VERSION 5.8 ;
BUSBITCHARS "[]" ;
DIVIDERCHAR "/" ;
UNITS
    DATABASE MICRONS 1000 ;
END UNITS

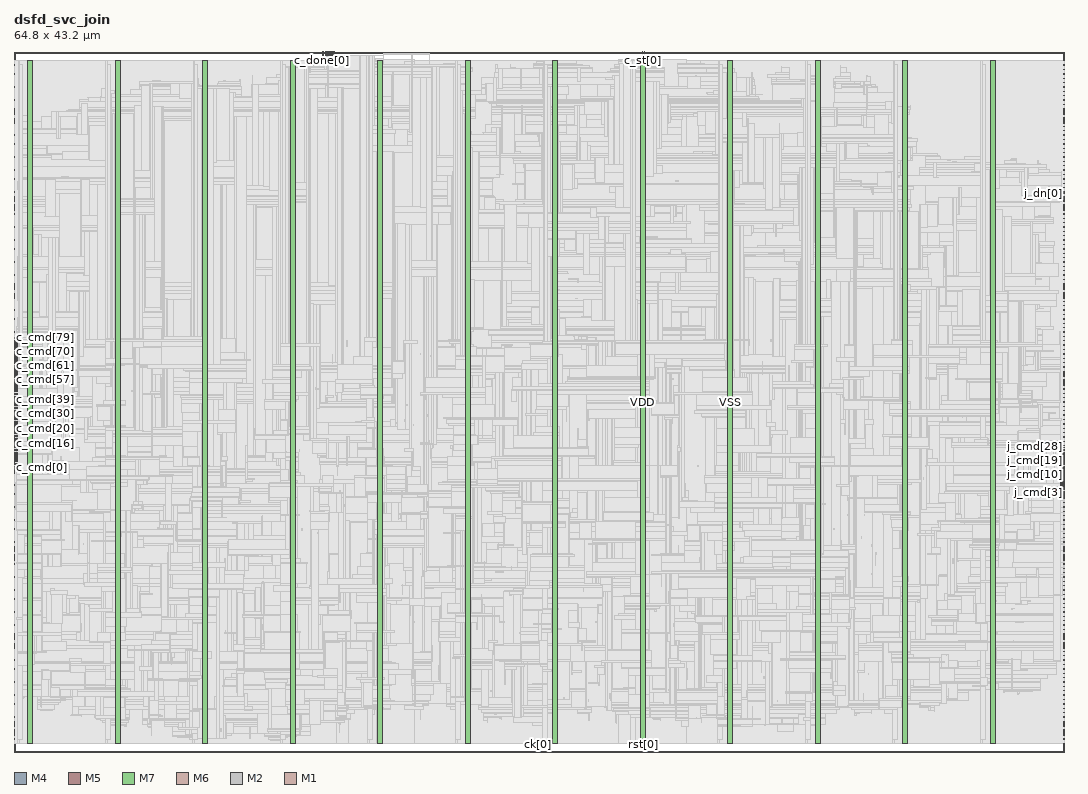
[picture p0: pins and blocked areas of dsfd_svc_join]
MACRO dsfd_svc_join
  FOREIGN dsfd_svc_join 0 0 ;
  CLASS BLOCK ;
  SIZE 64.8 BY 43.2 ;
  PIN c_cmd[0]
    DIRECTION INPUT ;
    USE SIGNAL ;
    PORT
      LAYER M4 ;
        RECT  0 17.52 0.192 17.544 ;
    END
  END c_cmd[0]
  PIN c_cmd[10]
    DIRECTION INPUT ;
    USE SIGNAL ;
    PORT
      LAYER M4 ;
        RECT  0 18.48 0.192 18.504 ;
    END
  END c_cmd[10]
  PIN c_cmd[11]
    DIRECTION INPUT ;
    USE SIGNAL ;
    PORT
      LAYER M4 ;
        RECT  0 18.576 0.192 18.6 ;
    END
  END c_cmd[11]
  PIN c_cmd[12]
    DIRECTION INPUT ;
    USE SIGNAL ;
    PORT
      LAYER M4 ;
        RECT  0 18.672 0.192 18.696 ;
    END
  END c_cmd[12]
  PIN c_cmd[13]
    DIRECTION INPUT ;
    USE SIGNAL ;
    PORT
      LAYER M4 ;
        RECT  0 18.768 0.192 18.792 ;
    END
  END c_cmd[13]
  PIN c_cmd[14]
    DIRECTION INPUT ;
    USE SIGNAL ;
    PORT
      LAYER M4 ;
        RECT  0 18.864 0.192 18.888 ;
    END
  END c_cmd[14]
  PIN c_cmd[15]
    DIRECTION INPUT ;
    USE SIGNAL ;
    PORT
      LAYER M4 ;
        RECT  0 18.96 0.192 18.984 ;
    END
  END c_cmd[15]
  PIN c_cmd[16]
    DIRECTION INPUT ;
    USE SIGNAL ;
    PORT
      LAYER M4 ;
        RECT  0 19.056 0.192 19.08 ;
    END
  END c_cmd[16]
  PIN c_cmd[17]
    DIRECTION INPUT ;
    USE SIGNAL ;
    PORT
      LAYER M4 ;
        RECT  0 19.152 0.192 19.176 ;
    END
  END c_cmd[17]
  PIN c_cmd[18]
    DIRECTION INPUT ;
    USE SIGNAL ;
    PORT
      LAYER M4 ;
        RECT  0 19.248 0.192 19.272 ;
    END
  END c_cmd[18]
  PIN c_cmd[19]
    DIRECTION INPUT ;
    USE SIGNAL ;
    PORT
      LAYER M4 ;
        RECT  0 19.344 0.192 19.368 ;
    END
  END c_cmd[19]
  PIN c_cmd[1]
    DIRECTION INPUT ;
    USE SIGNAL ;
    PORT
      LAYER M4 ;
        RECT  0 17.616 0.192 17.64 ;
    END
  END c_cmd[1]
  PIN c_cmd[20]
    DIRECTION INPUT ;
    USE SIGNAL ;
    PORT
      LAYER M4 ;
        RECT  0 19.44 0.192 19.464 ;
    END
  END c_cmd[20]
  PIN c_cmd[21]
    DIRECTION INPUT ;
    USE SIGNAL ;
    PORT
      LAYER M4 ;
        RECT  0 19.536 0.192 19.56 ;
    END
  END c_cmd[21]
  PIN c_cmd[22]
    DIRECTION INPUT ;
    USE SIGNAL ;
    PORT
      LAYER M4 ;
        RECT  0 19.632 0.192 19.656 ;
    END
  END c_cmd[22]
  PIN c_cmd[23]
    DIRECTION INPUT ;
    USE SIGNAL ;
    PORT
      LAYER M4 ;
        RECT  0 19.728 0.192 19.752 ;
    END
  END c_cmd[23]
  PIN c_cmd[24]
    DIRECTION INPUT ;
    USE SIGNAL ;
    PORT
      LAYER M4 ;
        RECT  0 19.824 0.192 19.848 ;
    END
  END c_cmd[24]
  PIN c_cmd[25]
    DIRECTION INPUT ;
    USE SIGNAL ;
    PORT
      LAYER M4 ;
        RECT  0 19.92 0.192 19.944 ;
    END
  END c_cmd[25]
  PIN c_cmd[26]
    DIRECTION INPUT ;
    USE SIGNAL ;
    PORT
      LAYER M4 ;
        RECT  0 20.016 0.192 20.04 ;
    END
  END c_cmd[26]
  PIN c_cmd[27]
    DIRECTION INPUT ;
    USE SIGNAL ;
    PORT
      LAYER M4 ;
        RECT  0 20.112 0.192 20.136 ;
    END
  END c_cmd[27]
  PIN c_cmd[28]
    DIRECTION INPUT ;
    USE SIGNAL ;
    PORT
      LAYER M4 ;
        RECT  0 20.208 0.192 20.232 ;
    END
  END c_cmd[28]
  PIN c_cmd[29]
    DIRECTION INPUT ;
    USE SIGNAL ;
    PORT
      LAYER M4 ;
        RECT  0 20.304 0.192 20.328 ;
    END
  END c_cmd[29]
  PIN c_cmd[2]
    DIRECTION INPUT ;
    USE SIGNAL ;
    PORT
      LAYER M4 ;
        RECT  0 17.712 0.192 17.736 ;
    END
  END c_cmd[2]
  PIN c_cmd[30]
    DIRECTION INPUT ;
    USE SIGNAL ;
    PORT
      LAYER M4 ;
        RECT  0 20.4 0.192 20.424 ;
    END
  END c_cmd[30]
  PIN c_cmd[31]
    DIRECTION INPUT ;
    USE SIGNAL ;
    PORT
      LAYER M4 ;
        RECT  0 20.496 0.192 20.52 ;
    END
  END c_cmd[31]
  PIN c_cmd[32]
    DIRECTION INPUT ;
    USE SIGNAL ;
    PORT
      LAYER M4 ;
        RECT  0 20.592 0.192 20.616 ;
    END
  END c_cmd[32]
  PIN c_cmd[33]
    DIRECTION INPUT ;
    USE SIGNAL ;
    PORT
      LAYER M4 ;
        RECT  0 20.688 0.192 20.712 ;
    END
  END c_cmd[33]
  PIN c_cmd[34]
    DIRECTION INPUT ;
    USE SIGNAL ;
    PORT
      LAYER M4 ;
        RECT  0 20.784 0.192 20.808 ;
    END
  END c_cmd[34]
  PIN c_cmd[35]
    DIRECTION INPUT ;
    USE SIGNAL ;
    PORT
      LAYER M4 ;
        RECT  0 20.88 0.192 20.904 ;
    END
  END c_cmd[35]
  PIN c_cmd[36]
    DIRECTION INPUT ;
    USE SIGNAL ;
    PORT
      LAYER M4 ;
        RECT  0 20.976 0.192 21 ;
    END
  END c_cmd[36]
  PIN c_cmd[37]
    DIRECTION INPUT ;
    USE SIGNAL ;
    PORT
      LAYER M4 ;
        RECT  0 21.072 0.192 21.096 ;
    END
  END c_cmd[37]
  PIN c_cmd[38]
    DIRECTION INPUT ;
    USE SIGNAL ;
    PORT
      LAYER M4 ;
        RECT  0 21.168 0.192 21.192 ;
    END
  END c_cmd[38]
  PIN c_cmd[39]
    DIRECTION INPUT ;
    USE SIGNAL ;
    PORT
      LAYER M4 ;
        RECT  0 21.264 0.192 21.288 ;
    END
  END c_cmd[39]
  PIN c_cmd[3]
    DIRECTION INPUT ;
    USE SIGNAL ;
    PORT
      LAYER M4 ;
        RECT  0 17.808 0.192 17.832 ;
    END
  END c_cmd[3]
  PIN c_cmd[40]
    DIRECTION INPUT ;
    USE SIGNAL ;
    PORT
      LAYER M4 ;
        RECT  0 21.36 0.192 21.384 ;
    END
  END c_cmd[40]
  PIN c_cmd[41]
    DIRECTION INPUT ;
    USE SIGNAL ;
    PORT
      LAYER M4 ;
        RECT  0 21.456 0.192 21.48 ;
    END
  END c_cmd[41]
  PIN c_cmd[42]
    DIRECTION INPUT ;
    USE SIGNAL ;
    PORT
      LAYER M4 ;
        RECT  0 21.552 0.192 21.576 ;
    END
  END c_cmd[42]
  PIN c_cmd[43]
    DIRECTION INPUT ;
    USE SIGNAL ;
    PORT
      LAYER M4 ;
        RECT  0 21.648 0.192 21.672 ;
    END
  END c_cmd[43]
  PIN c_cmd[44]
    DIRECTION INPUT ;
    USE SIGNAL ;
    PORT
      LAYER M4 ;
        RECT  0 21.744 0.192 21.768 ;
    END
  END c_cmd[44]
  PIN c_cmd[45]
    DIRECTION INPUT ;
    USE SIGNAL ;
    PORT
      LAYER M4 ;
        RECT  0 21.84 0.192 21.864 ;
    END
  END c_cmd[45]
  PIN c_cmd[46]
    DIRECTION INPUT ;
    USE SIGNAL ;
    PORT
      LAYER M4 ;
        RECT  0 21.936 0.192 21.96 ;
    END
  END c_cmd[46]
  PIN c_cmd[47]
    DIRECTION INPUT ;
    USE SIGNAL ;
    PORT
      LAYER M4 ;
        RECT  0 22.032 0.192 22.056 ;
    END
  END c_cmd[47]
  PIN c_cmd[48]
    DIRECTION INPUT ;
    USE SIGNAL ;
    PORT
      LAYER M4 ;
        RECT  0 22.128 0.192 22.152 ;
    END
  END c_cmd[48]
  PIN c_cmd[49]
    DIRECTION INPUT ;
    USE SIGNAL ;
    PORT
      LAYER M4 ;
        RECT  0 22.224 0.192 22.248 ;
    END
  END c_cmd[49]
  PIN c_cmd[4]
    DIRECTION INPUT ;
    USE SIGNAL ;
    PORT
      LAYER M4 ;
        RECT  0 17.904 0.192 17.928 ;
    END
  END c_cmd[4]
  PIN c_cmd[50]
    DIRECTION INPUT ;
    USE SIGNAL ;
    PORT
      LAYER M4 ;
        RECT  0 22.32 0.192 22.344 ;
    END
  END c_cmd[50]
  PIN c_cmd[51]
    DIRECTION INPUT ;
    USE SIGNAL ;
    PORT
      LAYER M4 ;
        RECT  0 22.416 0.192 22.44 ;
    END
  END c_cmd[51]
  PIN c_cmd[52]
    DIRECTION INPUT ;
    USE SIGNAL ;
    PORT
      LAYER M4 ;
        RECT  0 22.512 0.192 22.536 ;
    END
  END c_cmd[52]
  PIN c_cmd[53]
    DIRECTION INPUT ;
    USE SIGNAL ;
    PORT
      LAYER M4 ;
        RECT  0 22.608 0.192 22.632 ;
    END
  END c_cmd[53]
  PIN c_cmd[54]
    DIRECTION INPUT ;
    USE SIGNAL ;
    PORT
      LAYER M4 ;
        RECT  0 22.704 0.192 22.728 ;
    END
  END c_cmd[54]
  PIN c_cmd[55]
    DIRECTION INPUT ;
    USE SIGNAL ;
    PORT
      LAYER M4 ;
        RECT  0 22.8 0.192 22.824 ;
    END
  END c_cmd[55]
  PIN c_cmd[56]
    DIRECTION INPUT ;
    USE SIGNAL ;
    PORT
      LAYER M4 ;
        RECT  0 22.896 0.192 22.92 ;
    END
  END c_cmd[56]
  PIN c_cmd[57]
    DIRECTION INPUT ;
    USE SIGNAL ;
    PORT
      LAYER M4 ;
        RECT  0 22.992 0.192 23.016 ;
    END
  END c_cmd[57]
  PIN c_cmd[58]
    DIRECTION INPUT ;
    USE SIGNAL ;
    PORT
      LAYER M4 ;
        RECT  0 23.088 0.192 23.112 ;
    END
  END c_cmd[58]
  PIN c_cmd[59]
    DIRECTION INPUT ;
    USE SIGNAL ;
    PORT
      LAYER M4 ;
        RECT  0 23.184 0.192 23.208 ;
    END
  END c_cmd[59]
  PIN c_cmd[5]
    DIRECTION INPUT ;
    USE SIGNAL ;
    PORT
      LAYER M4 ;
        RECT  0 18 0.192 18.024 ;
    END
  END c_cmd[5]
  PIN c_cmd[60]
    DIRECTION INPUT ;
    USE SIGNAL ;
    PORT
      LAYER M4 ;
        RECT  0 23.28 0.192 23.304 ;
    END
  END c_cmd[60]
  PIN c_cmd[61]
    DIRECTION INPUT ;
    USE SIGNAL ;
    PORT
      LAYER M4 ;
        RECT  0 23.376 0.192 23.4 ;
    END
  END c_cmd[61]
  PIN c_cmd[62]
    DIRECTION INPUT ;
    USE SIGNAL ;
    PORT
      LAYER M4 ;
        RECT  0 23.472 0.192 23.496 ;
    END
  END c_cmd[62]
  PIN c_cmd[63]
    DIRECTION INPUT ;
    USE SIGNAL ;
    PORT
      LAYER M4 ;
        RECT  0 23.568 0.192 23.592 ;
    END
  END c_cmd[63]
  PIN c_cmd[64]
    DIRECTION INPUT ;
    USE SIGNAL ;
    PORT
      LAYER M4 ;
        RECT  0 23.664 0.192 23.688 ;
    END
  END c_cmd[64]
  PIN c_cmd[65]
    DIRECTION INPUT ;
    USE SIGNAL ;
    PORT
      LAYER M4 ;
        RECT  0 23.76 0.192 23.784 ;
    END
  END c_cmd[65]
  PIN c_cmd[66]
    DIRECTION INPUT ;
    USE SIGNAL ;
    PORT
      LAYER M4 ;
        RECT  0 23.856 0.192 23.88 ;
    END
  END c_cmd[66]
  PIN c_cmd[67]
    DIRECTION INPUT ;
    USE SIGNAL ;
    PORT
      LAYER M4 ;
        RECT  0 23.952 0.192 23.976 ;
    END
  END c_cmd[67]
  PIN c_cmd[68]
    DIRECTION INPUT ;
    USE SIGNAL ;
    PORT
      LAYER M4 ;
        RECT  0 24.048 0.192 24.072 ;
    END
  END c_cmd[68]
  PIN c_cmd[69]
    DIRECTION INPUT ;
    USE SIGNAL ;
    PORT
      LAYER M4 ;
        RECT  0 24.144 0.192 24.168 ;
    END
  END c_cmd[69]
  PIN c_cmd[6]
    DIRECTION INPUT ;
    USE SIGNAL ;
    PORT
      LAYER M4 ;
        RECT  0 18.096 0.192 18.12 ;
    END
  END c_cmd[6]
  PIN c_cmd[70]
    DIRECTION INPUT ;
    USE SIGNAL ;
    PORT
      LAYER M4 ;
        RECT  0 24.24 0.192 24.264 ;
    END
  END c_cmd[70]
  PIN c_cmd[71]
    DIRECTION INPUT ;
    USE SIGNAL ;
    PORT
      LAYER M4 ;
        RECT  0 24.336 0.192 24.36 ;
    END
  END c_cmd[71]
  PIN c_cmd[72]
    DIRECTION INPUT ;
    USE SIGNAL ;
    PORT
      LAYER M4 ;
        RECT  0 24.432 0.192 24.456 ;
    END
  END c_cmd[72]
  PIN c_cmd[73]
    DIRECTION INPUT ;
    USE SIGNAL ;
    PORT
      LAYER M4 ;
        RECT  0 24.528 0.192 24.552 ;
    END
  END c_cmd[73]
  PIN c_cmd[74]
    DIRECTION INPUT ;
    USE SIGNAL ;
    PORT
      LAYER M4 ;
        RECT  0 24.624 0.192 24.648 ;
    END
  END c_cmd[74]
  PIN c_cmd[75]
    DIRECTION INPUT ;
    USE SIGNAL ;
    PORT
      LAYER M4 ;
        RECT  0 24.72 0.192 24.744 ;
    END
  END c_cmd[75]
  PIN c_cmd[76]
    DIRECTION INPUT ;
    USE SIGNAL ;
    PORT
      LAYER M4 ;
        RECT  0 24.816 0.192 24.84 ;
    END
  END c_cmd[76]
  PIN c_cmd[77]
    DIRECTION INPUT ;
    USE SIGNAL ;
    PORT
      LAYER M4 ;
        RECT  0 24.912 0.192 24.936 ;
    END
  END c_cmd[77]
  PIN c_cmd[78]
    DIRECTION INPUT ;
    USE SIGNAL ;
    PORT
      LAYER M4 ;
        RECT  0 25.008 0.192 25.032 ;
    END
  END c_cmd[78]
  PIN c_cmd[79]
    DIRECTION INPUT ;
    USE SIGNAL ;
    PORT
      LAYER M4 ;
        RECT  0 25.104 0.192 25.128 ;
    END
  END c_cmd[79]
  PIN c_cmd[7]
    DIRECTION INPUT ;
    USE SIGNAL ;
    PORT
      LAYER M4 ;
        RECT  0 18.192 0.192 18.216 ;
    END
  END c_cmd[7]
  PIN c_cmd[80]
    DIRECTION INPUT ;
    USE SIGNAL ;
    PORT
      LAYER M4 ;
        RECT  0 25.2 0.192 25.224 ;
    END
  END c_cmd[80]
  PIN c_cmd[81]
    DIRECTION INPUT ;
    USE SIGNAL ;
    PORT
      LAYER M4 ;
        RECT  0 25.296 0.192 25.32 ;
    END
  END c_cmd[81]
  PIN c_cmd[82]
    DIRECTION INPUT ;
    USE SIGNAL ;
    PORT
      LAYER M4 ;
        RECT  0 25.392 0.192 25.416 ;
    END
  END c_cmd[82]
  PIN c_cmd[83]
    DIRECTION INPUT ;
    USE SIGNAL ;
    PORT
      LAYER M4 ;
        RECT  0 25.488 0.192 25.512 ;
    END
  END c_cmd[83]
  PIN c_cmd[84]
    DIRECTION INPUT ;
    USE SIGNAL ;
    PORT
      LAYER M4 ;
        RECT  0 25.584 0.192 25.608 ;
    END
  END c_cmd[84]
  PIN c_cmd[8]
    DIRECTION INPUT ;
    USE SIGNAL ;
    PORT
      LAYER M4 ;
        RECT  0 18.288 0.192 18.312 ;
    END
  END c_cmd[8]
  PIN c_cmd[9]
    DIRECTION INPUT ;
    USE SIGNAL ;
    PORT
      LAYER M4 ;
        RECT  0 18.384 0.192 18.408 ;
    END
  END c_cmd[9]
  PIN c_done[0]
    DIRECTION OUTPUT ;
    USE SIGNAL ;
    PORT
      LAYER M5 ;
        RECT  19.008 43.008 19.032 43.2 ;
    END
  END c_done[0]
  PIN c_done[1]
    DIRECTION OUTPUT ;
    USE SIGNAL ;
    PORT
      LAYER M5 ;
        RECT  19.104 43.008 19.128 43.2 ;
    END
  END c_done[1]
  PIN c_done[2]
    DIRECTION OUTPUT ;
    USE SIGNAL ;
    PORT
      LAYER M5 ;
        RECT  19.2 43.008 19.224 43.2 ;
    END
  END c_done[2]
  PIN c_done[3]
    DIRECTION OUTPUT ;
    USE SIGNAL ;
    PORT
      LAYER M5 ;
        RECT  19.296 43.008 19.32 43.2 ;
    END
  END c_done[3]
  PIN c_done[4]
    DIRECTION OUTPUT ;
    USE SIGNAL ;
    PORT
      LAYER M5 ;
        RECT  19.392 43.008 19.416 43.2 ;
    END
  END c_done[4]
  PIN c_done[5]
    DIRECTION OUTPUT ;
    USE SIGNAL ;
    PORT
      LAYER M5 ;
        RECT  19.488 43.008 19.512 43.2 ;
    END
  END c_done[5]
  PIN c_done[6]
    DIRECTION OUTPUT ;
    USE SIGNAL ;
    PORT
      LAYER M5 ;
        RECT  19.584 43.008 19.608 43.2 ;
    END
  END c_done[6]
  PIN c_done[7]
    DIRECTION OUTPUT ;
    USE SIGNAL ;
    PORT
      LAYER M5 ;
        RECT  19.68 43.008 19.704 43.2 ;
    END
  END c_done[7]
  PIN c_done[8]
    DIRECTION OUTPUT ;
    USE SIGNAL ;
    PORT
      LAYER M5 ;
        RECT  19.776 43.008 19.8 43.2 ;
    END
  END c_done[8]
  PIN c_st[0]
    DIRECTION OUTPUT ;
    USE SIGNAL ;
    PORT
      LAYER M5 ;
        RECT  38.784 43.008 38.808 43.2 ;
    END
  END c_st[0]
  PIN c_st[1]
    DIRECTION OUTPUT ;
    USE SIGNAL ;
    PORT
      LAYER M5 ;
        RECT  38.88 43.008 38.904 43.2 ;
    END
  END c_st[1]
  PIN ck[0]
    DIRECTION INPUT ;
    USE SIGNAL ;
    PORT
      LAYER M5 ;
        RECT  32.352 0 32.376 0.192 ;
    END
  END ck[0]
  PIN j_cmd[0]
    DIRECTION OUTPUT ;
    USE SIGNAL ;
    PORT
      LAYER M4 ;
        RECT  64.608 15.696 64.8 15.72 ;
    END
  END j_cmd[0]
  PIN j_cmd[10]
    DIRECTION OUTPUT ;
    USE SIGNAL ;
    PORT
      LAYER M4 ;
        RECT  64.608 16.656 64.8 16.68 ;
    END
  END j_cmd[10]
  PIN j_cmd[11]
    DIRECTION OUTPUT ;
    USE SIGNAL ;
    PORT
      LAYER M4 ;
        RECT  64.608 16.752 64.8 16.776 ;
    END
  END j_cmd[11]
  PIN j_cmd[12]
    DIRECTION OUTPUT ;
    USE SIGNAL ;
    PORT
      LAYER M4 ;
        RECT  64.608 16.848 64.8 16.872 ;
    END
  END j_cmd[12]
  PIN j_cmd[13]
    DIRECTION OUTPUT ;
    USE SIGNAL ;
    PORT
      LAYER M4 ;
        RECT  64.608 16.944 64.8 16.968 ;
    END
  END j_cmd[13]
  PIN j_cmd[14]
    DIRECTION OUTPUT ;
    USE SIGNAL ;
    PORT
      LAYER M4 ;
        RECT  64.608 17.04 64.8 17.064 ;
    END
  END j_cmd[14]
  PIN j_cmd[15]
    DIRECTION OUTPUT ;
    USE SIGNAL ;
    PORT
      LAYER M4 ;
        RECT  64.608 17.136 64.8 17.16 ;
    END
  END j_cmd[15]
  PIN j_cmd[16]
    DIRECTION OUTPUT ;
    USE SIGNAL ;
    PORT
      LAYER M4 ;
        RECT  64.608 17.232 64.8 17.256 ;
    END
  END j_cmd[16]
  PIN j_cmd[17]
    DIRECTION OUTPUT ;
    USE SIGNAL ;
    PORT
      LAYER M4 ;
        RECT  64.608 17.328 64.8 17.352 ;
    END
  END j_cmd[17]
  PIN j_cmd[18]
    DIRECTION OUTPUT ;
    USE SIGNAL ;
    PORT
      LAYER M4 ;
        RECT  64.608 17.424 64.8 17.448 ;
    END
  END j_cmd[18]
  PIN j_cmd[19]
    DIRECTION OUTPUT ;
    USE SIGNAL ;
    PORT
      LAYER M4 ;
        RECT  64.608 17.52 64.8 17.544 ;
    END
  END j_cmd[19]
  PIN j_cmd[1]
    DIRECTION OUTPUT ;
    USE SIGNAL ;
    PORT
      LAYER M4 ;
        RECT  64.608 15.792 64.8 15.816 ;
    END
  END j_cmd[1]
  PIN j_cmd[20]
    DIRECTION OUTPUT ;
    USE SIGNAL ;
    PORT
      LAYER M4 ;
        RECT  64.608 17.616 64.8 17.64 ;
    END
  END j_cmd[20]
  PIN j_cmd[21]
    DIRECTION OUTPUT ;
    USE SIGNAL ;
    PORT
      LAYER M4 ;
        RECT  64.608 17.712 64.8 17.736 ;
    END
  END j_cmd[21]
  PIN j_cmd[22]
    DIRECTION OUTPUT ;
    USE SIGNAL ;
    PORT
      LAYER M4 ;
        RECT  64.608 17.808 64.8 17.832 ;
    END
  END j_cmd[22]
  PIN j_cmd[23]
    DIRECTION OUTPUT ;
    USE SIGNAL ;
    PORT
      LAYER M4 ;
        RECT  64.608 17.904 64.8 17.928 ;
    END
  END j_cmd[23]
  PIN j_cmd[24]
    DIRECTION OUTPUT ;
    USE SIGNAL ;
    PORT
      LAYER M4 ;
        RECT  64.608 18 64.8 18.024 ;
    END
  END j_cmd[24]
  PIN j_cmd[25]
    DIRECTION OUTPUT ;
    USE SIGNAL ;
    PORT
      LAYER M4 ;
        RECT  64.608 18.096 64.8 18.12 ;
    END
  END j_cmd[25]
  PIN j_cmd[26]
    DIRECTION OUTPUT ;
    USE SIGNAL ;
    PORT
      LAYER M4 ;
        RECT  64.608 18.192 64.8 18.216 ;
    END
  END j_cmd[26]
  PIN j_cmd[27]
    DIRECTION OUTPUT ;
    USE SIGNAL ;
    PORT
      LAYER M4 ;
        RECT  64.608 18.288 64.8 18.312 ;
    END
  END j_cmd[27]
  PIN j_cmd[28]
    DIRECTION OUTPUT ;
    USE SIGNAL ;
    PORT
      LAYER M4 ;
        RECT  64.608 18.384 64.8 18.408 ;
    END
  END j_cmd[28]
  PIN j_cmd[29]
    DIRECTION OUTPUT ;
    USE SIGNAL ;
    PORT
      LAYER M4 ;
        RECT  64.608 18.48 64.8 18.504 ;
    END
  END j_cmd[29]
  PIN j_cmd[2]
    DIRECTION OUTPUT ;
    USE SIGNAL ;
    PORT
      LAYER M4 ;
        RECT  64.608 15.888 64.8 15.912 ;
    END
  END j_cmd[2]
  PIN j_cmd[30]
    DIRECTION OUTPUT ;
    USE SIGNAL ;
    PORT
      LAYER M4 ;
        RECT  64.608 18.576 64.8 18.6 ;
    END
  END j_cmd[30]
  PIN j_cmd[31]
    DIRECTION OUTPUT ;
    USE SIGNAL ;
    PORT
      LAYER M4 ;
        RECT  64.608 18.672 64.8 18.696 ;
    END
  END j_cmd[31]
  PIN j_cmd[32]
    DIRECTION OUTPUT ;
    USE SIGNAL ;
    PORT
      LAYER M4 ;
        RECT  64.608 18.768 64.8 18.792 ;
    END
  END j_cmd[32]
  PIN j_cmd[3]
    DIRECTION OUTPUT ;
    USE SIGNAL ;
    PORT
      LAYER M4 ;
        RECT  64.608 15.984 64.8 16.008 ;
    END
  END j_cmd[3]
  PIN j_cmd[4]
    DIRECTION OUTPUT ;
    USE SIGNAL ;
    PORT
      LAYER M4 ;
        RECT  64.608 16.08 64.8 16.104 ;
    END
  END j_cmd[4]
  PIN j_cmd[5]
    DIRECTION OUTPUT ;
    USE SIGNAL ;
    PORT
      LAYER M4 ;
        RECT  64.608 16.176 64.8 16.2 ;
    END
  END j_cmd[5]
  PIN j_cmd[6]
    DIRECTION OUTPUT ;
    USE SIGNAL ;
    PORT
      LAYER M4 ;
        RECT  64.608 16.272 64.8 16.296 ;
    END
  END j_cmd[6]
  PIN j_cmd[7]
    DIRECTION OUTPUT ;
    USE SIGNAL ;
    PORT
      LAYER M4 ;
        RECT  64.608 16.368 64.8 16.392 ;
    END
  END j_cmd[7]
  PIN j_cmd[8]
    DIRECTION OUTPUT ;
    USE SIGNAL ;
    PORT
      LAYER M4 ;
        RECT  64.608 16.464 64.8 16.488 ;
    END
  END j_cmd[8]
  PIN j_cmd[9]
    DIRECTION OUTPUT ;
    USE SIGNAL ;
    PORT
      LAYER M4 ;
        RECT  64.608 16.56 64.8 16.584 ;
    END
  END j_cmd[9]
  PIN j_dn[0]
    DIRECTION INPUT ;
    USE SIGNAL ;
    PORT
      LAYER M4 ;
        RECT  64.608 34.464 64.8 34.488 ;
    END
  END j_dn[0]
  PIN j_dn[1]
    DIRECTION INPUT ;
    USE SIGNAL ;
    PORT
      LAYER M4 ;
        RECT  64.608 34.56 64.8 34.584 ;
    END
  END j_dn[1]
  PIN rst[0]
    DIRECTION INPUT ;
    USE SIGNAL ;
    PORT
      LAYER M5 ;
        RECT  38.832 0 38.856 0.192 ;
    END
  END rst[0]
  PIN VDD
    DIRECTION INOUT ;
    USE POWER ;
    PORT
      LAYER M7 ;
        RECT  60.256 0.531 60.544 42.669 ;
        RECT  49.456 0.531 49.744 42.669 ;
        RECT  38.656 0.531 38.944 42.669 ;
        RECT  27.856 0.531 28.144 42.669 ;
        RECT  17.056 0.531 17.344 42.669 ;
        RECT  6.256 0.531 6.544 42.669 ;
      LAYER M6 ;
        RECT  64.768 39.372 64.8 39.66 ;
        RECT  0 39.372 0.032 39.66 ;
        RECT  64.768 33.972 64.8 34.26 ;
        RECT  0 33.972 0.032 34.26 ;
        RECT  64.768 28.572 64.8 28.86 ;
        RECT  0 28.572 0.032 28.86 ;
        RECT  64.768 23.172 64.8 23.46 ;
        RECT  0 23.172 0.032 23.46 ;
        RECT  64.768 17.772 64.8 18.06 ;
        RECT  0 17.772 0.032 18.06 ;
        RECT  64.768 12.372 64.8 12.66 ;
        RECT  0 12.372 0.032 12.66 ;
        RECT  64.768 6.972 64.8 7.26 ;
        RECT  0 6.972 0.032 7.26 ;
        RECT  64.768 1.572 64.8 1.86 ;
        RECT  0 1.572 0.032 1.86 ;
      LAYER M2 ;
        RECT  64.782 42.381 64.8 42.399 ;
        RECT  0 42.381 0.018 42.399 ;
        RECT  64.782 41.841 64.8 41.859 ;
        RECT  0 41.841 0.018 41.859 ;
        RECT  64.782 41.301 64.8 41.319 ;
        RECT  0 41.301 0.018 41.319 ;
        RECT  64.782 40.761 64.8 40.779 ;
        RECT  0 40.761 0.018 40.779 ;
        RECT  64.782 40.221 64.8 40.239 ;
        RECT  0 40.221 0.018 40.239 ;
        RECT  64.782 39.681 64.8 39.699 ;
        RECT  0 39.681 0.018 39.699 ;
        RECT  64.782 39.141 64.8 39.159 ;
        RECT  0 39.141 0.018 39.159 ;
        RECT  64.782 38.601 64.8 38.619 ;
        RECT  0 38.601 0.018 38.619 ;
        RECT  64.782 38.061 64.8 38.079 ;
        RECT  0 38.061 0.018 38.079 ;
        RECT  64.782 37.521 64.8 37.539 ;
        RECT  0 37.521 0.018 37.539 ;
        RECT  64.782 36.981 64.8 36.999 ;
        RECT  0 36.981 0.018 36.999 ;
        RECT  64.782 36.441 64.8 36.459 ;
        RECT  0 36.441 0.018 36.459 ;
        RECT  64.782 35.901 64.8 35.919 ;
        RECT  0 35.901 0.018 35.919 ;
        RECT  64.782 35.361 64.8 35.379 ;
        RECT  0 35.361 0.018 35.379 ;
        RECT  64.782 34.821 64.8 34.839 ;
        RECT  0 34.821 0.018 34.839 ;
        RECT  64.782 34.281 64.8 34.299 ;
        RECT  0 34.281 0.018 34.299 ;
        RECT  64.782 33.741 64.8 33.759 ;
        RECT  0 33.741 0.018 33.759 ;
        RECT  64.782 33.201 64.8 33.219 ;
        RECT  0 33.201 0.018 33.219 ;
        RECT  64.782 32.661 64.8 32.679 ;
        RECT  0 32.661 0.018 32.679 ;
        RECT  64.782 32.121 64.8 32.139 ;
        RECT  0 32.121 0.018 32.139 ;
        RECT  64.782 31.581 64.8 31.599 ;
        RECT  0 31.581 0.018 31.599 ;
        RECT  64.782 31.041 64.8 31.059 ;
        RECT  0 31.041 0.018 31.059 ;
        RECT  64.782 30.501 64.8 30.519 ;
        RECT  0 30.501 0.018 30.519 ;
        RECT  64.782 29.961 64.8 29.979 ;
        RECT  0 29.961 0.018 29.979 ;
        RECT  64.782 29.421 64.8 29.439 ;
        RECT  0 29.421 0.018 29.439 ;
        RECT  64.782 28.881 64.8 28.899 ;
        RECT  0 28.881 0.018 28.899 ;
        RECT  64.782 28.341 64.8 28.359 ;
        RECT  0 28.341 0.018 28.359 ;
        RECT  64.782 27.801 64.8 27.819 ;
        RECT  0 27.801 0.018 27.819 ;
        RECT  64.782 27.261 64.8 27.279 ;
        RECT  0 27.261 0.018 27.279 ;
        RECT  64.782 26.721 64.8 26.739 ;
        RECT  0 26.721 0.018 26.739 ;
        RECT  64.782 26.181 64.8 26.199 ;
        RECT  0 26.181 0.018 26.199 ;
        RECT  64.782 25.641 64.8 25.659 ;
        RECT  0 25.641 0.018 25.659 ;
        RECT  64.782 25.101 64.8 25.119 ;
        RECT  0 25.101 0.018 25.119 ;
        RECT  64.782 24.561 64.8 24.579 ;
        RECT  0 24.561 0.018 24.579 ;
        RECT  64.782 24.021 64.8 24.039 ;
        RECT  0 24.021 0.018 24.039 ;
        RECT  64.782 23.481 64.8 23.499 ;
        RECT  0 23.481 0.018 23.499 ;
        RECT  64.782 22.941 64.8 22.959 ;
        RECT  0 22.941 0.018 22.959 ;
        RECT  64.782 22.401 64.8 22.419 ;
        RECT  0 22.401 0.018 22.419 ;
        RECT  64.782 21.861 64.8 21.879 ;
        RECT  0 21.861 0.018 21.879 ;
        RECT  64.782 21.321 64.8 21.339 ;
        RECT  0 21.321 0.018 21.339 ;
        RECT  64.782 20.781 64.8 20.799 ;
        RECT  0 20.781 0.018 20.799 ;
        RECT  64.782 20.241 64.8 20.259 ;
        RECT  0 20.241 0.018 20.259 ;
        RECT  64.782 19.701 64.8 19.719 ;
        RECT  0 19.701 0.018 19.719 ;
        RECT  64.782 19.161 64.8 19.179 ;
        RECT  0 19.161 0.018 19.179 ;
        RECT  64.782 18.621 64.8 18.639 ;
        RECT  0 18.621 0.018 18.639 ;
        RECT  64.782 18.081 64.8 18.099 ;
        RECT  0 18.081 0.018 18.099 ;
        RECT  64.782 17.541 64.8 17.559 ;
        RECT  0 17.541 0.018 17.559 ;
        RECT  64.782 17.001 64.8 17.019 ;
        RECT  0 17.001 0.018 17.019 ;
        RECT  64.782 16.461 64.8 16.479 ;
        RECT  0 16.461 0.018 16.479 ;
        RECT  64.782 15.921 64.8 15.939 ;
        RECT  0 15.921 0.018 15.939 ;
        RECT  64.782 15.381 64.8 15.399 ;
        RECT  0 15.381 0.018 15.399 ;
        RECT  64.782 14.841 64.8 14.859 ;
        RECT  0 14.841 0.018 14.859 ;
        RECT  64.782 14.301 64.8 14.319 ;
        RECT  0 14.301 0.018 14.319 ;
        RECT  64.782 13.761 64.8 13.779 ;
        RECT  0 13.761 0.018 13.779 ;
        RECT  64.782 13.221 64.8 13.239 ;
        RECT  0 13.221 0.018 13.239 ;
        RECT  64.782 12.681 64.8 12.699 ;
        RECT  0 12.681 0.018 12.699 ;
        RECT  64.782 12.141 64.8 12.159 ;
        RECT  0 12.141 0.018 12.159 ;
        RECT  64.782 11.601 64.8 11.619 ;
        RECT  0 11.601 0.018 11.619 ;
        RECT  64.782 11.061 64.8 11.079 ;
        RECT  0 11.061 0.018 11.079 ;
        RECT  64.782 10.521 64.8 10.539 ;
        RECT  0 10.521 0.018 10.539 ;
        RECT  64.782 9.981 64.8 9.999 ;
        RECT  0 9.981 0.018 9.999 ;
        RECT  64.782 9.441 64.8 9.459 ;
        RECT  0 9.441 0.018 9.459 ;
        RECT  64.782 8.901 64.8 8.919 ;
        RECT  0 8.901 0.018 8.919 ;
        RECT  64.782 8.361 64.8 8.379 ;
        RECT  0 8.361 0.018 8.379 ;
        RECT  64.782 7.821 64.8 7.839 ;
        RECT  0 7.821 0.018 7.839 ;
        RECT  64.782 7.281 64.8 7.299 ;
        RECT  0 7.281 0.018 7.299 ;
        RECT  64.782 6.741 64.8 6.759 ;
        RECT  0 6.741 0.018 6.759 ;
        RECT  64.782 6.201 64.8 6.219 ;
        RECT  0 6.201 0.018 6.219 ;
        RECT  64.782 5.661 64.8 5.679 ;
        RECT  0 5.661 0.018 5.679 ;
        RECT  64.782 5.121 64.8 5.139 ;
        RECT  0 5.121 0.018 5.139 ;
        RECT  64.782 4.581 64.8 4.599 ;
        RECT  0 4.581 0.018 4.599 ;
        RECT  64.782 4.041 64.8 4.059 ;
        RECT  0 4.041 0.018 4.059 ;
        RECT  64.782 3.501 64.8 3.519 ;
        RECT  0 3.501 0.018 3.519 ;
        RECT  64.782 2.961 64.8 2.979 ;
        RECT  0 2.961 0.018 2.979 ;
        RECT  64.782 2.421 64.8 2.439 ;
        RECT  0 2.421 0.018 2.439 ;
        RECT  64.782 1.881 64.8 1.899 ;
        RECT  0 1.881 0.018 1.899 ;
        RECT  64.782 1.341 64.8 1.359 ;
        RECT  0 1.341 0.018 1.359 ;
        RECT  64.782 0.801 64.8 0.819 ;
        RECT  0 0.801 0.018 0.819 ;
      LAYER M1 ;
        RECT  64.782 42.381 64.8 42.399 ;
        RECT  0 42.381 0.018 42.399 ;
        RECT  64.782 41.841 64.8 41.859 ;
        RECT  0 41.841 0.018 41.859 ;
        RECT  64.782 41.301 64.8 41.319 ;
        RECT  0 41.301 0.018 41.319 ;
        RECT  64.782 40.761 64.8 40.779 ;
        RECT  0 40.761 0.018 40.779 ;
        RECT  64.782 40.221 64.8 40.239 ;
        RECT  0 40.221 0.018 40.239 ;
        RECT  64.782 39.681 64.8 39.699 ;
        RECT  0 39.681 0.018 39.699 ;
        RECT  64.782 39.141 64.8 39.159 ;
        RECT  0 39.141 0.018 39.159 ;
        RECT  64.782 38.601 64.8 38.619 ;
        RECT  0 38.601 0.018 38.619 ;
        RECT  64.782 38.061 64.8 38.079 ;
        RECT  0 38.061 0.018 38.079 ;
        RECT  64.782 37.521 64.8 37.539 ;
        RECT  0 37.521 0.018 37.539 ;
        RECT  64.782 36.981 64.8 36.999 ;
        RECT  0 36.981 0.018 36.999 ;
        RECT  64.782 36.441 64.8 36.459 ;
        RECT  0 36.441 0.018 36.459 ;
        RECT  64.782 35.901 64.8 35.919 ;
        RECT  0 35.901 0.018 35.919 ;
        RECT  64.782 35.361 64.8 35.379 ;
        RECT  0 35.361 0.018 35.379 ;
        RECT  64.782 34.821 64.8 34.839 ;
        RECT  0 34.821 0.018 34.839 ;
        RECT  64.782 34.281 64.8 34.299 ;
        RECT  0 34.281 0.018 34.299 ;
        RECT  64.782 33.741 64.8 33.759 ;
        RECT  0 33.741 0.018 33.759 ;
        RECT  64.782 33.201 64.8 33.219 ;
        RECT  0 33.201 0.018 33.219 ;
        RECT  64.782 32.661 64.8 32.679 ;
        RECT  0 32.661 0.018 32.679 ;
        RECT  64.782 32.121 64.8 32.139 ;
        RECT  0 32.121 0.018 32.139 ;
        RECT  64.782 31.581 64.8 31.599 ;
        RECT  0 31.581 0.018 31.599 ;
        RECT  64.782 31.041 64.8 31.059 ;
        RECT  0 31.041 0.018 31.059 ;
        RECT  64.782 30.501 64.8 30.519 ;
        RECT  0 30.501 0.018 30.519 ;
        RECT  64.782 29.961 64.8 29.979 ;
        RECT  0 29.961 0.018 29.979 ;
        RECT  64.782 29.421 64.8 29.439 ;
        RECT  0 29.421 0.018 29.439 ;
        RECT  64.782 28.881 64.8 28.899 ;
        RECT  0 28.881 0.018 28.899 ;
        RECT  64.782 28.341 64.8 28.359 ;
        RECT  0 28.341 0.018 28.359 ;
        RECT  64.782 27.801 64.8 27.819 ;
        RECT  0 27.801 0.018 27.819 ;
        RECT  64.782 27.261 64.8 27.279 ;
        RECT  0 27.261 0.018 27.279 ;
        RECT  64.782 26.721 64.8 26.739 ;
        RECT  0 26.721 0.018 26.739 ;
        RECT  64.782 26.181 64.8 26.199 ;
        RECT  0 26.181 0.018 26.199 ;
        RECT  64.782 25.641 64.8 25.659 ;
        RECT  0 25.641 0.018 25.659 ;
        RECT  64.782 25.101 64.8 25.119 ;
        RECT  0 25.101 0.018 25.119 ;
        RECT  64.782 24.561 64.8 24.579 ;
        RECT  0 24.561 0.018 24.579 ;
        RECT  64.782 24.021 64.8 24.039 ;
        RECT  0 24.021 0.018 24.039 ;
        RECT  64.782 23.481 64.8 23.499 ;
        RECT  0 23.481 0.018 23.499 ;
        RECT  64.782 22.941 64.8 22.959 ;
        RECT  0 22.941 0.018 22.959 ;
        RECT  64.782 22.401 64.8 22.419 ;
        RECT  0 22.401 0.018 22.419 ;
        RECT  64.782 21.861 64.8 21.879 ;
        RECT  0 21.861 0.018 21.879 ;
        RECT  64.782 21.321 64.8 21.339 ;
        RECT  0 21.321 0.018 21.339 ;
        RECT  64.782 20.781 64.8 20.799 ;
        RECT  0 20.781 0.018 20.799 ;
        RECT  64.782 20.241 64.8 20.259 ;
        RECT  0 20.241 0.018 20.259 ;
        RECT  64.782 19.701 64.8 19.719 ;
        RECT  0 19.701 0.018 19.719 ;
        RECT  64.782 19.161 64.8 19.179 ;
        RECT  0 19.161 0.018 19.179 ;
        RECT  64.782 18.621 64.8 18.639 ;
        RECT  0 18.621 0.018 18.639 ;
        RECT  64.782 18.081 64.8 18.099 ;
        RECT  0 18.081 0.018 18.099 ;
        RECT  64.782 17.541 64.8 17.559 ;
        RECT  0 17.541 0.018 17.559 ;
        RECT  64.782 17.001 64.8 17.019 ;
        RECT  0 17.001 0.018 17.019 ;
        RECT  64.782 16.461 64.8 16.479 ;
        RECT  0 16.461 0.018 16.479 ;
        RECT  64.782 15.921 64.8 15.939 ;
        RECT  0 15.921 0.018 15.939 ;
        RECT  64.782 15.381 64.8 15.399 ;
        RECT  0 15.381 0.018 15.399 ;
        RECT  64.782 14.841 64.8 14.859 ;
        RECT  0 14.841 0.018 14.859 ;
        RECT  64.782 14.301 64.8 14.319 ;
        RECT  0 14.301 0.018 14.319 ;
        RECT  64.782 13.761 64.8 13.779 ;
        RECT  0 13.761 0.018 13.779 ;
        RECT  64.782 13.221 64.8 13.239 ;
        RECT  0 13.221 0.018 13.239 ;
        RECT  64.782 12.681 64.8 12.699 ;
        RECT  0 12.681 0.018 12.699 ;
        RECT  64.782 12.141 64.8 12.159 ;
        RECT  0 12.141 0.018 12.159 ;
        RECT  64.782 11.601 64.8 11.619 ;
        RECT  0 11.601 0.018 11.619 ;
        RECT  64.782 11.061 64.8 11.079 ;
        RECT  0 11.061 0.018 11.079 ;
        RECT  64.782 10.521 64.8 10.539 ;
        RECT  0 10.521 0.018 10.539 ;
        RECT  64.782 9.981 64.8 9.999 ;
        RECT  0 9.981 0.018 9.999 ;
        RECT  64.782 9.441 64.8 9.459 ;
        RECT  0 9.441 0.018 9.459 ;
        RECT  64.782 8.901 64.8 8.919 ;
        RECT  0 8.901 0.018 8.919 ;
        RECT  64.782 8.361 64.8 8.379 ;
        RECT  0 8.361 0.018 8.379 ;
        RECT  64.782 7.821 64.8 7.839 ;
        RECT  0 7.821 0.018 7.839 ;
        RECT  64.782 7.281 64.8 7.299 ;
        RECT  0 7.281 0.018 7.299 ;
        RECT  64.782 6.741 64.8 6.759 ;
        RECT  0 6.741 0.018 6.759 ;
        RECT  64.782 6.201 64.8 6.219 ;
        RECT  0 6.201 0.018 6.219 ;
        RECT  64.782 5.661 64.8 5.679 ;
        RECT  0 5.661 0.018 5.679 ;
        RECT  64.782 5.121 64.8 5.139 ;
        RECT  0 5.121 0.018 5.139 ;
        RECT  64.782 4.581 64.8 4.599 ;
        RECT  0 4.581 0.018 4.599 ;
        RECT  64.782 4.041 64.8 4.059 ;
        RECT  0 4.041 0.018 4.059 ;
        RECT  64.782 3.501 64.8 3.519 ;
        RECT  0 3.501 0.018 3.519 ;
        RECT  64.782 2.961 64.8 2.979 ;
        RECT  0 2.961 0.018 2.979 ;
        RECT  64.782 2.421 64.8 2.439 ;
        RECT  0 2.421 0.018 2.439 ;
        RECT  64.782 1.881 64.8 1.899 ;
        RECT  0 1.881 0.018 1.899 ;
        RECT  64.782 1.341 64.8 1.359 ;
        RECT  0 1.341 0.018 1.359 ;
        RECT  64.782 0.801 64.8 0.819 ;
        RECT  0 0.801 0.018 0.819 ;
    END
  END VDD
  PIN VSS
    DIRECTION INOUT ;
    USE GROUND ;
    PORT
      LAYER M7 ;
        RECT  54.856 0.531 55.144 42.669 ;
        RECT  44.056 0.531 44.344 42.669 ;
        RECT  33.256 0.531 33.544 42.669 ;
        RECT  22.456 0.531 22.744 42.669 ;
        RECT  11.656 0.531 11.944 42.669 ;
        RECT  0.856 0.531 1.144 42.669 ;
      LAYER M6 ;
        RECT  64.768 38.796 64.8 39.084 ;
        RECT  0 38.796 0.032 39.084 ;
        RECT  64.768 33.396 64.8 33.684 ;
        RECT  0 33.396 0.032 33.684 ;
        RECT  64.768 27.996 64.8 28.284 ;
        RECT  0 27.996 0.032 28.284 ;
        RECT  64.768 22.596 64.8 22.884 ;
        RECT  0 22.596 0.032 22.884 ;
        RECT  64.768 17.196 64.8 17.484 ;
        RECT  0 17.196 0.032 17.484 ;
        RECT  64.768 11.796 64.8 12.084 ;
        RECT  0 11.796 0.032 12.084 ;
        RECT  64.768 6.396 64.8 6.684 ;
        RECT  0 6.396 0.032 6.684 ;
        RECT  64.768 0.996 64.8 1.284 ;
        RECT  0 0.996 0.032 1.284 ;
      LAYER M2 ;
        RECT  64.782 42.651 64.8 42.669 ;
        RECT  0 42.651 0.018 42.669 ;
        RECT  64.782 42.111 64.8 42.129 ;
        RECT  0 42.111 0.018 42.129 ;
        RECT  64.782 41.571 64.8 41.589 ;
        RECT  0 41.571 0.018 41.589 ;
        RECT  64.782 41.031 64.8 41.049 ;
        RECT  0 41.031 0.018 41.049 ;
        RECT  64.782 40.491 64.8 40.509 ;
        RECT  0 40.491 0.018 40.509 ;
        RECT  64.782 39.951 64.8 39.969 ;
        RECT  0 39.951 0.018 39.969 ;
        RECT  64.782 39.411 64.8 39.429 ;
        RECT  0 39.411 0.018 39.429 ;
        RECT  64.782 38.871 64.8 38.889 ;
        RECT  0 38.871 0.018 38.889 ;
        RECT  64.782 38.331 64.8 38.349 ;
        RECT  0 38.331 0.018 38.349 ;
        RECT  64.782 37.791 64.8 37.809 ;
        RECT  0 37.791 0.018 37.809 ;
        RECT  64.782 37.251 64.8 37.269 ;
        RECT  0 37.251 0.018 37.269 ;
        RECT  64.782 36.711 64.8 36.729 ;
        RECT  0 36.711 0.018 36.729 ;
        RECT  64.782 36.171 64.8 36.189 ;
        RECT  0 36.171 0.018 36.189 ;
        RECT  64.782 35.631 64.8 35.649 ;
        RECT  0 35.631 0.018 35.649 ;
        RECT  64.782 35.091 64.8 35.109 ;
        RECT  0 35.091 0.018 35.109 ;
        RECT  64.782 34.551 64.8 34.569 ;
        RECT  0 34.551 0.018 34.569 ;
        RECT  64.782 34.011 64.8 34.029 ;
        RECT  0 34.011 0.018 34.029 ;
        RECT  64.782 33.471 64.8 33.489 ;
        RECT  0 33.471 0.018 33.489 ;
        RECT  64.782 32.931 64.8 32.949 ;
        RECT  0 32.931 0.018 32.949 ;
        RECT  64.782 32.391 64.8 32.409 ;
        RECT  0 32.391 0.018 32.409 ;
        RECT  64.782 31.851 64.8 31.869 ;
        RECT  0 31.851 0.018 31.869 ;
        RECT  64.782 31.311 64.8 31.329 ;
        RECT  0 31.311 0.018 31.329 ;
        RECT  64.782 30.771 64.8 30.789 ;
        RECT  0 30.771 0.018 30.789 ;
        RECT  64.782 30.231 64.8 30.249 ;
        RECT  0 30.231 0.018 30.249 ;
        RECT  64.782 29.691 64.8 29.709 ;
        RECT  0 29.691 0.018 29.709 ;
        RECT  64.782 29.151 64.8 29.169 ;
        RECT  0 29.151 0.018 29.169 ;
        RECT  64.782 28.611 64.8 28.629 ;
        RECT  0 28.611 0.018 28.629 ;
        RECT  64.782 28.071 64.8 28.089 ;
        RECT  0 28.071 0.018 28.089 ;
        RECT  64.782 27.531 64.8 27.549 ;
        RECT  0 27.531 0.018 27.549 ;
        RECT  64.782 26.991 64.8 27.009 ;
        RECT  0 26.991 0.018 27.009 ;
        RECT  64.782 26.451 64.8 26.469 ;
        RECT  0 26.451 0.018 26.469 ;
        RECT  64.782 25.911 64.8 25.929 ;
        RECT  0 25.911 0.018 25.929 ;
        RECT  64.782 25.371 64.8 25.389 ;
        RECT  0 25.371 0.018 25.389 ;
        RECT  64.782 24.831 64.8 24.849 ;
        RECT  0 24.831 0.018 24.849 ;
        RECT  64.782 24.291 64.8 24.309 ;
        RECT  0 24.291 0.018 24.309 ;
        RECT  64.782 23.751 64.8 23.769 ;
        RECT  0 23.751 0.018 23.769 ;
        RECT  64.782 23.211 64.8 23.229 ;
        RECT  0 23.211 0.018 23.229 ;
        RECT  64.782 22.671 64.8 22.689 ;
        RECT  0 22.671 0.018 22.689 ;
        RECT  64.782 22.131 64.8 22.149 ;
        RECT  0 22.131 0.018 22.149 ;
        RECT  64.782 21.591 64.8 21.609 ;
        RECT  0 21.591 0.018 21.609 ;
        RECT  64.782 21.051 64.8 21.069 ;
        RECT  0 21.051 0.018 21.069 ;
        RECT  64.782 20.511 64.8 20.529 ;
        RECT  0 20.511 0.018 20.529 ;
        RECT  64.782 19.971 64.8 19.989 ;
        RECT  0 19.971 0.018 19.989 ;
        RECT  64.782 19.431 64.8 19.449 ;
        RECT  0 19.431 0.018 19.449 ;
        RECT  64.782 18.891 64.8 18.909 ;
        RECT  0 18.891 0.018 18.909 ;
        RECT  64.782 18.351 64.8 18.369 ;
        RECT  0 18.351 0.018 18.369 ;
        RECT  64.782 17.811 64.8 17.829 ;
        RECT  0 17.811 0.018 17.829 ;
        RECT  64.782 17.271 64.8 17.289 ;
        RECT  0 17.271 0.018 17.289 ;
        RECT  64.782 16.731 64.8 16.749 ;
        RECT  0 16.731 0.018 16.749 ;
        RECT  64.782 16.191 64.8 16.209 ;
        RECT  0 16.191 0.018 16.209 ;
        RECT  64.782 15.651 64.8 15.669 ;
        RECT  0 15.651 0.018 15.669 ;
        RECT  64.782 15.111 64.8 15.129 ;
        RECT  0 15.111 0.018 15.129 ;
        RECT  64.782 14.571 64.8 14.589 ;
        RECT  0 14.571 0.018 14.589 ;
        RECT  64.782 14.031 64.8 14.049 ;
        RECT  0 14.031 0.018 14.049 ;
        RECT  64.782 13.491 64.8 13.509 ;
        RECT  0 13.491 0.018 13.509 ;
        RECT  64.782 12.951 64.8 12.969 ;
        RECT  0 12.951 0.018 12.969 ;
        RECT  64.782 12.411 64.8 12.429 ;
        RECT  0 12.411 0.018 12.429 ;
        RECT  64.782 11.871 64.8 11.889 ;
        RECT  0 11.871 0.018 11.889 ;
        RECT  64.782 11.331 64.8 11.349 ;
        RECT  0 11.331 0.018 11.349 ;
        RECT  64.782 10.791 64.8 10.809 ;
        RECT  0 10.791 0.018 10.809 ;
        RECT  64.782 10.251 64.8 10.269 ;
        RECT  0 10.251 0.018 10.269 ;
        RECT  64.782 9.711 64.8 9.729 ;
        RECT  0 9.711 0.018 9.729 ;
        RECT  64.782 9.171 64.8 9.189 ;
        RECT  0 9.171 0.018 9.189 ;
        RECT  64.782 8.631 64.8 8.649 ;
        RECT  0 8.631 0.018 8.649 ;
        RECT  64.782 8.091 64.8 8.109 ;
        RECT  0 8.091 0.018 8.109 ;
        RECT  64.782 7.551 64.8 7.569 ;
        RECT  0 7.551 0.018 7.569 ;
        RECT  64.782 7.011 64.8 7.029 ;
        RECT  0 7.011 0.018 7.029 ;
        RECT  64.782 6.471 64.8 6.489 ;
        RECT  0 6.471 0.018 6.489 ;
        RECT  64.782 5.931 64.8 5.949 ;
        RECT  0 5.931 0.018 5.949 ;
        RECT  64.782 5.391 64.8 5.409 ;
        RECT  0 5.391 0.018 5.409 ;
        RECT  64.782 4.851 64.8 4.869 ;
        RECT  0 4.851 0.018 4.869 ;
        RECT  64.782 4.311 64.8 4.329 ;
        RECT  0 4.311 0.018 4.329 ;
        RECT  64.782 3.771 64.8 3.789 ;
        RECT  0 3.771 0.018 3.789 ;
        RECT  64.782 3.231 64.8 3.249 ;
        RECT  0 3.231 0.018 3.249 ;
        RECT  64.782 2.691 64.8 2.709 ;
        RECT  0 2.691 0.018 2.709 ;
        RECT  64.782 2.151 64.8 2.169 ;
        RECT  0 2.151 0.018 2.169 ;
        RECT  64.782 1.611 64.8 1.629 ;
        RECT  0 1.611 0.018 1.629 ;
        RECT  64.782 1.071 64.8 1.089 ;
        RECT  0 1.071 0.018 1.089 ;
        RECT  64.782 0.531 64.8 0.549 ;
        RECT  0 0.531 0.018 0.549 ;
      LAYER M1 ;
        RECT  64.782 42.651 64.8 42.669 ;
        RECT  0 42.651 0.018 42.669 ;
        RECT  64.782 42.111 64.8 42.129 ;
        RECT  0 42.111 0.018 42.129 ;
        RECT  64.782 41.571 64.8 41.589 ;
        RECT  0 41.571 0.018 41.589 ;
        RECT  64.782 41.031 64.8 41.049 ;
        RECT  0 41.031 0.018 41.049 ;
        RECT  64.782 40.491 64.8 40.509 ;
        RECT  0 40.491 0.018 40.509 ;
        RECT  64.782 39.951 64.8 39.969 ;
        RECT  0 39.951 0.018 39.969 ;
        RECT  64.782 39.411 64.8 39.429 ;
        RECT  0 39.411 0.018 39.429 ;
        RECT  64.782 38.871 64.8 38.889 ;
        RECT  0 38.871 0.018 38.889 ;
        RECT  64.782 38.331 64.8 38.349 ;
        RECT  0 38.331 0.018 38.349 ;
        RECT  64.782 37.791 64.8 37.809 ;
        RECT  0 37.791 0.018 37.809 ;
        RECT  64.782 37.251 64.8 37.269 ;
        RECT  0 37.251 0.018 37.269 ;
        RECT  64.782 36.711 64.8 36.729 ;
        RECT  0 36.711 0.018 36.729 ;
        RECT  64.782 36.171 64.8 36.189 ;
        RECT  0 36.171 0.018 36.189 ;
        RECT  64.782 35.631 64.8 35.649 ;
        RECT  0 35.631 0.018 35.649 ;
        RECT  64.782 35.091 64.8 35.109 ;
        RECT  0 35.091 0.018 35.109 ;
        RECT  64.782 34.551 64.8 34.569 ;
        RECT  0 34.551 0.018 34.569 ;
        RECT  64.782 34.011 64.8 34.029 ;
        RECT  0 34.011 0.018 34.029 ;
        RECT  64.782 33.471 64.8 33.489 ;
        RECT  0 33.471 0.018 33.489 ;
        RECT  64.782 32.931 64.8 32.949 ;
        RECT  0 32.931 0.018 32.949 ;
        RECT  64.782 32.391 64.8 32.409 ;
        RECT  0 32.391 0.018 32.409 ;
        RECT  64.782 31.851 64.8 31.869 ;
        RECT  0 31.851 0.018 31.869 ;
        RECT  64.782 31.311 64.8 31.329 ;
        RECT  0 31.311 0.018 31.329 ;
        RECT  64.782 30.771 64.8 30.789 ;
        RECT  0 30.771 0.018 30.789 ;
        RECT  64.782 30.231 64.8 30.249 ;
        RECT  0 30.231 0.018 30.249 ;
        RECT  64.782 29.691 64.8 29.709 ;
        RECT  0 29.691 0.018 29.709 ;
        RECT  64.782 29.151 64.8 29.169 ;
        RECT  0 29.151 0.018 29.169 ;
        RECT  64.782 28.611 64.8 28.629 ;
        RECT  0 28.611 0.018 28.629 ;
        RECT  64.782 28.071 64.8 28.089 ;
        RECT  0 28.071 0.018 28.089 ;
        RECT  64.782 27.531 64.8 27.549 ;
        RECT  0 27.531 0.018 27.549 ;
        RECT  64.782 26.991 64.8 27.009 ;
        RECT  0 26.991 0.018 27.009 ;
        RECT  64.782 26.451 64.8 26.469 ;
        RECT  0 26.451 0.018 26.469 ;
        RECT  64.782 25.911 64.8 25.929 ;
        RECT  0 25.911 0.018 25.929 ;
        RECT  64.782 25.371 64.8 25.389 ;
        RECT  0 25.371 0.018 25.389 ;
        RECT  64.782 24.831 64.8 24.849 ;
        RECT  0 24.831 0.018 24.849 ;
        RECT  64.782 24.291 64.8 24.309 ;
        RECT  0 24.291 0.018 24.309 ;
        RECT  64.782 23.751 64.8 23.769 ;
        RECT  0 23.751 0.018 23.769 ;
        RECT  64.782 23.211 64.8 23.229 ;
        RECT  0 23.211 0.018 23.229 ;
        RECT  64.782 22.671 64.8 22.689 ;
        RECT  0 22.671 0.018 22.689 ;
        RECT  64.782 22.131 64.8 22.149 ;
        RECT  0 22.131 0.018 22.149 ;
        RECT  64.782 21.591 64.8 21.609 ;
        RECT  0 21.591 0.018 21.609 ;
        RECT  64.782 21.051 64.8 21.069 ;
        RECT  0 21.051 0.018 21.069 ;
        RECT  64.782 20.511 64.8 20.529 ;
        RECT  0 20.511 0.018 20.529 ;
        RECT  64.782 19.971 64.8 19.989 ;
        RECT  0 19.971 0.018 19.989 ;
        RECT  64.782 19.431 64.8 19.449 ;
        RECT  0 19.431 0.018 19.449 ;
        RECT  64.782 18.891 64.8 18.909 ;
        RECT  0 18.891 0.018 18.909 ;
        RECT  64.782 18.351 64.8 18.369 ;
        RECT  0 18.351 0.018 18.369 ;
        RECT  64.782 17.811 64.8 17.829 ;
        RECT  0 17.811 0.018 17.829 ;
        RECT  64.782 17.271 64.8 17.289 ;
        RECT  0 17.271 0.018 17.289 ;
        RECT  64.782 16.731 64.8 16.749 ;
        RECT  0 16.731 0.018 16.749 ;
        RECT  64.782 16.191 64.8 16.209 ;
        RECT  0 16.191 0.018 16.209 ;
        RECT  64.782 15.651 64.8 15.669 ;
        RECT  0 15.651 0.018 15.669 ;
        RECT  64.782 15.111 64.8 15.129 ;
        RECT  0 15.111 0.018 15.129 ;
        RECT  64.782 14.571 64.8 14.589 ;
        RECT  0 14.571 0.018 14.589 ;
        RECT  64.782 14.031 64.8 14.049 ;
        RECT  0 14.031 0.018 14.049 ;
        RECT  64.782 13.491 64.8 13.509 ;
        RECT  0 13.491 0.018 13.509 ;
        RECT  64.782 12.951 64.8 12.969 ;
        RECT  0 12.951 0.018 12.969 ;
        RECT  64.782 12.411 64.8 12.429 ;
        RECT  0 12.411 0.018 12.429 ;
        RECT  64.782 11.871 64.8 11.889 ;
        RECT  0 11.871 0.018 11.889 ;
        RECT  64.782 11.331 64.8 11.349 ;
        RECT  0 11.331 0.018 11.349 ;
        RECT  64.782 10.791 64.8 10.809 ;
        RECT  0 10.791 0.018 10.809 ;
        RECT  64.782 10.251 64.8 10.269 ;
        RECT  0 10.251 0.018 10.269 ;
        RECT  64.782 9.711 64.8 9.729 ;
        RECT  0 9.711 0.018 9.729 ;
        RECT  64.782 9.171 64.8 9.189 ;
        RECT  0 9.171 0.018 9.189 ;
        RECT  64.782 8.631 64.8 8.649 ;
        RECT  0 8.631 0.018 8.649 ;
        RECT  64.782 8.091 64.8 8.109 ;
        RECT  0 8.091 0.018 8.109 ;
        RECT  64.782 7.551 64.8 7.569 ;
        RECT  0 7.551 0.018 7.569 ;
        RECT  64.782 7.011 64.8 7.029 ;
        RECT  0 7.011 0.018 7.029 ;
        RECT  64.782 6.471 64.8 6.489 ;
        RECT  0 6.471 0.018 6.489 ;
        RECT  64.782 5.931 64.8 5.949 ;
        RECT  0 5.931 0.018 5.949 ;
        RECT  64.782 5.391 64.8 5.409 ;
        RECT  0 5.391 0.018 5.409 ;
        RECT  64.782 4.851 64.8 4.869 ;
        RECT  0 4.851 0.018 4.869 ;
        RECT  64.782 4.311 64.8 4.329 ;
        RECT  0 4.311 0.018 4.329 ;
        RECT  64.782 3.771 64.8 3.789 ;
        RECT  0 3.771 0.018 3.789 ;
        RECT  64.782 3.231 64.8 3.249 ;
        RECT  0 3.231 0.018 3.249 ;
        RECT  64.782 2.691 64.8 2.709 ;
        RECT  0 2.691 0.018 2.709 ;
        RECT  64.782 2.151 64.8 2.169 ;
        RECT  0 2.151 0.018 2.169 ;
        RECT  64.782 1.611 64.8 1.629 ;
        RECT  0 1.611 0.018 1.629 ;
        RECT  64.782 1.071 64.8 1.089 ;
        RECT  0 1.071 0.018 1.089 ;
        RECT  64.782 0.531 64.8 0.549 ;
        RECT  0 0.531 0.018 0.549 ;
    END
  END VSS
  OBS
    LAYER RVTN ;
     RECT  0 0.54 64.8 0.675 ;
     RECT  0 0.945 64.8 1.215 ;
     RECT  0 1.485 64.8 1.755 ;
     RECT  0 2.025 64.8 2.295 ;
     RECT  0 2.565 64.8 2.835 ;
     RECT  0 3.105 64.8 3.375 ;
     RECT  0 3.645 64.8 3.915 ;
     RECT  0 4.185 64.8 4.455 ;
     RECT  0 4.725 64.8 4.995 ;
     RECT  0 5.265 64.8 5.535 ;
     RECT  0 5.805 64.8 6.075 ;
     RECT  0 6.345 64.8 6.615 ;
     RECT  0 6.885 64.8 7.155 ;
     RECT  0 7.425 64.8 7.695 ;
     RECT  0 7.965 64.8 8.235 ;
     RECT  0 8.505 64.8 8.775 ;
     RECT  0 9.045 64.8 9.315 ;
     RECT  0 9.585 64.8 9.855 ;
     RECT  0 10.125 64.8 10.395 ;
     RECT  0 10.665 64.8 10.935 ;
     RECT  0 11.205 64.8 11.475 ;
     RECT  0 11.745 64.8 12.015 ;
     RECT  0 12.285 64.8 12.555 ;
     RECT  0 12.825 64.8 13.095 ;
     RECT  0 13.365 64.8 13.635 ;
     RECT  0 13.905 64.8 14.175 ;
     RECT  0 14.445 64.8 14.715 ;
     RECT  0 14.985 64.8 15.255 ;
     RECT  0 15.525 64.8 15.795 ;
     RECT  0 16.065 64.8 16.335 ;
     RECT  0 16.605 64.8 16.875 ;
     RECT  0 17.145 64.8 17.415 ;
     RECT  0 17.685 64.8 17.955 ;
     RECT  0 18.225 64.8 18.495 ;
     RECT  0 18.765 64.8 19.035 ;
     RECT  0 19.305 64.8 19.575 ;
     RECT  0 19.845 64.8 20.115 ;
     RECT  0 20.385 64.8 20.655 ;
     RECT  0 20.925 64.8 21.195 ;
     RECT  0 21.465 64.8 21.735 ;
     RECT  0 22.005 64.8 22.275 ;
     RECT  0 22.545 64.8 22.815 ;
     RECT  0 23.085 64.8 23.355 ;
     RECT  0 23.625 64.8 23.895 ;
     RECT  0 24.165 64.8 24.435 ;
     RECT  0 24.705 64.8 24.975 ;
     RECT  0 25.245 64.8 25.515 ;
     RECT  0 25.785 64.8 26.055 ;
     RECT  0 26.325 64.8 26.595 ;
     RECT  0 26.865 64.8 27.135 ;
     RECT  0 27.405 64.8 27.675 ;
     RECT  0 27.945 64.8 28.215 ;
     RECT  0 28.485 64.8 28.755 ;
     RECT  0 29.025 64.8 29.295 ;
     RECT  0 29.565 64.8 29.835 ;
     RECT  0 30.105 64.8 30.375 ;
     RECT  0 30.645 64.8 30.915 ;
     RECT  0 31.185 64.8 31.455 ;
     RECT  0 31.725 64.8 31.995 ;
     RECT  0 32.265 64.8 32.535 ;
     RECT  0 32.805 64.8 33.075 ;
     RECT  0 33.345 64.8 33.615 ;
     RECT  0 33.885 64.8 34.155 ;
     RECT  0 34.425 64.8 34.695 ;
     RECT  0 34.965 64.8 35.235 ;
     RECT  0 35.505 64.8 35.775 ;
     RECT  0 36.045 64.8 36.315 ;
     RECT  0 36.585 64.8 36.855 ;
     RECT  0 37.125 64.8 37.395 ;
     RECT  0 37.665 64.8 37.935 ;
     RECT  0 38.205 64.8 38.475 ;
     RECT  0 38.745 64.8 39.015 ;
     RECT  0 39.285 64.8 39.555 ;
     RECT  0 39.825 64.8 40.095 ;
     RECT  0 40.365 64.8 40.635 ;
     RECT  0 40.905 64.8 41.175 ;
     RECT  0 41.445 64.8 41.715 ;
     RECT  0 41.985 64.8 42.255 ;
     RECT  0 42.525 64.8 42.66 ;
    LAYER RVTP ;
     RECT  0 0.675 64.8 0.945 ;
     RECT  0 1.215 64.8 1.485 ;
     RECT  0 1.755 64.8 2.025 ;
     RECT  0 2.295 64.8 2.565 ;
     RECT  0 2.835 64.8 3.105 ;
     RECT  0 3.375 64.8 3.645 ;
     RECT  0 3.915 64.8 4.185 ;
     RECT  0 4.455 64.8 4.725 ;
     RECT  0 4.995 64.8 5.265 ;
     RECT  0 5.535 64.8 5.805 ;
     RECT  0 6.075 64.8 6.345 ;
     RECT  0 6.615 64.8 6.885 ;
     RECT  0 7.155 64.8 7.425 ;
     RECT  0 7.695 64.8 7.965 ;
     RECT  0 8.235 64.8 8.505 ;
     RECT  0 8.775 64.8 9.045 ;
     RECT  0 9.315 64.8 9.585 ;
     RECT  0 9.855 64.8 10.125 ;
     RECT  0 10.395 64.8 10.665 ;
     RECT  0 10.935 64.8 11.205 ;
     RECT  0 11.475 64.8 11.745 ;
     RECT  0 12.015 64.8 12.285 ;
     RECT  0 12.555 64.8 12.825 ;
     RECT  0 13.095 64.8 13.365 ;
     RECT  0 13.635 64.8 13.905 ;
     RECT  0 14.175 64.8 14.445 ;
     RECT  0 14.715 64.8 14.985 ;
     RECT  0 15.255 64.8 15.525 ;
     RECT  0 15.795 64.8 16.065 ;
     RECT  0 16.335 64.8 16.605 ;
     RECT  0 16.875 64.8 17.145 ;
     RECT  0 17.415 64.8 17.685 ;
     RECT  0 17.955 64.8 18.225 ;
     RECT  0 18.495 64.8 18.765 ;
     RECT  0 19.035 64.8 19.305 ;
     RECT  0 19.575 64.8 19.845 ;
     RECT  0 20.115 64.8 20.385 ;
     RECT  0 20.655 64.8 20.925 ;
     RECT  0 21.195 64.8 21.465 ;
     RECT  0 21.735 64.8 22.005 ;
     RECT  0 22.275 64.8 22.545 ;
     RECT  0 22.815 64.8 23.085 ;
     RECT  0 23.355 64.8 23.625 ;
     RECT  0 23.895 64.8 24.165 ;
     RECT  0 24.435 64.8 24.705 ;
     RECT  0 24.975 64.8 25.245 ;
     RECT  0 25.515 64.8 25.785 ;
     RECT  0 26.055 64.8 26.325 ;
     RECT  0 26.595 64.8 26.865 ;
     RECT  0 27.135 64.8 27.405 ;
     RECT  0 27.675 64.8 27.945 ;
     RECT  0 28.215 64.8 28.485 ;
     RECT  0 28.755 64.8 29.025 ;
     RECT  0 29.295 64.8 29.565 ;
     RECT  0 29.835 64.8 30.105 ;
     RECT  0 30.375 64.8 30.645 ;
     RECT  0 30.915 64.8 31.185 ;
     RECT  0 31.455 64.8 31.725 ;
     RECT  0 31.995 64.8 32.265 ;
     RECT  0 32.535 64.8 32.805 ;
     RECT  0 33.075 64.8 33.345 ;
     RECT  0 33.615 64.8 33.885 ;
     RECT  0 34.155 64.8 34.425 ;
     RECT  0 34.695 64.8 34.965 ;
     RECT  0 35.235 64.8 35.505 ;
     RECT  0 35.775 64.8 36.045 ;
     RECT  0 36.315 64.8 36.585 ;
     RECT  0 36.855 64.8 37.125 ;
     RECT  0 37.395 64.8 37.665 ;
     RECT  0 37.935 64.8 38.205 ;
     RECT  0 38.475 64.8 38.745 ;
     RECT  0 39.015 64.8 39.285 ;
     RECT  0 39.555 64.8 39.825 ;
     RECT  0 40.095 64.8 40.365 ;
     RECT  0 40.635 64.8 40.905 ;
     RECT  0 41.175 64.8 41.445 ;
     RECT  0 41.715 64.8 41.985 ;
     RECT  0 42.255 64.8 42.525 ;
    LAYER M1 ;
     RECT  0 0.531 64.8 42.669 ;
    LAYER M2 ;
     RECT  0 0.531 19.903 42.669 ;
     RECT  19.903 0.531 20.659 42.714 ;
     RECT  20.659 0.531 22.343 42.786 ;
     RECT  22.343 0.531 24.719 42.714 ;
     RECT  24.719 0.531 37.327 42.669 ;
     RECT  37.327 0.531 41.531 42.714 ;
     RECT  41.531 0.531 64.8 42.669 ;
    LAYER M3 ;
     RECT  11.055 0.523 11.145 0.607 ;
     RECT  16.455 0.523 16.545 0.679 ;
     RECT  15.876 0.679 16.545 0.715 ;
     RECT  11.052 0.607 11.145 0.751 ;
     RECT  15.804 0.715 16.545 0.751 ;
     RECT  0.255 0.523 0.345 0.793 ;
     RECT  5.655 0.523 5.745 0.793 ;
     RECT  10.836 0.751 11.214 0.793 ;
     RECT  15.696 0.751 16.545 0.793 ;
     RECT  21.855 0.523 21.945 0.793 ;
     RECT  27.255 0.523 27.345 0.793 ;
     RECT  32.655 0.523 32.745 0.793 ;
     RECT  38.055 0.523 38.145 0.793 ;
     RECT  43.455 0.523 43.545 0.793 ;
     RECT  48.855 0.523 48.945 0.793 ;
     RECT  54.255 0.523 54.345 0.793 ;
     RECT  59.655 0.523 59.745 0.793 ;
     RECT  15.696 0.793 16.737 0.877 ;
     RECT  10.836 0.793 11.337 0.913 ;
     RECT  10.116 0.913 11.337 0.949 ;
     RECT  15.696 0.877 16.866 0.949 ;
     RECT  9.936 0.949 11.337 0.985 ;
     RECT  15.696 0.949 16.902 0.985 ;
     RECT  9.792 0.985 11.337 1.021 ;
     RECT  12.456 0.859 13.086 1.021 ;
     RECT  15.48 0.985 17.442 1.021 ;
     RECT  14.58 0.985 14.598 1.147 ;
     RECT  9.792 1.021 13.446 1.291 ;
     RECT  14.58 1.147 14.742 1.291 ;
     RECT  15.48 1.021 18.27 1.291 ;
     RECT  47.124 1.255 47.142 1.291 ;
     RECT  8.496 1.021 8.514 1.525 ;
     RECT  8.316 1.525 8.514 1.561 ;
     RECT  9.792 1.291 18.27 1.561 ;
     RECT  43.455 0.793 43.737 1.561 ;
     RECT  5.655 0.793 5.937 1.651 ;
     RECT  6.84 1.561 6.93 1.651 ;
     RECT  32.655 0.793 32.937 1.651 ;
     RECT  48.855 0.793 49.137 1.651 ;
     RECT  9.288 1.561 18.27 1.675 ;
     RECT  43.455 1.561 45.594 1.675 ;
     RECT  46.332 1.651 46.35 1.675 ;
     RECT  5.655 1.651 6.93 1.687 ;
     RECT  8.208 1.561 8.514 1.687 ;
     RECT  43.455 1.675 46.35 1.687 ;
     RECT  47.124 1.291 48.078 1.687 ;
     RECT  20.088 1.183 20.106 1.723 ;
     RECT  48.855 1.651 49.374 1.723 ;
     RECT  20.088 1.723 20.178 1.759 ;
     RECT  20.016 1.759 20.178 1.795 ;
     RECT  37.188 1.759 37.206 1.795 ;
     RECT  5.616 1.687 6.93 1.831 ;
     RECT  9.288 1.675 18.882 1.831 ;
     RECT  20.016 1.795 20.394 1.831 ;
     RECT  30.852 1.795 31.05 1.831 ;
     RECT  31.968 1.651 32.937 1.831 ;
     RECT  5.436 1.831 7.074 1.915 ;
     RECT  7.956 1.687 8.514 1.921 ;
     RECT  9.288 1.831 20.394 1.921 ;
     RECT  29.232 1.795 29.25 1.921 ;
     RECT  41.22 1.561 41.598 1.921 ;
     RECT  29.124 1.921 29.25 1.957 ;
     RECT  35.424 1.921 35.442 1.957 ;
     RECT  5.364 1.915 7.074 1.993 ;
     RECT  5.364 1.993 7.11 2.029 ;
     RECT  7.956 1.921 20.394 2.029 ;
     RECT  39.888 1.921 39.906 2.029 ;
     RECT  7.956 2.029 20.79 2.057 ;
     RECT  40.824 1.921 41.598 2.059 ;
     RECT  42.408 1.795 42.426 2.059 ;
     RECT  43.455 1.687 48.078 2.059 ;
     RECT  48.855 1.723 50.058 2.059 ;
     RECT  30.06 1.993 30.078 2.065 ;
     RECT  39.456 2.029 39.906 2.065 ;
     RECT  40.824 2.059 42.426 2.093 ;
     RECT  5.112 2.029 7.11 2.101 ;
     RECT  28.944 1.957 29.25 2.101 ;
     RECT  29.988 2.065 30.078 2.101 ;
     RECT  38.055 0.793 38.337 2.101 ;
     RECT  39.384 2.065 39.906 2.101 ;
     RECT  40.824 2.093 41.598 2.101 ;
     RECT  42.372 2.093 42.426 2.101 ;
     RECT  43.455 2.059 50.058 2.101 ;
     RECT  28.944 2.101 30.078 2.191 ;
     RECT  30.852 1.831 32.937 2.191 ;
     RECT  4.14 2.191 4.158 2.251 ;
     RECT  51.984 2.227 52.002 2.263 ;
     RECT  3.528 2.251 4.158 2.291 ;
     RECT  3.996 2.291 4.158 2.335 ;
     RECT  4.968 2.101 7.11 2.335 ;
     RECT  21.855 0.793 22.137 2.335 ;
     RECT  37.116 1.795 37.206 2.335 ;
     RECT  38.016 2.101 41.598 2.335 ;
     RECT  10.044 2.057 20.79 2.371 ;
     RECT  28.944 2.191 32.937 2.371 ;
     RECT  35.424 1.957 35.514 2.371 ;
     RECT  42.372 2.101 50.058 2.371 ;
     RECT  51.84 2.263 52.002 2.371 ;
     RECT  54.255 0.793 54.537 2.371 ;
     RECT  28.944 2.371 33.426 2.461 ;
     RECT  34.776 2.371 35.514 2.461 ;
     RECT  51.84 2.371 52.182 2.461 ;
     RECT  52.92 2.371 52.938 2.461 ;
     RECT  37.116 2.335 41.598 2.497 ;
     RECT  36.936 2.497 41.598 2.533 ;
     RECT  2.376 2.533 2.394 2.569 ;
     RECT  36.648 2.533 41.598 2.569 ;
     RECT  56.808 2.497 56.826 2.569 ;
     RECT  1.656 2.569 2.394 2.605 ;
     RECT  10.044 2.371 21.042 2.605 ;
     RECT  21.855 2.335 22.23 2.605 ;
     RECT  27.255 0.793 27.537 2.605 ;
     RECT  28.872 2.461 33.426 2.605 ;
     RECT  51.84 2.461 52.938 2.605 ;
     RECT  53.748 2.371 54.537 2.605 ;
     RECT  1.584 2.605 2.394 2.641 ;
     RECT  3.996 2.335 7.11 2.641 ;
     RECT  7.956 2.057 9.306 2.641 ;
     RECT  10.044 2.605 22.23 2.641 ;
     RECT  23.148 2.605 23.166 2.641 ;
     RECT  25.092 1.993 25.11 2.641 ;
     RECT  27.036 2.605 27.537 2.641 ;
     RECT  28.656 2.605 33.426 2.641 ;
     RECT  34.776 2.461 35.622 2.641 ;
     RECT  42.372 2.371 50.778 2.641 ;
     RECT  51.84 2.605 54.537 2.641 ;
     RECT  42.372 2.641 50.922 2.731 ;
     RECT  51.696 2.641 54.537 2.731 ;
     RECT  56.448 2.569 56.826 2.731 ;
     RECT  28.656 2.641 35.622 2.759 ;
     RECT  36.576 2.569 41.598 2.767 ;
     RECT  26.964 2.641 27.537 2.803 ;
     RECT  24.084 2.641 25.254 2.875 ;
     RECT  36.432 2.767 41.598 2.875 ;
     RECT  42.372 2.731 54.882 2.875 ;
     RECT  1.476 2.641 2.502 2.911 ;
     RECT  3.996 2.641 9.306 2.911 ;
     RECT  10.044 2.641 23.238 2.911 ;
     RECT  24.084 2.875 25.578 2.911 ;
     RECT  26.676 2.803 27.537 2.911 ;
     RECT  28.656 2.759 34.434 2.911 ;
     RECT  35.28 2.759 35.622 2.911 ;
     RECT  36.432 2.875 54.882 2.911 ;
     RECT  55.908 2.731 56.826 2.911 ;
     RECT  3.996 2.911 25.578 2.939 ;
     RECT  35.28 2.911 56.826 2.939 ;
     RECT  40.86 2.939 56.826 3.019 ;
     RECT  1.476 2.911 2.754 3.037 ;
     RECT  35.28 2.939 40.086 3.065 ;
     RECT  3.996 2.939 17.046 3.101 ;
     RECT  17.928 2.939 25.578 3.101 ;
     RECT  1.476 3.037 2.862 3.181 ;
     RECT  24.588 3.101 25.578 3.181 ;
     RECT  40.86 3.019 57.546 3.181 ;
     RECT  17.928 3.101 23.49 3.209 ;
     RECT  1.476 3.181 3.186 3.259 ;
     RECT  3.996 3.101 9.27 3.259 ;
     RECT  17.928 3.209 23.238 3.299 ;
     RECT  0.255 0.793 0.537 3.307 ;
     RECT  0.255 3.307 0.594 3.343 ;
     RECT  0.255 3.343 0.666 3.403 ;
     RECT  1.476 3.259 9.27 3.403 ;
     RECT  24.588 3.181 25.686 3.577 ;
     RECT  61.956 3.577 61.974 3.613 ;
     RECT  40.86 3.181 58.878 3.685 ;
     RECT  26.676 2.911 34.434 3.721 ;
     RECT  35.28 3.065 39.474 3.721 ;
     RECT  61.092 3.649 61.11 3.721 ;
     RECT  61.956 3.613 62.082 3.721 ;
     RECT  40.464 3.685 58.878 3.787 ;
     RECT  40.428 3.787 58.878 3.811 ;
     RECT  59.655 0.793 59.937 3.811 ;
     RECT  61.092 3.721 62.838 3.811 ;
     RECT  26.676 3.721 39.474 3.835 ;
     RECT  0.255 3.403 9.27 3.847 ;
     RECT  10.008 3.101 17.046 3.847 ;
     RECT  17.928 3.299 23.202 3.847 ;
     RECT  26.676 3.835 39.546 3.847 ;
     RECT  40.428 3.811 59.937 3.847 ;
     RECT  61.092 3.811 63.342 3.847 ;
     RECT  26.676 3.847 63.342 3.983 ;
     RECT  0.255 3.847 23.202 4.081 ;
     RECT  24.588 3.577 25.866 4.117 ;
     RECT  0.255 4.081 23.31 4.189 ;
     RECT  24.552 4.117 25.866 4.219 ;
     RECT  26.676 3.983 28.026 4.219 ;
     RECT  28.764 3.983 63.342 4.261 ;
     RECT  28.764 4.261 63.378 4.379 ;
     RECT  58.068 4.379 63.378 4.531 ;
     RECT  28.764 4.379 57.114 4.559 ;
     RECT  24.552 4.219 28.026 4.685 ;
     RECT  24.66 4.685 28.026 4.801 ;
     RECT  28.764 4.559 33.75 4.801 ;
     RECT  58.068 4.531 63.81 4.801 ;
     RECT  0.255 4.189 23.526 4.963 ;
     RECT  34.524 4.559 57.114 5.161 ;
     RECT  58.068 4.801 64.35 5.161 ;
     RECT  24.66 4.801 33.75 5.341 ;
     RECT  34.524 5.161 64.35 5.341 ;
     RECT  0.255 4.963 23.742 5.459 ;
     RECT  24.66 5.341 64.35 5.459 ;
     RECT  0.255 5.459 23.526 5.495 ;
     RECT  24.66 5.459 62.19 5.531 ;
     RECT  0.255 5.495 23.31 5.603 ;
     RECT  24.66 5.531 34.47 5.603 ;
     RECT  62.928 5.459 64.35 5.611 ;
     RECT  62.928 5.611 64.566 5.693 ;
     RECT  24.66 5.603 34.326 5.701 ;
     RECT  35.208 5.531 62.19 6.277 ;
     RECT  62.928 5.693 64.242 6.277 ;
     RECT  0.255 5.603 23.094 6.385 ;
     RECT  35.208 6.277 64.242 6.421 ;
     RECT  0.255 6.385 23.13 6.547 ;
     RECT  24.624 5.701 34.326 6.571 ;
     RECT  35.208 6.421 64.422 6.571 ;
     RECT  24.624 6.571 64.422 6.781 ;
     RECT  24.624 6.781 64.53 6.845 ;
     RECT  0.255 6.547 23.634 6.961 ;
     RECT  0.216 6.961 23.634 7.231 ;
     RECT  24.624 6.845 64.458 7.231 ;
     RECT  0.216 7.231 64.458 7.421 ;
     RECT  0.216 7.421 23.958 7.457 ;
     RECT  24.696 7.421 64.458 8.041 ;
     RECT  0.216 7.457 23.778 8.437 ;
     RECT  24.696 8.041 64.494 8.437 ;
     RECT  0.216 8.437 64.494 8.477 ;
     RECT  24.696 8.477 64.494 8.537 ;
     RECT  24.696 8.537 58.446 8.813 ;
     RECT  59.22 8.537 64.494 9.149 ;
     RECT  0.216 8.477 23.634 9.355 ;
     RECT  44.604 8.813 58.446 9.437 ;
     RECT  0.216 9.355 23.886 9.451 ;
     RECT  24.696 8.813 43.866 9.451 ;
     RECT  0.216 9.451 43.866 9.509 ;
     RECT  62.136 9.149 64.494 9.509 ;
     RECT  24.588 9.509 43.866 9.553 ;
     RECT  45.18 9.437 58.446 9.581 ;
     RECT  45.432 9.581 58.446 9.661 ;
     RECT  59.22 9.149 61.218 9.661 ;
     RECT  63.252 9.509 64.494 9.661 ;
     RECT  45.432 9.661 61.218 9.851 ;
     RECT  24.588 9.553 44.442 10.165 ;
     RECT  50.688 9.851 61.218 10.201 ;
     RECT  24.588 10.165 44.586 10.267 ;
     RECT  0.216 9.509 23.202 10.399 ;
     RECT  50.688 10.201 61.29 10.427 ;
     RECT  58.896 10.427 61.29 10.435 ;
     RECT  62.136 9.509 62.514 10.435 ;
     RECT  24.156 10.267 44.586 10.463 ;
     RECT  45.432 9.851 49.626 10.633 ;
     RECT  50.688 10.427 57.906 10.633 ;
     RECT  0.216 10.399 23.346 10.697 ;
     RECT  27.036 10.463 44.586 10.705 ;
     RECT  45.432 10.633 57.906 10.705 ;
     RECT  0.216 10.697 23.202 10.733 ;
     RECT  63.252 9.661 64.71 10.741 ;
     RECT  58.896 10.435 62.514 10.859 ;
     RECT  59.04 10.859 62.514 10.939 ;
     RECT  63.252 10.741 64.746 10.939 ;
     RECT  24.156 10.463 26.262 11.209 ;
     RECT  27.036 10.705 57.906 11.209 ;
     RECT  27.036 11.209 58.158 11.213 ;
     RECT  24.048 11.209 26.262 11.371 ;
     RECT  27.036 11.213 55.134 11.371 ;
     RECT  24.048 11.371 55.134 11.399 ;
     RECT  59.04 10.939 64.746 11.399 ;
     RECT  24.048 11.399 30.33 11.435 ;
     RECT  0.216 10.733 15.39 11.479 ;
     RECT  16.128 10.733 23.202 11.479 ;
     RECT  0.216 11.479 23.202 11.641 ;
     RECT  24.048 11.435 30.114 11.641 ;
     RECT  31.068 11.399 55.134 11.669 ;
     RECT  61.596 11.399 64.746 11.669 ;
     RECT  56.088 11.213 58.158 11.749 ;
     RECT  56.088 11.749 58.302 11.821 ;
     RECT  59.04 11.399 60.786 11.821 ;
     RECT  44.856 11.669 55.134 11.975 ;
     RECT  45.216 11.975 55.134 12.019 ;
     RECT  45.216 12.019 55.35 12.029 ;
     RECT  45.54 12.029 55.35 12.055 ;
     RECT  56.088 11.821 60.786 12.055 ;
     RECT  31.068 11.669 43.938 12.451 ;
     RECT  45.54 12.055 60.786 12.451 ;
     RECT  61.704 11.669 64.746 12.451 ;
     RECT  31.068 12.451 44.442 12.749 ;
     RECT  0.216 11.641 30.114 12.757 ;
     RECT  0.216 12.757 30.294 12.763 ;
     RECT  31.068 12.749 31.806 12.763 ;
     RECT  45.54 12.451 64.746 12.829 ;
     RECT  0.216 12.763 31.806 12.857 ;
     RECT  45.432 12.829 64.746 12.865 ;
     RECT  32.655 12.749 44.442 12.991 ;
     RECT  45.432 12.865 64.782 12.991 ;
     RECT  32.655 12.991 64.782 13.163 ;
     RECT  0.255 12.857 31.806 13.289 ;
     RECT  0.255 13.289 28.89 13.373 ;
     RECT  29.664 13.289 31.806 13.531 ;
     RECT  32.655 13.163 34.902 13.531 ;
     RECT  35.64 13.163 64.782 13.595 ;
     RECT  0.255 13.373 27.594 13.723 ;
     RECT  35.64 13.595 40.698 13.901 ;
     RECT  41.58 13.595 64.782 14.045 ;
     RECT  28.368 13.373 28.89 14.071 ;
     RECT  29.664 13.531 34.902 14.071 ;
     RECT  28.368 14.071 34.902 14.143 ;
     RECT  35.64 13.901 40.554 14.143 ;
     RECT  0.18 13.723 27.594 14.203 ;
     RECT  28.368 14.143 40.554 14.203 ;
     RECT  0.144 14.203 40.554 14.711 ;
     RECT  28.836 14.711 40.554 14.747 ;
     RECT  42.3 14.045 64.782 14.791 ;
     RECT  0.144 14.711 19.458 14.909 ;
     RECT  0.144 14.909 6.462 14.953 ;
     RECT  30.924 14.747 40.554 15.025 ;
     RECT  30.924 15.025 40.878 15.061 ;
     RECT  41.76 14.791 64.782 15.061 ;
     RECT  7.236 14.909 19.458 15.179 ;
     RECT  7.236 15.179 19.422 15.251 ;
     RECT  7.452 15.251 19.422 15.287 ;
     RECT  28.836 14.747 30.114 15.529 ;
     RECT  30.924 15.061 64.782 15.529 ;
     RECT  20.232 14.711 28.098 15.727 ;
     RECT  28.836 15.529 64.782 15.727 ;
     RECT  7.632 15.287 19.422 15.961 ;
     RECT  20.232 15.727 64.782 15.961 ;
     RECT  7.632 15.961 64.782 16.105 ;
     RECT  7.524 16.105 64.782 16.259 ;
     RECT  0.072 14.953 6.462 16.411 ;
     RECT  7.776 16.259 64.782 16.541 ;
     RECT  0.072 16.411 7.002 16.645 ;
     RECT  18.864 16.541 64.782 16.799 ;
     RECT  7.776 16.541 17.946 17.069 ;
     RECT  7.776 17.069 17.658 17.249 ;
     RECT  7.776 17.249 17.55 17.311 ;
     RECT  0.036 16.645 7.002 17.419 ;
     RECT  7.74 17.311 17.55 17.419 ;
     RECT  18.936 16.799 64.782 17.717 ;
     RECT  18.936 17.717 64.746 17.761 ;
     RECT  18.828 17.761 64.746 17.879 ;
     RECT  0.036 17.419 17.55 17.915 ;
     RECT  18.828 17.879 64.602 17.933 ;
     RECT  4.824 17.915 17.55 18.149 ;
     RECT  18.828 17.933 64.566 18.149 ;
     RECT  18.828 18.149 20.574 18.193 ;
     RECT  5.004 18.149 17.55 18.221 ;
     RECT  18.756 18.193 20.574 18.301 ;
     RECT  18.72 18.301 20.574 18.391 ;
     RECT  7.02 18.221 17.55 18.491 ;
     RECT  7.02 18.491 16.794 18.527 ;
     RECT  17.604 18.571 17.622 18.689 ;
     RECT  0.036 17.915 4.05 18.797 ;
     RECT  7.02 18.527 16.737 18.845 ;
     RECT  5.004 18.221 6.282 19.075 ;
     RECT  18.396 18.391 20.574 19.075 ;
     RECT  21.348 18.149 64.566 19.075 ;
     RECT  18.396 19.075 64.566 19.111 ;
     RECT  18.396 19.111 64.602 19.201 ;
     RECT  4.356 19.075 6.282 19.471 ;
     RECT  7.02 18.845 11.754 19.471 ;
     RECT  12.636 18.845 16.737 19.531 ;
     RECT  17.856 19.201 64.602 19.607 ;
     RECT  4.356 19.471 11.754 19.615 ;
     RECT  12.636 19.531 16.938 19.615 ;
     RECT  17.856 19.607 18.666 19.615 ;
     RECT  0.036 18.797 3.438 19.651 ;
     RECT  4.356 19.615 18.666 19.651 ;
     RECT  0.036 19.651 18.666 19.913 ;
     RECT  19.404 19.607 64.602 20.147 ;
     RECT  0.072 19.913 18.666 20.353 ;
     RECT  19.404 20.147 61.254 20.353 ;
     RECT  62.064 20.147 64.602 20.461 ;
     RECT  62.064 20.461 64.674 20.579 ;
     RECT  0.072 20.353 61.254 21.271 ;
     RECT  62.064 20.579 64.53 21.271 ;
     RECT  0.072 21.271 64.53 21.299 ;
     RECT  0.072 21.299 29.754 21.505 ;
     RECT  30.492 21.299 64.53 21.541 ;
     RECT  0.036 21.505 29.754 21.629 ;
     RECT  30.492 21.541 64.566 21.695 ;
     RECT  0.072 21.629 29.754 21.767 ;
     RECT  30.492 21.695 63.45 21.773 ;
     RECT  30.492 21.773 61.038 21.803 ;
     RECT  0.108 21.767 29.754 22.081 ;
     RECT  30.492 21.803 61.002 22.081 ;
     RECT  0.108 22.081 61.002 22.235 ;
     RECT  0.144 22.235 61.002 22.505 ;
     RECT  61.956 21.773 63.45 22.585 ;
     RECT  0.18 22.505 61.002 22.891 ;
     RECT  61.956 22.585 63.702 22.891 ;
     RECT  0.18 22.891 63.702 23.419 ;
     RECT  0.072 23.419 63.702 23.431 ;
     RECT  64.548 21.695 64.566 23.431 ;
     RECT  0.072 23.431 64.566 23.585 ;
     RECT  0.144 23.585 64.566 23.657 ;
     RECT  0.216 23.657 64.566 23.819 ;
     RECT  0.216 23.819 52.578 23.855 ;
     RECT  53.352 23.819 64.566 23.927 ;
     RECT  53.424 23.927 64.566 24.241 ;
     RECT  53.424 24.241 64.602 24.359 ;
     RECT  0.255 23.855 52.578 24.935 ;
     RECT  0.255 24.935 28.53 25.043 ;
     RECT  0.255 25.043 28.386 25.169 ;
     RECT  53.424 24.359 64.566 25.169 ;
     RECT  29.484 24.935 52.578 25.285 ;
     RECT  29.484 25.285 52.614 25.411 ;
     RECT  53.424 25.169 63.486 25.411 ;
     RECT  0.255 25.169 28.206 25.483 ;
     RECT  29.484 25.411 63.486 25.681 ;
     RECT  29.268 25.681 63.486 25.781 ;
     RECT  0.216 25.483 28.206 25.861 ;
     RECT  0.144 25.861 28.206 25.951 ;
     RECT  64.548 25.169 64.566 25.979 ;
     RECT  29.268 25.781 57.114 25.997 ;
     RECT  0.144 25.951 28.35 26.059 ;
     RECT  29.268 25.997 57.078 26.059 ;
     RECT  57.852 25.781 63.486 26.059 ;
     RECT  57.852 26.059 63.63 26.095 ;
     RECT  0.144 26.059 57.078 26.123 ;
     RECT  57.852 26.095 64.134 26.249 ;
     RECT  0.144 26.123 57.042 26.285 ;
     RECT  0.216 26.285 57.042 26.789 ;
     RECT  0.255 26.789 57.042 27.103 ;
     RECT  0.255 27.103 57.078 27.211 ;
     RECT  57.852 26.249 63.954 27.211 ;
     RECT  0.255 27.211 63.954 27.481 ;
     RECT  0.255 27.481 64.35 27.877 ;
     RECT  0.216 27.877 64.35 28.291 ;
     RECT  0.216 28.291 64.458 28.481 ;
     RECT  0.216 28.481 63.918 28.715 ;
     RECT  0.216 28.715 56.646 29.021 ;
     RECT  51.624 29.021 56.646 29.219 ;
     RECT  57.384 28.715 63.918 29.371 ;
     RECT  0.216 29.021 50.742 29.803 ;
     RECT  51.624 29.219 56.43 29.803 ;
     RECT  0.216 29.803 56.43 29.903 ;
     RECT  57.384 29.371 64.458 30.137 ;
     RECT  0.216 29.903 56.394 30.569 ;
     RECT  0.255 30.569 56.394 30.605 ;
     RECT  33.66 30.605 56.394 30.685 ;
     RECT  33.66 30.685 56.538 30.847 ;
     RECT  57.384 30.137 64.17 30.847 ;
     RECT  33.66 30.847 64.17 31.109 ;
     RECT  33.66 31.109 45.018 31.145 ;
     RECT  45.9 31.109 64.17 31.145 ;
     RECT  45.9 31.145 56.394 31.253 ;
     RECT  57.132 31.145 64.17 31.261 ;
     RECT  0.255 30.605 32.937 31.379 ;
     RECT  33.66 31.145 44.91 31.379 ;
     RECT  0.255 31.379 31.842 31.451 ;
     RECT  57.132 31.261 64.242 31.523 ;
     RECT  32.616 31.379 32.937 31.627 ;
     RECT  33.66 31.379 41.814 31.627 ;
     RECT  32.616 31.627 41.814 31.721 ;
     RECT  42.588 31.379 44.91 31.867 ;
     RECT  42.588 31.867 45.486 31.999 ;
     RECT  42.588 31.999 45.558 32.071 ;
     RECT  46.404 31.253 56.394 32.071 ;
     RECT  57.132 31.523 63.63 32.071 ;
     RECT  0.255 31.451 31.734 32.197 ;
     RECT  32.616 31.721 41.49 32.197 ;
     RECT  0.255 32.197 41.49 32.381 ;
     RECT  0.255 32.381 31.77 32.477 ;
     RECT  32.655 32.381 41.49 32.611 ;
     RECT  42.588 32.071 63.63 32.611 ;
     RECT  32.655 32.611 41.778 32.729 ;
     RECT  42.588 32.611 64.17 32.765 ;
     RECT  56.232 32.765 64.17 32.873 ;
     RECT  63 32.873 64.17 32.999 ;
     RECT  63 32.999 63.99 33.035 ;
     RECT  26.964 32.477 31.77 33.241 ;
     RECT  32.655 32.729 41.274 33.241 ;
     RECT  0.255 32.477 26.19 33.313 ;
     RECT  26.964 33.241 41.274 33.313 ;
     RECT  42.588 32.765 55.278 33.421 ;
     RECT  42.3 33.421 55.278 33.583 ;
     RECT  0.255 33.313 41.274 33.691 ;
     RECT  56.232 32.873 62.262 33.691 ;
     RECT  63 33.035 63.954 33.691 ;
     RECT  42.3 33.583 55.386 33.787 ;
     RECT  42.264 33.787 55.386 33.809 ;
     RECT  0.255 33.691 41.382 33.817 ;
     RECT  42.264 33.809 55.35 33.817 ;
     RECT  56.232 33.691 63.954 33.925 ;
     RECT  0.255 33.817 55.35 33.953 ;
     RECT  56.232 33.925 64.53 33.961 ;
     RECT  0.255 33.953 30.222 34.079 ;
     RECT  30.96 33.953 55.35 34.079 ;
     RECT  0.255 34.079 30.15 34.115 ;
     RECT  0.255 34.115 29.682 34.253 ;
     RECT  0.255 34.253 29.574 34.349 ;
     RECT  0.255 34.349 29.538 34.735 ;
     RECT  48.348 34.079 55.35 34.735 ;
     RECT  48.348 34.735 55.494 34.889 ;
     RECT  54.036 34.889 55.494 34.925 ;
     RECT  54.144 34.925 55.494 34.933 ;
     RECT  56.232 33.961 64.674 34.933 ;
     RECT  31.068 34.079 47.574 35.035 ;
     RECT  30.78 35.035 47.574 35.041 ;
     RECT  48.348 34.889 53.262 35.041 ;
     RECT  30.78 35.041 53.262 35.069 ;
     RECT  0.216 34.735 29.538 35.231 ;
     RECT  0.255 35.231 29.538 35.419 ;
     RECT  0.255 35.419 29.574 35.437 ;
     RECT  54.144 34.933 64.674 35.609 ;
     RECT  55.872 35.609 64.674 35.735 ;
     RECT  30.96 35.069 53.262 35.779 ;
     RECT  54.144 35.609 54.702 35.779 ;
     RECT  64.656 35.735 64.674 35.807 ;
     RECT  55.872 35.735 63.882 35.969 ;
     RECT  55.872 35.969 63.702 36.077 ;
     RECT  0.255 35.437 29.97 36.121 ;
     RECT  56.232 36.077 63.702 36.239 ;
     RECT  61.128 36.239 62.406 36.311 ;
     RECT  30.96 35.779 54.702 36.319 ;
     RECT  63.18 36.239 63.378 36.347 ;
     RECT  56.232 36.239 60.318 36.383 ;
     RECT  30.852 36.319 54.702 36.475 ;
     RECT  61.128 36.311 61.866 36.509 ;
     RECT  63.18 36.347 63.198 36.509 ;
     RECT  56.232 36.383 59.937 36.545 ;
     RECT  61.488 36.509 61.866 36.545 ;
     RECT  58.104 36.545 59.937 36.581 ;
     RECT  61.56 36.545 61.866 36.617 ;
     RECT  30.852 36.475 55.458 36.625 ;
     RECT  61.848 36.617 61.866 36.653 ;
     RECT  0.255 36.121 30.006 36.661 ;
     RECT  30.78 36.625 55.458 36.661 ;
     RECT  56.232 36.545 57.186 36.779 ;
     RECT  58.68 36.581 59.937 36.779 ;
     RECT  0.255 36.661 55.458 36.811 ;
     RECT  56.232 36.779 57.114 36.811 ;
     RECT  0.255 36.811 57.114 36.815 ;
     RECT  0.255 36.815 57.006 36.923 ;
     RECT  0.255 36.923 55.71 36.959 ;
     RECT  56.7 36.923 57.006 36.959 ;
     RECT  30.96 36.959 55.71 37.391 ;
     RECT  0.255 36.959 29.862 37.427 ;
     RECT  42.264 37.391 55.71 37.669 ;
     RECT  24.3 37.427 29.862 37.705 ;
     RECT  30.96 37.391 41.202 37.705 ;
     RECT  42.264 37.669 55.746 37.859 ;
     RECT  42.264 37.859 55.386 37.895 ;
     RECT  24.3 37.705 41.202 38.129 ;
     RECT  42.264 37.895 54.702 38.129 ;
     RECT  0.255 37.427 23.49 38.173 ;
     RECT  28.944 38.129 34.11 38.237 ;
     RECT  24.3 38.129 28.206 38.309 ;
     RECT  0.255 38.173 23.526 38.395 ;
     RECT  24.3 38.309 28.062 38.395 ;
     RECT  34.848 38.129 41.202 38.525 ;
     RECT  29.124 38.237 34.11 38.741 ;
     RECT  53.964 38.129 54.702 38.821 ;
     RECT  0.255 38.395 28.062 38.939 ;
     RECT  29.448 38.741 34.11 38.939 ;
     RECT  35.352 38.525 41.202 39.055 ;
     RECT  1.692 38.939 28.062 39.091 ;
     RECT  1.692 39.091 28.494 39.197 ;
     RECT  1.8 39.197 28.494 39.209 ;
     RECT  42.264 38.129 53.118 39.211 ;
     RECT  0.255 38.939 0.918 39.281 ;
     RECT  42.156 39.211 53.118 39.325 ;
     RECT  53.964 38.821 55.026 39.325 ;
     RECT  29.484 38.939 34.11 39.355 ;
     RECT  35.352 39.055 41.274 39.355 ;
     RECT  42.156 39.325 55.278 39.355 ;
     RECT  29.484 39.355 34.614 39.487 ;
     RECT  35.352 39.355 55.278 39.487 ;
     RECT  2.34 39.209 28.494 39.533 ;
     RECT  2.664 39.533 28.494 39.551 ;
     RECT  3.24 39.551 28.494 39.587 ;
     RECT  3.384 39.587 28.494 39.623 ;
     RECT  29.484 39.487 55.278 39.631 ;
     RECT  4.032 39.623 28.494 39.749 ;
     RECT  29.484 39.631 55.314 39.749 ;
     RECT  29.484 39.749 54.537 39.785 ;
     RECT  29.484 39.785 49.626 39.821 ;
     RECT  55.296 39.749 55.314 39.869 ;
     RECT  29.484 39.821 49.554 40.027 ;
     RECT  50.58 39.785 54.537 40.091 ;
     RECT  29.34 40.027 49.554 40.099 ;
     RECT  28.476 39.749 28.494 40.123 ;
     RECT  29.304 40.099 49.554 40.123 ;
     RECT  4.032 39.749 27.537 40.163 ;
     RECT  28.476 40.123 49.554 40.205 ;
     RECT  4.032 40.163 4.59 40.289 ;
     RECT  28.476 40.205 45.99 40.289 ;
     RECT  34.956 40.289 45.99 40.325 ;
     RECT  4.572 40.289 4.59 40.397 ;
     RECT  5.328 40.163 27.537 40.445 ;
     RECT  5.328 40.445 14.022 40.469 ;
     RECT  34.956 40.325 45.918 40.469 ;
     RECT  14.832 40.445 27.537 40.555 ;
     RECT  28.476 40.289 34.11 40.555 ;
     RECT  5.436 40.469 14.022 40.595 ;
     RECT  5.436 40.595 6.246 40.667 ;
     RECT  50.652 40.091 54.537 40.703 ;
     RECT  5.436 40.667 6.21 40.829 ;
     RECT  14.832 40.555 34.11 40.829 ;
     RECT  7.2 40.595 14.022 40.901 ;
     RECT  5.436 40.829 5.937 40.973 ;
     RECT  36.792 40.469 45.774 40.973 ;
     RECT  50.652 40.703 53.262 40.981 ;
     RECT  28.872 40.829 34.11 41.035 ;
     RECT  7.74 40.901 14.022 41.099 ;
     RECT  36.792 40.973 41.562 41.099 ;
     RECT  50.544 40.981 53.262 41.099 ;
     RECT  7.74 41.099 13.95 41.135 ;
     RECT  42.336 40.973 45.774 41.135 ;
     RECT  14.832 40.829 28.062 41.179 ;
     RECT  7.74 41.135 11.43 41.207 ;
     RECT  50.544 41.099 53.154 41.207 ;
     RECT  14.724 41.179 28.062 41.213 ;
     RECT  28.872 41.035 34.182 41.215 ;
     RECT  34.956 40.469 36.018 41.215 ;
     RECT  36.792 41.099 40.158 41.215 ;
     RECT  46.8 40.205 49.554 41.215 ;
     RECT  12.528 41.135 13.95 41.243 ;
     RECT  15.516 41.213 28.062 41.243 ;
     RECT  46.764 41.215 49.554 41.251 ;
     RECT  7.74 41.207 11.394 41.369 ;
     RECT  12.6 41.243 13.95 41.369 ;
     RECT  42.336 41.135 45.702 41.369 ;
     RECT  50.544 41.207 52.83 41.369 ;
     RECT  46.764 41.251 49.59 41.377 ;
     RECT  7.74 41.369 9.27 41.405 ;
     RECT  10.332 41.369 11.394 41.405 ;
     RECT  12.6 41.369 13.05 41.405 ;
     RECT  50.544 41.369 51.894 41.405 ;
     RECT  8.568 41.405 9.018 41.441 ;
     RECT  12.924 41.405 13.05 41.441 ;
     RECT  13.932 41.369 13.95 41.513 ;
     RECT  45.54 41.369 45.702 41.513 ;
     RECT  46.728 41.377 49.59 41.513 ;
     RECT  11.055 41.405 11.394 41.549 ;
     RECT  48.816 41.513 49.59 41.549 ;
     RECT  50.544 41.405 51.642 41.549 ;
     RECT  15.588 41.243 28.062 41.639 ;
     RECT  28.872 41.215 40.158 41.639 ;
     RECT  45.54 41.513 45.666 41.639 ;
     RECT  29.628 41.639 40.158 41.645 ;
     RECT  46.728 41.513 47.862 41.647 ;
     RECT  48.855 41.549 49.59 41.675 ;
     RECT  50.688 41.549 51.642 41.675 ;
     RECT  52.632 41.369 52.83 41.675 ;
     RECT  41.004 41.099 41.562 41.707 ;
     RECT  42.336 41.369 44.586 41.707 ;
     RECT  14.724 41.213 14.742 41.747 ;
     RECT  48.855 41.675 49.374 41.747 ;
     RECT  52.632 41.675 52.65 41.747 ;
     RECT  16.2 41.639 28.062 41.783 ;
     RECT  46.512 41.647 47.862 41.783 ;
     RECT  41.004 41.707 44.586 41.881 ;
     RECT  29.664 41.645 40.158 41.909 ;
     RECT  40.932 41.881 44.586 41.909 ;
     RECT  45.54 41.639 45.558 41.909 ;
     RECT  50.976 41.675 51.642 41.909 ;
     RECT  40.932 41.909 44.55 41.933 ;
     RECT  29.664 41.909 35.694 41.945 ;
     RECT  47.016 41.783 47.862 41.945 ;
     RECT  50.976 41.909 51.462 41.945 ;
     RECT  36.612 41.909 40.158 41.981 ;
     RECT  16.416 41.783 28.062 42.025 ;
     RECT  36.792 41.981 40.158 42.053 ;
     RECT  29.7 41.945 35.694 42.179 ;
     RECT  36.828 42.053 40.158 42.179 ;
     RECT  40.932 41.933 44.478 42.179 ;
     RECT  30.636 42.179 30.942 42.215 ;
     RECT  32.04 42.179 35.694 42.215 ;
     RECT  37.044 42.179 40.158 42.215 ;
     RECT  40.932 42.179 44.37 42.215 ;
     RECT  47.34 41.945 47.862 42.215 ;
     RECT  50.976 41.945 51.354 42.215 ;
     RECT  16.416 42.025 28.278 42.221 ;
     RECT  37.044 42.215 39.942 42.287 ;
     RECT  47.34 42.215 47.358 42.287 ;
     RECT  16.416 42.221 17.01 42.323 ;
     RECT  17.82 42.221 28.17 42.323 ;
     RECT  32.04 42.215 35.514 42.359 ;
     RECT  50.976 42.215 50.994 42.359 ;
     RECT  0.255 39.281 0.537 42.407 ;
     RECT  5.655 40.973 5.937 42.407 ;
     RECT  11.055 41.549 11.337 42.407 ;
     RECT  16.455 42.323 16.737 42.407 ;
     RECT  18.504 42.323 27.537 42.407 ;
     RECT  32.04 42.359 35.082 42.407 ;
     RECT  40.932 42.215 43.737 42.407 ;
     RECT  48.855 41.747 49.137 42.407 ;
     RECT  54.255 40.703 54.537 42.407 ;
     RECT  59.655 36.779 59.937 42.407 ;
     RECT  18.504 42.407 27.345 42.449 ;
     RECT  29.7 42.179 29.862 42.449 ;
     RECT  30.636 42.215 30.654 42.449 ;
     RECT  33.624 42.407 35.082 42.449 ;
     RECT  37.08 42.287 39.546 42.449 ;
     RECT  40.932 42.407 43.545 42.449 ;
     RECT  18.504 42.449 18.522 42.485 ;
     RECT  19.296 42.449 22.806 42.485 ;
     RECT  32.04 42.407 32.745 42.485 ;
     RECT  33.624 42.449 34.722 42.485 ;
     RECT  40.932 42.449 42.642 42.485 ;
     RECT  19.332 42.485 20.97 42.521 ;
     RECT  26.532 42.449 27.345 42.521 ;
     RECT  41.508 42.485 42.39 42.521 ;
     RECT  32.256 42.485 32.745 42.593 ;
     RECT  34.704 42.485 34.722 42.593 ;
     RECT  37.332 42.449 39.546 42.593 ;
     RECT  19.908 42.521 20.97 42.605 ;
     RECT  21.708 42.485 22.806 42.629 ;
     RECT  24.084 42.449 24.714 42.629 ;
     RECT  42.372 42.521 42.39 42.629 ;
     RECT  0.255 42.407 0.345 42.677 ;
     RECT  5.655 42.407 5.745 42.677 ;
     RECT  11.055 42.407 11.145 42.677 ;
     RECT  16.455 42.407 16.545 42.677 ;
     RECT  21.855 42.629 22.806 42.677 ;
     RECT  27.255 42.521 27.345 42.677 ;
     RECT  32.655 42.593 32.745 42.677 ;
     RECT  37.332 42.593 39.33 42.677 ;
     RECT  43.455 42.449 43.545 42.677 ;
     RECT  48.855 42.407 48.945 42.677 ;
     RECT  54.255 42.407 54.345 42.677 ;
     RECT  59.655 42.407 59.745 42.677 ;
     RECT  20.664 42.605 20.97 42.719 ;
     RECT  24.696 42.629 24.714 42.719 ;
     RECT  37.332 42.677 37.35 42.719 ;
     RECT  38.736 42.677 39.33 42.719 ;
     RECT  41.508 42.521 41.526 42.719 ;
     RECT  19.908 42.605 19.926 42.749 ;
     RECT  39.312 42.719 39.33 42.749 ;
     RECT  20.664 42.719 20.682 42.791 ;
     RECT  22.32 42.677 22.806 42.791 ;
     RECT  22.788 42.791 22.806 43.085 ;
     RECT  25.632 42.449 25.65 43.085 ;
    LAYER M4 ;
     RECT  0.085 14.208 0.133 14.232 ;
     RECT  0.037 17.376 0.133 17.4 ;
     RECT  0.037 18.384 0.133 18.408 ;
     RECT  0.025 19.44 0.133 19.464 ;
     RECT  0.025 21.6 0.133 21.624 ;
     RECT  0.037 23.424 0.133 23.448 ;
     RECT  0.133 13.728 0.156 20.376 ;
     RECT  0.133 8.208 0.248 8.232 ;
     RECT  0.133 11.664 0.248 11.688 ;
     RECT  0.156 13.728 0.248 20.424 ;
     RECT  0.133 21.6 0.248 22.392 ;
     RECT  0.133 23.424 0.248 23.64 ;
     RECT  0.156 25.488 0.248 25.608 ;
     RECT  0.248 0.528 0.352 42.672 ;
     RECT  0.352 0.798 0.544 42.402 ;
     RECT  0.544 10.752 0.659 23.928 ;
     RECT  0.544 27.168 0.995 29.256 ;
     RECT  0.544 30.672 1.187 32.28 ;
     RECT  0.544 5.424 1.289 7.272 ;
     RECT  1.289 6.096 1.379 7.272 ;
     RECT  1.187 30.672 1.537 31.944 ;
     RECT  0.659 13.44 1.573 23.928 ;
     RECT  0.995 27.168 1.573 28.968 ;
     RECT  0.544 3.408 1.645 3.432 ;
     RECT  0.659 10.848 1.645 12.264 ;
     RECT  1.573 13.44 1.645 24.216 ;
     RECT  1.645 10.656 1.669 12.264 ;
     RECT  1.645 13.392 1.669 24.216 ;
     RECT  1.645 8.688 1.681 8.712 ;
     RECT  0.544 38.448 1.681 38.472 ;
     RECT  1.645 2.784 1.715 3.432 ;
     RECT  1.715 3.408 1.717 3.432 ;
     RECT  1.379 6.144 1.717 7.272 ;
     RECT  1.681 8.688 1.717 9.096 ;
     RECT  1.669 10.656 1.717 24.216 ;
     RECT  1.537 30.576 1.721 31.944 ;
     RECT  1.717 6.144 1.753 24.216 ;
     RECT  0.544 25.44 1.753 25.56 ;
     RECT  1.753 6.144 1.757 25.56 ;
     RECT  1.897 33.024 1.933 33.048 ;
     RECT  0.544 34.272 1.933 35.352 ;
     RECT  1.573 26.88 2.005 28.968 ;
     RECT  0.544 36.864 2.005 37.272 ;
     RECT  1.757 6.144 2.009 9.912 ;
     RECT  1.757 11.472 2.041 25.56 ;
     RECT  2.005 36.864 2.051 37.368 ;
     RECT  1.717 3.408 2.099 5.064 ;
     RECT  2.005 26.88 2.101 29.496 ;
     RECT  1.721 30.576 2.101 31.752 ;
     RECT  2.041 11.472 2.113 25.608 ;
     RECT  2.101 26.88 2.113 31.752 ;
     RECT  2.099 3.408 2.291 5.016 ;
     RECT  2.051 36.864 2.293 36.888 ;
     RECT  2.009 6.288 2.297 9.912 ;
     RECT  1.681 38.448 2.329 39.192 ;
     RECT  2.297 6.288 2.339 6.792 ;
     RECT  2.113 11.472 2.405 31.752 ;
     RECT  2.405 19.2 2.549 31.752 ;
     RECT  1.933 33.024 2.585 35.352 ;
     RECT  2.329 38.448 2.653 39.528 ;
     RECT  2.653 37.872 2.723 39.528 ;
     RECT  2.549 27.168 2.729 31.752 ;
     RECT  2.291 3.408 2.819 3.96 ;
     RECT  2.729 30.576 2.833 31.752 ;
     RECT  2.585 33.024 2.833 34.44 ;
     RECT  2.405 11.472 2.867 17.976 ;
     RECT  2.723 37.872 2.867 39.192 ;
     RECT  2.819 3.408 2.869 3.864 ;
     RECT  2.867 11.472 2.945 15.528 ;
     RECT  2.297 7.92 2.963 9.912 ;
     RECT  2.293 36.576 3.013 36.888 ;
     RECT  2.867 16.512 3.053 17.976 ;
     RECT  2.549 19.2 3.053 25.608 ;
     RECT  3.053 19.2 3.161 20.616 ;
     RECT  2.729 27.168 3.233 29.592 ;
     RECT  2.963 8.592 3.253 9.912 ;
     RECT  2.339 6.48 3.269 6.792 ;
     RECT  3.053 16.512 3.269 17.88 ;
     RECT  3.253 8.592 3.305 9.96 ;
     RECT  2.941 35.472 3.341 35.496 ;
     RECT  2.291 4.992 3.397 5.016 ;
     RECT  3.269 16.512 3.443 17.736 ;
     RECT  3.233 27.168 3.443 28.488 ;
     RECT  3.443 16.512 3.449 17.64 ;
     RECT  2.869 3.312 3.481 3.864 ;
     RECT  3.517 2.256 3.589 2.28 ;
     RECT  3.481 3.264 3.589 3.864 ;
     RECT  2.945 12.528 3.593 15.528 ;
     RECT  3.053 21.936 3.625 25.608 ;
     RECT  3.589 2.256 3.635 3.864 ;
     RECT  3.593 15.312 3.635 15.528 ;
     RECT  3.625 21.936 3.661 25.896 ;
     RECT  3.635 15.504 3.845 15.528 ;
     RECT  2.867 38.448 3.877 39.192 ;
     RECT  3.877 38.112 3.925 39.192 ;
     RECT  3.661 21.936 3.949 25.992 ;
     RECT  3.305 8.592 3.953 9.672 ;
     RECT  3.593 12.528 3.973 13.992 ;
     RECT  3.949 21.936 3.973 26.136 ;
     RECT  3.443 27.168 3.973 28.392 ;
     RECT  3.953 8.592 4.061 9.24 ;
     RECT  3.973 21.936 4.061 28.392 ;
     RECT  3.973 12.24 4.067 13.992 ;
     RECT  3.449 16.512 4.093 16.776 ;
     RECT  3.841 6.864 4.117 7.368 ;
     RECT  4.061 8.592 4.117 9.192 ;
     RECT  2.833 30.576 4.129 34.44 ;
     RECT  4.117 6.864 4.133 9.192 ;
     RECT  4.129 30.576 4.163 35.352 ;
     RECT  3.925 38.112 4.165 39.432 ;
     RECT  3.397 4.992 4.169 5.736 ;
     RECT  4.169 4.992 4.205 5.592 ;
     RECT  4.061 24.384 4.277 28.392 ;
     RECT  3.233 29.52 4.309 29.592 ;
     RECT  3.635 2.832 4.345 3.864 ;
     RECT  4.205 4.992 4.345 5.448 ;
     RECT  3.161 19.968 4.345 20.616 ;
     RECT  4.133 6.864 4.349 9.144 ;
     RECT  4.309 29.376 4.357 29.592 ;
     RECT  4.163 30.576 4.357 32.136 ;
     RECT  4.277 25.008 4.385 28.392 ;
     RECT  4.345 2.832 4.403 5.448 ;
     RECT  4.093 16.032 4.453 16.776 ;
     RECT  4.345 19.296 4.547 20.616 ;
     RECT  4.165 38.112 4.547 40.008 ;
     RECT  4.309 10.32 4.549 11.016 ;
     RECT  4.067 12.24 4.549 13.56 ;
     RECT  4.453 16.032 4.597 17.592 ;
     RECT  3.013 36.576 4.597 37.08 ;
     RECT  4.547 38.112 4.597 39.192 ;
     RECT  4.547 19.968 4.601 20.616 ;
     RECT  4.597 36.576 4.601 39.192 ;
     RECT  4.549 10.32 4.643 13.56 ;
     RECT  4.163 33.12 4.643 35.352 ;
     RECT  4.349 6.864 4.669 9.096 ;
     RECT  4.385 25.44 4.669 28.392 ;
     RECT  4.357 29.376 4.669 32.136 ;
     RECT  4.601 36.576 4.669 38.664 ;
     RECT  4.601 20.112 4.705 20.616 ;
     RECT  4.705 20.112 4.849 20.712 ;
     RECT  4.061 21.936 4.849 23.352 ;
     RECT  4.633 14.784 4.933 14.808 ;
     RECT  4.403 2.832 5.029 3.912 ;
     RECT  4.933 14.784 5.125 14.952 ;
     RECT  4.597 16.032 5.125 17.64 ;
     RECT  4.669 25.44 5.125 32.136 ;
     RECT  4.643 33.12 5.125 35.016 ;
     RECT  5.029 2.208 5.353 3.912 ;
     RECT  4.669 6.768 5.425 9.096 ;
     RECT  4.561 40.368 5.425 40.392 ;
     RECT  4.403 5.088 5.497 5.448 ;
     RECT  5.425 6.768 5.497 9.96 ;
     RECT  4.643 10.992 5.509 13.56 ;
     RECT  5.125 14.784 5.509 17.64 ;
     RECT  4.669 36.528 5.641 38.664 ;
     RECT  5.353 1.92 5.648 3.912 ;
     RECT  5.497 5.088 5.648 9.96 ;
     RECT  5.509 10.992 5.648 17.64 ;
     RECT  5.029 18.768 5.648 18.792 ;
     RECT  4.849 20.112 5.648 23.352 ;
     RECT  5.125 25.44 5.648 35.016 ;
     RECT  5.641 36.096 5.648 38.664 ;
     RECT  5.425 40.368 5.648 40.968 ;
     RECT  5.648 0.528 5.752 42.672 ;
     RECT  5.752 0.798 5.944 42.402 ;
     RECT  5.944 19.728 6.005 40.632 ;
     RECT  5.944 16.608 6.083 18.744 ;
     RECT  6.005 19.728 6.083 39.384 ;
     RECT  6.083 16.608 6.179 18.072 ;
     RECT  6.083 19.824 6.179 39.384 ;
     RECT  6.179 16.656 6.275 18.072 ;
     RECT  6.005 40.368 6.275 40.632 ;
     RECT  6.275 16.8 6.323 18.072 ;
     RECT  5.944 2.016 6.851 4.488 ;
     RECT  5.944 6.912 6.851 14.904 ;
     RECT  6.851 2.016 6.905 2.088 ;
     RECT  6.851 8.208 6.947 14.904 ;
     RECT  6.851 3.36 6.995 4.488 ;
     RECT  6.905 2.016 7.085 2.04 ;
     RECT  6.947 8.88 7.193 14.904 ;
     RECT  7.193 14.784 7.225 14.904 ;
     RECT  7.193 8.88 7.301 13.608 ;
     RECT  7.301 8.88 7.337 11.16 ;
     RECT  7.225 14.784 7.381 15.24 ;
     RECT  6.179 19.824 7.405 33.144 ;
     RECT  6.179 34.176 7.405 39.384 ;
     RECT  7.381 14.784 7.427 15.432 ;
     RECT  7.405 19.824 7.429 39.384 ;
     RECT  6.995 3.504 7.441 4.488 ;
     RECT  6.997 5.856 7.441 6.552 ;
     RECT  7.429 19.824 7.445 39.912 ;
     RECT  7.445 19.824 7.475 34.824 ;
     RECT  6.323 16.8 7.477 17.064 ;
     RECT  6.323 18.048 7.477 18.072 ;
     RECT  7.427 14.88 7.513 15.432 ;
     RECT  7.477 16.8 7.513 18.216 ;
     RECT  7.337 8.88 7.625 10.248 ;
     RECT  7.301 12.624 7.625 13.608 ;
     RECT  7.513 14.88 7.697 18.216 ;
     RECT  7.475 19.824 7.769 33.144 ;
     RECT  7.625 8.88 7.805 10.2 ;
     RECT  7.441 3.504 7.861 6.552 ;
     RECT  7.445 35.904 7.873 39.912 ;
     RECT  7.717 41.136 7.873 41.16 ;
     RECT  7.769 24.96 7.907 33.144 ;
     RECT  7.697 14.88 7.949 15.432 ;
     RECT  7.769 19.824 7.957 23.736 ;
     RECT  7.949 14.88 7.985 15.24 ;
     RECT  7.625 12.624 8.003 13.128 ;
     RECT  7.907 24.96 8.003 26.136 ;
     RECT  7.861 3.504 8.017 6.6 ;
     RECT  8.003 12.624 8.057 12.648 ;
     RECT  7.907 27.12 8.057 33.144 ;
     RECT  8.057 27.408 8.129 33.144 ;
     RECT  7.697 16.512 8.195 18.216 ;
     RECT  8.195 16.512 8.237 17.112 ;
     RECT  8.245 1.68 8.305 1.704 ;
     RECT  8.017 2.832 8.305 6.6 ;
     RECT  8.305 1.68 8.309 6.6 ;
     RECT  8.237 16.8 8.345 17.112 ;
     RECT  7.873 35.904 8.377 41.16 ;
     RECT  8.309 1.776 8.417 6.6 ;
     RECT  7.475 34.176 8.437 34.824 ;
     RECT  8.377 35.904 8.437 41.256 ;
     RECT  8.417 2.208 8.485 6.6 ;
     RECT  8.341 11.424 8.485 11.448 ;
     RECT  7.957 19.776 8.485 23.736 ;
     RECT  8.485 18.24 8.525 23.736 ;
     RECT  8.437 34.176 8.531 41.256 ;
     RECT  8.485 11.424 8.533 11.544 ;
     RECT  8.485 2.208 8.593 6.888 ;
     RECT  8.531 41.04 8.597 41.256 ;
     RECT  8.129 30.288 8.677 33.144 ;
     RECT  8.531 34.176 8.677 39.864 ;
     RECT  8.525 20.016 8.737 23.736 ;
     RECT  8.593 2.208 8.915 7.464 ;
     RECT  8.915 3.408 8.921 7.464 ;
     RECT  8.881 13.824 8.953 13.848 ;
     RECT  7.985 14.88 8.953 14.904 ;
     RECT  8.921 5.616 9.025 7.464 ;
     RECT  7.805 8.928 9.025 10.2 ;
     RECT  8.533 11.424 9.025 11.64 ;
     RECT  8.129 27.408 9.061 29.256 ;
     RECT  8.915 2.208 9.065 2.28 ;
     RECT  9.025 5.616 9.109 7.512 ;
     RECT  9.025 8.928 9.109 11.64 ;
     RECT  8.737 20.016 9.109 23.832 ;
     RECT  8.003 25.008 9.109 26.136 ;
     RECT  9.061 27.312 9.133 29.256 ;
     RECT  8.677 30.288 9.133 39.864 ;
     RECT  9.109 20.016 9.169 26.136 ;
     RECT  9.133 27.312 9.169 39.864 ;
     RECT  9.065 2.208 9.173 2.232 ;
     RECT  8.921 3.408 9.209 4.488 ;
     RECT  8.953 13.824 9.241 14.904 ;
     RECT  9.169 20.016 9.245 39.864 ;
     RECT  9.245 20.016 9.299 39 ;
     RECT  9.241 13.824 9.349 15.192 ;
     RECT  8.345 16.992 9.349 17.112 ;
     RECT  8.525 18.24 9.349 18.888 ;
     RECT  9.299 20.016 9.425 28.008 ;
     RECT  9.349 13.824 9.443 17.112 ;
     RECT  9.109 5.616 9.493 11.64 ;
     RECT  9.425 20.064 9.497 28.008 ;
     RECT  9.493 5.616 9.529 12.312 ;
     RECT  9.529 5.616 9.533 12.792 ;
     RECT  9.533 5.616 9.641 9.096 ;
     RECT  9.533 10.128 9.683 12.792 ;
     RECT  8.597 41.184 9.685 41.256 ;
     RECT  9.443 16.32 9.731 17.112 ;
     RECT  9.443 13.824 9.749 15.288 ;
     RECT  9.683 12.288 9.817 12.792 ;
     RECT  9.749 13.824 9.817 15.192 ;
     RECT  9.731 17.04 9.821 17.112 ;
     RECT  9.497 20.064 9.821 27.912 ;
     RECT  9.349 18.192 9.853 18.888 ;
     RECT  9.641 7.296 9.893 9.096 ;
     RECT  9.893 7.344 10.019 9.096 ;
     RECT  9.817 12.288 10.073 15.192 ;
     RECT  10.105 1.488 10.141 1.512 ;
     RECT  9.209 3.408 10.177 4.44 ;
     RECT  9.685 40.56 10.213 41.256 ;
     RECT  10.141 1.488 10.393 1.8 ;
     RECT  9.853 17.616 10.429 18.888 ;
     RECT  10.393 1.488 10.573 1.848 ;
     RECT  9.641 5.616 10.609 6.12 ;
     RECT  10.177 3.408 10.717 4.488 ;
     RECT  10.609 5.616 10.717 6.312 ;
     RECT  10.019 7.44 10.741 9.096 ;
     RECT  9.683 10.128 10.741 11.16 ;
     RECT  9.821 20.064 10.753 22.056 ;
     RECT  10.573 1.104 10.825 1.992 ;
     RECT  10.717 3.408 10.825 6.312 ;
     RECT  10.073 14.784 10.861 15.192 ;
     RECT  9.821 23.136 10.885 27.912 ;
     RECT  10.861 14.784 10.933 15.672 ;
     RECT  10.753 20.016 10.933 22.056 ;
     RECT  10.885 23.136 10.933 27.96 ;
     RECT  9.299 28.992 10.933 39 ;
     RECT  10.933 20.016 10.969 39 ;
     RECT  10.213 40.32 10.969 41.256 ;
     RECT  10.825 1.104 11.041 6.312 ;
     RECT  11.041 0.864 11.048 6.312 ;
     RECT  10.741 7.44 11.048 11.16 ;
     RECT  10.073 12.288 11.048 13.368 ;
     RECT  10.933 14.784 11.048 16.008 ;
     RECT  10.429 17.616 11.048 18.984 ;
     RECT  10.969 20.016 11.048 41.256 ;
     RECT  11.048 0.528 11.152 42.672 ;
     RECT  11.152 0.798 11.344 42.402 ;
     RECT  11.344 8.976 11.555 40.92 ;
     RECT  11.555 13.776 11.621 40.92 ;
     RECT  11.621 13.776 11.837 16.344 ;
     RECT  11.837 13.776 11.873 14.472 ;
     RECT  11.621 17.616 12.305 40.92 ;
     RECT  11.344 0.864 12.481 7.992 ;
     RECT  11.555 8.976 12.481 12.648 ;
     RECT  12.305 36.384 12.521 40.92 ;
     RECT  12.481 0.864 12.665 12.648 ;
     RECT  11.837 15.456 12.769 16.344 ;
     RECT  12.305 17.616 12.769 35.016 ;
     RECT  11.873 14.448 12.805 14.472 ;
     RECT  12.769 15.456 12.805 35.016 ;
     RECT  12.805 14.448 12.881 35.016 ;
     RECT  12.665 0.864 12.917 5.112 ;
     RECT  12.917 0.864 13.061 2.28 ;
     RECT  12.881 15.744 13.091 35.016 ;
     RECT  13.061 0.864 13.097 1.848 ;
     RECT  12.881 14.448 13.133 14.472 ;
     RECT  12.665 6.192 13.201 12.648 ;
     RECT  12.521 36.48 13.313 40.92 ;
     RECT  13.201 6.192 13.453 12.984 ;
     RECT  13.097 1.152 13.529 1.848 ;
     RECT  13.313 36.48 13.571 40.68 ;
     RECT  13.091 17.472 13.597 35.016 ;
     RECT  13.571 36.48 13.597 39.24 ;
     RECT  13.489 14.112 13.667 14.184 ;
     RECT  13.571 40.368 13.673 40.68 ;
     RECT  13.597 17.472 13.709 39.24 ;
     RECT  13.453 6.192 13.715 13.032 ;
     RECT  13.715 10.848 13.717 13.032 ;
     RECT  13.667 14.112 13.717 14.136 ;
     RECT  12.917 3.408 13.813 5.112 ;
     RECT  13.715 6.192 13.813 9.864 ;
     RECT  13.717 10.848 13.817 14.136 ;
     RECT  13.091 15.744 13.885 16.248 ;
     RECT  13.885 15.312 13.955 16.248 ;
     RECT  13.955 15.456 14.033 16.248 ;
     RECT  13.813 3.408 14.177 9.864 ;
     RECT  14.177 3.408 14.197 3.624 ;
     RECT  14.177 4.848 14.243 9.864 ;
     RECT  14.243 4.848 14.249 6.072 ;
     RECT  13.817 10.848 14.249 14.088 ;
     RECT  13.709 22.752 14.357 39.24 ;
     RECT  14.197 2.592 14.429 3.624 ;
     RECT  13.709 17.472 14.435 21.48 ;
     RECT  14.249 11.184 14.465 14.088 ;
     RECT  13.529 1.152 14.533 1.56 ;
     RECT  14.033 15.456 14.579 15.48 ;
     RECT  14.533 1.104 14.609 1.56 ;
     RECT  13.673 40.368 14.677 40.44 ;
     RECT  14.429 2.592 14.723 2.76 ;
     RECT  14.461 16.8 14.723 16.872 ;
     RECT  14.357 34.992 14.749 39.24 ;
     RECT  14.677 40.368 14.749 41.208 ;
     RECT  14.435 18.288 14.785 21.48 ;
     RECT  14.357 22.752 14.785 33.768 ;
     RECT  14.723 16.848 14.825 16.872 ;
     RECT  14.243 7.056 14.893 9.864 ;
     RECT  14.785 18.288 14.897 33.768 ;
     RECT  14.897 30.384 14.969 33.768 ;
     RECT  14.609 1.152 15.001 1.56 ;
     RECT  14.749 34.992 15.077 41.208 ;
     RECT  14.249 5.184 15.205 6.072 ;
     RECT  14.893 7.056 15.205 10.152 ;
     RECT  15.205 5.184 15.253 10.152 ;
     RECT  15.253 5.184 15.293 10.488 ;
     RECT  14.465 12.048 15.301 14.088 ;
     RECT  15.301 12.048 15.365 14.52 ;
     RECT  15.293 5.184 15.397 5.688 ;
     RECT  15.077 34.992 15.397 39.528 ;
     RECT  15.293 6.672 15.401 10.488 ;
     RECT  15.397 4.992 15.433 5.688 ;
     RECT  15.401 8.448 15.473 10.44 ;
     RECT  15.433 4.464 15.493 5.688 ;
     RECT  14.897 18.288 15.505 29.4 ;
     RECT  15.001 1.152 15.721 2.376 ;
     RECT  15.493 3.936 15.721 5.688 ;
     RECT  15.685 15.408 15.733 15.432 ;
     RECT  15.397 34.896 15.793 39.528 ;
     RECT  15.365 12.048 15.901 14.232 ;
     RECT  14.969 30.384 15.937 33.576 ;
     RECT  15.901 11.76 15.973 14.232 ;
     RECT  15.505 17.952 15.973 29.4 ;
     RECT  15.937 30.384 15.973 33.672 ;
     RECT  15.973 17.952 16.225 33.672 ;
     RECT  15.721 1.152 16.261 5.688 ;
     RECT  15.401 6.672 16.261 7.416 ;
     RECT  16.225 17.664 16.309 33.672 ;
     RECT  15.793 34.656 16.309 39.528 ;
     RECT  15.077 40.608 16.309 41.208 ;
     RECT  16.261 1.152 16.448 7.416 ;
     RECT  15.473 9.072 16.448 10.44 ;
     RECT  15.973 11.52 16.448 14.232 ;
     RECT  15.733 15.408 16.448 16.536 ;
     RECT  16.309 17.664 16.448 39.528 ;
     RECT  16.309 40.608 16.448 41.448 ;
     RECT  16.448 0.528 16.552 42.672 ;
     RECT  16.552 0.798 16.744 42.402 ;
     RECT  16.744 4.176 16.805 5.112 ;
     RECT  16.744 1.104 16.883 2.808 ;
     RECT  16.805 4.416 16.883 5.112 ;
     RECT  16.744 19.536 16.949 42.216 ;
     RECT  16.744 6.24 16.985 17.976 ;
     RECT  16.949 20.064 16.985 42.216 ;
     RECT  16.985 17.952 17.165 17.976 ;
     RECT  16.883 1.104 17.201 2.376 ;
     RECT  16.985 6.24 17.315 16.68 ;
     RECT  16.883 4.56 17.345 5.112 ;
     RECT  17.315 10.128 17.525 16.68 ;
     RECT  17.201 1.104 17.651 2.328 ;
     RECT  17.345 4.752 17.651 5.112 ;
     RECT  17.651 1.44 17.747 2.328 ;
     RECT  16.985 35.136 17.917 42.216 ;
     RECT  16.985 20.064 18.025 33.912 ;
     RECT  18.025 20.064 18.061 33.96 ;
     RECT  17.917 35.136 18.061 42.264 ;
     RECT  18.061 20.064 18.179 42.264 ;
     RECT  17.315 6.24 18.181 9.096 ;
     RECT  18.179 20.064 18.227 40.968 ;
     RECT  18.179 41.952 18.227 42.264 ;
     RECT  17.747 1.68 18.229 2.328 ;
     RECT  18.227 20.064 18.229 40.92 ;
     RECT  17.525 10.128 18.281 16.536 ;
     RECT  18.229 19.248 18.281 40.92 ;
     RECT  18.227 41.952 18.281 42.216 ;
     RECT  18.281 10.128 18.313 13.752 ;
     RECT  18.281 19.344 18.317 27.72 ;
     RECT  18.181 6.096 18.385 9.096 ;
     RECT  18.313 10.08 18.385 13.752 ;
     RECT  17.651 4.752 18.421 5.064 ;
     RECT  18.281 14.832 18.461 16.536 ;
     RECT  18.317 19.344 18.461 27.672 ;
     RECT  18.461 19.344 18.677 27.624 ;
     RECT  18.281 28.992 18.749 40.92 ;
     RECT  18.385 6.096 18.803 13.752 ;
     RECT  18.461 14.832 18.857 16.056 ;
     RECT  18.677 21.216 18.857 27.624 ;
     RECT  18.229 1.68 18.893 3.192 ;
     RECT  18.857 21.552 18.893 27.624 ;
     RECT  18.803 6.096 19.037 9.096 ;
     RECT  18.421 4.656 19.093 5.064 ;
     RECT  19.037 6.096 19.093 7.416 ;
     RECT  18.893 1.968 19.109 3.192 ;
     RECT  19.093 4.656 19.109 7.416 ;
     RECT  19.109 4.656 19.141 7.368 ;
     RECT  18.857 14.832 19.145 14.856 ;
     RECT  19.141 4.416 19.177 7.368 ;
     RECT  19.177 3.936 19.187 7.368 ;
     RECT  18.281 42.096 19.189 42.216 ;
     RECT  19.187 3.936 19.235 6.984 ;
     RECT  18.749 40.416 19.237 40.92 ;
     RECT  18.889 18.192 19.285 18.216 ;
     RECT  18.677 19.344 19.285 19.368 ;
     RECT  19.189 42.096 19.285 42.36 ;
     RECT  18.893 21.552 19.325 22.872 ;
     RECT  19.237 40.416 19.333 41.112 ;
     RECT  19.285 42.096 19.333 42.984 ;
     RECT  19.037 8.496 19.379 9.096 ;
     RECT  18.803 10.368 19.381 13.752 ;
     RECT  18.749 28.992 19.381 39.384 ;
     RECT  19.285 18.144 19.397 19.368 ;
     RECT  19.333 40.416 19.397 42.984 ;
     RECT  18.857 15.984 19.621 16.056 ;
     RECT  19.033 17.04 19.621 17.064 ;
     RECT  19.621 15.984 19.715 17.064 ;
     RECT  19.109 1.968 19.829 2.904 ;
     RECT  18.893 24.048 19.861 27.624 ;
     RECT  19.381 28.8 19.861 39.384 ;
     RECT  19.397 18.144 19.933 19.128 ;
     RECT  19.325 21.648 19.933 22.872 ;
     RECT  19.933 21.648 19.957 22.92 ;
     RECT  19.861 24.048 19.957 39.384 ;
     RECT  19.397 40.416 19.957 41.016 ;
     RECT  19.933 17.616 20.003 19.128 ;
     RECT  19.379 8.736 20.041 9.096 ;
     RECT  19.381 10.368 20.041 14.808 ;
     RECT  19.957 21.648 20.225 41.016 ;
     RECT  19.829 2.16 20.245 2.904 ;
     RECT  19.235 4.08 20.245 6.984 ;
     RECT  20.225 22.176 20.291 41.016 ;
     RECT  20.291 22.224 20.333 41.016 ;
     RECT  20.041 8.736 20.365 14.808 ;
     RECT  19.715 15.984 20.365 16.584 ;
     RECT  20.245 2.16 20.435 6.984 ;
     RECT  20.365 8.736 20.435 16.584 ;
     RECT  20.435 3.984 20.473 6.984 ;
     RECT  20.435 2.16 20.531 2.904 ;
     RECT  20.003 18.144 20.533 19.128 ;
     RECT  20.473 3.984 20.549 7.464 ;
     RECT  20.531 2.592 20.585 2.904 ;
     RECT  20.533 18.144 20.585 19.464 ;
     RECT  20.585 2.688 20.621 2.904 ;
     RECT  20.435 8.736 20.725 14.28 ;
     RECT  20.725 8.544 20.729 14.28 ;
     RECT  20.585 18.192 20.729 19.464 ;
     RECT  20.549 6.384 20.761 7.464 ;
     RECT  20.729 8.544 20.761 14.184 ;
     RECT  20.435 15.744 21.013 16.584 ;
     RECT  20.333 22.464 21.337 40.968 ;
     RECT  19.397 42.048 21.337 42.984 ;
     RECT  21.337 22.464 21.373 42.984 ;
     RECT  20.621 2.736 21.445 2.904 ;
     RECT  20.549 3.984 21.445 4.824 ;
     RECT  21.013 15.744 21.697 16.968 ;
     RECT  20.729 18.192 21.697 19.128 ;
     RECT  21.697 15.744 21.733 19.128 ;
     RECT  21.085 20.352 21.733 20.424 ;
     RECT  21.373 21.84 21.733 42.984 ;
     RECT  21.445 2.736 21.848 4.824 ;
     RECT  20.761 6.384 21.848 14.184 ;
     RECT  21.733 15.744 21.848 42.984 ;
     RECT  21.848 0.528 21.952 42.984 ;
     RECT  21.952 0.798 22.144 42.984 ;
     RECT  22.144 4.128 22.205 23.064 ;
     RECT  22.205 4.128 22.241 20.664 ;
     RECT  22.241 4.128 22.259 20.616 ;
     RECT  22.144 38.64 22.259 42.984 ;
     RECT  22.259 4.128 22.277 13.608 ;
     RECT  22.277 4.128 22.349 13.416 ;
     RECT  22.259 14.592 22.355 20.424 ;
     RECT  22.144 2.688 22.385 2.856 ;
     RECT  22.144 24.96 22.385 37.032 ;
     RECT  22.355 14.736 22.421 20.424 ;
     RECT  22.421 14.736 22.529 19.08 ;
     RECT  22.349 4.128 22.745 5.064 ;
     RECT  22.349 6.576 22.745 13.368 ;
     RECT  22.259 42.96 22.777 42.984 ;
     RECT  22.529 14.736 22.787 18.696 ;
     RECT  22.777 42.96 22.817 43.08 ;
     RECT  22.787 14.736 22.853 18.264 ;
     RECT  22.745 6.576 22.889 12.648 ;
     RECT  22.853 14.736 22.889 17.736 ;
     RECT  22.889 11.424 22.925 12.648 ;
     RECT  22.889 6.576 22.961 10.344 ;
     RECT  22.961 6.672 22.979 10.344 ;
     RECT  22.889 14.736 22.979 17.64 ;
     RECT  22.925 11.52 23.033 12.648 ;
     RECT  22.745 4.176 23.105 5.064 ;
     RECT  22.259 38.64 23.137 39.096 ;
     RECT  22.385 2.688 23.177 2.712 ;
     RECT  22.979 10.32 23.177 10.344 ;
     RECT  22.421 20.064 23.245 20.424 ;
     RECT  22.979 6.672 23.249 9.144 ;
     RECT  22.385 24.96 23.269 27.96 ;
     RECT  23.137 38.544 23.281 39.096 ;
     RECT  22.259 40.464 23.281 41.832 ;
     RECT  23.281 38.544 23.285 41.832 ;
     RECT  22.979 14.736 23.317 16.152 ;
     RECT  22.205 21.648 23.317 23.064 ;
     RECT  23.269 24.144 23.317 27.96 ;
     RECT  23.285 38.544 23.321 38.856 ;
     RECT  23.285 39.888 23.353 41.832 ;
     RECT  23.321 38.544 23.365 38.808 ;
     RECT  23.317 21.504 23.389 27.96 ;
     RECT  22.385 28.944 23.389 37.032 ;
     RECT  23.353 39.888 23.411 41.976 ;
     RECT  23.389 21.504 23.429 37.032 ;
     RECT  23.429 21.504 23.501 36.984 ;
     RECT  23.245 20.064 23.569 20.52 ;
     RECT  23.501 21.504 23.569 32.616 ;
     RECT  23.569 20.064 23.677 32.616 ;
     RECT  23.317 14.256 23.939 16.152 ;
     RECT  23.939 15.792 23.969 16.152 ;
     RECT  23.033 11.664 24.037 12.648 ;
     RECT  23.677 19.92 24.179 32.616 ;
     RECT  23.969 15.888 24.181 16.152 ;
     RECT  22.979 17.136 24.181 17.64 ;
     RECT  23.939 14.256 24.217 14.76 ;
     RECT  24.181 15.888 24.253 17.64 ;
     RECT  23.249 6.672 24.397 9.096 ;
     RECT  23.941 10.272 24.397 10.296 ;
     RECT  24.085 18.672 24.397 18.696 ;
     RECT  24.179 19.92 24.397 32.568 ;
     RECT  23.365 38.4 24.433 38.808 ;
     RECT  23.411 39.888 24.433 41.832 ;
     RECT  24.433 38.256 24.505 41.832 ;
     RECT  22.817 43.056 24.505 43.08 ;
     RECT  24.397 18.672 24.515 32.568 ;
     RECT  23.105 4.8 24.517 5.064 ;
     RECT  24.253 15.888 24.541 17.688 ;
     RECT  24.515 18.672 24.541 29.352 ;
     RECT  24.505 38.256 24.611 43.08 ;
     RECT  24.517 4.56 24.613 5.064 ;
     RECT  24.397 6.672 24.613 10.296 ;
     RECT  24.037 11.376 24.613 12.648 ;
     RECT  23.501 33.648 24.613 36.984 ;
     RECT  24.611 38.256 24.613 41.64 ;
     RECT  24.613 4.56 24.659 12.648 ;
     RECT  24.613 2.976 24.709 3 ;
     RECT  24.659 4.56 24.709 5.064 ;
     RECT  24.709 2.976 24.721 5.064 ;
     RECT  24.721 2.832 24.761 5.064 ;
     RECT  24.217 13.728 25.093 14.76 ;
     RECT  24.613 33.648 25.093 41.64 ;
     RECT  24.659 6.144 25.187 12.648 ;
     RECT  24.761 2.832 25.193 3 ;
     RECT  25.093 13.728 25.297 14.808 ;
     RECT  24.541 15.888 25.297 29.352 ;
     RECT  25.187 11.136 25.333 12.648 ;
     RECT  25.297 13.728 25.333 29.352 ;
     RECT  25.187 6.144 25.337 10.104 ;
     RECT  24.515 30.336 25.429 32.568 ;
     RECT  25.093 33.6 25.429 41.64 ;
     RECT  25.333 11.136 25.481 29.352 ;
     RECT  25.481 11.472 25.571 29.352 ;
     RECT  24.611 43.056 25.661 43.08 ;
     RECT  25.571 16.128 25.763 29.352 ;
     RECT  24.761 4.368 25.765 5.064 ;
     RECT  25.337 6.144 25.765 9 ;
     RECT  25.429 30.336 25.765 41.64 ;
     RECT  25.763 16.128 25.769 17.688 ;
     RECT  25.765 30.336 25.805 42.312 ;
     RECT  25.805 30.336 25.811 34.152 ;
     RECT  25.763 18.768 25.859 29.352 ;
     RECT  25.337 10.08 25.877 10.104 ;
     RECT  25.859 19.008 26.089 29.352 ;
     RECT  25.811 30.336 26.089 32.568 ;
     RECT  26.089 19.008 26.093 32.568 ;
     RECT  25.805 35.184 26.099 42.312 ;
     RECT  26.093 19.968 26.165 32.568 ;
     RECT  25.765 4.368 26.243 9 ;
     RECT  26.099 36.816 26.243 42.312 ;
     RECT  26.243 4.368 26.305 7.032 ;
     RECT  26.243 8.256 26.341 9 ;
     RECT  26.341 8.256 26.413 9.048 ;
     RECT  25.811 33.744 26.773 34.152 ;
     RECT  26.099 35.184 26.773 35.592 ;
     RECT  25.193 2.976 26.917 3 ;
     RECT  26.305 4.224 26.917 7.032 ;
     RECT  26.165 25.008 26.989 32.568 ;
     RECT  26.773 33.744 26.989 35.592 ;
     RECT  25.571 11.472 27.013 15.096 ;
     RECT  25.769 16.128 27.013 17.544 ;
     RECT  27.013 11.472 27.061 17.544 ;
     RECT  26.917 18.72 27.061 18.936 ;
     RECT  26.989 25.008 27.061 35.592 ;
     RECT  27.061 11.472 27.097 18.936 ;
     RECT  26.165 19.968 27.097 23.592 ;
     RECT  27.061 25.008 27.109 35.832 ;
     RECT  26.243 36.816 27.109 42.216 ;
     RECT  26.917 2.976 27.248 7.032 ;
     RECT  26.413 8.256 27.248 9.816 ;
     RECT  27.097 11.472 27.248 23.592 ;
     RECT  27.109 25.008 27.248 42.216 ;
     RECT  27.248 0.528 27.352 42.672 ;
     RECT  27.352 0.798 27.544 42.402 ;
     RECT  27.544 3.36 27.683 40.824 ;
     RECT  27.683 3.36 27.821 39.384 ;
     RECT  27.821 3.36 27.827 25.032 ;
     RECT  27.544 42 27.893 42.216 ;
     RECT  27.821 26.208 27.923 39.384 ;
     RECT  27.827 3.936 27.929 25.032 ;
     RECT  27.923 26.208 27.929 37.32 ;
     RECT  27.929 24.24 27.971 25.032 ;
     RECT  27.923 38.784 28.001 39.384 ;
     RECT  27.929 3.936 28.253 9.432 ;
     RECT  27.929 30.288 28.289 37.32 ;
     RECT  27.893 42.192 28.289 42.216 ;
     RECT  27.929 10.416 28.325 23.208 ;
     RECT  28.325 10.416 28.361 17.928 ;
     RECT  28.361 11.712 28.433 17.928 ;
     RECT  27.929 26.208 28.433 29.16 ;
     RECT  28.001 39.216 28.505 39.24 ;
     RECT  27.971 24.384 28.541 25.032 ;
     RECT  28.433 11.712 28.613 17.88 ;
     RECT  28.325 19.008 28.685 23.208 ;
     RECT  28.289 30.288 28.691 37.08 ;
     RECT  28.691 33.504 28.721 37.08 ;
     RECT  28.721 35.424 28.757 35.688 ;
     RECT  28.613 11.712 28.829 16.344 ;
     RECT  28.645 2.784 28.837 2.808 ;
     RECT  28.253 3.936 28.837 5.064 ;
     RECT  27.683 40.56 28.861 40.824 ;
     RECT  28.253 6.384 28.883 9.432 ;
     RECT  28.685 19.344 28.933 23.208 ;
     RECT  28.541 24.384 28.933 24.888 ;
     RECT  28.433 26.208 28.969 29.112 ;
     RECT  28.883 6.384 29.009 9.096 ;
     RECT  28.361 10.416 29.009 10.68 ;
     RECT  28.721 33.504 29.045 34.296 ;
     RECT  28.861 40.56 29.077 40.968 ;
     RECT  28.829 11.712 29.153 12.936 ;
     RECT  29.077 40.56 29.185 41.256 ;
     RECT  28.837 2.784 29.261 5.064 ;
     RECT  28.691 30.288 29.293 32.328 ;
     RECT  28.613 17.472 29.461 17.88 ;
     RECT  28.933 38.208 29.473 38.232 ;
     RECT  29.009 10.608 29.477 10.68 ;
     RECT  28.933 19.344 29.509 24.888 ;
     RECT  29.261 3.36 29.545 5.064 ;
     RECT  29.009 6.384 29.545 9 ;
     RECT  28.757 35.424 29.585 35.448 ;
     RECT  29.185 40.128 29.617 41.256 ;
     RECT  29.545 3.36 29.657 9 ;
     RECT  29.045 33.504 29.693 34.248 ;
     RECT  28.829 14.112 29.701 16.344 ;
     RECT  29.461 17.472 29.725 18.216 ;
     RECT  29.509 19.344 29.725 24.984 ;
     RECT  29.617 40.128 29.761 41.64 ;
     RECT  28.721 36.816 29.797 37.08 ;
     RECT  29.473 38.208 29.797 38.52 ;
     RECT  29.653 2.304 29.801 2.328 ;
     RECT  29.761 39.888 29.801 41.64 ;
     RECT  29.153 12.528 29.891 12.936 ;
     RECT  29.801 40.944 29.905 41.64 ;
     RECT  29.701 14.112 29.941 16.392 ;
     RECT  29.725 17.472 29.941 24.984 ;
     RECT  29.761 35.616 29.977 35.64 ;
     RECT  29.797 36.816 29.977 38.52 ;
     RECT  29.693 33.504 29.987 33.864 ;
     RECT  28.969 26.064 30.035 29.112 ;
     RECT  29.977 35.616 30.035 38.52 ;
     RECT  30.035 26.256 30.085 29.112 ;
     RECT  29.293 30.24 30.085 32.328 ;
     RECT  30.035 36.912 30.085 38.52 ;
     RECT  29.801 39.888 30.085 39.912 ;
     RECT  30.085 36.912 30.125 39.912 ;
     RECT  29.941 14.112 30.131 24.984 ;
     RECT  29.905 40.944 30.131 42.168 ;
     RECT  30.085 26.256 30.161 32.328 ;
     RECT  30.035 35.616 30.179 35.64 ;
     RECT  29.725 11.088 30.227 11.112 ;
     RECT  29.657 6.624 30.229 9 ;
     RECT  29.891 12.624 30.229 12.936 ;
     RECT  30.131 14.112 30.229 14.424 ;
     RECT  30.131 16.032 30.229 24.984 ;
     RECT  30.229 6.624 30.233 9.912 ;
     RECT  29.987 33.504 30.233 33.816 ;
     RECT  30.229 16.032 30.275 25.032 ;
     RECT  30.161 30.24 30.277 32.328 ;
     RECT  30.233 33.504 30.277 33.768 ;
     RECT  30.161 26.256 30.413 29.112 ;
     RECT  30.413 26.256 30.521 26.664 ;
     RECT  30.275 24.96 30.661 25.032 ;
     RECT  29.657 3.36 30.697 5.64 ;
     RECT  30.661 24.96 30.701 25.128 ;
     RECT  30.413 27.696 30.701 29.112 ;
     RECT  30.701 25.104 30.755 25.128 ;
     RECT  30.697 3.072 30.769 5.64 ;
     RECT  30.233 6.672 30.805 9.912 ;
     RECT  30.805 6.672 30.841 10.056 ;
     RECT  30.769 2.208 30.877 5.64 ;
     RECT  30.125 36.912 30.899 39.384 ;
     RECT  30.277 30.24 30.989 33.768 ;
     RECT  30.989 30.24 30.995 32.808 ;
     RECT  30.275 16.032 31.141 23.448 ;
     RECT  30.877 2.112 31.273 5.64 ;
     RECT  30.841 6.672 31.273 10.104 ;
     RECT  31.273 2.112 31.277 10.104 ;
     RECT  30.899 36.912 31.277 37.08 ;
     RECT  30.131 41.616 31.285 42.168 ;
     RECT  31.277 2.112 31.331 6.696 ;
     RECT  31.141 15.792 31.333 23.448 ;
     RECT  30.899 38.112 31.333 39.384 ;
     RECT  30.229 12.624 31.345 14.424 ;
     RECT  31.333 15.408 31.345 23.448 ;
     RECT  31.285 40.944 31.349 42.168 ;
     RECT  31.345 12.624 31.381 23.88 ;
     RECT  31.277 7.68 31.385 10.104 ;
     RECT  31.333 38.112 31.385 39.912 ;
     RECT  31.385 9.744 31.421 10.104 ;
     RECT  31.417 36.288 31.453 36.312 ;
     RECT  31.331 2.208 31.457 5.592 ;
     RECT  31.417 33.84 31.475 33.864 ;
     RECT  30.769 35.04 31.525 35.064 ;
     RECT  31.453 36.096 31.525 36.312 ;
     RECT  31.421 10.08 31.561 10.104 ;
     RECT  30.661 11.184 31.561 11.208 ;
     RECT  31.385 38.112 31.565 39.336 ;
     RECT  31.525 34.08 31.571 36.312 ;
     RECT  31.381 12.192 31.637 24.12 ;
     RECT  31.561 10.08 31.669 11.208 ;
     RECT  31.637 12.192 31.669 12.648 ;
     RECT  31.457 2.784 31.673 5.592 ;
     RECT  30.995 30.24 31.705 32.376 ;
     RECT  31.637 13.68 31.849 24.12 ;
     RECT  31.813 25.152 31.849 25.176 ;
     RECT  30.521 26.496 31.909 26.664 ;
     RECT  31.849 13.68 31.957 25.176 ;
     RECT  30.701 28.416 31.957 29.112 ;
     RECT  31.705 30.144 31.957 32.376 ;
     RECT  31.565 38.112 32.281 38.184 ;
     RECT  32.281 37.968 32.353 38.184 ;
     RECT  31.331 6.672 32.389 6.696 ;
     RECT  31.385 7.68 32.389 8.76 ;
     RECT  31.909 26.352 32.437 27.432 ;
     RECT  31.957 28.416 32.437 32.376 ;
     RECT  32.353 37.68 32.437 38.184 ;
     RECT  31.349 41.616 32.437 42.168 ;
     RECT  31.571 34.08 32.533 35.88 ;
     RECT  32.437 37.44 32.533 38.184 ;
     RECT  31.565 39.312 32.533 39.336 ;
     RECT  32.533 34.08 32.605 38.232 ;
     RECT  32.437 41.184 32.641 42.168 ;
     RECT  31.673 2.784 32.648 3.192 ;
     RECT  31.673 4.176 32.648 5.592 ;
     RECT  32.389 6.672 32.648 8.76 ;
     RECT  31.669 10.08 32.648 12.648 ;
     RECT  31.957 13.68 32.648 25.272 ;
     RECT  32.437 26.352 32.648 32.376 ;
     RECT  32.605 33.84 32.648 38.232 ;
     RECT  32.533 39.216 32.648 39.336 ;
     RECT  32.641 40.416 32.648 42.168 ;
     RECT  32.648 0.528 32.752 42.672 ;
     RECT  32.752 0.798 32.944 42.402 ;
     RECT  32.944 10.32 33.059 10.344 ;
     RECT  32.944 11.664 33.107 30.6 ;
     RECT  32.944 33.264 33.113 41.064 ;
     RECT  33.107 25.488 33.149 30.6 ;
     RECT  33.107 11.664 33.293 24.504 ;
     RECT  33.113 39.84 33.293 41.064 ;
     RECT  33.149 25.488 33.299 28.536 ;
     RECT  33.299 25.68 33.329 28.536 ;
     RECT  33.149 29.52 33.545 30.6 ;
     RECT  33.113 33.264 33.581 38.712 ;
     RECT  33.329 28.512 33.653 28.536 ;
     RECT  33.329 25.68 33.683 27.336 ;
     RECT  33.581 33.264 33.725 37.656 ;
     RECT  33.293 15.648 33.869 24.504 ;
     RECT  33.725 33.264 33.869 36.264 ;
     RECT  32.944 31.632 33.973 31.656 ;
     RECT  33.683 25.68 34.049 26.76 ;
     RECT  34.049 25.68 34.085 26.04 ;
     RECT  33.545 29.52 34.157 29.64 ;
     RECT  34.157 29.52 34.193 29.544 ;
     RECT  33.293 40.56 34.211 41.064 ;
     RECT  33.293 11.664 34.213 14.664 ;
     RECT  34.213 11.52 34.265 14.664 ;
     RECT  34.265 14.352 34.297 14.664 ;
     RECT  33.869 15.648 34.297 23.64 ;
     RECT  32.944 3.264 34.301 5.592 ;
     RECT  33.869 34.704 34.451 36.264 ;
     RECT  34.085 25.68 34.513 25.704 ;
     RECT  33.581 38.688 34.585 38.712 ;
     RECT  34.451 34.8 34.595 36.264 ;
     RECT  34.513 25.632 34.597 25.704 ;
     RECT  33.973 30.96 34.657 31.656 ;
     RECT  34.657 30.96 34.693 32.184 ;
     RECT  33.725 37.392 34.693 37.656 ;
     RECT  34.693 30.768 34.739 32.184 ;
     RECT  34.213 29.184 34.765 29.208 ;
     RECT  32.944 42.192 34.765 42.264 ;
     RECT  32.944 6.672 34.769 9.192 ;
     RECT  34.693 36.48 34.801 37.656 ;
     RECT  34.585 38.688 34.801 39.912 ;
     RECT  34.657 27.984 34.805 28.008 ;
     RECT  34.595 34.8 34.805 35.4 ;
     RECT  34.597 25.152 34.835 25.704 ;
     RECT  34.765 28.992 34.835 29.208 ;
     RECT  34.769 6.672 34.841 9.096 ;
     RECT  34.801 36.48 34.913 39.912 ;
     RECT  34.913 36.48 34.985 37.944 ;
     RECT  34.765 41.376 34.985 42.264 ;
     RECT  34.841 6.672 35.017 8.904 ;
     RECT  34.835 25.152 35.053 25.656 ;
     RECT  35.017 26.88 35.125 26.904 ;
     RECT  34.739 30.768 35.161 31.992 ;
     RECT  35.125 10.128 35.171 10.152 ;
     RECT  34.265 11.52 35.197 13.128 ;
     RECT  34.913 39.36 35.197 39.912 ;
     RECT  35.221 2.64 35.269 2.664 ;
     RECT  34.301 3.936 35.269 5.592 ;
     RECT  34.297 14.352 35.305 23.64 ;
     RECT  35.053 24.864 35.305 25.656 ;
     RECT  35.269 2.64 35.309 5.592 ;
     RECT  35.305 14.352 35.381 25.656 ;
     RECT  34.985 36.48 35.417 37.656 ;
     RECT  35.161 29.472 35.507 31.992 ;
     RECT  33.869 33.264 35.593 33.624 ;
     RECT  35.417 36.48 35.597 37.416 ;
     RECT  35.125 26.88 35.629 27.912 ;
     RECT  35.197 10.416 35.701 13.128 ;
     RECT  34.805 35.376 35.845 35.4 ;
     RECT  35.597 36.48 35.845 36.696 ;
     RECT  35.701 10.416 35.893 13.176 ;
     RECT  35.381 14.352 35.893 25.56 ;
     RECT  35.845 35.376 35.893 36.696 ;
     RECT  35.593 32.976 35.921 33.624 ;
     RECT  35.893 10.416 35.957 25.56 ;
     RECT  35.017 6.576 36.025 8.904 ;
     RECT  35.957 10.416 36.083 25.368 ;
     RECT  35.507 31.632 36.097 31.992 ;
     RECT  35.921 32.976 36.097 33.048 ;
     RECT  35.507 29.472 36.133 30.6 ;
     RECT  35.197 39.36 36.241 40.152 ;
     RECT  36.025 6.576 36.313 9.096 ;
     RECT  36.083 10.416 36.313 25.32 ;
     RECT  35.629 26.64 36.349 27.912 ;
     RECT  36.133 28.944 36.349 30.6 ;
     RECT  36.241 38.736 36.421 40.152 ;
     RECT  35.893 35.136 36.467 36.696 ;
     RECT  36.349 26.64 36.469 30.6 ;
     RECT  36.097 31.632 36.469 33.048 ;
     RECT  35.309 2.784 36.493 5.592 ;
     RECT  36.313 6.576 36.493 25.32 ;
     RECT  34.985 41.616 36.517 41.64 ;
     RECT  36.469 26.64 36.533 33.048 ;
     RECT  36.493 2.784 36.637 25.32 ;
     RECT  36.421 38.016 36.637 40.152 ;
     RECT  36.467 36.24 36.661 36.696 ;
     RECT  36.637 38.016 36.661 40.296 ;
     RECT  36.533 31.44 36.713 33.048 ;
     RECT  36.713 33.024 36.749 33.048 ;
     RECT  36.637 2.544 36.893 25.32 ;
     RECT  36.517 41.52 36.949 41.64 ;
     RECT  36.893 3.936 36.965 25.32 ;
     RECT  36.661 36.24 36.997 40.296 ;
     RECT  36.965 10.704 37.043 25.32 ;
     RECT  37.043 24.624 37.045 25.32 ;
     RECT  36.533 26.64 37.045 29.976 ;
     RECT  36.997 36.24 37.069 40.44 ;
     RECT  36.949 41.52 37.069 41.736 ;
     RECT  36.781 34.512 37.093 34.92 ;
     RECT  37.069 36.24 37.357 41.736 ;
     RECT  36.713 31.44 37.621 31.992 ;
     RECT  37.093 33.6 37.621 34.92 ;
     RECT  37.357 36.24 37.621 42.504 ;
     RECT  37.045 24.624 37.717 29.976 ;
     RECT  37.621 31.008 37.717 31.992 ;
     RECT  36.893 2.544 37.909 2.568 ;
     RECT  37.909 2.352 38.048 2.856 ;
     RECT  36.965 3.936 38.048 9.624 ;
     RECT  37.043 10.704 38.048 23.304 ;
     RECT  37.717 24.624 38.048 31.992 ;
     RECT  37.621 33.6 38.048 42.504 ;
     RECT  38.048 0.528 38.152 42.672 ;
     RECT  38.152 0.798 38.344 42.672 ;
     RECT  38.344 14.4 38.477 27.912 ;
     RECT  38.477 14.496 38.483 27.912 ;
     RECT  38.344 42.48 38.549 42.672 ;
     RECT  38.344 31.44 38.585 31.8 ;
     RECT  38.344 33.072 38.801 41.4 ;
     RECT  38.549 42.624 38.869 42.672 ;
     RECT  38.344 2.112 39.203 13.08 ;
     RECT  38.483 14.496 39.233 27.672 ;
     RECT  38.801 33.072 39.299 33.816 ;
     RECT  39.203 2.112 39.305 2.712 ;
     RECT  38.869 42.624 39.341 42.744 ;
     RECT  39.305 2.112 39.413 2.136 ;
     RECT  38.801 35.52 39.449 41.4 ;
     RECT  39.299 33.072 39.521 33.72 ;
     RECT  39.449 35.712 39.665 41.4 ;
     RECT  38.585 31.776 39.701 31.8 ;
     RECT  39.233 14.64 39.733 27.672 ;
     RECT  38.344 28.944 39.733 29.016 ;
     RECT  39.733 14.64 39.779 29.016 ;
     RECT  39.665 37.248 39.845 41.4 ;
     RECT  39.779 28.944 39.877 29.016 ;
     RECT  39.845 37.248 39.989 40.584 ;
     RECT  39.665 35.712 40.019 36.216 ;
     RECT  39.779 14.64 40.025 27.912 ;
     RECT  39.203 3.696 40.213 13.08 ;
     RECT  40.025 14.64 40.213 24.984 ;
     RECT  40.213 3.696 40.259 24.984 ;
     RECT  39.989 38.112 40.313 40.584 ;
     RECT  40.313 38.784 40.385 40.584 ;
     RECT  40.385 38.832 40.421 40.584 ;
     RECT  40.259 3.696 40.453 23.352 ;
     RECT  40.129 32.592 40.489 32.616 ;
     RECT  39.521 33.696 40.489 33.72 ;
     RECT  40.453 2.928 40.493 23.352 ;
     RECT  40.381 30.72 40.525 30.744 ;
     RECT  40.421 38.832 40.529 40.008 ;
     RECT  40.493 10.032 40.565 23.352 ;
     RECT  40.025 26.208 40.565 27.912 ;
     RECT  40.529 39.024 40.595 39.24 ;
     RECT  40.489 32.592 40.709 33.72 ;
     RECT  40.493 2.928 40.739 9.048 ;
     RECT  39.877 28.944 40.837 29.592 ;
     RECT  40.709 33.024 40.837 33.72 ;
     RECT  40.739 2.928 40.849 6.888 ;
     RECT  40.837 33.024 40.883 33.816 ;
     RECT  40.849 2.064 40.889 6.888 ;
     RECT  40.883 33.792 40.889 33.816 ;
     RECT  40.813 35.232 40.997 35.256 ;
     RECT  40.889 2.064 41.027 2.088 ;
     RECT  40.565 14.448 41.027 23.352 ;
     RECT  40.889 3.888 41.033 6.888 ;
     RECT  40.837 28.32 41.033 29.592 ;
     RECT  41.033 6.624 41.069 6.888 ;
     RECT  41.027 15.072 41.075 23.352 ;
     RECT  40.259 24.384 41.125 24.984 ;
     RECT  40.565 26.208 41.125 27.144 ;
     RECT  41.033 28.464 41.141 29.592 ;
     RECT  41.125 24.384 41.171 27.144 ;
     RECT  40.525 30.72 41.177 30.984 ;
     RECT  41.075 15.456 41.221 23.352 ;
     RECT  41.171 24.384 41.221 25.32 ;
     RECT  41.269 36.48 41.321 36.504 ;
     RECT  40.565 10.032 41.363 13.368 ;
     RECT  41.221 15.456 41.393 25.32 ;
     RECT  41.141 29.568 41.425 29.592 ;
     RECT  41.177 30.72 41.425 30.744 ;
     RECT  41.425 29.568 41.465 30.744 ;
     RECT  41.033 3.888 41.507 5.592 ;
     RECT  41.465 29.568 41.507 30.552 ;
     RECT  40.739 8.256 41.557 9.048 ;
     RECT  41.363 10.032 41.557 11.688 ;
     RECT  41.363 13.056 41.557 13.368 ;
     RECT  41.389 42.192 41.603 42.216 ;
     RECT  41.171 26.304 41.641 27.144 ;
     RECT  41.857 36.912 41.965 36.936 ;
     RECT  40.595 39.216 41.965 39.24 ;
     RECT  41.507 3.936 42.001 5.592 ;
     RECT  41.069 6.624 42.001 6.792 ;
     RECT  41.557 8.256 42.001 11.688 ;
     RECT  42.073 2.064 42.131 2.088 ;
     RECT  42.073 41.712 42.131 41.736 ;
     RECT  41.141 28.464 42.179 28.488 ;
     RECT  42.001 8.208 42.181 11.688 ;
     RECT  41.965 39.216 42.181 39.384 ;
     RECT  42.001 3.936 42.217 6.792 ;
     RECT  42.181 7.968 42.217 11.688 ;
     RECT  41.557 13.056 42.289 14.04 ;
     RECT  42.229 33.792 42.293 33.816 ;
     RECT  42.217 3.936 42.325 11.688 ;
     RECT  42.325 3.936 42.397 12.024 ;
     RECT  42.289 13.056 42.397 14.328 ;
     RECT  42.397 3.936 42.401 14.328 ;
     RECT  41.641 26.304 42.433 27.432 ;
     RECT  41.965 36.912 42.469 37.032 ;
     RECT  42.401 3.984 42.613 14.328 ;
     RECT  41.393 15.456 42.661 25.272 ;
     RECT  42.433 26.256 42.661 27.432 ;
     RECT  42.181 38.688 42.685 39.528 ;
     RECT  42.505 2.256 42.757 2.28 ;
     RECT  41.507 29.568 42.757 30.408 ;
     RECT  42.721 40.656 42.829 40.68 ;
     RECT  42.757 29.568 43.009 30.456 ;
     RECT  42.469 36.912 43.081 37.08 ;
     RECT  42.829 40.56 43.189 40.68 ;
     RECT  42.661 15.456 43.237 27.432 ;
     RECT  43.081 36.864 43.297 37.08 ;
     RECT  42.685 38.16 43.297 39.528 ;
     RECT  42.757 2.256 43.333 2.904 ;
     RECT  42.613 3.984 43.333 14.376 ;
     RECT  43.237 15.408 43.333 27.432 ;
     RECT  43.333 2.064 43.448 2.904 ;
     RECT  43.333 3.984 43.448 28.248 ;
     RECT  43.009 29.568 43.448 30.888 ;
     RECT  42.853 32.544 43.448 32.568 ;
     RECT  43.333 33.84 43.448 33.864 ;
     RECT  43.297 36.864 43.448 39.528 ;
     RECT  43.189 40.56 43.448 40.824 ;
     RECT  42.757 41.904 43.448 42.168 ;
     RECT  43.448 0.528 43.552 42.672 ;
     RECT  43.552 0.798 43.744 42.402 ;
     RECT  43.744 1.584 43.859 9.432 ;
     RECT  43.744 10.752 43.859 11.64 ;
     RECT  43.859 1.584 43.913 2.28 ;
     RECT  43.744 14.208 43.949 37.608 ;
     RECT  43.744 39.072 43.955 41.928 ;
     RECT  43.859 10.848 44.099 11.64 ;
     RECT  43.913 1.584 44.309 2.232 ;
     RECT  43.949 14.208 44.387 35.88 ;
     RECT  44.387 33.84 44.483 35.88 ;
     RECT  43.955 40.752 44.561 41.928 ;
     RECT  43.859 4.176 44.633 9.432 ;
     RECT  44.387 14.208 44.773 32.52 ;
     RECT  44.483 34.848 44.777 35.88 ;
     RECT  44.309 1.632 44.819 2.232 ;
     RECT  44.773 13.872 44.849 32.52 ;
     RECT  44.633 4.176 44.869 9.384 ;
     RECT  44.819 1.68 44.917 2.232 ;
     RECT  44.869 3.312 44.917 9.384 ;
     RECT  44.849 13.872 44.953 23.4 ;
     RECT  44.777 35.04 44.963 35.88 ;
     RECT  44.963 35.136 44.965 35.88 ;
     RECT  43.949 36.864 44.965 37.608 ;
     RECT  43.955 39.072 44.989 39.48 ;
     RECT  44.099 10.848 45.013 11.016 ;
     RECT  44.849 24.48 45.029 32.52 ;
     RECT  44.953 13.728 45.061 23.4 ;
     RECT  45.029 24.48 45.065 30.648 ;
     RECT  44.483 33.84 45.101 33.864 ;
     RECT  44.561 40.752 45.205 41.64 ;
     RECT  45.061 13.296 45.209 23.4 ;
     RECT  44.989 38.592 45.209 39.48 ;
     RECT  44.917 1.68 45.251 9.384 ;
     RECT  44.965 35.136 45.253 37.608 ;
     RECT  45.209 38.592 45.253 39.096 ;
     RECT  45.253 35.136 45.299 39.096 ;
     RECT  45.013 10.752 45.301 11.016 ;
     RECT  45.013 12 45.301 12.024 ;
     RECT  45.065 24.48 45.317 29.304 ;
     RECT  45.205 40.512 45.395 41.64 ;
     RECT  45.301 10.752 45.421 12.024 ;
     RECT  45.209 13.296 45.421 23.352 ;
     RECT  45.029 31.872 45.497 32.52 ;
     RECT  45.395 40.56 45.529 41.64 ;
     RECT  45.421 10.752 45.539 23.352 ;
     RECT  45.251 4.176 45.587 9.384 ;
     RECT  45.529 40.56 45.587 41.88 ;
     RECT  45.317 24.528 45.641 29.304 ;
     RECT  45.497 32.064 45.641 32.52 ;
     RECT  45.299 35.136 45.677 38.808 ;
     RECT  45.587 6.768 45.733 9.384 ;
     RECT  45.539 10.752 45.733 11.356 ;
     RECT  45.065 30.624 45.779 30.648 ;
     RECT  45.641 24.528 45.785 29.16 ;
     RECT  45.539 12.336 45.923 23.352 ;
     RECT  45.587 40.56 46.163 40.584 ;
     RECT  45.677 35.136 46.249 37.896 ;
     RECT  45.251 1.68 46.357 3.096 ;
     RECT  45.587 4.176 46.357 5.592 ;
     RECT  46.249 34.752 46.357 37.896 ;
     RECT  46.357 34.224 46.405 37.896 ;
     RECT  45.733 6.768 46.549 11.356 ;
     RECT  46.357 1.68 46.613 5.592 ;
     RECT  45.923 12.432 46.643 23.352 ;
     RECT  46.643 12.432 46.739 13.416 ;
     RECT  46.357 40.176 46.739 40.2 ;
     RECT  46.613 2.784 46.741 5.592 ;
     RECT  46.549 6.576 46.741 11.356 ;
     RECT  46.405 33.504 46.787 37.896 ;
     RECT  46.741 2.784 46.789 11.356 ;
     RECT  45.785 24.528 46.825 29.064 ;
     RECT  46.789 2.784 46.829 11.448 ;
     RECT  46.789 39.072 46.835 39.096 ;
     RECT  46.825 24.432 46.897 29.064 ;
     RECT  45.641 32.064 46.897 32.328 ;
     RECT  46.897 32.064 46.969 32.616 ;
     RECT  46.969 31.824 47.027 32.616 ;
     RECT  46.981 41.616 47.041 41.64 ;
     RECT  47.041 41.376 47.045 41.64 ;
     RECT  47.027 32.064 47.081 32.616 ;
     RECT  46.787 33.6 47.221 37.896 ;
     RECT  47.221 33.6 47.261 38.76 ;
     RECT  46.897 24.432 47.267 29.208 ;
     RECT  47.261 35.232 47.267 38.76 ;
     RECT  47.267 27.936 47.297 29.208 ;
     RECT  47.261 33.6 47.315 34.152 ;
     RECT  47.267 35.232 47.369 38.184 ;
     RECT  47.267 24.432 47.401 26.664 ;
     RECT  46.643 14.4 47.405 23.352 ;
     RECT  47.081 32.304 47.405 32.616 ;
     RECT  46.573 30.768 47.473 30.792 ;
     RECT  47.369 37.2 47.477 38.184 ;
     RECT  47.473 30.768 47.545 31.032 ;
     RECT  47.545 30.24 47.555 31.032 ;
     RECT  47.405 14.496 47.617 23.352 ;
     RECT  47.401 24.384 47.617 26.664 ;
     RECT  46.829 2.928 47.651 11.448 ;
     RECT  47.651 2.928 47.837 9.912 ;
     RECT  47.651 10.992 47.941 11.448 ;
     RECT  46.739 12.432 47.941 13.08 ;
     RECT  47.405 32.496 48.121 32.616 ;
     RECT  47.315 33.6 48.121 33.624 ;
     RECT  47.941 10.992 48.301 13.08 ;
     RECT  47.617 14.496 48.301 26.664 ;
     RECT  47.297 27.936 48.301 28.776 ;
     RECT  47.555 30.24 48.301 30.264 ;
     RECT  47.369 35.232 48.325 35.64 ;
     RECT  47.477 37.344 48.325 38.184 ;
     RECT  46.613 1.68 48.409 1.752 ;
     RECT  48.301 14.496 48.409 29.112 ;
     RECT  48.301 30.096 48.409 30.264 ;
     RECT  48.121 32.496 48.445 33.624 ;
     RECT  48.325 34.992 48.445 35.64 ;
     RECT  48.445 32.496 48.469 35.64 ;
     RECT  48.301 10.992 48.481 13.32 ;
     RECT  48.409 14.496 48.481 30.264 ;
     RECT  48.481 10.992 48.553 30.264 ;
     RECT  47.045 41.376 48.553 41.4 ;
     RECT  48.553 10.992 48.613 30.456 ;
     RECT  48.469 31.536 48.613 36.072 ;
     RECT  47.893 40.32 48.613 40.344 ;
     RECT  47.837 3.696 48.661 9.912 ;
     RECT  48.613 10.992 48.661 36.072 ;
     RECT  48.325 37.344 48.709 38.232 ;
     RECT  48.613 39.792 48.709 40.344 ;
     RECT  48.409 1.68 48.848 2.328 ;
     RECT  48.661 3.696 48.848 36.072 ;
     RECT  48.709 37.344 48.848 40.344 ;
     RECT  48.553 41.376 48.848 41.448 ;
     RECT  48.848 0.528 48.952 42.672 ;
     RECT  48.952 0.798 49.144 42.402 ;
     RECT  49.144 2.064 49.169 2.328 ;
     RECT  49.144 3.408 49.169 11.016 ;
     RECT  49.169 3.408 49.283 10.872 ;
     RECT  49.283 3.648 49.313 10.872 ;
     RECT  49.144 30.096 49.313 36.072 ;
     RECT  49.313 3.648 49.349 9.816 ;
     RECT  49.144 12 49.379 29.016 ;
     RECT  49.349 3.648 49.385 8.568 ;
     RECT  49.349 9.744 49.385 9.816 ;
     RECT  49.313 31.44 49.421 36.072 ;
     RECT  49.169 2.256 49.457 2.28 ;
     RECT  49.313 10.848 49.523 10.872 ;
     RECT  49.421 31.776 49.565 36.072 ;
     RECT  49.144 41.184 49.565 41.208 ;
     RECT  49.379 12 49.571 26.904 ;
     RECT  49.144 37.344 49.571 40.152 ;
     RECT  49.385 4.176 49.763 8.568 ;
     RECT  49.571 12.096 49.853 26.904 ;
     RECT  49.571 37.344 49.859 39.24 ;
     RECT  49.853 12.236 49.948 26.904 ;
     RECT  49.948 12.24 49.955 26.904 ;
     RECT  49.379 27.984 50.149 29.016 ;
     RECT  49.859 37.344 50.149 37.56 ;
     RECT  49.763 7.776 50.353 8.568 ;
     RECT  49.385 9.792 50.353 9.816 ;
     RECT  50.149 27.984 50.393 29.16 ;
     RECT  49.955 12.768 50.425 26.904 ;
     RECT  50.393 27.984 50.425 29.016 ;
     RECT  50.353 7.776 50.435 9.816 ;
     RECT  49.763 4.176 50.533 6.696 ;
     RECT  49.565 31.776 50.581 33.384 ;
     RECT  49.565 34.464 50.581 36.072 ;
     RECT  50.581 31.776 50.627 36.072 ;
     RECT  49.859 38.592 50.641 39.24 ;
     RECT  50.627 31.776 50.645 34.152 ;
     RECT  50.533 3.552 50.713 6.696 ;
     RECT  50.645 31.776 50.713 33.576 ;
     RECT  50.629 41.232 50.713 41.4 ;
     RECT  50.713 40.944 50.717 41.4 ;
     RECT  50.713 31.104 50.725 33.576 ;
     RECT  50.641 38.592 50.749 39.672 ;
     RECT  50.725 30.816 50.773 33.576 ;
     RECT  50.627 35.232 50.785 36.072 ;
     RECT  50.149 37.056 50.785 37.56 ;
     RECT  50.749 38.592 50.789 39.768 ;
     RECT  50.789 38.688 50.819 39.768 ;
     RECT  50.713 2.832 50.821 6.696 ;
     RECT  50.435 7.776 50.821 8.568 ;
     RECT  50.819 38.688 50.825 39.672 ;
     RECT  50.785 35.232 50.933 37.56 ;
     RECT  50.933 36.384 50.969 37.56 ;
     RECT  50.425 12.768 51.001 29.016 ;
     RECT  51.001 12.624 51.037 29.016 ;
     RECT  50.717 40.944 51.077 41.256 ;
     RECT  50.435 9.696 51.217 9.816 ;
     RECT  50.725 10.8 51.217 10.824 ;
     RECT  50.969 36.528 51.253 37.56 ;
     RECT  51.217 9.696 51.289 10.824 ;
     RECT  51.253 36.528 51.329 37.608 ;
     RECT  51.329 36.624 51.365 37.608 ;
     RECT  51.289 9.696 51.493 11.304 ;
     RECT  51.037 12.528 51.493 29.016 ;
     RECT  50.821 2.832 51.509 8.568 ;
     RECT  51.509 3.168 51.541 8.568 ;
     RECT  51.493 9.696 51.541 29.016 ;
     RECT  50.933 35.232 51.689 35.352 ;
     RECT  51.541 3.168 51.829 29.016 ;
     RECT  50.773 30.432 51.829 33.576 ;
     RECT  51.077 41.232 51.865 41.256 ;
     RECT  51.829 3.168 51.869 33.576 ;
     RECT  51.869 8.256 51.875 33.576 ;
     RECT  51.875 10.128 51.905 33.384 ;
     RECT  51.905 10.128 51.971 33.336 ;
     RECT  51.971 29.952 52.049 33.336 ;
     RECT  51.869 3.168 52.115 7.224 ;
     RECT  51.365 36.624 52.121 37.56 ;
     RECT  51.689 35.232 52.261 35.256 ;
     RECT  51.865 41.232 52.261 41.4 ;
     RECT  52.261 34.944 52.301 35.256 ;
     RECT  52.301 34.944 52.307 34.968 ;
     RECT  50.825 38.688 52.333 38.712 ;
     RECT  52.333 38.688 52.405 39.288 ;
     RECT  52.049 29.952 52.451 30.696 ;
     RECT  52.261 41.136 52.453 41.4 ;
     RECT  52.453 40.56 52.499 41.4 ;
     RECT  52.405 38.544 52.621 39.288 ;
     RECT  52.499 40.56 52.621 41.16 ;
     RECT  52.115 6.672 52.625 7.224 ;
     RECT  52.621 38.544 52.625 41.16 ;
     RECT  52.121 37.392 52.661 37.56 ;
     RECT  52.625 39.648 52.697 41.16 ;
     RECT  52.661 37.392 52.769 37.416 ;
     RECT  52.453 34.848 52.873 34.872 ;
     RECT  52.625 6.768 52.885 7.224 ;
     RECT  51.875 8.256 52.885 9.144 ;
     RECT  52.873 34.752 52.945 34.872 ;
     RECT  52.697 40.992 52.949 41.16 ;
     RECT  51.971 10.128 52.981 28.584 ;
     RECT  52.945 34.512 52.981 34.872 ;
     RECT  52.981 34.416 53.021 34.872 ;
     RECT  52.949 40.992 53.021 41.016 ;
     RECT  53.021 34.416 53.027 34.776 ;
     RECT  52.451 30.432 53.029 30.696 ;
     RECT  52.049 31.68 53.029 33.336 ;
     RECT  52.625 38.544 53.129 38.568 ;
     RECT  52.115 3.168 53.377 5.592 ;
     RECT  53.029 30.432 53.449 33.336 ;
     RECT  53.377 2.64 53.593 5.592 ;
     RECT  52.885 6.768 53.593 9.144 ;
     RECT  53.449 30.144 53.605 33.336 ;
     RECT  53.593 2.64 53.653 9.144 ;
     RECT  52.981 10.128 53.653 28.728 ;
     RECT  52.697 39.648 53.797 39.912 ;
     RECT  53.629 36.912 53.941 36.936 ;
     RECT  53.605 29.856 54.097 33.336 ;
     RECT  53.027 34.512 54.133 34.776 ;
     RECT  53.773 35.808 54.133 35.832 ;
     RECT  53.797 39.648 54.169 40.152 ;
     RECT  53.653 2.64 54.248 28.728 ;
     RECT  54.097 29.856 54.248 33.384 ;
     RECT  54.133 34.512 54.248 35.832 ;
     RECT  53.941 36.912 54.248 36.984 ;
     RECT  54.169 38.784 54.248 40.152 ;
     RECT  54.248 0.528 54.352 42.672 ;
     RECT  54.352 0.798 54.544 42.402 ;
     RECT  54.544 35.472 54.641 35.496 ;
     RECT  54.544 2.736 54.659 33.384 ;
     RECT  54.659 8.448 54.713 33.384 ;
     RECT  54.713 10.32 54.785 28.872 ;
     RECT  54.785 10.32 54.821 26.856 ;
     RECT  54.821 10.32 54.857 26.376 ;
     RECT  54.659 2.736 54.893 7.416 ;
     RECT  54.544 36.48 54.995 39.864 ;
     RECT  54.995 38.928 55.037 39.864 ;
     RECT  54.893 3.168 55.331 7.416 ;
     RECT  54.785 28.416 55.331 28.872 ;
     RECT  54.995 36.48 55.331 37.32 ;
     RECT  55.037 39.84 55.331 39.864 ;
     RECT  55.331 36.816 55.475 37.32 ;
     RECT  55.331 4.08 55.571 5.832 ;
     RECT  55.475 36.816 55.577 36.84 ;
     RECT  55.573 34.944 55.619 34.968 ;
     RECT  55.331 6.96 55.645 7.416 ;
     RECT  54.713 8.448 55.645 9.288 ;
     RECT  55.331 28.416 55.789 28.536 ;
     RECT  54.713 29.856 55.825 33.384 ;
     RECT  54.857 10.32 55.861 26.328 ;
     RECT  55.825 29.76 55.909 33.384 ;
     RECT  55.645 6.96 55.957 9.288 ;
     RECT  55.861 10.32 55.957 26.472 ;
     RECT  55.957 6.96 55.969 26.472 ;
     RECT  55.969 6.96 55.973 27.24 ;
     RECT  55.909 29.76 55.973 33.816 ;
     RECT  55.973 14.976 56.005 27.24 ;
     RECT  55.789 28.32 56.005 28.536 ;
     RECT  55.973 29.76 56.045 31.272 ;
     RECT  55.973 6.96 56.261 13.656 ;
     RECT  56.045 29.76 56.297 29.784 ;
     RECT  56.005 14.976 56.333 28.536 ;
     RECT  55.973 32.4 56.387 33.816 ;
     RECT  55.897 2.832 56.437 3.048 ;
     RECT  56.333 15.36 56.513 28.536 ;
     RECT  56.437 2.592 56.579 3.048 ;
     RECT  56.437 36.384 56.725 36.408 ;
     RECT  56.513 24.336 56.941 28.536 ;
     RECT  56.261 7.296 56.945 13.656 ;
     RECT  56.725 35.424 56.945 36.408 ;
     RECT  56.387 32.448 56.981 33.816 ;
     RECT  56.981 32.544 57.049 33.816 ;
     RECT  56.941 24.336 57.053 28.68 ;
     RECT  56.945 35.424 57.053 35.448 ;
     RECT  57.013 14.16 57.089 14.28 ;
     RECT  57.053 27.312 57.089 28.68 ;
     RECT  55.571 4.176 57.125 5.832 ;
     RECT  56.513 15.36 57.125 23.304 ;
     RECT  57.089 14.208 57.203 14.28 ;
     RECT  56.579 3.024 57.265 3.048 ;
     RECT  57.125 4.176 57.265 4.2 ;
     RECT  57.125 5.232 57.265 5.832 ;
     RECT  56.045 31.248 57.337 31.272 ;
     RECT  57.397 29.904 57.445 29.928 ;
     RECT  57.337 31.152 57.445 31.272 ;
     RECT  57.203 14.256 57.481 14.28 ;
     RECT  57.125 15.36 57.481 19.416 ;
     RECT  57.089 27.552 57.481 28.68 ;
     RECT  57.445 29.904 57.481 31.272 ;
     RECT  57.481 27.552 57.539 31.272 ;
     RECT  57.265 3.024 57.557 4.2 ;
     RECT  57.125 20.4 57.589 23.304 ;
     RECT  57.053 24.336 57.589 26.328 ;
     RECT  56.945 7.296 57.635 13.176 ;
     RECT  57.265 5.232 57.665 6.024 ;
     RECT  57.589 20.4 57.665 26.328 ;
     RECT  57.589 36.48 57.773 36.504 ;
     RECT  57.635 9.744 57.809 13.176 ;
     RECT  57.665 24.624 57.923 26.328 ;
     RECT  57.049 32.544 57.949 34.248 ;
     RECT  57.539 29.376 57.973 31.272 ;
     RECT  57.949 32.496 57.973 34.248 ;
     RECT  57.809 9.744 58.061 13.08 ;
     RECT  57.973 29.376 58.163 34.248 ;
     RECT  57.949 36.432 58.163 36.456 ;
     RECT  57.635 7.296 58.169 8.76 ;
     RECT  58.061 9.888 58.169 13.08 ;
     RECT  57.665 5.232 58.205 5.64 ;
     RECT  58.169 11.904 58.205 13.08 ;
     RECT  57.557 3.216 58.211 4.2 ;
     RECT  57.923 26.304 58.237 26.328 ;
     RECT  57.539 27.552 58.237 28.392 ;
     RECT  58.169 9.888 58.241 10.296 ;
     RECT  58.163 33.168 58.273 34.248 ;
     RECT  58.205 5.232 58.277 5.592 ;
     RECT  58.163 29.376 58.307 32.184 ;
     RECT  57.481 14.256 58.309 19.416 ;
     RECT  58.169 8.064 58.313 8.76 ;
     RECT  58.273 33.168 58.349 34.824 ;
     RECT  58.309 14.208 58.405 19.416 ;
     RECT  58.349 33.648 58.457 34.824 ;
     RECT  58.237 26.304 58.561 28.392 ;
     RECT  58.405 14.16 58.633 19.416 ;
     RECT  57.665 20.4 58.777 23.64 ;
     RECT  57.923 24.624 58.777 25.176 ;
     RECT  58.205 11.952 59.125 13.08 ;
     RECT  59.101 35.808 59.269 35.832 ;
     RECT  58.313 8.064 59.353 8.568 ;
     RECT  58.241 9.888 59.353 10.104 ;
     RECT  59.353 8.064 59.365 10.104 ;
     RECT  58.307 29.568 59.389 32.184 ;
     RECT  58.457 33.648 59.389 34.2 ;
     RECT  58.277 5.28 59.461 5.592 ;
     RECT  58.561 26.304 59.605 28.536 ;
     RECT  58.211 3.84 59.648 4.2 ;
     RECT  59.461 5.28 59.648 5.64 ;
     RECT  58.261 6.816 59.648 6.84 ;
     RECT  59.365 7.92 59.648 10.104 ;
     RECT  59.125 11.952 59.648 13.128 ;
     RECT  58.633 14.112 59.648 19.416 ;
     RECT  58.777 20.4 59.648 25.176 ;
     RECT  59.605 26.256 59.648 28.536 ;
     RECT  59.389 29.568 59.648 34.2 ;
     RECT  59.269 35.808 59.648 36.312 ;
     RECT  59.648 0.528 59.752 42.672 ;
     RECT  59.752 0.798 59.944 42.402 ;
     RECT  59.944 20.4 59.969 35.928 ;
     RECT  59.944 12.528 60.083 19.368 ;
     RECT  60.083 12.528 60.149 19.32 ;
     RECT  59.969 28.176 60.227 35.928 ;
     RECT  59.944 5.472 60.329 7.464 ;
     RECT  60.329 5.568 60.365 7.464 ;
     RECT  60.149 12.528 60.365 19.032 ;
     RECT  60.365 5.568 60.419 7.368 ;
     RECT  59.944 8.448 60.473 11.4 ;
     RECT  60.227 28.416 60.473 35.928 ;
     RECT  60.473 10.56 60.509 11.4 ;
     RECT  60.473 8.544 60.545 9.336 ;
     RECT  60.419 5.568 60.617 6.36 ;
     RECT  60.545 9.312 60.653 9.336 ;
     RECT  60.419 7.344 60.689 7.368 ;
     RECT  59.944 3.84 60.761 4.2 ;
     RECT  59.969 20.4 60.797 27.144 ;
     RECT  60.473 34.752 60.833 35.928 ;
     RECT  60.797 21.504 60.905 27.144 ;
     RECT  60.473 28.416 61.013 33.48 ;
     RECT  60.797 20.4 61.085 20.424 ;
     RECT  61.013 28.416 61.121 33.048 ;
     RECT  60.365 12.528 61.157 18.984 ;
     RECT  60.833 35.424 61.229 35.928 ;
     RECT  60.905 22.752 61.285 27.144 ;
     RECT  61.121 28.416 61.285 28.44 ;
     RECT  61.285 22.752 61.373 28.44 ;
     RECT  60.617 5.568 61.405 5.736 ;
     RECT  61.405 5.472 61.573 5.736 ;
     RECT  61.121 29.52 61.589 33.048 ;
     RECT  60.761 3.84 61.619 3.864 ;
     RECT  61.157 14.592 61.697 18.984 ;
     RECT  61.573 8.832 61.769 8.856 ;
     RECT  60.509 10.8 61.805 11.4 ;
     RECT  61.157 12.528 61.841 13.56 ;
     RECT  61.697 14.64 61.945 18.984 ;
     RECT  61.841 12.912 61.985 13.56 ;
     RECT  61.945 14.64 61.985 19.752 ;
     RECT  60.905 21.504 62.005 21.768 ;
     RECT  61.373 22.752 62.005 27.816 ;
     RECT  62.005 21.504 62.053 27.816 ;
     RECT  61.229 35.424 62.053 35.832 ;
     RECT  62.053 21.408 62.125 27.816 ;
     RECT  61.573 5.04 62.129 5.736 ;
     RECT  61.985 19.248 62.129 19.752 ;
     RECT  61.837 9.12 62.149 9.144 ;
     RECT  62.053 35.136 62.149 35.832 ;
     RECT  61.669 6.816 62.165 6.84 ;
     RECT  62.125 20.976 62.195 27.816 ;
     RECT  61.985 13.008 62.237 13.56 ;
     RECT  61.837 7.968 62.309 7.992 ;
     RECT  61.985 14.64 62.309 18.216 ;
     RECT  62.195 23.52 62.309 27.816 ;
     RECT  62.149 34.32 62.377 35.832 ;
     RECT  62.129 5.04 62.525 5.064 ;
     RECT  62.149 9.12 62.525 9.336 ;
     RECT  62.377 34.32 62.561 36.072 ;
     RECT  62.561 34.32 62.593 34.344 ;
     RECT  62.309 14.64 62.597 17.688 ;
     RECT  62.561 35.376 62.633 36.072 ;
     RECT  62.525 9.312 62.705 9.336 ;
     RECT  62.597 15.792 62.705 17.688 ;
     RECT  62.237 13.056 62.725 13.56 ;
     RECT  62.597 14.64 62.725 14.664 ;
     RECT  61.589 29.52 62.725 32.52 ;
     RECT  62.195 21.408 62.849 22.296 ;
     RECT  62.725 29.52 62.849 32.76 ;
     RECT  62.725 13.056 62.957 14.664 ;
     RECT  62.849 29.52 63.013 31.944 ;
     RECT  62.309 23.52 63.029 27.624 ;
     RECT  63.029 23.52 63.065 26.232 ;
     RECT  63.013 28.848 63.065 31.944 ;
     RECT  61.805 10.8 63.133 10.824 ;
     RECT  62.849 21.408 63.137 21.576 ;
     RECT  63.065 23.52 63.173 26.136 ;
     RECT  63.029 27.312 63.173 27.624 ;
     RECT  63.133 10.8 63.203 11.304 ;
     RECT  63.173 23.52 63.209 25.128 ;
     RECT  62.633 35.712 63.209 36.072 ;
     RECT  62.129 19.584 63.241 19.752 ;
     RECT  63.137 21.408 63.241 21.432 ;
     RECT  63.065 30.192 63.251 31.944 ;
     RECT  63.241 19.584 63.253 21.432 ;
     RECT  63.173 27.36 63.281 27.624 ;
     RECT  63.251 30.192 63.281 31.368 ;
     RECT  63.203 10.8 63.317 10.824 ;
     RECT  62.957 13.344 63.317 14.664 ;
     RECT  63.281 31.344 63.317 31.368 ;
     RECT  63.209 36.048 63.317 36.072 ;
     RECT  63.253 19.2 63.353 21.432 ;
     RECT  63.209 23.616 63.353 25.128 ;
     RECT  63.173 26.112 63.353 26.136 ;
     RECT  63.065 29.184 63.389 29.208 ;
     RECT  63.281 30.192 63.389 30.216 ;
     RECT  63.353 20.112 63.461 21.432 ;
     RECT  63.461 20.112 63.497 20.952 ;
     RECT  63.353 24.768 63.497 25.128 ;
     RECT  63.281 27.36 63.533 27.384 ;
     RECT  63.353 23.616 63.677 23.64 ;
     RECT  62.705 15.792 63.745 17.064 ;
     RECT  63.493 18.72 63.745 18.792 ;
     RECT  62.593 34.176 63.781 34.344 ;
     RECT  63.781 34.128 63.827 34.344 ;
     RECT  63.497 20.496 63.875 20.952 ;
     RECT  63.317 14.208 63.889 14.664 ;
     RECT  63.889 14.208 63.893 14.808 ;
     RECT  63.853 34.464 63.923 34.872 ;
     RECT  63.241 33.072 63.965 33.096 ;
     RECT  63.893 14.256 64.001 14.808 ;
     RECT  64.001 14.784 64.037 14.808 ;
     RECT  64.105 9.648 64.163 9.672 ;
     RECT  63.497 24.768 64.181 24.792 ;
     RECT  63.875 20.928 64.259 20.952 ;
     RECT  64.249 7.968 64.307 7.992 ;
     RECT  64.165 5.664 64.309 5.688 ;
     RECT  64.309 5.088 64.361 5.688 ;
     RECT  64.213 6.816 64.547 6.84 ;
     RECT  63.745 15.792 64.573 18.792 ;
     RECT  64.361 5.664 64.595 5.688 ;
     RECT  64.573 15.696 64.62 18.792 ;
     RECT  63.923 34.464 64.62 34.584 ;
    LAYER M5 ;
     RECT  32.352 0.144 32.376 0.235 ;
     RECT  38.832 0.144 38.856 0.517 ;
     RECT  38.04 0.517 38.856 0.555 ;
     RECT  0.24 0.517 0.36 0.787 ;
     RECT  5.64 0.517 5.76 0.787 ;
     RECT  11.04 0.517 11.16 0.787 ;
     RECT  16.44 0.517 16.56 0.787 ;
     RECT  21.84 0.517 21.96 0.787 ;
     RECT  27.24 0.517 27.36 0.787 ;
     RECT  32.64 0.517 32.76 0.787 ;
     RECT  43.44 0.517 43.56 0.787 ;
     RECT  48.84 0.517 48.96 0.787 ;
     RECT  54.24 0.517 54.36 0.787 ;
     RECT  59.64 0.517 59.76 0.787 ;
     RECT  13.056 0.821 13.08 0.899 ;
     RECT  16.44 0.787 16.752 1.093 ;
     RECT  14.544 0.821 14.568 1.139 ;
     RECT  11.04 0.787 11.352 1.141 ;
     RECT  16.44 1.093 17.64 1.285 ;
     RECT  10.944 1.141 11.352 1.397 ;
     RECT  15.648 1.285 17.64 1.397 ;
     RECT  12.768 1.237 12.792 1.451 ;
     RECT  15.648 1.397 17.736 1.451 ;
     RECT  15.888 1.451 17.736 1.475 ;
     RECT  10.128 1.397 11.352 1.523 ;
     RECT  11.04 1.523 11.352 1.525 ;
     RECT  43.44 0.787 43.752 1.573 ;
     RECT  43.44 1.573 44.28 1.621 ;
     RECT  43.44 1.621 44.808 1.669 ;
     RECT  8.256 1.669 8.28 1.765 ;
     RECT  48.84 0.787 49.152 1.973 ;
     RECT  43.44 1.669 45.576 2.005 ;
     RECT  47.376 1.717 47.4 2.027 ;
     RECT  5.64 0.787 5.952 2.037 ;
     RECT  8.256 1.765 8.376 2.037 ;
     RECT  43.44 2.005 46.056 2.037 ;
     RECT  8.256 2.037 8.904 2.091 ;
     RECT  43.344 2.037 46.056 2.091 ;
     RECT  40.992 2.037 41.016 2.099 ;
     RECT  42.096 2.037 42.12 2.099 ;
     RECT  43.344 2.091 44.28 2.099 ;
     RECT  48.72 1.973 49.152 2.099 ;
     RECT  38.04 0.555 38.352 2.101 ;
     RECT  20.496 2.149 20.52 2.197 ;
     RECT  8.352 2.091 8.904 2.229 ;
     RECT  43.344 2.099 43.848 2.229 ;
     RECT  5.04 2.037 6.264 2.243 ;
     RECT  20.064 2.197 20.52 2.245 ;
     RECT  8.352 2.229 9.048 2.291 ;
     RECT  12.912 2.229 12.936 2.291 ;
     RECT  42.72 2.229 43.848 2.291 ;
     RECT  15.888 1.475 17.64 2.339 ;
     RECT  38.04 2.101 39.192 2.341 ;
     RECT  11.04 1.525 11.448 2.485 ;
     RECT  19.968 2.245 20.52 2.485 ;
     RECT  37.92 2.341 39.192 2.533 ;
     RECT  10.848 2.485 11.448 2.539 ;
     RECT  19.104 2.485 20.52 2.539 ;
     RECT  11.04 2.539 11.448 2.613 ;
     RECT  14.208 2.581 14.232 2.613 ;
     RECT  54.24 0.787 54.552 2.629 ;
     RECT  11.04 2.613 12.504 2.675 ;
     RECT  19.968 2.539 20.52 2.677 ;
     RECT  21.84 0.787 22.152 2.677 ;
     RECT  37.008 2.533 39.192 2.677 ;
     RECT  5.52 2.243 6.264 2.725 ;
     RECT  53.424 2.629 54.552 2.725 ;
     RECT  19.968 2.677 20.568 2.731 ;
     RECT  21.648 2.677 22.824 2.731 ;
     RECT  35.232 2.629 35.256 2.731 ;
     RECT  37.008 2.677 39.288 2.731 ;
     RECT  31.296 2.101 31.32 2.773 ;
     RECT  32.64 0.787 32.952 2.773 ;
     RECT  14.208 2.613 14.712 2.795 ;
     RECT  21.648 2.731 22.344 2.805 ;
     RECT  56.544 2.581 56.568 2.805 ;
     RECT  15.888 2.339 16.872 2.819 ;
     RECT  45.552 2.091 45.576 2.819 ;
     RECT  1.68 2.773 1.704 2.859 ;
     RECT  14.208 2.795 14.232 2.859 ;
     RECT  19.968 2.731 20.52 2.859 ;
     RECT  28.656 2.773 28.872 2.859 ;
     RECT  31.296 2.773 32.952 2.859 ;
     RECT  21.552 2.805 22.344 2.867 ;
     RECT  51.456 2.805 51.48 2.867 ;
     RECT  55.92 2.805 56.568 2.869 ;
     RECT  40.464 2.869 40.488 2.963 ;
     RECT  55.92 2.869 57.144 3.059 ;
     RECT  27.24 0.787 27.552 3.125 ;
     RECT  48.84 2.099 49.152 3.125 ;
     RECT  53.424 2.725 54.744 3.157 ;
     RECT  8.352 2.291 8.904 3.179 ;
     RECT  47.088 3.109 47.112 3.179 ;
     RECT  18.24 3.157 18.264 3.243 ;
     RECT  35.424 3.109 35.448 3.243 ;
     RECT  3.6 2.245 3.624 3.253 ;
     RECT  28.848 2.859 28.872 3.299 ;
     RECT  53.424 3.157 55.32 3.299 ;
     RECT  36.816 3.189 36.84 3.301 ;
     RECT  58.176 3.205 58.2 3.301 ;
     RECT  57.552 3.301 58.2 3.307 ;
     RECT  33.936 3.253 33.96 3.347 ;
     RECT  44.88 3.253 45.24 3.347 ;
     RECT  5.52 2.725 6.84 3.349 ;
     RECT  3.168 3.253 3.624 3.381 ;
     RECT  27.24 3.125 27.816 3.381 ;
     RECT  2.256 3.381 3.624 3.397 ;
     RECT  5.52 3.349 6.984 3.397 ;
     RECT  2.256 3.397 6.984 3.435 ;
     RECT  12.384 2.675 12.504 3.435 ;
     RECT  53.76 3.299 55.32 3.435 ;
     RECT  57.552 3.307 57.672 3.435 ;
     RECT  26.928 3.381 27.816 3.443 ;
     RECT  31.296 2.859 31.32 3.443 ;
     RECT  43.44 2.291 43.848 3.443 ;
     RECT  46.368 3.253 46.392 3.443 ;
     RECT  3.936 3.435 6.984 3.445 ;
     RECT  8.352 3.179 8.664 3.445 ;
     RECT  37.92 2.731 39.192 3.539 ;
     RECT  36.72 3.301 36.84 3.627 ;
     RECT  52.416 3.125 52.44 3.635 ;
     RECT  48.84 3.125 49.272 3.637 ;
     RECT  19.968 2.859 20.424 3.683 ;
     RECT  47.616 3.637 49.272 3.691 ;
     RECT  3.936 3.445 8.664 3.731 ;
     RECT  47.616 3.691 49.152 3.755 ;
     RECT  29.424 3.733 29.448 3.819 ;
     RECT  45.216 3.347 45.24 3.819 ;
     RECT  50.544 3.509 51.336 3.819 ;
     RECT  40.416 3.765 40.44 3.827 ;
     RECT  19.968 3.683 19.992 3.829 ;
     RECT  3.936 3.731 7.176 3.875 ;
     RECT  15.888 2.819 16.752 3.925 ;
     RECT  37.92 3.539 38.352 3.925 ;
     RECT  4.368 3.875 7.176 3.947 ;
     RECT  39.408 3.877 40.248 3.947 ;
     RECT  41.472 3.877 41.496 3.947 ;
     RECT  57.648 3.435 57.672 3.947 ;
     RECT  2.256 3.435 2.808 3.971 ;
     RECT  4.368 3.947 7.032 4.011 ;
     RECT  24.72 3.925 24.744 4.011 ;
     RECT  37.632 3.925 38.352 4.011 ;
     RECT  13.728 3.685 13.752 4.021 ;
     RECT  59.64 0.787 59.952 4.021 ;
     RECT  53.76 3.435 54.552 4.075 ;
     RECT  5.64 4.011 6.888 4.115 ;
     RECT  12.864 4.021 13.752 4.115 ;
     RECT  50.544 3.819 51.288 4.115 ;
     RECT  54.144 4.075 54.552 4.115 ;
     RECT  59.136 4.021 59.952 4.115 ;
     RECT  11.04 2.675 11.352 4.117 ;
     RECT  59.64 4.115 59.952 4.117 ;
     RECT  32.64 2.859 32.952 4.149 ;
     RECT  31.968 4.149 32.952 4.211 ;
     RECT  36.096 4.117 36.12 4.213 ;
     RECT  43.44 3.443 43.752 4.261 ;
     RECT  35.472 4.213 36.12 4.267 ;
     RECT  15.504 3.925 16.752 4.277 ;
     RECT  21.552 2.867 22.152 4.277 ;
     RECT  50.544 4.115 50.808 4.331 ;
     RECT  10.848 4.117 11.352 4.341 ;
     RECT  8.208 3.731 8.664 4.405 ;
     RECT  10.128 4.341 11.352 4.405 ;
     RECT  2.256 3.971 2.28 4.453 ;
     RECT  15.504 4.277 16.872 4.453 ;
     RECT  8.208 4.405 11.352 4.459 ;
     RECT  12.96 4.115 13.752 4.459 ;
     RECT  10.224 4.459 11.352 4.469 ;
     RECT  5.64 4.115 6.696 4.499 ;
     RECT  21.408 4.277 22.152 4.501 ;
     RECT  54.24 4.115 54.552 4.501 ;
     RECT  55.536 4.021 56.472 4.501 ;
     RECT  8.208 4.459 9.192 4.523 ;
     RECT  10.224 4.469 11.448 4.523 ;
     RECT  10.848 4.523 11.448 4.533 ;
     RECT  15.456 4.453 16.872 4.533 ;
     RECT  13.056 4.459 13.752 4.587 ;
     RECT  21.12 4.501 22.872 4.587 ;
     RECT  59.64 4.117 60.072 4.587 ;
     RECT  24.528 4.533 24.552 4.595 ;
     RECT  19.152 3.829 19.992 4.597 ;
     RECT  46.272 4.533 46.296 4.643 ;
     RECT  18.72 4.597 19.992 4.691 ;
     RECT  37.92 4.011 38.352 4.725 ;
     RECT  39.408 3.947 40.2 4.725 ;
     RECT  10.848 4.533 11.544 4.739 ;
     RECT  42.72 4.261 43.752 4.739 ;
     RECT  36 4.267 36.12 4.789 ;
     RECT  13.392 4.587 13.752 4.837 ;
     RECT  13.392 4.837 14.232 4.843 ;
     RECT  52.704 4.789 52.728 4.843 ;
     RECT  4.368 4.011 4.392 4.917 ;
     RECT  15.456 4.533 17.112 4.917 ;
     RECT  34.416 4.789 34.44 4.933 ;
     RECT  47.856 3.755 49.152 4.933 ;
     RECT  50.4 4.533 50.424 4.933 ;
     RECT  10.848 4.739 11.496 4.979 ;
     RECT  32.64 4.211 32.952 4.981 ;
     RECT  1.728 4.453 2.28 5.027 ;
     RECT  8.208 4.523 8.52 5.029 ;
     RECT  34.416 4.933 35.016 5.035 ;
     RECT  52.032 4.933 52.488 5.035 ;
     RECT  13.728 4.843 14.232 5.045 ;
     RECT  15.408 4.917 17.112 5.045 ;
     RECT  13.728 5.045 17.112 5.077 ;
     RECT  1.728 5.027 2.088 5.099 ;
     RECT  32.64 4.981 33.192 5.099 ;
     RECT  30.24 4.149 30.36 5.109 ;
     RECT  13.728 5.077 17.64 5.123 ;
     RECT  43.152 4.739 43.752 5.125 ;
     RECT  19.104 4.691 19.992 5.171 ;
     RECT  41.568 4.501 41.592 5.171 ;
     RECT  37.92 4.725 40.2 5.173 ;
     RECT  47.856 4.933 50.424 5.173 ;
     RECT  37.488 5.173 40.2 5.219 ;
     RECT  36 4.789 36.456 5.237 ;
     RECT  7.728 5.029 8.52 5.267 ;
     RECT  32.64 5.099 32.952 5.269 ;
     RECT  30.24 5.109 30.984 5.301 ;
     RECT  26.208 4.501 26.232 5.315 ;
     RECT  35.808 5.237 36.456 5.315 ;
     RECT  19.104 5.171 19.176 5.363 ;
     RECT  0.24 0.787 0.552 5.365 ;
     RECT  3.504 4.917 4.392 5.365 ;
     RECT  5.64 4.499 5.952 5.365 ;
     RECT  30.24 5.301 31.512 5.429 ;
     RECT  32.496 5.269 32.952 5.429 ;
     RECT  3.504 5.365 5.952 5.459 ;
     RECT  30.24 5.429 32.952 5.459 ;
     RECT  40.416 5.237 41.352 5.459 ;
     RECT  52.464 5.035 52.488 5.483 ;
     RECT  36.24 5.315 36.456 5.493 ;
     RECT  37.488 5.219 39.336 5.493 ;
     RECT  54.24 4.501 56.472 5.493 ;
     RECT  34.416 5.035 34.44 5.507 ;
     RECT  54.144 5.493 56.472 5.509 ;
     RECT  30.24 5.459 31.32 5.555 ;
     RECT  3.504 5.459 4.152 5.557 ;
     RECT  9.696 5.429 9.72 5.605 ;
     RECT  30.24 5.555 30.264 5.605 ;
     RECT  43.152 5.125 44.568 5.605 ;
     RECT  46.128 4.933 46.152 5.605 ;
     RECT  54.144 5.509 57.432 5.611 ;
     RECT  47.808 5.173 50.424 5.621 ;
     RECT  64.32 5.077 64.344 5.653 ;
     RECT  29.952 5.605 30.264 5.675 ;
     RECT  36.24 5.493 39.336 5.675 ;
     RECT  40.416 5.459 41.16 5.675 ;
     RECT  43.152 5.605 46.152 5.675 ;
     RECT  47.328 5.621 50.424 5.685 ;
     RECT  3.408 5.557 4.152 5.747 ;
     RECT  24.624 5.685 24.648 5.747 ;
     RECT  40.416 5.675 40.92 5.747 ;
     RECT  47.328 5.685 51.336 5.747 ;
     RECT  54.144 5.611 56.472 5.747 ;
     RECT  61.584 3.829 61.608 5.747 ;
     RECT  11.04 4.979 11.496 5.749 ;
     RECT  27.24 3.443 27.552 5.749 ;
     RECT  54.144 5.747 56.136 5.803 ;
     RECT  27.072 5.749 27.552 5.843 ;
     RECT  9.696 5.605 9.768 5.845 ;
     RECT  27.12 5.843 27.552 5.893 ;
     RECT  43.152 5.675 45.576 5.931 ;
     RECT  47.856 5.747 51.336 5.939 ;
     RECT  27.12 5.893 28.056 5.995 ;
     RECT  54.144 5.803 55.512 5.995 ;
     RECT  57.552 5.941 57.576 6.035 ;
     RECT  43.152 5.931 44.568 6.037 ;
     RECT  0.24 5.365 1.128 6.085 ;
     RECT  14.208 5.123 17.64 6.085 ;
     RECT  19.104 5.363 19.128 6.085 ;
     RECT  14.208 6.085 19.128 6.123 ;
     RECT  31.296 5.555 31.32 6.123 ;
     RECT  47.856 5.939 50.712 6.123 ;
     RECT  51.84 6.037 52.104 6.123 ;
     RECT  9.696 5.845 9.912 6.131 ;
     RECT  0.24 6.085 1.368 6.133 ;
     RECT  8.496 5.267 8.52 6.133 ;
     RECT  25.776 5.605 25.8 6.133 ;
     RECT  54.144 5.995 55.32 6.133 ;
     RECT  14.208 6.123 14.232 6.181 ;
     RECT  0.24 6.133 1.992 6.187 ;
     RECT  11.04 5.749 12.216 6.187 ;
     RECT  25.056 6.133 25.8 6.187 ;
     RECT  47.856 6.123 49.272 6.187 ;
     RECT  53.952 6.133 55.32 6.187 ;
     RECT  1.728 6.187 1.992 6.261 ;
     RECT  7.008 5.845 7.032 6.261 ;
     RECT  8.496 6.133 9.576 6.261 ;
     RECT  11.04 6.187 11.352 6.261 ;
     RECT  21.84 4.587 22.152 6.261 ;
     RECT  29.568 5.989 29.592 6.261 ;
     RECT  59.64 4.587 59.952 6.261 ;
     RECT  36.624 5.675 39.336 6.275 ;
     RECT  45.552 5.931 45.576 6.275 ;
     RECT  51.84 6.123 51.864 6.275 ;
     RECT  13.632 6.181 14.232 6.277 ;
     RECT  15.216 6.123 19.128 6.315 ;
     RECT  36.624 6.275 39.144 6.315 ;
     RECT  7.008 6.261 9.576 6.323 ;
     RECT  10.656 6.261 11.352 6.323 ;
     RECT  15.216 6.315 17.592 6.323 ;
     RECT  50.688 6.123 50.712 6.323 ;
     RECT  25.776 6.187 25.8 6.563 ;
     RECT  40.512 5.747 40.92 6.563 ;
     RECT  7.872 6.323 9.576 6.611 ;
     RECT  13.536 6.277 14.232 6.659 ;
     RECT  5.52 5.459 5.952 6.757 ;
     RECT  35.04 6.261 35.064 6.757 ;
     RECT  53.952 6.187 55.08 6.757 ;
     RECT  58.704 6.261 60.072 6.757 ;
     RECT  19.056 6.315 19.128 6.773 ;
     RECT  29.28 6.261 29.592 6.773 ;
     RECT  46.56 6.069 46.776 6.773 ;
     RECT  58.704 6.757 60.408 6.773 ;
     RECT  35.04 6.757 35.88 6.805 ;
     RECT  40.512 6.563 40.536 6.805 ;
     RECT  1.728 6.261 3.24 6.827 ;
     RECT  4.704 6.757 5.952 6.827 ;
     RECT  58.272 6.773 60.408 6.827 ;
     RECT  19.056 6.773 20.088 6.837 ;
     RECT  21.744 6.261 22.152 6.837 ;
     RECT  27.12 5.995 27.552 6.837 ;
     RECT  53.232 6.757 55.08 6.837 ;
     RECT  12.48 6.261 12.504 6.851 ;
     RECT  58.272 6.827 60.072 6.851 ;
     RECT  61.68 6.773 61.704 6.851 ;
     RECT  13.536 6.659 13.752 6.891 ;
     RECT  19.056 6.837 22.152 6.891 ;
     RECT  29.28 6.773 29.832 6.891 ;
     RECT  8.496 6.611 9.576 6.899 ;
     RECT  19.152 6.891 22.152 6.899 ;
     RECT  29.808 6.891 29.832 6.899 ;
     RECT  32.4 5.459 32.952 6.899 ;
     RECT  34.848 6.805 35.88 6.899 ;
     RECT  43.008 6.037 44.568 6.949 ;
     RECT  26.208 6.837 27.552 7.043 ;
     RECT  53.04 6.837 55.08 7.091 ;
     RECT  0.24 6.187 0.552 7.189 ;
     RECT  1.728 6.827 2.952 7.189 ;
     RECT  43.008 6.949 44.76 7.237 ;
     RECT  13.536 6.891 13.704 7.285 ;
     RECT  8.736 6.899 9.576 7.333 ;
     RECT  37.488 6.315 39.144 7.333 ;
     RECT  40.32 6.805 40.536 7.333 ;
     RECT  5.136 6.827 5.952 7.349 ;
     RECT  15.456 6.323 17.592 7.349 ;
     RECT  21.12 6.899 22.152 7.349 ;
     RECT  53.04 7.091 54.648 7.349 ;
     RECT  19.152 6.899 19.992 7.379 ;
     RECT  32.544 6.899 32.952 7.381 ;
     RECT  48.528 6.187 49.272 7.381 ;
     RECT  0.24 7.189 2.952 7.403 ;
     RECT  5.136 7.349 6.84 7.403 ;
     RECT  8.736 7.333 10.008 7.403 ;
     RECT  12.96 7.285 13.704 7.403 ;
     RECT  19.968 7.379 19.992 7.403 ;
     RECT  31.2 7.333 31.224 7.403 ;
     RECT  37.488 7.333 40.536 7.403 ;
     RECT  42.48 7.237 44.76 7.403 ;
     RECT  46.128 6.773 47.304 7.413 ;
     RECT  48.528 7.381 49.752 7.413 ;
     RECT  15.456 7.349 17.688 7.427 ;
     RECT  52.896 7.349 54.648 7.427 ;
     RECT  15.456 7.427 17.496 7.467 ;
     RECT  13.056 7.403 13.08 7.475 ;
     RECT  21.12 7.349 23.496 7.475 ;
     RECT  46.128 7.413 49.752 7.475 ;
     RECT  46.128 7.475 47.688 7.477 ;
     RECT  37.488 7.403 39.144 7.531 ;
     RECT  32.544 7.381 33.144 7.541 ;
     RECT  32.544 7.541 33.768 7.619 ;
     RECT  34.848 6.899 35.352 7.619 ;
     RECT  51.36 7.605 51.384 7.621 ;
     RECT  34.848 7.619 34.872 7.669 ;
     RECT  5.64 7.403 6.84 7.733 ;
     RECT  48.672 7.475 49.752 7.765 ;
     RECT  51.36 7.621 51.624 7.765 ;
     RECT  57.504 7.285 57.96 7.797 ;
     RECT  15.36 7.573 15.384 7.861 ;
     RECT  32.544 7.619 33.192 7.861 ;
     RECT  42.48 7.403 43.752 7.861 ;
     RECT  21.12 7.475 22.824 7.909 ;
     RECT  59.64 6.851 60.072 7.909 ;
     RECT  4.128 7.413 4.152 7.915 ;
     RECT  32.064 7.861 33.192 7.915 ;
     RECT  40.704 7.765 40.728 7.915 ;
     RECT  11.04 6.323 11.352 7.925 ;
     RECT  1.728 7.403 2.952 7.955 ;
     RECT  42.432 7.861 43.752 7.957 ;
     RECT  1.728 7.955 2.184 7.979 ;
     RECT  21.024 7.909 22.824 7.979 ;
     RECT  48.672 7.765 51.624 7.979 ;
     RECT  59.376 7.909 60.072 7.979 ;
     RECT  27.24 7.043 27.552 7.989 ;
     RECT  28.56 7.541 28.584 7.989 ;
     RECT  42.192 7.957 43.752 7.989 ;
     RECT  11.04 7.925 11.928 8.003 ;
     RECT  34.224 7.669 34.872 8.003 ;
     RECT  24.672 7.989 24.696 8.051 ;
     RECT  29.952 7.989 30.264 8.051 ;
     RECT  35.904 7.989 35.928 8.051 ;
     RECT  26.208 7.043 26.232 8.053 ;
     RECT  56.64 7.797 57.96 8.053 ;
     RECT  44.736 7.403 44.76 8.117 ;
     RECT  45.984 7.477 47.688 8.117 ;
     RECT  56.64 8.053 58.2 8.117 ;
     RECT  25.776 8.053 26.232 8.147 ;
     RECT  9.12 7.403 10.008 8.181 ;
     RECT  11.04 8.003 11.736 8.181 ;
     RECT  37.488 7.531 38.352 8.181 ;
     RECT  56.64 8.117 58.296 8.195 ;
     RECT  0.24 7.403 0.552 8.197 ;
     RECT  15.264 7.861 15.384 8.245 ;
     RECT  51.552 7.979 51.624 8.245 ;
     RECT  0.144 8.197 0.552 8.299 ;
     RECT  1.728 7.979 1.992 8.299 ;
     RECT  9.12 8.181 11.736 8.299 ;
     RECT  5.64 7.733 6.936 8.309 ;
     RECT  14.832 8.245 15.384 8.309 ;
     RECT  56.64 8.195 58.2 8.309 ;
     RECT  9.12 8.299 9.48 8.363 ;
     RECT  27.24 7.989 28.584 8.373 ;
     RECT  29.952 8.051 29.976 8.373 ;
     RECT  42.048 7.989 43.752 8.373 ;
     RECT  44.736 8.117 47.688 8.373 ;
     RECT  37.056 8.181 38.352 8.427 ;
     RECT  52.992 7.427 54.648 8.427 ;
     RECT  1.728 8.299 1.752 8.435 ;
     RECT  27.24 8.373 29.976 8.435 ;
     RECT  42.048 8.373 47.688 8.435 ;
     RECT  56.448 8.309 58.2 8.435 ;
     RECT  14.112 8.309 15.384 8.437 ;
     RECT  53.952 8.427 54.648 8.437 ;
     RECT  14.112 8.437 15.432 8.483 ;
     RECT  48.672 7.979 50.424 8.483 ;
     RECT  18.816 7.861 18.888 8.485 ;
     RECT  14.208 8.483 15.432 8.491 ;
     RECT  16.44 7.467 17.496 8.491 ;
     RECT  37.296 8.427 38.352 8.531 ;
     RECT  27.24 8.435 29.544 8.533 ;
     RECT  10.56 8.299 11.736 8.555 ;
     RECT  26.736 8.533 29.544 8.555 ;
     RECT  32.544 7.915 33.192 8.555 ;
     RECT  42.048 8.435 42.072 8.565 ;
     RECT  5.64 8.309 7.848 8.619 ;
     RECT  26.736 8.555 28.872 8.627 ;
     RECT  45.888 8.435 47.688 8.629 ;
     RECT  48.672 8.483 49.152 8.629 ;
     RECT  14.208 8.491 15.288 8.675 ;
     RECT  5.64 8.619 6.072 8.677 ;
     RECT  7.728 8.619 7.848 8.683 ;
     RECT  41.808 8.565 42.072 8.693 ;
     RECT  1.68 8.565 1.704 8.723 ;
     RECT  9.456 8.363 9.48 8.723 ;
     RECT  20.832 8.245 20.856 8.723 ;
     RECT  34.224 8.003 34.776 8.723 ;
     RECT  45.888 8.629 49.152 8.771 ;
     RECT  56.976 8.435 58.2 8.771 ;
     RECT  32.64 8.555 33.192 8.821 ;
     RECT  37.68 8.531 38.352 8.821 ;
     RECT  39.504 8.693 39.672 8.821 ;
     RECT  51.552 8.245 51.672 8.821 ;
     RECT  4.656 8.677 6.072 8.875 ;
     RECT  32.64 8.821 33.576 8.875 ;
     RECT  50.304 8.483 50.424 8.875 ;
     RECT  61.584 8.821 61.608 8.875 ;
     RECT  37.68 8.821 39.672 8.885 ;
     RECT  51.552 8.821 51.912 8.915 ;
     RECT  37.68 8.885 39.816 8.949 ;
     RECT  48.288 8.771 49.152 8.963 ;
     RECT  4.608 8.949 4.632 9.011 ;
     RECT  34.752 8.723 34.776 9.011 ;
     RECT  41.04 8.693 42.072 9.011 ;
     RECT  10.8 8.555 11.736 9.013 ;
     RECT  18.816 8.485 19.368 9.013 ;
     RECT  37.68 8.949 39.912 9.013 ;
     RECT  24.432 8.437 24.456 9.061 ;
     RECT  36.096 8.565 36.312 9.061 ;
     RECT  18.816 9.013 19.752 9.067 ;
     RECT  34.8 9.061 34.824 9.131 ;
     RECT  36.048 9.061 36.312 9.131 ;
     RECT  50.304 8.875 50.328 9.131 ;
     RECT  37.68 9.013 40.44 9.155 ;
     RECT  45.888 8.771 47.064 9.155 ;
     RECT  26.736 8.627 27.552 9.195 ;
     RECT  59.376 7.979 59.952 9.195 ;
     RECT  21.84 7.979 22.824 9.253 ;
     RECT  16.44 8.491 17.304 9.259 ;
     RECT  18.816 9.067 18.936 9.259 ;
     RECT  55.776 9.205 55.896 9.323 ;
     RECT  56.976 8.771 57.624 9.323 ;
     RECT  62.16 9.269 62.184 9.347 ;
     RECT  43.104 8.435 44.52 9.397 ;
     RECT  51.552 8.915 51.864 9.451 ;
     RECT  3.216 8.565 3.432 9.461 ;
     RECT  53.952 8.437 54.696 9.461 ;
     RECT  24.432 9.061 25.32 9.491 ;
     RECT  51.6 9.451 51.864 9.515 ;
     RECT  10.8 9.013 12.024 9.525 ;
     RECT  41.568 9.011 42.072 9.525 ;
     RECT  43.104 9.397 44.616 9.525 ;
     RECT  53.664 9.461 54.696 9.539 ;
     RECT  10.8 9.525 12.696 9.589 ;
     RECT  37.68 9.155 39.24 9.589 ;
     RECT  21.12 9.253 22.824 9.637 ;
     RECT  64.176 5.653 64.584 9.637 ;
     RECT  3.216 9.461 3.816 9.643 ;
     RECT  37.632 9.589 39.24 9.643 ;
     RECT  30.672 9.637 30.696 9.653 ;
     RECT  28.848 8.627 28.872 9.707 ;
     RECT  64.128 9.637 64.584 9.707 ;
     RECT  3.216 9.643 3.288 9.717 ;
     RECT  7.728 8.683 7.8 9.717 ;
     RECT  30.576 9.653 30.696 9.717 ;
     RECT  48.384 8.963 49.152 9.717 ;
     RECT  7.728 9.717 8.568 9.779 ;
     RECT  38.04 9.643 39.24 9.779 ;
     RECT  48.384 9.717 49.272 9.779 ;
     RECT  57.408 9.323 57.624 9.779 ;
     RECT  14.208 8.675 14.856 9.781 ;
     RECT  20.064 9.205 20.136 9.829 ;
     RECT  21.12 9.637 22.968 9.829 ;
     RECT  18.768 9.781 18.792 9.835 ;
     RECT  5.64 8.875 6.072 9.877 ;
     RECT  16.44 9.259 17.112 9.877 ;
     RECT  30.576 9.717 31.368 9.877 ;
     RECT  36.336 9.589 36.36 9.877 ;
     RECT  7.728 9.779 8.376 9.899 ;
     RECT  40.416 9.155 40.44 9.899 ;
     RECT  5.64 9.877 6.408 9.909 ;
     RECT  9.456 9.845 9.48 9.923 ;
     RECT  14.112 9.781 14.856 9.963 ;
     RECT  30.24 9.877 31.368 9.963 ;
     RECT  2.256 9.717 3.288 9.971 ;
     RECT  10.752 9.589 12.696 10.021 ;
     RECT  14.112 9.963 14.136 10.021 ;
     RECT  27.24 9.195 27.552 10.021 ;
     RECT  30.816 9.963 31.368 10.069 ;
     RECT  32.64 8.875 32.952 10.069 ;
     RECT  2.256 9.971 2.472 10.091 ;
     RECT  27.24 10.021 27.912 10.091 ;
     RECT  30.816 10.069 32.952 10.091 ;
     RECT  10.752 10.021 14.136 10.101 ;
     RECT  18.336 10.069 18.36 10.101 ;
     RECT  31.584 10.091 32.952 10.101 ;
     RECT  20.064 9.829 22.968 10.115 ;
     RECT  41.568 9.525 44.616 10.117 ;
     RECT  45.888 9.155 46.824 10.117 ;
     RECT  35.136 9.909 35.16 10.163 ;
     RECT  18.24 10.101 18.36 10.219 ;
     RECT  5.376 9.909 6.408 10.229 ;
     RECT  54.24 9.539 54.696 10.229 ;
     RECT  18.24 10.219 18.264 10.259 ;
     RECT  16.032 9.877 17.112 10.283 ;
     RECT  31.584 10.101 33.048 10.283 ;
     RECT  45.744 10.117 46.824 10.293 ;
     RECT  48.384 9.779 49.152 10.293 ;
     RECT  55.968 9.461 56.376 10.293 ;
     RECT  20.064 10.115 22.68 10.307 ;
     RECT  23.952 9.717 23.976 10.307 ;
     RECT  55.968 10.293 57.048 10.355 ;
     RECT  20.064 10.307 22.152 10.357 ;
     RECT  36.336 9.877 36.888 10.357 ;
     RECT  16.44 10.283 17.112 10.405 ;
     RECT  9.792 10.101 14.136 10.411 ;
     RECT  4.32 10.229 6.408 10.475 ;
     RECT  15.264 10.405 15.384 10.475 ;
     RECT  59.64 9.195 59.952 10.485 ;
     RECT  15.36 10.475 15.384 10.499 ;
     RECT  54.24 10.229 54.936 10.549 ;
     RECT  51.6 9.515 51.624 10.595 ;
     RECT  59.64 10.485 60.408 10.595 ;
     RECT  31.824 10.283 33.048 10.613 ;
     RECT  5.136 10.475 6.408 10.693 ;
     RECT  19.344 10.357 22.152 10.731 ;
     RECT  0.24 8.299 0.552 10.741 ;
     RECT  40.992 10.117 44.616 10.741 ;
     RECT  45.744 10.293 49.152 10.741 ;
     RECT  36.192 10.357 36.888 10.789 ;
     RECT  40.992 10.741 49.152 10.805 ;
     RECT  57.024 10.355 57.048 10.805 ;
     RECT  25.152 9.491 25.32 10.835 ;
     RECT  35.328 10.789 36.888 10.837 ;
     RECT  38.04 9.779 38.76 10.837 ;
     RECT  50.736 10.789 50.76 10.859 ;
     RECT  54.24 10.549 55.224 10.859 ;
     RECT  57.024 10.805 57.528 10.883 ;
     RECT  20.88 10.731 22.152 10.931 ;
     RECT  57.12 10.883 57.528 10.931 ;
     RECT  12.96 10.411 14.136 10.933 ;
     RECT  35.328 10.837 38.76 10.933 ;
     RECT  39.936 10.213 39.96 10.933 ;
     RECT  35.328 10.933 39.96 10.979 ;
     RECT  9.792 10.411 11.976 10.981 ;
     RECT  39.36 10.979 39.96 10.997 ;
     RECT  40.992 10.805 49.512 10.997 ;
     RECT  52.944 10.933 52.968 11.027 ;
     RECT  5.136 10.693 6.84 11.061 ;
     RECT  19.344 10.731 19.464 11.115 ;
     RECT  35.328 10.979 38.352 11.115 ;
     RECT  39.36 10.997 49.512 11.115 ;
     RECT  30.192 11.061 30.216 11.123 ;
     RECT  31.824 10.613 33.48 11.123 ;
     RECT  5.136 11.061 7.32 11.171 ;
     RECT  12.96 10.933 14.232 11.171 ;
     RECT  25.296 10.835 25.32 11.171 ;
     RECT  9.552 10.981 11.976 11.179 ;
     RECT  39.936 11.115 49.512 11.179 ;
     RECT  9.552 11.179 9.672 11.243 ;
     RECT  0.24 10.741 0.648 11.253 ;
     RECT  1.68 10.645 1.704 11.253 ;
     RECT  43.344 11.179 49.512 11.267 ;
     RECT  5.136 11.171 7.224 11.371 ;
     RECT  43.344 11.267 46.872 11.371 ;
     RECT  63.168 11.269 63.192 11.371 ;
     RECT  11.04 11.179 11.976 11.381 ;
     RECT  12.96 11.171 13.032 11.381 ;
     RECT  31.872 11.123 33.48 11.381 ;
     RECT  30.672 11.173 30.696 11.435 ;
     RECT  27.24 10.091 27.552 11.445 ;
     RECT  8.352 9.899 8.376 11.459 ;
     RECT  9.648 11.243 9.672 11.459 ;
     RECT  21.168 10.931 22.152 11.459 ;
     RECT  26.736 11.445 27.96 11.507 ;
     RECT  0.24 11.253 1.704 11.637 ;
     RECT  5.136 11.371 6.84 11.637 ;
     RECT  16.44 10.405 18.072 11.637 ;
     RECT  47.948 11.267 49.512 11.637 ;
     RECT  16.44 11.637 18.12 11.648 ;
     RECT  4.56 11.637 6.84 11.651 ;
     RECT  8.544 11.573 8.568 11.651 ;
     RECT  43.344 11.371 46.824 11.651 ;
     RECT  16.44 11.648 18.124 11.692 ;
     RECT  0.144 11.637 1.704 11.699 ;
     RECT  4.56 11.651 4.584 11.699 ;
     RECT  11.04 11.381 13.032 11.699 ;
     RECT  16.44 11.692 18.12 11.699 ;
     RECT  19.392 11.115 19.464 11.699 ;
     RECT  35.712 11.115 38.352 11.699 ;
     RECT  39.936 11.179 42.36 11.699 ;
     RECT  29.04 10.597 29.064 11.747 ;
     RECT  13.008 11.699 13.032 11.939 ;
     RECT  16.44 11.699 17.688 11.939 ;
     RECT  36 11.699 38.352 11.939 ;
     RECT  57.936 11.637 57.96 11.939 ;
     RECT  42.336 11.699 42.36 12.035 ;
     RECT  45.024 11.651 46.824 12.035 ;
     RECT  14.208 11.171 14.232 12.037 ;
     RECT  31.872 11.381 34.248 12.037 ;
     RECT  47.948 11.637 49.56 12.085 ;
     RECT  14.208 12.037 15.096 12.133 ;
     RECT  39.936 11.699 41.352 12.133 ;
     RECT  13.248 12.133 15.096 12.181 ;
     RECT  16.44 11.939 17.016 12.181 ;
     RECT  31.872 12.037 34.584 12.203 ;
     RECT  39.36 12.133 41.352 12.203 ;
     RECT  0.24 11.699 1.704 12.213 ;
     RECT  2.88 12.037 2.904 12.213 ;
     RECT  19.44 11.699 19.464 12.213 ;
     RECT  43.344 11.651 43.752 12.213 ;
     RECT  47.948 12.085 49.8 12.213 ;
     RECT  51.504 11.637 51.528 12.213 ;
     RECT  53.136 11.509 53.16 12.213 ;
     RECT  56.4 12.181 56.424 12.213 ;
     RECT  47.948 12.213 49.944 12.224 ;
     RECT  51.504 12.213 51.912 12.224 ;
     RECT  5.64 11.651 6.84 12.227 ;
     RECT  19.44 12.213 20.04 12.227 ;
     RECT  31.968 12.203 34.44 12.227 ;
     RECT  39.888 12.203 41.352 12.227 ;
     RECT  21.36 11.459 22.152 12.267 ;
     RECT  32.64 12.227 34.44 12.267 ;
     RECT  39.888 12.227 41.256 12.267 ;
     RECT  56.4 12.213 57.192 12.267 ;
     RECT  47.948 12.224 49.948 12.268 ;
     RECT  0.24 12.213 2.904 12.275 ;
     RECT  3.984 12.213 4.008 12.275 ;
     RECT  25.056 12.213 25.08 12.275 ;
     RECT  34.416 12.267 34.44 12.275 ;
     RECT  40.176 12.267 41.256 12.275 ;
     RECT  47.948 12.268 49.944 12.275 ;
     RECT  20.016 12.227 20.04 12.323 ;
     RECT  21.744 12.267 22.152 12.323 ;
     RECT  53.136 12.213 53.256 12.323 ;
     RECT  45.504 12.035 46.824 12.421 ;
     RECT  47.948 12.275 49.608 12.421 ;
     RECT  13.248 12.181 17.016 12.515 ;
     RECT  51.504 12.224 51.916 12.517 ;
     RECT  59.64 10.595 59.952 12.517 ;
     RECT  54.24 10.859 54.792 12.563 ;
     RECT  56.64 12.267 57.192 12.611 ;
     RECT  59.136 12.517 60.744 12.613 ;
     RECT  11.04 11.699 11.448 12.709 ;
     RECT  51.072 12.517 51.916 12.709 ;
     RECT  29.856 12.517 29.88 12.725 ;
     RECT  40.992 12.275 41.016 12.755 ;
     RECT  58.992 12.613 60.744 12.757 ;
     RECT  29.856 12.725 30.84 12.779 ;
     RECT  51.072 12.709 51.96 12.779 ;
     RECT  52.944 12.709 52.968 12.779 ;
     RECT  58.992 12.757 60.792 12.779 ;
     RECT  10.08 12.709 11.448 12.789 ;
     RECT  36 11.939 36.552 12.789 ;
     RECT  30.24 12.779 30.84 12.803 ;
     RECT  4.272 12.789 4.296 12.851 ;
     RECT  35.424 12.789 36.552 12.851 ;
     RECT  35.712 12.851 36.552 12.901 ;
     RECT  37.536 11.939 38.352 12.901 ;
     RECT  59.136 12.779 60.792 12.917 ;
     RECT  61.92 12.901 61.944 12.917 ;
     RECT  5.64 12.227 6.552 12.981 ;
     RECT  10.08 12.789 11.544 12.981 ;
     RECT  59.136 12.917 61.944 12.981 ;
     RECT  51.072 12.779 51.096 13.035 ;
     RECT  4.752 12.981 6.552 13.043 ;
     RECT  45.504 12.421 49.608 13.043 ;
     RECT  1.68 12.275 2.904 13.045 ;
     RECT  10.032 12.981 11.544 13.045 ;
     RECT  35.712 12.901 38.352 13.045 ;
     RECT  43.2 12.213 43.752 13.045 ;
     RECT  59.136 12.981 62.184 13.045 ;
     RECT  9.936 13.045 11.544 13.091 ;
     RECT  1.68 13.045 3.144 13.099 ;
     RECT  13.248 12.515 16.752 13.099 ;
     RECT  35.712 13.045 38.856 13.099 ;
     RECT  45.504 13.043 47.592 13.099 ;
     RECT  48.72 13.043 49.512 13.099 ;
     RECT  59.136 13.045 62.904 13.099 ;
     RECT  21.84 12.323 22.152 13.109 ;
     RECT  59.136 13.099 60.84 13.163 ;
     RECT  21.84 13.109 22.392 13.187 ;
     RECT  35.712 13.099 38.352 13.187 ;
     RECT  7.968 13.093 7.992 13.227 ;
     RECT  13.728 13.099 13.752 13.283 ;
     RECT  52.272 13.173 52.296 13.283 ;
     RECT  5.64 13.043 6.552 13.285 ;
     RECT  45.504 13.099 47.352 13.285 ;
     RECT  14.784 13.099 16.752 13.355 ;
     RECT  56.64 12.611 56.808 13.381 ;
     RECT  0.24 12.275 0.648 13.429 ;
     RECT  1.68 13.099 2.856 13.429 ;
     RECT  55.776 13.381 56.808 13.483 ;
     RECT  27.24 11.507 27.552 13.493 ;
     RECT  5.64 13.285 6.648 13.557 ;
     RECT  42.816 13.045 43.752 13.557 ;
     RECT  18.72 13.493 18.744 13.571 ;
     RECT  26.496 13.493 27.552 13.571 ;
     RECT  5.64 13.557 7.608 13.619 ;
     RECT  0.24 13.429 2.856 13.685 ;
     RECT  27.24 13.571 27.552 13.685 ;
     RECT  45.072 13.285 47.352 13.685 ;
     RECT  54.24 12.563 54.648 13.685 ;
     RECT  56.64 13.483 56.808 13.685 ;
     RECT  0.144 13.685 2.856 13.715 ;
     RECT  61.92 13.099 62.904 13.739 ;
     RECT  11.04 13.091 11.544 13.749 ;
     RECT  17.76 13.685 17.784 13.763 ;
     RECT  11.04 13.749 11.832 13.811 ;
     RECT  50.592 13.749 50.616 13.811 ;
     RECT  8.928 13.749 8.952 13.859 ;
     RECT  51.888 13.749 51.912 13.859 ;
     RECT  32.64 12.267 32.952 13.861 ;
     RECT  56.64 13.685 57.192 13.867 ;
     RECT  54.24 13.685 55.176 13.877 ;
     RECT  4.032 13.813 4.056 13.907 ;
     RECT  48.72 13.099 49.152 13.995 ;
     RECT  40.464 13.301 40.536 14.005 ;
     RECT  42.384 13.557 43.752 14.005 ;
     RECT  9.936 13.091 10.056 14.053 ;
     RECT  40.224 14.005 40.536 14.059 ;
     RECT  41.568 14.005 43.752 14.059 ;
     RECT  44.976 13.685 47.352 14.059 ;
     RECT  59.136 13.163 60.792 14.069 ;
     RECT  14.784 13.355 14.808 14.099 ;
     RECT  30.24 12.803 30.264 14.101 ;
     RECT  32.64 13.861 34.008 14.101 ;
     RECT  29.616 14.101 30.264 14.133 ;
     RECT  58.656 14.069 60.792 14.133 ;
     RECT  31.344 14.101 34.008 14.187 ;
     RECT  13.632 14.133 13.656 14.195 ;
     RECT  57.024 13.867 57.192 14.195 ;
     RECT  0.144 13.715 2.184 14.197 ;
     RECT  5.64 13.619 6.888 14.197 ;
     RECT  42.192 14.059 43.752 14.197 ;
     RECT  44.976 14.059 45.624 14.197 ;
     RECT  58.416 14.133 60.792 14.197 ;
     RECT  62.736 13.739 62.904 14.197 ;
     RECT  64.176 9.707 64.584 14.197 ;
     RECT  31.392 14.187 34.008 14.243 ;
     RECT  57.168 14.195 57.192 14.245 ;
     RECT  58.32 14.197 60.792 14.245 ;
     RECT  0.096 14.197 2.184 14.251 ;
     RECT  5.52 14.197 6.888 14.251 ;
     RECT  9.024 14.053 10.056 14.251 ;
     RECT  15.888 13.355 16.752 14.251 ;
     RECT  35.904 13.187 38.352 14.251 ;
     RECT  57.168 14.245 60.792 14.251 ;
     RECT  36.384 14.251 38.352 14.261 ;
     RECT  9.024 14.251 9.72 14.291 ;
     RECT  57.456 14.251 60.792 14.315 ;
     RECT  21.84 13.187 22.152 14.325 ;
     RECT  54.144 13.877 55.176 14.325 ;
     RECT  58.08 14.315 60.792 14.435 ;
     RECT  23.712 14.325 23.736 14.437 ;
     RECT  25.104 14.325 25.128 14.437 ;
     RECT  27.24 13.685 28.152 14.437 ;
     RECT  48.84 13.995 49.152 14.437 ;
     RECT  35.376 14.389 35.4 14.443 ;
     RECT  59.52 14.435 60.792 14.483 ;
     RECT  54.096 14.325 55.176 14.485 ;
     RECT  27.24 14.437 28.296 14.507 ;
     RECT  29.616 14.133 30.36 14.507 ;
     RECT  15.312 14.485 15.336 14.571 ;
     RECT  27.24 14.507 28.2 14.571 ;
     RECT  54.096 14.485 55.896 14.571 ;
     RECT  16.44 14.251 16.752 14.581 ;
     RECT  23.712 14.437 23.832 14.629 ;
     RECT  25.104 14.437 25.512 14.629 ;
     RECT  59.64 14.483 60.792 14.629 ;
     RECT  16.44 14.581 17.64 14.635 ;
     RECT  58.08 14.435 58.488 14.635 ;
     RECT  29.616 14.507 30.12 14.645 ;
     RECT  51.456 14.581 51.48 14.675 ;
     RECT  52.464 14.581 52.488 14.675 ;
     RECT  19.44 14.245 19.464 14.677 ;
     RECT  54.096 14.571 55.32 14.677 ;
     RECT  23.712 14.629 25.512 14.699 ;
     RECT  58.08 14.635 58.392 14.699 ;
     RECT  62.736 14.197 64.584 14.699 ;
     RECT  27.24 14.571 27.96 14.725 ;
     RECT  62.736 14.699 62.808 14.725 ;
     RECT  19.392 14.677 19.464 14.763 ;
     RECT  36.384 14.261 39.48 14.763 ;
     RECT  42.192 14.197 45.624 14.763 ;
     RECT  34.32 14.453 34.776 14.771 ;
     RECT  5.52 14.251 5.952 14.773 ;
     RECT  53.568 14.677 55.32 14.773 ;
     RECT  19.44 14.763 19.464 14.819 ;
     RECT  4.656 14.773 5.952 14.827 ;
     RECT  25.104 14.699 25.512 14.827 ;
     RECT  52.512 14.773 55.32 14.827 ;
     RECT  62.4 14.725 62.808 14.827 ;
     RECT  0.144 14.251 2.184 14.837 ;
     RECT  3.168 14.197 3.576 14.837 ;
     RECT  29.232 14.645 30.12 14.867 ;
     RECT  36.384 14.763 39.24 14.867 ;
     RECT  18.24 14.837 18.264 14.915 ;
     RECT  4.944 14.827 5.952 14.963 ;
     RECT  59.64 14.629 61.32 14.963 ;
     RECT  26.496 14.725 27.96 15.019 ;
     RECT  34.464 14.771 34.776 15.019 ;
     RECT  7.296 14.773 7.416 15.029 ;
     RECT  43.248 14.763 45.624 15.029 ;
     RECT  46.752 14.059 47.352 15.029 ;
     RECT  26.496 15.019 27.912 15.061 ;
     RECT  11.04 13.811 11.496 15.093 ;
     RECT  43.248 15.029 47.352 15.093 ;
     RECT  25.536 15.061 27.912 15.147 ;
     RECT  59.64 14.963 60.264 15.155 ;
     RECT  7.296 15.029 7.848 15.211 ;
     RECT  20.4 15.157 20.424 15.251 ;
     RECT  52.512 14.827 54.648 15.251 ;
     RECT  31.392 14.243 33.096 15.285 ;
     RECT  48.84 14.437 49.416 15.285 ;
     RECT  7.392 15.211 7.848 15.299 ;
     RECT  0.144 14.837 3.576 15.301 ;
     RECT  40.992 14.437 41.064 15.339 ;
     RECT  48.84 15.285 50.088 15.347 ;
     RECT  43.248 15.093 47.4 15.349 ;
     RECT  48.84 15.347 49.608 15.349 ;
     RECT  31.392 15.285 33.24 15.397 ;
     RECT  0.144 15.301 3.624 15.403 ;
     RECT  43.248 15.349 49.608 15.403 ;
     RECT  13.92 15.285 13.944 15.413 ;
     RECT  21.84 14.325 22.392 15.413 ;
     RECT  23.712 14.699 23.928 15.413 ;
     RECT  57.072 15.349 57.096 15.413 ;
     RECT  58.08 14.699 58.104 15.413 ;
     RECT  7.392 15.299 7.656 15.443 ;
     RECT  11.04 15.093 11.784 15.445 ;
     RECT  12.816 15.013 12.84 15.445 ;
     RECT  25.536 15.147 25.56 15.467 ;
     RECT  31.344 15.397 33.24 15.467 ;
     RECT  13.92 15.413 14.568 15.491 ;
     RECT  31.344 15.467 31.512 15.491 ;
     RECT  42.144 15.477 42.168 15.493 ;
     RECT  31.344 15.491 31.416 15.539 ;
     RECT  41.232 15.493 42.168 15.539 ;
     RECT  11.04 15.445 12.84 15.541 ;
     RECT  16.44 14.635 16.872 15.541 ;
     RECT  48.096 15.403 49.608 15.635 ;
     RECT  51.408 15.541 51.432 15.669 ;
     RECT  52.512 15.251 54.552 15.669 ;
     RECT  36.432 14.867 39.24 15.723 ;
     RECT  41.232 15.539 41.64 15.723 ;
     RECT  51.408 15.669 54.552 15.723 ;
     RECT  43.248 15.403 47.064 15.731 ;
     RECT  10.896 15.541 12.84 15.733 ;
     RECT  13.872 15.669 13.896 15.733 ;
     RECT  15.744 15.541 16.872 15.733 ;
     RECT  62.784 14.827 62.808 15.733 ;
     RECT  64.176 14.699 64.584 15.733 ;
     RECT  10.896 15.733 13.896 15.787 ;
     RECT  51.408 15.723 51.576 15.829 ;
     RECT  59.64 15.155 60.168 15.829 ;
     RECT  21.84 15.413 23.928 15.877 ;
     RECT  24.912 15.797 25.512 15.877 ;
     RECT  21.84 15.877 25.512 15.925 ;
     RECT  61.248 14.963 61.32 15.925 ;
     RECT  29.472 14.867 30.12 15.973 ;
     RECT  57.072 15.413 58.104 15.973 ;
     RECT  59.472 15.829 60.168 15.973 ;
     RECT  57.072 15.973 60.168 15.979 ;
     RECT  34.752 15.019 34.776 15.989 ;
     RECT  43.248 15.731 45.528 15.989 ;
     RECT  21.744 15.925 25.512 16.019 ;
     RECT  10.944 15.787 13.896 16.043 ;
     RECT  29.424 15.973 30.12 16.053 ;
     RECT  57.408 15.979 60.168 16.067 ;
     RECT  21.744 16.019 22.872 16.069 ;
     RECT  27.024 15.147 27.912 16.069 ;
     RECT  29.328 16.053 30.12 16.069 ;
     RECT  20.112 15.989 20.136 16.115 ;
     RECT  41.424 15.723 41.64 16.115 ;
     RECT  29.184 16.069 30.12 16.117 ;
     RECT  31.152 15.781 31.176 16.117 ;
     RECT  32.64 15.467 33.24 16.117 ;
     RECT  34.752 15.989 35.4 16.117 ;
     RECT  36.432 15.723 38.472 16.117 ;
     RECT  57.552 16.067 60.168 16.117 ;
     RECT  61.248 15.925 61.416 16.117 ;
     RECT  62.784 15.733 64.584 16.117 ;
     RECT  5.136 14.963 5.952 16.181 ;
     RECT  48.096 15.635 49.56 16.211 ;
     RECT  11.04 16.043 13.896 16.299 ;
     RECT  48.096 16.211 49.512 16.307 ;
     RECT  27.024 16.069 27.96 16.309 ;
     RECT  29.088 16.117 31.176 16.309 ;
     RECT  11.04 16.299 13.08 16.355 ;
     RECT  39.744 16.117 39.768 16.363 ;
     RECT  15.744 15.733 17.496 16.373 ;
     RECT  18.816 15.989 18.84 16.373 ;
     RECT  15.744 16.373 18.84 16.405 ;
     RECT  51.072 15.829 51.576 16.405 ;
     RECT  57.552 16.117 61.416 16.405 ;
     RECT  62.448 16.117 64.584 16.405 ;
     RECT  27.024 16.309 31.176 16.427 ;
     RECT  46.512 15.731 47.064 16.437 ;
     RECT  48.096 16.307 49.464 16.437 ;
     RECT  46.512 16.437 49.464 16.491 ;
     RECT  50.736 16.405 51.576 16.491 ;
     RECT  24.288 16.019 25.512 16.499 ;
     RECT  0.144 15.403 2.952 16.501 ;
     RECT  7.536 15.443 7.656 16.501 ;
     RECT  27.024 16.427 28.536 16.501 ;
     RECT  29.856 16.427 31.176 16.501 ;
     RECT  53.28 15.723 54.552 16.501 ;
     RECT  15.744 16.405 19.704 16.555 ;
     RECT  41.424 16.115 41.448 16.555 ;
     RECT  57.552 16.405 64.584 16.555 ;
     RECT  4.848 16.181 5.952 16.565 ;
     RECT  9.36 14.291 9.72 16.565 ;
     RECT  42.72 15.989 45.528 16.565 ;
     RECT  57.984 16.555 64.584 16.595 ;
     RECT  15.744 16.555 17.496 16.619 ;
     RECT  4.8 16.565 6.168 16.629 ;
     RECT  53.28 16.501 55.416 16.629 ;
     RECT  12.912 16.355 13.08 16.643 ;
     RECT  26.208 16.501 28.536 16.643 ;
     RECT  4.704 16.629 6.168 16.645 ;
     RECT  26.448 16.643 28.536 16.683 ;
     RECT  14.304 16.565 14.328 16.693 ;
     RECT  29.856 16.501 31.224 16.693 ;
     RECT  32.64 16.117 38.472 16.693 ;
     RECT  51.552 16.491 51.576 16.693 ;
     RECT  0.144 16.501 3.624 16.741 ;
     RECT  4.704 16.645 6.264 16.741 ;
     RECT  16.44 16.619 17.496 16.747 ;
     RECT  0.144 16.741 6.264 16.757 ;
     RECT  7.536 16.501 7.992 16.757 ;
     RECT  29.856 16.693 38.472 16.757 ;
     RECT  53.28 16.629 55.992 16.787 ;
     RECT  64.176 16.595 64.584 16.787 ;
     RECT  0.144 16.757 6.312 16.789 ;
     RECT  7.536 16.757 8.328 16.789 ;
     RECT  0.144 16.789 8.328 16.811 ;
     RECT  26.736 16.683 28.536 16.811 ;
     RECT  14.304 16.693 14.712 16.835 ;
     RECT  46.512 16.491 49.152 16.875 ;
     RECT  29.856 16.757 38.808 16.883 ;
     RECT  21.696 16.069 22.872 16.885 ;
     RECT  21.648 16.885 22.872 16.933 ;
     RECT  56.112 16.837 56.136 16.939 ;
     RECT  42.624 16.565 45.528 16.949 ;
     RECT  46.512 16.875 47.448 16.949 ;
     RECT  4.464 16.811 8.328 16.981 ;
     RECT  9.36 16.565 9.768 16.981 ;
     RECT  39.888 16.949 40.392 16.981 ;
     RECT  24.288 16.499 25.08 17.003 ;
     RECT  51.552 16.693 51.672 17.013 ;
     RECT  21.024 16.933 22.872 17.067 ;
     RECT  39.888 16.981 41.016 17.067 ;
     RECT  4.464 16.981 9.768 17.075 ;
     RECT  19.056 16.555 19.704 17.075 ;
     RECT  42.624 16.949 47.448 17.075 ;
     RECT  57.984 16.595 62.808 17.075 ;
     RECT  21.744 17.067 22.872 17.077 ;
     RECT  51.552 17.013 52.104 17.077 ;
     RECT  53.28 16.787 55.032 17.077 ;
     RECT  57.984 17.075 62.664 17.123 ;
     RECT  0.144 16.811 3.432 17.131 ;
     RECT  43.296 17.075 47.448 17.171 ;
     RECT  43.296 17.171 46.68 17.315 ;
     RECT  24.528 17.003 25.08 17.363 ;
     RECT  64.224 16.787 64.584 17.363 ;
     RECT  0.144 17.131 1.752 17.365 ;
     RECT  16.44 16.747 16.968 17.459 ;
     RECT  48.48 16.875 49.152 17.557 ;
     RECT  11.04 16.355 11.352 17.589 ;
     RECT  21.744 17.077 22.968 17.589 ;
     RECT  4.464 17.075 6.312 17.603 ;
     RECT  11.04 17.589 12.072 17.605 ;
     RECT  48.48 17.557 49.8 17.605 ;
     RECT  51.552 17.077 55.032 17.605 ;
     RECT  24.576 17.363 25.08 17.643 ;
     RECT  48.48 17.605 55.032 17.643 ;
     RECT  5.232 17.603 6.312 17.651 ;
     RECT  10.704 17.605 12.072 17.651 ;
     RECT  19.968 17.077 19.992 17.651 ;
     RECT  21.744 17.589 23.352 17.651 ;
     RECT  34.848 16.883 38.808 17.651 ;
     RECT  42.192 17.589 42.216 17.651 ;
     RECT  13.056 16.643 13.08 17.653 ;
     RECT  29.856 16.883 33.768 17.653 ;
     RECT  37.008 17.651 38.808 17.653 ;
     RECT  39.888 17.067 40.968 17.653 ;
     RECT  56.256 17.605 56.28 17.653 ;
     RECT  57.984 17.123 61.752 17.653 ;
     RECT  26.736 16.811 28.392 17.699 ;
     RECT  37.008 17.653 40.968 17.707 ;
     RECT  43.296 17.315 44.712 17.707 ;
     RECT  48.48 17.643 54.744 17.707 ;
     RECT  56.256 17.653 61.752 17.707 ;
     RECT  2.88 17.131 3.432 17.747 ;
     RECT  37.008 17.707 38.952 17.843 ;
     RECT  56.352 17.707 61.752 17.843 ;
     RECT  2.88 17.747 3.24 17.891 ;
     RECT  14.304 16.835 14.424 17.893 ;
     RECT  48.48 17.707 50.664 17.893 ;
     RECT  12.768 17.653 13.08 17.939 ;
     RECT  37.008 17.843 38.352 17.987 ;
     RECT  12.816 17.939 13.08 17.989 ;
     RECT  29.808 17.653 33.768 17.989 ;
     RECT  5.64 17.651 6.312 18.037 ;
     RECT  7.776 17.075 9 18.037 ;
     RECT  34.848 17.651 35.88 18.083 ;
     RECT  56.352 17.843 57 18.131 ;
     RECT  16.44 17.459 16.752 18.133 ;
     RECT  29.664 17.989 33.768 18.133 ;
     RECT  20.544 17.653 20.568 18.165 ;
     RECT  21.744 17.651 22.392 18.165 ;
     RECT  20.544 18.165 22.392 18.179 ;
     RECT  5.64 18.037 9 18.181 ;
     RECT  10.704 17.651 11.448 18.181 ;
     RECT  45.792 17.315 46.68 18.181 ;
     RECT  47.856 17.893 50.664 18.181 ;
     RECT  2.88 17.891 2.904 18.219 ;
     RECT  5.64 18.181 9.384 18.219 ;
     RECT  10.464 18.181 11.448 18.219 ;
     RECT  12.816 17.989 13.176 18.219 ;
     RECT  26.736 17.699 28.248 18.219 ;
     RECT  29.472 18.133 33.768 18.219 ;
     RECT  5.64 18.219 7.752 18.227 ;
     RECT  45.792 18.181 50.664 18.227 ;
     RECT  64.224 17.363 64.536 18.227 ;
     RECT  30.192 18.219 33.768 18.229 ;
     RECT  34.848 18.083 35.832 18.229 ;
     RECT  64.224 18.227 64.296 18.229 ;
     RECT  8.976 18.219 9.384 18.275 ;
     RECT  51.648 17.707 54.744 18.275 ;
     RECT  5.64 18.227 6.888 18.283 ;
     RECT  9.36 18.275 9.384 18.283 ;
     RECT  30.192 18.229 35.832 18.283 ;
     RECT  0.048 17.365 1.752 18.357 ;
     RECT  45.792 18.227 49.8 18.411 ;
     RECT  0.048 18.357 2.328 18.419 ;
     RECT  15.984 18.133 16.752 18.469 ;
     RECT  43.344 17.707 44.712 18.485 ;
     RECT  45.792 18.411 46.776 18.485 ;
     RECT  24.576 17.643 24.648 18.549 ;
     RECT  40.944 17.707 40.968 18.549 ;
     RECT  27.072 18.219 28.248 18.603 ;
     RECT  64.176 18.229 64.296 18.611 ;
     RECT  21.216 18.179 22.392 18.661 ;
     RECT  56.352 18.131 56.712 18.667 ;
     RECT  24.096 18.549 24.648 18.707 ;
     RECT  30.192 18.283 35.448 18.707 ;
     RECT  51.648 18.275 53.016 18.707 ;
     RECT  54 18.275 54.744 18.709 ;
     RECT  56.352 18.667 56.52 18.709 ;
     RECT  21.216 18.661 22.776 18.731 ;
     RECT  24.528 18.707 24.648 18.731 ;
     RECT  5.64 18.283 6.072 18.741 ;
     RECT  25.728 18.133 25.752 18.757 ;
     RECT  30.816 18.707 35.448 18.795 ;
     RECT  40.944 18.549 41.16 18.795 ;
     RECT  63.504 18.709 63.528 18.795 ;
     RECT  5.04 18.741 6.072 18.803 ;
     RECT  21.216 18.731 22.248 18.803 ;
     RECT  37.056 17.987 38.352 18.805 ;
     RECT  57.984 17.843 61.752 18.805 ;
     RECT  34.752 18.795 35.448 18.851 ;
     RECT  10.464 18.219 11.352 18.853 ;
     RECT  54 18.709 56.52 18.859 ;
     RECT  14.256 17.893 14.424 18.899 ;
     RECT  57.84 18.805 61.752 18.899 ;
     RECT  0.144 18.419 2.328 18.923 ;
     RECT  40.944 18.795 41.064 18.923 ;
     RECT  43.344 18.485 46.776 18.923 ;
     RECT  25.728 18.757 25.848 18.997 ;
     RECT  27.12 18.603 28.248 18.997 ;
     RECT  37.056 18.805 38.568 18.997 ;
     RECT  25.056 18.997 25.848 19.051 ;
     RECT  51.648 18.707 52.536 19.061 ;
     RECT  21.216 18.803 22.152 19.091 ;
     RECT  25.056 19.051 25.656 19.091 ;
     RECT  57.84 18.899 60.072 19.115 ;
     RECT  0.24 18.923 2.328 19.189 ;
     RECT  61.92 18.933 61.944 19.189 ;
     RECT  25.632 19.091 25.656 19.235 ;
     RECT  61.92 19.189 63.288 19.243 ;
     RECT  34.752 18.851 35.352 19.283 ;
     RECT  15.552 18.469 16.752 19.285 ;
     RECT  34.8 19.283 35.352 19.307 ;
     RECT  59.28 19.115 60.072 19.307 ;
     RECT  57.84 19.115 57.912 19.317 ;
     RECT  4.512 19.285 4.536 19.371 ;
     RECT  51.504 19.061 52.536 19.371 ;
     RECT  54 18.859 56.424 19.379 ;
     RECT  57.552 19.317 57.912 19.379 ;
     RECT  59.64 19.307 60.072 19.379 ;
     RECT  37.056 18.997 38.76 19.381 ;
     RECT  46.704 18.923 46.776 19.381 ;
     RECT  57.552 19.379 57.576 19.427 ;
     RECT  18.24 19.237 18.264 19.435 ;
     RECT  41.04 18.923 41.064 19.435 ;
     RECT  47.904 18.411 49.8 19.435 ;
     RECT  54 19.379 55.368 19.445 ;
     RECT  20.544 19.381 20.568 19.475 ;
     RECT  14.832 19.285 16.752 19.509 ;
     RECT  27.12 18.997 28.632 19.509 ;
     RECT  27.12 19.509 29.544 19.523 ;
     RECT  30.816 18.795 33.672 19.563 ;
     RECT  14.832 19.509 16.872 19.571 ;
     RECT  27.12 19.523 28.488 19.571 ;
     RECT  53.568 19.445 55.368 19.571 ;
     RECT  46.704 19.381 46.824 19.573 ;
     RECT  12.816 18.219 12.84 19.621 ;
     RECT  32.064 19.563 33.672 19.691 ;
     RECT  61.968 19.243 63.288 19.691 ;
     RECT  12.576 19.621 12.84 19.701 ;
     RECT  10.416 18.853 11.352 19.765 ;
     RECT  29.52 19.523 29.544 19.765 ;
     RECT  15.984 19.571 16.872 19.811 ;
     RECT  5.64 18.803 6.072 19.813 ;
     RECT  7.968 19.765 7.992 19.813 ;
     RECT  5.64 19.813 7.992 19.819 ;
     RECT  46.704 19.573 47.736 19.819 ;
     RECT  62.016 19.691 63.288 19.819 ;
     RECT  14.832 19.571 14.856 19.947 ;
     RECT  62.496 19.819 63.288 19.947 ;
     RECT  34.8 19.307 34.824 19.955 ;
     RECT  43.344 18.923 45.672 19.955 ;
     RECT  48.84 19.435 49.8 19.955 ;
     RECT  21.744 19.091 22.152 19.957 ;
     RECT  5.64 19.819 7.416 20.003 ;
     RECT  37.056 19.381 38.904 20.011 ;
     RECT  21.744 19.957 22.392 20.051 ;
     RECT  32.16 19.691 33.672 20.075 ;
     RECT  5.64 20.003 6.888 20.085 ;
     RECT  46.704 19.819 47.016 20.085 ;
     RECT  5.52 20.085 6.888 20.139 ;
     RECT  0.24 19.189 2.904 20.147 ;
     RECT  63.456 20.085 63.48 20.147 ;
     RECT  0.24 20.147 2.28 20.149 ;
     RECT  27.12 19.571 28.392 20.149 ;
     RECT  29.52 19.765 29.736 20.149 ;
     RECT  30.816 19.563 31.08 20.149 ;
     RECT  56.4 19.379 56.424 20.149 ;
     RECT  52.512 19.371 52.536 20.197 ;
     RECT  24.624 20.149 24.648 20.203 ;
     RECT  26.784 20.149 28.392 20.245 ;
     RECT  51.264 19.573 51.288 20.277 ;
     RECT  10.416 19.765 11.592 20.293 ;
     RECT  12.576 19.701 13.656 20.293 ;
     RECT  46.416 20.085 47.016 20.331 ;
     RECT  23.616 20.277 23.64 20.339 ;
     RECT  21.744 20.051 22.248 20.341 ;
     RECT  0.144 20.149 2.28 20.395 ;
     RECT  56.4 20.149 57.096 20.405 ;
     RECT  16.44 19.811 16.872 20.437 ;
     RECT  21.456 20.341 22.248 20.459 ;
     RECT  10.416 20.293 13.656 20.483 ;
     RECT  5.52 20.139 5.952 20.485 ;
     RECT  16.44 20.437 16.968 20.523 ;
     RECT  51.024 20.277 51.288 20.523 ;
     RECT  52.512 20.197 53.016 20.523 ;
     RECT  24.096 20.405 24.12 20.531 ;
     RECT  26.688 20.245 28.392 20.533 ;
     RECT  29.52 20.149 31.08 20.533 ;
     RECT  40.608 20.277 40.632 20.533 ;
     RECT  52.512 20.523 52.728 20.533 ;
     RECT  26.688 20.533 31.08 20.581 ;
     RECT  37.056 20.011 38.352 20.581 ;
     RECT  35.472 20.437 35.496 20.597 ;
     RECT  36.72 20.581 38.352 20.597 ;
     RECT  26.496 20.581 31.08 20.627 ;
     RECT  21.744 20.459 22.248 20.651 ;
     RECT  26.496 20.627 29.64 20.651 ;
     RECT  40.128 20.533 40.632 20.661 ;
     RECT  43.344 19.955 45.144 20.661 ;
     RECT  8.496 20.661 8.52 20.723 ;
     RECT  42.48 20.661 45.144 20.725 ;
     RECT  54.24 19.571 55.368 20.725 ;
     RECT  56.4 20.405 57.288 20.725 ;
     RECT  58.512 20.629 58.536 20.725 ;
     RECT  59.64 19.379 59.952 20.725 ;
     RECT  32.16 20.075 32.952 20.773 ;
     RECT  54.24 20.725 60.456 20.773 ;
     RECT  40.128 20.661 41.064 20.789 ;
     RECT  25.488 20.725 25.512 20.819 ;
     RECT  39.36 20.789 41.064 20.843 ;
     RECT  31.536 20.773 32.952 20.907 ;
     RECT  42.432 20.725 45.144 20.917 ;
     RECT  48.84 19.955 49.56 20.917 ;
     RECT  54.048 20.773 60.456 20.917 ;
     RECT  63.84 20.485 63.864 20.917 ;
     RECT  63.84 20.917 64.248 20.963 ;
     RECT  10.416 20.483 11.448 20.965 ;
     RECT  3.36 20.149 3.384 20.971 ;
     RECT  64.224 20.963 64.248 20.971 ;
     RECT  42 20.917 45.144 21.099 ;
     RECT  16.44 20.523 16.752 21.109 ;
     RECT  32.208 20.907 32.952 21.109 ;
     RECT  34.08 20.389 34.104 21.109 ;
     RECT  35.472 20.597 38.352 21.109 ;
     RECT  42.096 21.099 45.144 21.109 ;
     RECT  46.416 20.331 46.728 21.109 ;
     RECT  48.672 20.917 49.56 21.109 ;
     RECT  51.216 20.523 51.288 21.109 ;
     RECT  52.464 20.533 52.728 21.109 ;
     RECT  12.624 20.483 13.656 21.155 ;
     RECT  32.208 21.109 34.104 21.163 ;
     RECT  54.048 20.917 60.744 21.163 ;
     RECT  47.76 21.109 49.56 21.237 ;
     RECT  32.256 21.163 34.104 21.301 ;
     RECT  5.136 20.485 5.952 21.349 ;
     RECT  42.096 21.109 46.728 21.355 ;
     RECT  5.088 21.349 5.952 21.365 ;
     RECT  47.76 21.237 49.608 21.395 ;
     RECT  0.24 20.395 2.28 21.397 ;
     RECT  5.088 21.365 6.888 21.419 ;
     RECT  27.072 20.651 29.64 21.419 ;
     RECT  57.12 21.163 60.744 21.419 ;
     RECT  24.24 21.365 24.264 21.443 ;
     RECT  10.32 20.965 11.448 21.493 ;
     RECT  35.328 21.109 38.352 21.493 ;
     RECT  39.36 20.843 40.776 21.493 ;
     RECT  54.048 21.163 55.32 21.493 ;
     RECT  62.16 20.965 62.184 21.493 ;
     RECT  62.16 21.493 62.712 21.541 ;
     RECT  35.328 21.493 40.776 21.587 ;
     RECT  0.24 21.397 2.376 21.589 ;
     RECT  53.712 21.493 55.32 21.611 ;
     RECT  62.16 21.541 63.096 21.611 ;
     RECT  0.048 21.589 2.376 21.637 ;
     RECT  15.456 21.109 16.752 21.637 ;
     RECT  46.656 21.355 46.728 21.675 ;
     RECT  5.52 21.419 6.888 21.683 ;
     RECT  9.12 21.621 9.144 21.683 ;
     RECT  35.328 21.587 39.624 21.683 ;
     RECT  57.216 21.419 60.744 21.683 ;
     RECT  51.216 21.109 52.728 21.685 ;
     RECT  53.712 21.611 54.648 21.685 ;
     RECT  15.456 21.637 17.448 21.733 ;
     RECT  58.944 21.683 60.744 21.733 ;
     RECT  62.16 21.611 62.808 21.733 ;
     RECT  15.456 21.733 17.544 21.739 ;
     RECT  9.072 21.685 9.096 21.779 ;
     RECT  51.216 21.685 54.648 21.779 ;
     RECT  10.32 21.493 11.64 21.781 ;
     RECT  12.624 21.155 12.936 21.781 ;
     RECT  58.944 21.733 62.808 21.803 ;
     RECT  21.744 20.651 22.152 21.813 ;
     RECT  51.216 21.779 51.24 21.875 ;
     RECT  52.224 21.779 54.648 21.875 ;
     RECT  10.32 21.781 12.936 21.877 ;
     RECT  19.248 21.541 19.272 21.877 ;
     RECT  27.072 21.419 29.112 21.877 ;
     RECT  52.224 21.875 52.968 21.923 ;
     RECT  0.048 21.637 2.808 21.931 ;
     RECT  52.224 21.923 52.728 21.931 ;
     RECT  10.272 21.877 12.936 21.971 ;
     RECT  19.248 21.877 19.704 21.971 ;
     RECT  62.016 21.803 62.808 21.971 ;
     RECT  15.984 21.739 17.544 21.973 ;
     RECT  57.216 21.683 57.624 21.995 ;
     RECT  21.408 21.813 22.824 22.005 ;
     RECT  25.392 21.749 25.416 22.005 ;
     RECT  40.704 21.587 40.776 22.021 ;
     RECT  10.608 21.971 12.936 22.067 ;
     RECT  21.408 22.005 23.544 22.067 ;
     RECT  8.688 21.877 9.048 22.069 ;
     RECT  25.104 22.005 25.416 22.069 ;
     RECT  26.448 21.877 29.112 22.069 ;
     RECT  32.256 21.301 34.2 22.069 ;
     RECT  35.328 21.683 39.192 22.069 ;
     RECT  40.704 22.021 40.92 22.069 ;
     RECT  42.096 21.355 45.576 22.069 ;
     RECT  51.12 21.877 51.192 22.069 ;
     RECT  7.968 22.069 9.048 22.123 ;
     RECT  62.064 21.971 62.808 22.123 ;
     RECT  15.984 21.973 18.168 22.163 ;
     RECT  19.824 22.005 19.992 22.165 ;
     RECT  48.336 21.395 49.608 22.197 ;
     RECT  50.784 22.069 51.192 22.197 ;
     RECT  25.104 22.069 29.112 22.211 ;
     RECT  40.704 22.069 45.576 22.211 ;
     RECT  8.4 22.123 9.048 22.251 ;
     RECT  42.48 22.211 45.576 22.259 ;
     RECT  3.984 22.069 4.008 22.261 ;
     RECT  30.72 21.621 30.984 22.309 ;
     RECT  32.256 22.069 39.192 22.309 ;
     RECT  7.248 22.261 7.368 22.315 ;
     RECT  62.16 22.123 62.808 22.315 ;
     RECT  30.72 22.309 39.192 22.355 ;
     RECT  0.048 21.931 2.712 22.451 ;
     RECT  18.576 22.389 18.84 22.451 ;
     RECT  57.6 21.995 57.624 22.451 ;
     RECT  46.8 21.733 46.92 22.453 ;
     RECT  48.336 22.197 51.192 22.453 ;
     RECT  25.392 22.211 29.112 22.499 ;
     RECT  46.8 22.453 51.192 22.499 ;
     RECT  3.744 22.261 4.008 22.507 ;
     RECT  18.576 22.451 18.696 22.507 ;
     RECT  21.408 22.067 23.4 22.507 ;
     RECT  5.64 21.683 6.072 22.547 ;
     RECT  30.768 22.355 39.192 22.547 ;
     RECT  29.088 22.499 29.112 22.549 ;
     RECT  21.408 22.507 22.248 22.595 ;
     RECT  40.704 22.211 41.016 22.595 ;
     RECT  46.8 22.499 49.368 22.691 ;
     RECT  7.344 22.315 7.368 22.739 ;
     RECT  32.352 22.547 39.192 22.739 ;
     RECT  50.352 22.499 51.192 22.739 ;
     RECT  5.64 22.547 5.952 22.741 ;
     RECT  15.984 22.163 17.112 22.741 ;
     RECT  19.824 22.165 20.28 22.741 ;
     RECT  21.408 22.595 22.152 22.741 ;
     RECT  10.848 22.067 12.936 22.789 ;
     RECT  14.064 22.741 14.088 22.789 ;
     RECT  58.944 21.803 60.744 22.789 ;
     RECT  0.048 22.451 0.936 22.835 ;
     RECT  46.8 22.691 49.152 22.835 ;
     RECT  58.848 22.789 60.744 22.837 ;
     RECT  34.032 22.739 39.192 22.883 ;
     RECT  46.8 22.835 47.832 22.883 ;
     RECT  29.088 22.549 29.448 22.965 ;
     RECT  58.848 22.837 60.984 22.965 ;
     RECT  34.176 22.883 39.192 22.981 ;
     RECT  50.448 22.739 51.192 22.981 ;
     RECT  52.224 21.931 52.44 22.981 ;
     RECT  15.36 22.741 17.112 23.019 ;
     RECT  19.824 22.741 22.152 23.019 ;
     RECT  50.448 22.981 52.44 23.019 ;
     RECT  40.656 22.965 40.68 23.027 ;
     RECT  58.08 22.965 60.984 23.027 ;
     RECT  10.848 22.789 14.088 23.029 ;
     RECT  23.376 22.507 23.4 23.029 ;
     RECT  29.088 22.965 29.496 23.029 ;
     RECT  34.176 22.981 39.48 23.029 ;
     RECT  56.448 22.965 56.952 23.029 ;
     RECT  25.392 22.499 27.912 23.083 ;
     RECT  30.768 22.547 31.32 23.083 ;
     RECT  34.176 23.029 39.576 23.083 ;
     RECT  42.48 22.259 45.24 23.083 ;
     RECT  51.12 23.019 52.44 23.083 ;
     RECT  42.48 23.083 44.52 23.123 ;
     RECT  56.256 23.029 56.952 23.123 ;
     RECT  9.024 22.251 9.048 23.125 ;
     RECT  15.936 23.019 17.112 23.125 ;
     RECT  34.176 23.083 34.2 23.171 ;
     RECT  35.328 23.083 39.576 23.171 ;
     RECT  3.984 22.507 4.008 23.173 ;
     RECT  5.088 22.741 5.952 23.173 ;
     RECT  51.552 23.083 52.44 23.173 ;
     RECT  46.8 22.883 46.824 23.219 ;
     RECT  2.016 22.451 2.712 23.317 ;
     RECT  9.024 23.125 9.144 23.317 ;
     RECT  29.088 23.029 29.64 23.317 ;
     RECT  23.376 23.029 23.976 23.365 ;
     RECT  54.24 21.875 54.648 23.365 ;
     RECT  29.088 23.317 29.688 23.413 ;
     RECT  0.048 22.835 0.744 23.459 ;
     RECT  10.848 23.029 14.328 23.509 ;
     RECT  2.016 23.317 2.904 23.541 ;
     RECT  3.984 23.173 5.952 23.541 ;
     RECT  10.608 23.509 14.328 23.541 ;
     RECT  15.936 23.125 17.736 23.541 ;
     RECT  51.552 23.173 52.824 23.541 ;
     RECT  54.24 23.365 55.272 23.541 ;
     RECT  42.48 23.123 44.472 23.557 ;
     RECT  41.664 23.557 44.472 23.595 ;
     RECT  1.776 23.541 5.952 23.603 ;
     RECT  15.936 23.541 18.504 23.603 ;
     RECT  26.112 23.083 27.912 23.603 ;
     RECT  3.984 23.603 5.952 23.605 ;
     RECT  31.296 23.083 31.32 23.605 ;
     RECT  32.352 22.739 32.952 23.605 ;
     RECT  0.144 23.459 0.744 23.651 ;
     RECT  8.544 23.317 9.144 23.653 ;
     RECT  3.984 23.605 6.072 23.659 ;
     RECT  8.208 23.653 9.144 23.669 ;
     RECT  10.464 23.541 14.328 23.669 ;
     RECT  48.84 22.835 49.152 23.701 ;
     RECT  39.552 23.171 39.576 23.733 ;
     RECT  48.84 23.701 49.464 23.787 ;
     RECT  51.552 23.541 55.272 23.787 ;
     RECT  15.936 23.603 18.36 23.795 ;
     RECT  0.24 23.651 0.744 23.797 ;
     RECT  1.776 23.603 2.904 23.797 ;
     RECT  41.664 23.595 43.896 23.797 ;
     RECT  62.16 22.315 62.184 23.797 ;
     RECT  47.808 22.883 47.832 23.843 ;
     RECT  62.016 23.797 62.184 23.845 ;
     RECT  0.24 23.797 2.904 23.851 ;
     RECT  35.328 23.171 38.472 23.851 ;
     RECT  62.016 23.845 62.52 23.851 ;
     RECT  5.64 23.659 6.072 23.861 ;
     RECT  0.24 23.851 2.52 23.891 ;
     RECT  5.64 23.861 6.792 23.893 ;
     RECT  8.208 23.669 14.328 23.893 ;
     RECT  62.448 23.851 62.52 23.893 ;
     RECT  5.64 23.893 14.328 23.915 ;
     RECT  19.968 23.019 22.152 23.915 ;
     RECT  58.224 23.027 60.984 23.915 ;
     RECT  9.12 23.915 14.328 23.939 ;
     RECT  15.936 23.795 18.264 23.939 ;
     RECT  5.64 23.915 7.704 23.979 ;
     RECT  31.296 23.605 32.952 23.979 ;
     RECT  3.984 23.659 4.008 23.987 ;
     RECT  56.448 23.123 56.952 23.989 ;
     RECT  58.224 23.915 58.344 23.989 ;
     RECT  39.552 23.733 40.152 24.053 ;
     RECT  48.84 23.787 49.368 24.053 ;
     RECT  46.176 23.269 46.2 24.107 ;
     RECT  23.376 23.365 24.072 24.117 ;
     RECT  51.552 23.787 51.864 24.117 ;
     RECT  1.584 23.891 2.52 24.131 ;
     RECT  31.392 23.979 32.952 24.131 ;
     RECT  47.952 24.053 49.368 24.131 ;
     RECT  23.28 24.117 24.072 24.179 ;
     RECT  41.232 23.797 43.896 24.179 ;
     RECT  12.768 23.939 14.328 24.181 ;
     RECT  27.24 23.603 27.912 24.229 ;
     RECT  1.584 24.131 1.8 24.235 ;
     RECT  12.768 24.181 14.568 24.235 ;
     RECT  5.64 23.979 7.368 24.299 ;
     RECT  31.872 24.131 32.952 24.309 ;
     RECT  39.552 24.053 40.248 24.309 ;
     RECT  41.232 24.179 43.848 24.309 ;
     RECT  25.872 24.309 25.896 24.371 ;
     RECT  50.736 24.117 51.864 24.371 ;
     RECT  53.04 23.787 55.272 24.373 ;
     RECT  56.448 23.989 58.344 24.373 ;
     RECT  27.24 24.229 27.96 24.421 ;
     RECT  29.088 23.413 30.264 24.421 ;
     RECT  20.976 23.915 22.152 24.427 ;
     RECT  36.528 23.851 38.472 24.427 ;
     RECT  31.872 24.309 33.096 24.437 ;
     RECT  62.448 23.893 62.904 24.437 ;
     RECT  25.68 24.421 25.704 24.491 ;
     RECT  27.24 24.421 30.264 24.491 ;
     RECT  53.04 24.373 58.344 24.491 ;
     RECT  37.104 24.427 38.472 24.501 ;
     RECT  39.552 24.309 43.848 24.501 ;
     RECT  1.776 24.235 1.8 24.515 ;
     RECT  19.632 23.989 19.656 24.515 ;
     RECT  25.056 24.501 25.08 24.563 ;
     RECT  59.64 23.915 60.984 24.661 ;
     RECT  12.768 24.235 14.232 24.683 ;
     RECT  62.448 24.437 62.952 24.693 ;
     RECT  62.448 24.693 64.152 24.803 ;
     RECT  48.144 24.131 49.368 24.853 ;
     RECT  29.136 24.491 30.264 24.899 ;
     RECT  7.296 24.299 7.368 24.949 ;
     RECT  56.448 24.491 58.344 24.949 ;
     RECT  59.64 24.661 61.368 24.949 ;
     RECT  9.12 23.939 11.688 24.997 ;
     RECT  16.44 23.939 18.264 24.997 ;
     RECT  48.144 24.853 49.464 24.997 ;
     RECT  3.984 24.997 4.008 25.013 ;
     RECT  56.448 24.949 61.368 25.013 ;
     RECT  62.448 24.803 63.48 25.013 ;
     RECT  3.888 25.013 4.008 25.067 ;
     RECT  30.096 24.899 30.264 25.077 ;
     RECT  35.328 23.851 35.448 25.077 ;
     RECT  3.888 25.067 3.912 25.091 ;
     RECT  51.264 24.371 51.864 25.093 ;
     RECT  30.096 25.077 30.744 25.139 ;
     RECT  48.144 24.997 50.184 25.139 ;
     RECT  53.04 24.491 55.464 25.139 ;
     RECT  56.448 25.013 63.48 25.139 ;
     RECT  31.872 24.437 33.624 25.141 ;
     RECT  35.328 25.077 36.072 25.141 ;
     RECT  51.264 25.093 52.008 25.141 ;
     RECT  53.04 25.139 53.064 25.141 ;
     RECT  24.048 24.179 24.072 25.189 ;
     RECT  31.824 25.141 36.072 25.195 ;
     RECT  16.44 24.997 18.888 25.205 ;
     RECT  27.24 24.491 27.552 25.205 ;
     RECT  37.104 24.501 43.848 25.237 ;
     RECT  59.64 25.139 63.048 25.259 ;
     RECT  37.104 25.237 44.088 25.285 ;
     RECT  32.64 25.195 36.072 25.323 ;
     RECT  5.64 24.299 5.952 25.333 ;
     RECT  7.296 24.949 7.992 25.333 ;
     RECT  9.12 24.997 11.784 25.333 ;
     RECT  21.6 24.427 22.152 25.333 ;
     RECT  26.88 25.205 27.552 25.333 ;
     RECT  34.608 25.323 36.072 25.379 ;
     RECT  37.104 25.285 44.376 25.381 ;
     RECT  45.36 25.077 45.384 25.381 ;
     RECT  20.496 25.013 20.568 25.387 ;
     RECT  26.208 25.333 27.552 25.387 ;
     RECT  37.104 25.381 45.384 25.387 ;
     RECT  54.144 25.139 55.464 25.387 ;
     RECT  59.64 25.259 60.696 25.387 ;
     RECT  24.048 25.189 24.888 25.397 ;
     RECT  26.784 25.387 27.552 25.427 ;
     RECT  34.608 25.379 35.352 25.451 ;
     RECT  42.528 25.387 45.384 25.461 ;
     RECT  46.704 25.333 46.728 25.461 ;
     RECT  5.64 25.333 11.784 25.475 ;
     RECT  54.144 25.387 54.792 25.475 ;
     RECT  5.64 25.475 7.992 25.515 ;
     RECT  12.768 24.683 13.656 25.515 ;
     RECT  21.6 25.333 22.344 25.571 ;
     RECT  9.216 25.475 11.784 25.621 ;
     RECT  12.768 25.515 13.128 25.621 ;
     RECT  20.496 25.387 20.52 25.621 ;
     RECT  9.216 25.621 13.128 25.643 ;
     RECT  20.064 25.621 20.52 25.653 ;
     RECT  24 25.397 24.888 25.653 ;
     RECT  56.448 25.139 57.912 25.653 ;
     RECT  14.928 25.653 14.952 25.669 ;
     RECT  15.936 25.205 18.888 25.669 ;
     RECT  9.216 25.643 13.08 25.715 ;
     RECT  55.776 25.653 57.912 25.715 ;
     RECT  62.16 25.259 63.048 25.715 ;
     RECT  14.928 25.669 18.888 25.717 ;
     RECT  19.968 25.653 20.52 25.717 ;
     RECT  37.104 25.387 41.16 25.717 ;
     RECT  14.928 25.717 20.52 25.763 ;
     RECT  42.528 25.461 46.728 25.845 ;
     RECT  9.216 25.715 9.24 25.859 ;
     RECT  48.432 25.139 50.184 25.909 ;
     RECT  51.264 25.141 53.064 26.027 ;
     RECT  5.64 25.515 7.224 26.037 ;
     RECT  10.224 25.715 13.08 26.051 ;
     RECT  21.648 25.571 22.344 26.051 ;
     RECT  30.096 25.139 30.12 26.053 ;
     RECT  37.056 25.717 41.16 26.099 ;
     RECT  55.776 25.715 57.096 26.099 ;
     RECT  2.4 26.053 2.424 26.101 ;
     RECT  62.448 25.715 63.048 26.101 ;
     RECT  48.432 25.909 50.28 26.155 ;
     RECT  55.776 26.099 56.664 26.155 ;
     RECT  62.448 26.101 63.336 26.155 ;
     RECT  50.256 26.155 50.28 26.165 ;
     RECT  51.264 26.027 52.008 26.165 ;
     RECT  27.24 25.427 27.552 26.197 ;
     RECT  24 25.653 25.32 26.229 ;
     RECT  28.992 26.053 29.016 26.229 ;
     RECT  30 26.053 30.12 26.229 ;
     RECT  42.528 25.845 47.256 26.229 ;
     RECT  48.432 26.155 49.272 26.229 ;
     RECT  2.4 26.101 2.52 26.243 ;
     RECT  28.992 26.229 30.12 26.243 ;
     RECT  40.896 26.099 41.16 26.243 ;
     RECT  62.448 26.155 62.712 26.243 ;
     RECT  23.856 26.229 25.32 26.291 ;
     RECT  42.528 26.229 49.272 26.291 ;
     RECT  50.256 26.165 52.008 26.291 ;
     RECT  59.64 25.387 60.408 26.291 ;
     RECT  27.24 26.197 27.816 26.293 ;
     RECT  32.64 25.323 33.288 26.293 ;
     RECT  32.64 26.293 33.816 26.341 ;
     RECT  34.8 25.451 35.352 26.357 ;
     RECT  37.056 26.099 39.912 26.357 ;
     RECT  5.136 26.037 7.224 26.411 ;
     RECT  29.28 26.243 30.12 26.421 ;
     RECT  42.672 26.291 47.4 26.475 ;
     RECT  15.024 25.763 20.52 26.483 ;
     RECT  53.04 26.027 53.064 26.483 ;
     RECT  55.872 26.155 56.664 26.483 ;
     RECT  7.2 26.411 7.224 26.539 ;
     RECT  43.296 26.475 47.4 26.539 ;
     RECT  23.664 26.357 23.688 26.549 ;
     RECT  29.28 26.421 30.264 26.549 ;
     RECT  31.92 26.341 33.816 26.549 ;
     RECT  54.144 25.475 54.552 26.581 ;
     RECT  15.024 26.483 18.456 26.603 ;
     RECT  24.672 26.291 25.32 26.603 ;
     RECT  29.28 26.549 33.816 26.627 ;
     RECT  56.208 26.483 56.664 26.627 ;
     RECT  3.984 26.053 4.008 26.629 ;
     RECT  5.136 26.411 5.952 26.629 ;
     RECT  31.68 26.627 33.816 26.629 ;
     RECT  34.8 26.357 39.912 26.629 ;
     RECT  54.048 26.581 54.552 26.629 ;
     RECT  54.048 26.629 54.648 26.667 ;
     RECT  23.184 26.549 23.688 26.723 ;
     RECT  12.768 26.051 13.08 26.725 ;
     RECT  15.024 26.603 17.976 26.731 ;
     RECT  54.144 26.667 54.648 26.731 ;
     RECT  19.536 26.483 20.52 26.795 ;
     RECT  31.68 26.629 39.912 26.795 ;
     RECT  12.768 26.725 13.32 26.805 ;
     RECT  15.024 26.731 17.88 26.805 ;
     RECT  19.872 26.795 20.52 26.805 ;
     RECT  21.648 26.051 22.152 26.805 ;
     RECT  10.224 26.051 11.784 26.819 ;
     RECT  41.04 26.243 41.16 26.859 ;
     RECT  10.32 26.819 11.784 26.867 ;
     RECT  23.664 26.723 23.688 26.867 ;
     RECT  43.296 26.539 47.256 26.867 ;
     RECT  50.256 26.291 51.72 26.867 ;
     RECT  2.4 26.243 2.424 26.869 ;
     RECT  25.2 26.603 25.32 26.917 ;
     RECT  12.768 26.805 17.88 26.923 ;
     RECT  3.984 26.629 5.952 26.997 ;
     RECT  3.408 26.997 5.952 27.051 ;
     RECT  12.768 26.923 15.048 27.059 ;
     RECT  43.296 26.867 44.28 27.059 ;
     RECT  45.552 26.867 47.256 27.059 ;
     RECT  62.592 26.243 62.712 27.059 ;
     RECT  61.584 26.869 61.608 27.061 ;
     RECT  34.8 26.795 39.912 27.115 ;
     RECT  0.24 23.891 0.552 27.157 ;
     RECT  1.584 26.869 2.424 27.157 ;
     RECT  34.8 27.115 34.824 27.179 ;
     RECT  36.24 27.115 39.912 27.179 ;
     RECT  3.408 27.051 4.008 27.203 ;
     RECT  27.24 26.293 28.248 27.205 ;
     RECT  29.28 26.627 30.264 27.205 ;
     RECT  3.936 27.203 4.008 27.243 ;
     RECT  5.136 27.051 5.952 27.243 ;
     RECT  48.432 26.291 49.272 27.243 ;
     RECT  56.208 26.627 56.328 27.243 ;
     RECT  59.64 26.291 60.168 27.253 ;
     RECT  14.928 27.059 15.048 27.299 ;
     RECT  61.488 27.061 61.608 27.347 ;
     RECT  62.784 27.189 62.808 27.347 ;
     RECT  43.296 27.059 44.04 27.371 ;
     RECT  25.2 26.917 26.232 27.381 ;
     RECT  27.24 27.205 30.264 27.381 ;
     RECT  48.672 27.243 49.272 27.381 ;
     RECT  36.24 27.179 39 27.395 ;
     RECT  43.296 27.371 43.944 27.395 ;
     RECT  42.144 27.301 42.168 27.435 ;
     RECT  50.688 26.867 50.904 27.435 ;
     RECT  25.2 27.381 30.264 27.443 ;
     RECT  43.344 27.395 43.944 27.443 ;
     RECT  50.88 27.435 50.904 27.443 ;
     RECT  36.24 27.395 38.616 27.563 ;
     RECT  9.072 27.189 9.096 27.573 ;
     RECT  40.176 27.381 40.488 27.587 ;
     RECT  31.68 26.795 33.672 27.627 ;
     RECT  36.24 27.563 38.472 27.635 ;
     RECT  63.216 27.573 63.24 27.635 ;
     RECT  31.68 27.627 33.048 27.683 ;
     RECT  7.344 26.677 7.896 27.685 ;
     RECT  10.464 26.867 11.784 27.685 ;
     RECT  12.768 27.059 13.32 27.685 ;
     RECT  29.76 27.443 30.264 27.691 ;
     RECT  58.32 27.061 58.344 27.701 ;
     RECT  59.64 27.253 60.216 27.701 ;
     RECT  19.872 26.805 22.152 27.731 ;
     RECT  7.344 27.685 8.088 27.755 ;
     RECT  27.24 27.443 28.584 27.755 ;
     RECT  45.552 27.059 45.72 27.779 ;
     RECT  61.296 27.381 61.32 27.827 ;
     RECT  9.072 27.573 9.288 27.829 ;
     RECT  21.12 27.731 22.152 27.829 ;
     RECT  25.2 27.443 26.088 27.829 ;
     RECT  48.672 27.381 49.368 27.829 ;
     RECT  51.936 27.573 51.96 27.829 ;
     RECT  54.24 26.731 54.648 27.829 ;
     RECT  58.32 27.701 60.216 27.829 ;
     RECT  10.464 27.685 13.32 27.875 ;
     RECT  24 27.829 24.024 27.883 ;
     RECT  48.672 27.829 49.896 27.883 ;
     RECT  53.904 27.829 56.04 27.883 ;
     RECT  3.984 27.243 4.008 27.971 ;
     RECT  8.496 27.829 9.432 27.971 ;
     RECT  10.896 27.875 13.32 27.971 ;
     RECT  21.12 27.829 22.392 27.971 ;
     RECT  28.56 27.755 28.584 27.971 ;
     RECT  54.24 27.883 56.04 27.971 ;
     RECT  51.936 27.829 52.44 27.973 ;
     RECT  8.592 27.971 9.432 28.019 ;
     RECT  46.752 27.059 47.256 28.163 ;
     RECT  45.696 27.779 45.72 28.165 ;
     RECT  46.752 28.163 46.968 28.165 ;
     RECT  19.872 27.731 19.896 28.211 ;
     RECT  58.128 27.829 60.216 28.211 ;
     RECT  5.184 27.243 5.952 28.213 ;
     RECT  7.344 27.755 7.512 28.213 ;
     RECT  51.936 27.973 52.632 28.309 ;
     RECT  5.184 28.213 7.512 28.357 ;
     RECT  10.944 27.971 13.32 28.405 ;
     RECT  31.68 27.683 32.952 28.405 ;
     RECT  57.504 28.357 57.528 28.405 ;
     RECT  58.656 28.211 60.216 28.405 ;
     RECT  31.296 28.405 32.952 28.451 ;
     RECT  51.12 28.309 52.632 28.451 ;
     RECT  16.44 26.923 17.88 28.453 ;
     RECT  43.344 27.443 43.752 28.453 ;
     RECT  4.8 28.357 7.512 28.459 ;
     RECT  31.296 28.451 31.32 28.459 ;
     RECT  37.056 27.635 38.472 28.459 ;
     RECT  40.848 28.309 41.016 28.459 ;
     RECT  43.344 28.453 44.52 28.459 ;
     RECT  45.696 28.165 46.968 28.459 ;
     RECT  51.936 28.451 52.632 28.459 ;
     RECT  54.24 27.971 55.848 28.459 ;
     RECT  40.848 28.459 40.872 28.499 ;
     RECT  42.144 28.405 42.168 28.499 ;
     RECT  51.936 28.459 52.536 28.547 ;
     RECT  58.656 28.405 61.032 28.547 ;
     RECT  10.944 28.405 13.944 28.645 ;
     RECT  14.928 27.299 14.952 28.645 ;
     RECT  56.976 28.405 57.528 28.691 ;
     RECT  10.944 28.645 14.952 28.693 ;
     RECT  29.76 27.691 30.072 28.693 ;
     RECT  46.752 28.459 46.968 28.787 ;
     RECT  0.24 27.157 2.424 28.789 ;
     RECT  3.408 28.405 3.432 28.789 ;
     RECT  43.44 28.459 44.52 28.789 ;
     RECT  59.64 28.547 61.032 28.789 ;
     RECT  25.056 27.829 26.088 28.835 ;
     RECT  37.056 28.459 38.352 28.837 ;
     RECT  36.384 28.837 38.352 28.933 ;
     RECT  0.24 28.789 3.432 28.979 ;
     RECT  39.744 28.309 39.768 28.979 ;
     RECT  8.592 28.019 9.288 28.981 ;
     RECT  10.944 28.693 15.096 28.981 ;
     RECT  16.44 28.453 18.168 28.981 ;
     RECT  19.392 28.789 19.416 28.981 ;
     RECT  21.744 27.971 22.248 28.981 ;
     RECT  25.68 28.835 26.088 28.981 ;
     RECT  27.24 27.755 27.552 28.981 ;
     RECT  32.496 28.451 32.952 28.981 ;
     RECT  48.72 27.883 49.896 28.981 ;
     RECT  5.088 28.459 6.264 29.035 ;
     RECT  8.592 28.981 15.096 29.035 ;
     RECT  25.68 28.981 28.104 29.035 ;
     RECT  29.328 28.693 30.072 29.035 ;
     RECT  43.44 28.789 45.624 29.035 ;
     RECT  48.72 28.981 50.76 29.035 ;
     RECT  54.24 28.459 55.32 29.035 ;
     RECT  48.72 29.035 49.152 29.045 ;
     RECT  21.744 28.981 22.296 29.109 ;
     RECT  43.44 29.035 44.52 29.123 ;
     RECT  48.336 29.045 49.152 29.123 ;
     RECT  50.16 29.035 50.184 29.171 ;
     RECT  10.848 29.035 15.096 29.173 ;
     RECT  16.44 28.981 19.416 29.173 ;
     RECT  34.8 28.981 34.824 29.173 ;
     RECT  63.024 28.837 63.048 29.173 ;
     RECT  40.56 29.109 40.584 29.219 ;
     RECT  46.944 28.787 46.968 29.219 ;
     RECT  54.24 29.035 54.696 29.219 ;
     RECT  34.224 29.173 34.824 29.227 ;
     RECT  63.024 29.173 63.288 29.227 ;
     RECT  0.24 28.979 0.984 29.267 ;
     RECT  10.848 29.173 19.656 29.291 ;
     RECT  25.68 29.035 27.912 29.315 ;
     RECT  45.6 29.035 45.624 29.315 ;
     RECT  2.112 28.979 3.432 29.365 ;
     RECT  57.504 28.691 57.528 29.365 ;
     RECT  12.912 29.291 19.656 29.419 ;
     RECT  57.504 29.365 58.296 29.419 ;
     RECT  36.144 28.933 38.352 29.461 ;
     RECT  25.92 29.315 27.912 29.507 ;
     RECT  32.496 28.981 33.048 29.509 ;
     RECT  59.64 28.789 61.08 29.509 ;
     RECT  51.936 28.547 51.96 29.557 ;
     RECT  59.64 29.509 61.608 29.557 ;
     RECT  2.112 29.365 3.672 29.603 ;
     RECT  23.472 28.309 23.496 29.605 ;
     RECT  58.752 29.557 61.608 29.605 ;
     RECT  63.024 29.227 63.048 29.605 ;
     RECT  58.752 29.605 63.048 29.611 ;
     RECT  7.44 28.459 7.512 29.621 ;
     RECT  35.184 29.461 38.352 29.651 ;
     RECT  21.648 29.109 22.392 29.685 ;
     RECT  23.472 29.605 23.592 29.685 ;
     RECT  36.288 29.651 38.352 29.699 ;
     RECT  5.52 29.035 6.264 29.749 ;
     RECT  7.344 29.621 7.512 29.749 ;
     RECT  8.592 29.035 9.816 29.749 ;
     RECT  62.304 29.611 63.048 29.795 ;
     RECT  21.648 29.685 23.592 29.797 ;
     RECT  12.912 29.419 14.856 29.803 ;
     RECT  54.24 29.219 54.552 29.845 ;
     RECT  21.648 29.797 24.264 29.877 ;
     RECT  2.112 29.603 3.048 29.891 ;
     RECT  35.184 29.651 35.208 29.931 ;
     RECT  14.832 29.803 14.856 29.939 ;
     RECT  21.648 29.877 24.504 29.939 ;
     RECT  16.32 29.419 19.656 29.941 ;
     RECT  21.648 29.939 23.928 29.941 ;
     RECT  32.496 29.509 33.24 29.941 ;
     RECT  51.84 29.557 51.96 29.941 ;
     RECT  2.688 29.891 3.048 29.995 ;
     RECT  57.408 29.893 57.432 29.995 ;
     RECT  5.52 29.749 9.816 30.035 ;
     RECT  43.44 29.123 43.752 30.085 ;
     RECT  31.968 29.941 33.24 30.133 ;
     RECT  43.296 30.085 43.752 30.133 ;
     RECT  31.728 30.133 33.24 30.187 ;
     RECT  30.096 29.813 30.12 30.197 ;
     RECT  48.48 29.123 49.152 30.197 ;
     RECT  29.424 30.197 30.744 30.261 ;
     RECT  29.232 30.261 30.744 30.275 ;
     RECT  26.592 29.507 27.912 30.277 ;
     RECT  29.232 30.275 30.168 30.277 ;
     RECT  26.592 30.277 30.168 30.323 ;
     RECT  36.288 29.699 36.312 30.371 ;
     RECT  55.968 30.325 55.992 30.379 ;
     RECT  51.84 29.941 52.44 30.389 ;
     RECT  53.616 29.845 54.552 30.389 ;
     RECT  5.52 30.035 5.952 30.421 ;
     RECT  43.296 30.133 43.848 30.421 ;
     RECT  26.592 30.323 28.728 30.443 ;
     RECT  51.84 30.389 54.552 30.467 ;
     RECT  42.768 30.421 43.848 30.507 ;
     RECT  25.2 30.373 25.224 30.515 ;
     RECT  50.784 30.421 50.808 30.517 ;
     RECT  41.472 30.261 41.496 30.563 ;
     RECT  6.96 30.035 9.816 30.565 ;
     RECT  10.848 29.291 11.88 30.565 ;
     RECT  21.168 29.941 23.928 30.565 ;
     RECT  26.592 30.443 28.104 30.571 ;
     RECT  31.872 30.187 33.24 30.611 ;
     RECT  6.96 30.565 11.88 30.613 ;
     RECT  12.912 29.803 13.704 30.613 ;
     RECT  45.024 30.133 45.048 30.613 ;
     RECT  58.752 29.611 61.176 30.613 ;
     RECT  62.304 29.795 62.328 30.613 ;
     RECT  21.12 30.565 23.928 30.635 ;
     RECT  58.752 30.613 62.328 30.645 ;
     RECT  16.32 29.941 19.944 30.661 ;
     RECT  45.024 30.613 45.768 30.699 ;
     RECT  58.608 30.645 62.328 30.699 ;
     RECT  53.04 30.467 54.552 30.709 ;
     RECT  1.68 30.709 1.704 30.763 ;
     RECT  6.96 30.613 13.704 30.773 ;
     RECT  50.784 30.517 51.528 30.773 ;
     RECT  62.16 30.699 62.328 30.773 ;
     RECT  38.04 29.699 38.352 30.837 ;
     RECT  6.96 30.773 14.136 30.851 ;
     RECT  36.48 30.773 36.504 30.851 ;
     RECT  53.04 30.709 55.512 30.851 ;
     RECT  29.76 30.323 30.168 30.899 ;
     RECT  53.376 30.851 55.512 30.899 ;
     RECT  16.32 30.661 19.992 30.901 ;
     RECT  58.608 30.699 61.032 30.949 ;
     RECT  15.984 30.901 19.992 30.955 ;
     RECT  58.128 30.949 61.032 30.995 ;
     RECT  37.728 30.837 38.352 30.997 ;
     RECT  47.568 30.197 49.152 30.997 ;
     RECT  6.96 30.851 13.464 31.019 ;
     RECT  47.52 30.997 49.152 31.029 ;
     RECT  26.592 30.571 28.056 31.093 ;
     RECT  15.984 30.955 18.696 31.141 ;
     RECT  25.872 31.093 28.056 31.147 ;
     RECT  47.52 31.029 49.272 31.147 ;
     RECT  19.92 30.955 19.992 31.157 ;
     RECT  19.92 31.157 20.328 31.211 ;
     RECT  8.016 31.019 13.464 31.235 ;
     RECT  4.368 30.421 5.952 31.237 ;
     RECT  6.96 31.019 6.984 31.237 ;
     RECT  15.792 31.141 18.696 31.285 ;
     RECT  43.44 30.507 43.848 31.285 ;
     RECT  44.976 31.029 45 31.285 ;
     RECT  58.128 30.995 58.152 31.333 ;
     RECT  31.872 30.611 32.952 31.349 ;
     RECT  20.304 31.211 20.328 31.379 ;
     RECT  21.648 30.635 23.928 31.381 ;
     RECT  2.688 29.995 2.712 31.413 ;
     RECT  13.104 31.235 13.464 31.427 ;
     RECT  62.16 30.773 63.24 31.427 ;
     RECT  4.368 31.237 6.984 31.429 ;
     RECT  2.16 31.413 3.192 31.477 ;
     RECT  4.272 31.429 6.984 31.477 ;
     RECT  37.632 30.997 38.352 31.477 ;
     RECT  8.016 31.235 11.88 31.523 ;
     RECT  21.648 31.381 24.072 31.525 ;
     RECT  25.872 31.147 27.912 31.525 ;
     RECT  34.176 31.477 34.2 31.531 ;
     RECT  36.672 31.477 38.352 31.531 ;
     RECT  30.24 31.349 30.264 31.541 ;
     RECT  21.648 31.525 24.312 31.571 ;
     RECT  48.48 31.147 49.272 31.571 ;
     RECT  10.176 31.523 11.88 31.595 ;
     RECT  21.648 31.571 22.296 31.605 ;
     RECT  13.296 31.427 13.464 31.619 ;
     RECT  30.24 31.541 30.36 31.619 ;
     RECT  59.472 30.995 61.032 31.619 ;
     RECT  35.472 31.141 35.496 31.621 ;
     RECT  21.168 31.605 22.296 31.659 ;
     RECT  21.168 31.659 22.248 31.667 ;
     RECT  34.704 31.621 35.496 31.667 ;
     RECT  36.768 31.531 38.352 31.667 ;
     RECT  55.536 31.541 55.56 31.667 ;
     RECT  57.984 31.333 58.152 31.667 ;
     RECT  21.648 31.667 22.248 31.715 ;
     RECT  14.784 31.285 18.696 31.723 ;
     RECT  55.728 31.669 55.752 31.723 ;
     RECT  59.52 31.619 61.032 31.723 ;
     RECT  50.736 30.773 51.528 31.765 ;
     RECT  2.16 31.477 6.984 31.787 ;
     RECT  48.576 31.571 49.272 31.797 ;
     RECT  43.44 31.285 45 31.861 ;
     RECT  29.04 31.669 29.064 31.909 ;
     RECT  59.64 31.723 61.032 31.909 ;
     RECT  46.992 31.813 47.016 31.925 ;
     RECT  14.784 31.723 16.752 31.955 ;
     RECT  36.96 31.667 38.352 31.955 ;
     RECT  62.304 31.427 63.24 31.955 ;
     RECT  29.04 31.909 29.688 31.979 ;
     RECT  36.96 31.955 36.984 31.979 ;
     RECT  48.576 31.797 49.416 31.979 ;
     RECT  43.44 31.861 45.048 31.989 ;
     RECT  46.176 31.925 47.016 31.989 ;
     RECT  34.704 31.667 35.352 32.003 ;
     RECT  2.928 31.787 4.152 32.051 ;
     RECT  18 31.723 18.696 32.053 ;
     RECT  50.736 31.765 51.864 32.053 ;
     RECT  43.44 31.989 47.016 32.099 ;
     RECT  31.824 31.349 32.952 32.101 ;
     RECT  50.64 32.053 51.864 32.107 ;
     RECT  23.472 31.571 24.312 32.117 ;
     RECT  25.728 31.525 27.912 32.117 ;
     RECT  23.472 32.117 27.912 32.195 ;
     RECT  34.704 32.003 34.728 32.195 ;
     RECT  59.64 31.909 61.32 32.195 ;
     RECT  43.44 32.099 45.24 32.243 ;
     RECT  48.576 31.979 49.324 32.243 ;
     RECT  53.376 30.899 54.552 32.243 ;
     RECT  0.24 29.267 0.552 32.245 ;
     RECT  50.88 32.107 51.864 32.245 ;
     RECT  48.72 32.243 49.324 32.288 ;
     RECT  0.24 32.245 1.176 32.299 ;
     RECT  21.648 31.715 22.152 32.299 ;
     RECT  29.664 31.979 29.688 32.299 ;
     RECT  48.72 32.288 49.32 32.299 ;
     RECT  46.992 32.099 47.016 32.339 ;
     RECT  25.92 32.195 27.912 32.341 ;
     RECT  25.92 32.341 28.008 32.373 ;
     RECT  25.92 32.373 28.68 32.427 ;
     RECT  30.96 32.101 32.952 32.427 ;
     RECT  56.352 32.373 56.376 32.435 ;
     RECT  5.136 31.787 6.984 32.437 ;
     RECT  8.016 31.523 9.048 32.437 ;
     RECT  11.04 31.595 11.88 32.437 ;
     RECT  50.88 32.245 52.056 32.437 ;
     RECT  18 32.053 19.128 32.491 ;
     RECT  21.696 32.299 22.152 32.491 ;
     RECT  26.832 32.427 28.68 32.491 ;
     RECT  43.44 32.243 44.472 32.491 ;
     RECT  50.88 32.437 52.536 32.491 ;
     RECT  14.784 31.955 15.144 32.501 ;
     RECT  43.44 32.491 44.376 32.501 ;
     RECT  53.568 32.243 54.552 32.501 ;
     RECT  58.128 31.667 58.152 32.531 ;
     RECT  62.304 31.955 62.76 32.531 ;
     RECT  11.04 32.437 11.976 32.565 ;
     RECT  42.864 32.501 44.376 32.579 ;
     RECT  59.64 32.195 61.032 32.579 ;
     RECT  5.136 32.437 9.048 32.627 ;
     RECT  23.472 32.195 24.168 32.627 ;
     RECT  47.52 32.565 47.544 32.627 ;
     RECT  7.248 32.627 9.048 32.629 ;
     RECT  10.608 32.565 11.976 32.629 ;
     RECT  7.248 32.629 11.976 32.757 ;
     RECT  13.296 31.619 13.32 32.757 ;
     RECT  20.256 32.693 20.28 32.771 ;
     RECT  23.184 32.693 23.208 32.771 ;
     RECT  53.568 32.501 54.696 32.771 ;
     RECT  59.64 32.579 60.792 32.771 ;
     RECT  62.736 32.531 62.76 32.771 ;
     RECT  7.248 32.757 13.32 32.811 ;
     RECT  14.736 32.501 15.144 32.819 ;
     RECT  18.144 32.491 19.128 32.821 ;
     RECT  16.32 31.955 16.752 32.867 ;
     RECT  14.832 32.819 15.144 32.875 ;
     RECT  18.144 32.821 19.56 32.875 ;
     RECT  27.12 32.491 28.68 32.875 ;
     RECT  30.96 32.427 30.984 32.875 ;
     RECT  7.248 32.811 9.048 32.939 ;
     RECT  53.568 32.771 54.552 32.939 ;
     RECT  10.128 32.811 13.32 32.963 ;
     RECT  51.552 32.491 52.536 32.963 ;
     RECT  7.248 32.939 9 33.011 ;
     RECT  10.272 32.963 13.32 33.011 ;
     RECT  3.168 32.051 4.152 33.013 ;
     RECT  43.44 32.579 44.376 33.059 ;
     RECT  2.256 33.013 4.152 33.067 ;
     RECT  7.248 33.011 7.464 33.067 ;
     RECT  14.832 32.875 14.856 33.067 ;
     RECT  18.144 32.875 18.84 33.155 ;
     RECT  30.288 33.077 30.312 33.155 ;
     RECT  54.096 32.939 54.552 33.155 ;
     RECT  10.272 33.011 11.88 33.203 ;
     RECT  7.44 33.067 7.464 33.251 ;
     RECT  13.008 33.011 13.32 33.251 ;
     RECT  51.552 32.963 51.864 33.259 ;
     RECT  53.04 33.205 53.064 33.259 ;
     RECT  25.68 33.253 25.8 33.269 ;
     RECT  48.72 32.299 49.152 33.269 ;
     RECT  48.72 33.269 49.56 33.347 ;
     RECT  57.024 33.269 57.048 33.347 ;
     RECT  46.416 33.269 46.44 33.493 ;
     RECT  13.056 33.251 13.32 33.539 ;
     RECT  46.416 33.493 46.776 33.539 ;
     RECT  2.016 33.269 2.04 33.587 ;
     RECT  10.608 33.203 11.88 33.587 ;
     RECT  51.84 33.259 51.864 33.587 ;
     RECT  25.44 33.269 25.8 33.589 ;
     RECT  27.12 32.875 27.552 33.589 ;
     RECT  13.104 33.539 13.32 33.637 ;
     RECT  38.04 31.955 38.352 33.637 ;
     RECT  59.64 32.771 59.952 33.637 ;
     RECT  4.128 33.067 4.152 33.683 ;
     RECT  40.848 33.013 40.872 33.685 ;
     RECT  58.656 33.637 59.952 33.685 ;
     RECT  21.84 32.491 22.152 33.733 ;
     RECT  28.608 32.875 28.68 33.733 ;
     RECT  5.136 32.627 6.168 33.781 ;
     RECT  13.104 33.637 13.8 33.781 ;
     RECT  16.44 32.867 16.752 33.781 ;
     RECT  18.144 33.155 18.264 33.781 ;
     RECT  28.608 33.733 29.112 33.781 ;
     RECT  37.104 33.637 38.352 33.781 ;
     RECT  40.128 33.685 40.872 33.781 ;
     RECT  43.44 33.059 43.752 33.781 ;
     RECT  58.176 33.685 59.952 33.781 ;
     RECT  37.104 33.781 40.872 33.835 ;
     RECT  42.24 33.781 42.264 33.835 ;
     RECT  55.92 33.781 55.944 33.835 ;
     RECT  20.544 33.781 20.568 33.845 ;
     RECT  21.84 33.733 22.248 33.845 ;
     RECT  31.44 33.829 31.464 33.845 ;
     RECT  32.64 32.427 32.952 33.845 ;
     RECT  46.752 33.539 46.776 33.845 ;
     RECT  48.72 33.347 49.152 33.845 ;
     RECT  58.176 33.781 60.312 33.845 ;
     RECT  28.608 33.781 29.976 33.875 ;
     RECT  43.344 33.781 43.752 33.875 ;
     RECT  25.104 33.589 25.8 33.877 ;
     RECT  16.44 33.781 18.264 33.899 ;
     RECT  29.952 33.875 29.976 33.899 ;
     RECT  31.44 33.845 32.952 33.899 ;
     RECT  46.752 33.845 47.304 33.899 ;
     RECT  58.176 33.845 60.408 33.899 ;
     RECT  16.44 33.899 16.872 33.923 ;
     RECT  20.544 33.845 22.248 33.923 ;
     RECT  28.608 33.875 28.776 33.923 ;
     RECT  21.456 33.923 22.248 34.021 ;
     RECT  21.456 34.021 22.92 34.067 ;
     RECT  10.608 33.587 11.784 34.115 ;
     RECT  47.28 33.899 47.304 34.163 ;
     RECT  63.792 33.781 63.816 34.163 ;
     RECT  3.12 33.067 3.144 34.165 ;
     RECT  43.44 33.875 43.752 34.165 ;
     RECT  58.656 33.899 60.408 34.211 ;
     RECT  8.688 33.011 9 34.357 ;
     RECT  16.44 33.923 16.752 34.357 ;
     RECT  24.048 34.117 24.072 34.357 ;
     RECT  8.016 34.357 9 34.405 ;
     RECT  19.728 34.405 19.752 34.421 ;
     RECT  2.688 34.165 3.144 34.451 ;
     RECT  0.24 32.299 0.552 34.453 ;
     RECT  1.584 34.357 1.608 34.453 ;
     RECT  21.744 34.067 22.92 34.453 ;
     RECT  24.048 34.357 24.12 34.453 ;
     RECT  18.096 33.899 18.264 34.485 ;
     RECT  19.344 34.421 19.752 34.485 ;
     RECT  21.744 34.453 24.12 34.485 ;
     RECT  25.104 33.877 25.992 34.485 ;
     RECT  50.592 34.117 50.616 34.499 ;
     RECT  37.104 33.835 38.352 34.501 ;
     RECT  2.688 34.451 2.712 34.539 ;
     RECT  8.016 34.405 9.528 34.613 ;
     RECT  4.992 33.781 6.168 34.645 ;
     RECT  31.536 33.899 32.952 34.645 ;
     RECT  54.24 33.155 54.552 34.645 ;
     RECT  7.968 34.613 9.528 34.691 ;
     RECT  0.24 34.453 1.608 34.731 ;
     RECT  8.4 34.691 9.528 34.739 ;
     RECT  21.744 34.485 25.992 34.739 ;
     RECT  4.608 34.645 6.168 34.741 ;
     RECT  10.848 34.115 11.784 34.741 ;
     RECT  13.104 33.781 14.04 34.741 ;
     RECT  59.64 34.211 60.408 34.741 ;
     RECT  10.848 34.741 14.04 34.789 ;
     RECT  27.024 33.589 27.552 34.789 ;
     RECT  31.536 34.645 33.192 34.789 ;
     RECT  10.848 34.789 14.232 34.795 ;
     RECT  59.64 34.741 60.792 34.795 ;
     RECT  52.992 34.405 53.016 34.805 ;
     RECT  4.56 34.741 6.264 34.835 ;
     RECT  62.16 33.845 62.184 34.835 ;
     RECT  1.968 34.789 1.992 34.859 ;
     RECT  4.56 34.835 4.632 34.859 ;
     RECT  15.84 34.357 16.752 34.869 ;
     RECT  31.536 34.789 33.24 34.869 ;
     RECT  34.416 34.693 34.44 34.869 ;
     RECT  18.096 34.485 19.752 34.883 ;
     RECT  63.888 34.805 63.912 34.883 ;
     RECT  13.296 34.795 14.232 34.923 ;
     RECT  26.976 34.789 27.552 34.923 ;
     RECT  23.808 34.739 25.992 34.931 ;
     RECT  52.464 34.805 53.016 34.933 ;
     RECT  48.48 33.845 49.152 34.981 ;
     RECT  52.272 34.933 53.016 34.987 ;
     RECT  55.584 34.933 55.608 34.987 ;
     RECT  57.6 34.165 57.624 34.987 ;
     RECT  43.44 34.165 44.472 34.997 ;
     RECT  48.336 34.981 49.152 35.051 ;
     RECT  8.448 34.739 9.528 35.061 ;
     RECT  31.536 34.869 34.44 35.061 ;
     RECT  54 34.645 54.552 35.115 ;
     RECT  36.816 34.501 38.352 35.125 ;
     RECT  31.536 35.061 34.584 35.179 ;
     RECT  43.44 34.997 44.952 35.221 ;
     RECT  48.84 35.051 49.152 35.221 ;
     RECT  5.64 34.835 6.264 35.253 ;
     RECT  40.848 33.835 40.872 35.267 ;
     RECT  10.848 34.795 11.784 35.269 ;
     RECT  35.904 35.125 38.352 35.307 ;
     RECT  5.64 35.253 7.032 35.315 ;
     RECT  37.632 35.307 38.352 35.317 ;
     RECT  46.272 34.741 46.296 35.317 ;
     RECT  4.608 34.859 4.632 35.363 ;
     RECT  5.64 35.315 6.888 35.363 ;
     RECT  34.176 35.179 34.584 35.365 ;
     RECT  35.904 35.307 36.456 35.365 ;
     RECT  28.56 34.405 28.584 35.381 ;
     RECT  34.176 35.365 36.456 35.435 ;
     RECT  37.632 35.317 38.472 35.445 ;
     RECT  28.56 35.381 29.544 35.459 ;
     RECT  56.976 35.061 57 35.459 ;
     RECT  15.408 34.869 16.752 35.461 ;
     RECT  18.096 34.883 19.56 35.461 ;
     RECT  5.64 35.363 6.84 35.507 ;
     RECT  27.24 34.923 27.552 35.509 ;
     RECT  28.56 35.459 28.728 35.509 ;
     RECT  46.272 35.317 47.256 35.509 ;
     RECT  21.744 34.739 22.824 35.637 ;
     RECT  30.144 35.573 30.168 35.651 ;
     RECT  27.24 35.509 28.728 35.699 ;
     RECT  8.448 35.061 9.672 35.701 ;
     RECT  10.752 35.269 11.784 35.701 ;
     RECT  21.216 35.637 22.824 35.749 ;
     RECT  8.448 35.701 11.784 35.755 ;
     RECT  15.408 35.461 19.56 35.755 ;
     RECT  59.64 34.795 59.952 35.765 ;
     RECT  8.448 35.755 9.576 35.819 ;
     RECT  34.176 35.435 34.584 35.819 ;
     RECT  43.44 35.221 45 35.829 ;
     RECT  46.128 35.509 47.256 35.829 ;
     RECT  43.44 35.829 47.256 35.883 ;
     RECT  54.096 35.115 54.552 35.883 ;
     RECT  31.536 35.179 33.048 35.891 ;
     RECT  43.44 35.883 45.912 35.891 ;
     RECT  10.656 35.755 11.784 35.893 ;
     RECT  15.504 35.755 19.56 35.893 ;
     RECT  21.12 35.749 22.824 35.893 ;
     RECT  23.808 34.931 24.744 35.893 ;
     RECT  10.656 35.893 12.264 35.947 ;
     RECT  37.632 35.445 38.568 35.957 ;
     RECT  39.936 35.701 40.008 35.957 ;
     RECT  21.12 35.893 24.744 35.987 ;
     RECT  23.952 35.987 24.744 36.021 ;
     RECT  48.84 35.221 49.608 36.021 ;
     RECT  48.84 36.021 50.136 36.037 ;
     RECT  9.408 35.819 9.576 36.083 ;
     RECT  48.48 36.037 50.136 36.083 ;
     RECT  13.296 34.923 14.088 36.085 ;
     RECT  23.952 36.021 24.84 36.085 ;
     RECT  25.968 34.931 25.992 36.085 ;
     RECT  31.536 35.891 31.56 36.085 ;
     RECT  5.64 35.507 6.744 36.131 ;
     RECT  23.952 36.085 25.992 36.131 ;
     RECT  15.504 35.893 19.8 36.139 ;
     RECT  25.536 36.131 25.992 36.149 ;
     RECT  46.944 35.883 47.256 36.149 ;
     RECT  21.12 35.987 22.92 36.203 ;
     RECT  32.544 35.891 33.048 36.213 ;
     RECT  37.632 35.957 40.008 36.227 ;
     RECT  35.856 35.435 36.456 36.267 ;
     RECT  44.976 35.891 45.912 36.267 ;
     RECT  32.544 36.213 34.008 36.275 ;
     RECT  37.632 36.227 39.624 36.277 ;
     RECT  54.24 35.883 54.552 36.277 ;
     RECT  59.52 35.765 59.952 36.277 ;
     RECT  23.952 36.131 23.976 36.331 ;
     RECT  31.488 36.085 31.56 36.331 ;
     RECT  35.856 36.267 36.408 36.331 ;
     RECT  46.944 36.149 47.352 36.331 ;
     RECT  48.48 36.083 49.152 36.331 ;
     RECT  59.28 36.277 59.952 36.331 ;
     RECT  15.84 36.139 18.84 36.395 ;
     RECT  37.584 36.277 39.624 36.395 ;
     RECT  27.24 35.699 28.536 36.405 ;
     RECT  45.264 36.267 45.912 36.459 ;
     RECT  50.736 36.373 50.952 36.459 ;
     RECT  56.448 36.373 56.472 36.459 ;
     RECT  58.128 36.277 58.152 36.467 ;
     RECT  35.856 36.331 36.36 36.469 ;
     RECT  47.328 36.331 47.352 36.515 ;
     RECT  5.64 36.131 6.552 36.517 ;
     RECT  32.544 36.275 33.672 36.523 ;
     RECT  35.472 36.469 36.36 36.523 ;
     RECT  41.28 36.469 41.304 36.523 ;
     RECT  57.6 36.469 57.624 36.523 ;
     RECT  4.704 36.517 6.552 36.533 ;
     RECT  21.12 36.203 22.824 36.533 ;
     RECT  38.04 36.395 39.624 36.563 ;
     RECT  10.656 35.947 12.072 36.587 ;
     RECT  50.736 36.459 50.856 36.587 ;
     RECT  4.08 36.533 6.552 36.661 ;
     RECT  36.336 36.523 36.36 36.707 ;
     RECT  25.536 36.149 26.088 36.789 ;
     RECT  27.12 36.405 28.536 36.789 ;
     RECT  30 36.469 30.024 36.789 ;
     RECT  20.88 36.533 22.824 36.803 ;
     RECT  8.352 36.037 8.376 36.805 ;
     RECT  3.408 36.661 6.552 36.851 ;
     RECT  29.664 36.789 30.024 36.851 ;
     RECT  8.352 36.805 9.096 36.853 ;
     RECT  8.16 36.853 9.096 36.901 ;
     RECT  29.808 36.851 30.024 36.901 ;
     RECT  43.44 35.891 43.752 36.901 ;
     RECT  2.304 36.565 2.328 36.917 ;
     RECT  10.896 36.587 12.072 36.949 ;
     RECT  13.296 36.085 14.52 36.949 ;
     RECT  54.24 36.277 55.32 36.949 ;
     RECT  15.84 36.395 18.696 36.971 ;
     RECT  21.264 36.803 22.824 36.971 ;
     RECT  25.536 36.789 28.536 36.981 ;
     RECT  53.952 36.949 55.32 36.981 ;
     RECT  53.952 36.981 55.464 37.035 ;
     RECT  21.744 36.971 22.824 37.043 ;
     RECT  1.68 36.917 2.328 37.045 ;
     RECT  35.328 36.997 35.352 37.045 ;
     RECT  42.624 36.901 43.752 37.045 ;
     RECT  50.736 36.587 50.76 37.045 ;
     RECT  25.536 36.981 28.584 37.091 ;
     RECT  29.808 36.901 30.888 37.091 ;
     RECT  50.16 37.045 50.76 37.091 ;
     RECT  8.064 36.901 9.096 37.093 ;
     RECT  10.896 36.949 14.52 37.093 ;
     RECT  3.408 36.851 3.672 37.099 ;
     RECT  4.992 36.851 6.552 37.099 ;
     RECT  42.48 37.045 43.848 37.099 ;
     RECT  1.632 37.045 2.328 37.139 ;
     RECT  35.184 37.045 35.352 37.139 ;
     RECT  16.32 36.971 18.696 37.227 ;
     RECT  39.36 36.563 39.624 37.237 ;
     RECT  42.624 37.099 43.848 37.237 ;
     RECT  45.264 36.459 45.576 37.237 ;
     RECT  1.68 37.139 2.328 37.283 ;
     RECT  42.624 37.237 43.944 37.301 ;
     RECT  44.976 37.237 45.576 37.301 ;
     RECT  48.84 36.331 49.152 37.301 ;
     RECT  54.24 37.035 55.464 37.331 ;
     RECT  25.536 37.091 28.248 37.355 ;
     RECT  2.016 37.283 2.328 37.379 ;
     RECT  42.624 37.301 45.576 37.379 ;
     RECT  5.088 37.099 6.552 37.381 ;
     RECT  7.872 37.093 9.096 37.419 ;
     RECT  42.624 37.379 43.944 37.419 ;
     RECT  32.544 36.523 33.288 37.427 ;
     RECT  32.544 37.427 33.048 37.429 ;
     RECT  47.904 37.301 49.152 37.429 ;
     RECT  50.16 37.091 50.184 37.429 ;
     RECT  10.896 37.093 14.808 37.477 ;
     RECT  5.088 37.381 6.84 37.483 ;
     RECT  47.904 37.429 50.184 37.523 ;
     RECT  29.808 37.091 29.832 37.547 ;
     RECT  25.536 37.355 27.912 37.557 ;
     RECT  35.328 37.139 35.352 37.611 ;
     RECT  24.624 37.557 27.912 37.619 ;
     RECT  36.672 37.557 37.032 37.619 ;
     RECT  32.448 37.429 33.048 37.621 ;
     RECT  51.264 37.573 51.288 37.675 ;
     RECT  20.208 37.477 20.232 37.717 ;
     RECT  7.968 37.419 9.096 37.765 ;
     RECT  47.904 37.523 49.848 37.859 ;
     RECT  45.264 37.379 45.576 37.861 ;
     RECT  2.832 37.861 2.856 37.931 ;
     RECT  36.672 37.619 36.696 38.005 ;
     RECT  39.36 37.237 39.816 38.005 ;
     RECT  7.968 37.765 9.72 38.069 ;
     RECT  10.896 37.477 15.336 38.069 ;
     RECT  20.064 37.717 20.232 38.101 ;
     RECT  7.968 38.069 15.336 38.123 ;
     RECT  45.264 37.861 45.768 38.123 ;
     RECT  10.176 38.123 15.336 38.133 ;
     RECT  16.32 37.227 17.736 38.133 ;
     RECT  47.904 37.859 49.368 38.133 ;
     RECT  31.92 37.621 33.048 38.147 ;
     RECT  39.36 38.005 40.104 38.147 ;
     RECT  7.968 38.123 9.192 38.187 ;
     RECT  7.968 38.187 9.096 38.195 ;
     RECT  10.176 38.133 17.736 38.195 ;
     RECT  32.448 38.147 33.048 38.195 ;
     RECT  43.248 37.419 43.752 38.195 ;
     RECT  47.424 38.133 49.368 38.195 ;
     RECT  20.064 38.101 20.328 38.197 ;
     RECT  32.544 38.195 33.048 38.243 ;
     RECT  48.336 38.195 49.368 38.243 ;
     RECT  25.488 37.619 26.232 38.251 ;
     RECT  11.04 38.195 17.736 38.261 ;
     RECT  23.712 38.197 24.36 38.389 ;
     RECT  30.864 37.091 30.888 38.435 ;
     RECT  11.04 38.261 18.264 38.453 ;
     RECT  19.968 38.197 20.328 38.453 ;
     RECT  11.04 38.453 20.328 38.483 ;
     RECT  38.04 36.563 38.352 38.485 ;
     RECT  7.968 38.195 7.992 38.533 ;
     RECT  34.848 38.325 34.872 38.571 ;
     RECT  11.04 38.483 19.992 38.579 ;
     RECT  21.744 37.043 22.152 38.581 ;
     RECT  23.376 38.389 24.36 38.581 ;
     RECT  45.264 38.123 45.576 38.635 ;
     RECT  11.04 38.579 19.176 38.723 ;
     RECT  26.208 38.251 26.232 38.723 ;
     RECT  51.216 38.645 51.24 38.723 ;
     RECT  36.432 38.005 36.696 38.725 ;
     RECT  9.072 38.195 9.096 38.771 ;
     RECT  47.232 38.645 47.256 38.771 ;
     RECT  23.376 38.581 24.408 38.821 ;
     RECT  21.072 38.581 22.152 38.915 ;
     RECT  5.64 37.483 6.84 39.013 ;
     RECT  7.824 38.533 7.992 39.013 ;
     RECT  39.744 38.147 40.104 39.013 ;
     RECT  23.232 38.821 24.408 39.061 ;
     RECT  45.264 38.635 45.288 39.061 ;
     RECT  48.72 38.243 49.368 39.061 ;
     RECT  44.928 39.061 45.288 39.107 ;
     RECT  36.384 38.725 36.696 39.109 ;
     RECT  37.728 38.485 38.352 39.109 ;
     RECT  39.744 39.013 40.584 39.157 ;
     RECT  3.936 38.629 3.96 39.205 ;
     RECT  32.64 38.243 33.048 39.205 ;
     RECT  36.384 39.109 38.352 39.205 ;
     RECT  39.504 39.157 40.584 39.205 ;
     RECT  11.04 38.723 13.56 39.211 ;
     RECT  36.288 39.205 40.584 39.211 ;
     RECT  23.232 39.061 25.128 39.221 ;
     RECT  11.04 39.211 12.024 39.251 ;
     RECT  14.64 38.723 19.176 39.251 ;
     RECT  15.264 39.251 19.176 39.275 ;
     RECT  23.232 39.221 25.704 39.275 ;
     RECT  32.544 39.205 33.048 39.275 ;
     RECT  36.288 39.211 36.312 39.275 ;
     RECT  37.344 39.211 39.768 39.275 ;
     RECT  44.928 39.107 45.048 39.275 ;
     RECT  46.8 39.061 46.824 39.275 ;
     RECT  48.72 39.061 49.656 39.275 ;
     RECT  15.312 39.275 19.176 39.299 ;
     RECT  52.416 39.221 52.44 39.299 ;
     RECT  42.192 38.677 42.216 39.349 ;
     RECT  43.44 38.195 43.752 39.349 ;
     RECT  5.64 39.013 7.992 39.395 ;
     RECT  13.008 39.211 13.56 39.395 ;
     RECT  27.24 37.619 27.912 39.395 ;
     RECT  30.816 38.821 30.84 39.395 ;
     RECT  37.344 39.275 38.472 39.395 ;
     RECT  3.936 39.205 4.536 39.443 ;
     RECT  2.688 39.221 2.712 39.539 ;
     RECT  42.192 39.349 43.752 39.539 ;
     RECT  7.44 39.395 7.992 39.589 ;
     RECT  27.24 39.395 27.672 39.733 ;
     RECT  48.72 39.275 49.56 39.733 ;
     RECT  16.44 39.299 19.176 39.779 ;
     RECT  39.6 39.275 39.768 39.779 ;
     RECT  42.864 39.539 43.752 39.781 ;
     RECT  11.04 39.251 11.64 39.787 ;
     RECT  13.056 39.395 13.56 39.787 ;
     RECT  15.312 39.299 15.336 39.787 ;
     RECT  19.152 39.779 19.176 39.787 ;
     RECT  23.52 39.275 25.704 39.787 ;
     RECT  37.392 39.395 38.472 39.787 ;
     RECT  50.784 39.733 50.808 39.787 ;
     RECT  7.44 39.589 8.52 39.829 ;
     RECT  32.64 39.275 33.048 39.829 ;
     RECT  54.24 37.331 54.984 39.829 ;
     RECT  21.648 38.915 22.152 39.861 ;
     RECT  26.736 39.733 27.672 39.861 ;
     RECT  54.24 39.829 55.32 39.861 ;
     RECT  7.44 39.829 9.192 39.915 ;
     RECT  16.44 39.779 17.592 39.915 ;
     RECT  32.64 39.829 33.096 39.915 ;
     RECT  54.144 39.861 55.32 39.915 ;
     RECT  23.52 39.787 23.928 39.923 ;
     RECT  31.344 39.797 31.368 39.923 ;
     RECT  35.52 39.861 35.592 39.923 ;
     RECT  7.44 39.915 8.568 39.979 ;
     RECT  4.512 39.443 4.536 40.019 ;
     RECT  23.52 39.923 23.544 40.067 ;
     RECT  39.6 39.779 39.624 40.067 ;
     RECT  54.144 39.915 54.552 40.117 ;
     RECT  48.624 39.733 49.56 40.171 ;
     RECT  53.808 40.117 54.552 40.171 ;
     RECT  11.04 39.787 11.496 40.245 ;
     RECT  19.968 39.925 19.992 40.245 ;
     RECT  26.16 39.861 27.672 40.259 ;
     RECT  35.568 39.923 35.592 40.299 ;
     RECT  48.624 40.171 49.368 40.309 ;
     RECT  37.392 39.787 38.352 40.355 ;
     RECT  5.64 39.395 5.952 40.357 ;
     RECT  32.64 39.915 33.048 40.451 ;
     RECT  21.648 39.861 22.248 40.453 ;
     RECT  10.512 40.245 11.496 40.501 ;
     RECT  26.688 40.259 27.672 40.501 ;
     RECT  45.024 39.275 45.048 40.501 ;
     RECT  45.024 40.501 45.72 40.549 ;
     RECT  46.704 40.165 46.728 40.549 ;
     RECT  34.176 40.501 34.2 40.595 ;
     RECT  45.024 40.549 46.728 40.619 ;
     RECT  5.64 40.357 6.264 40.643 ;
     RECT  13.056 39.787 13.32 40.691 ;
     RECT  42.864 39.781 43.944 40.691 ;
     RECT  43.2 40.691 43.944 40.741 ;
     RECT  45.024 40.619 45.576 40.741 ;
     RECT  9.696 40.501 11.496 40.747 ;
     RECT  19.968 40.245 20.424 40.757 ;
     RECT  43.2 40.741 45.576 40.811 ;
     RECT  21.648 40.453 23.4 40.835 ;
     RECT  43.2 40.811 43.752 40.835 ;
     RECT  26.688 40.501 28.248 40.875 ;
     RECT  19.248 40.757 20.424 40.885 ;
     RECT  5.64 40.643 5.952 40.933 ;
     RECT  19.248 40.885 20.568 40.933 ;
     RECT  21.648 40.835 22.248 40.933 ;
     RECT  7.92 39.979 8.568 40.949 ;
     RECT  19.248 40.933 22.248 40.979 ;
     RECT  30.096 40.885 30.12 40.979 ;
     RECT  31.296 40.885 31.32 40.979 ;
     RECT  5.52 40.933 5.952 41.003 ;
     RECT  10.368 40.747 11.496 41.003 ;
     RECT  25.2 41.013 25.224 41.029 ;
     RECT  21.072 40.979 22.248 41.067 ;
     RECT  7.728 40.949 8.568 41.075 ;
     RECT  21.36 41.067 22.248 41.075 ;
     RECT  24.48 41.029 25.224 41.075 ;
     RECT  26.688 40.875 27.552 41.075 ;
     RECT  19.248 40.979 19.992 41.123 ;
     RECT  16.44 39.915 16.92 41.125 ;
     RECT  7.728 41.075 7.752 41.171 ;
     RECT  14.688 41.141 14.712 41.173 ;
     RECT  32.64 40.451 32.952 41.173 ;
     RECT  12.624 40.837 12.648 41.195 ;
     RECT  19.344 41.123 19.992 41.195 ;
     RECT  14.688 41.173 15.384 41.205 ;
     RECT  16.44 41.125 17.112 41.205 ;
     RECT  47.904 40.309 49.368 41.205 ;
     RECT  50.736 40.565 50.76 41.205 ;
     RECT  14.688 41.205 17.112 41.219 ;
     RECT  47.856 41.205 49.368 41.219 ;
     RECT  15.36 41.219 17.112 41.259 ;
     RECT  10.368 41.003 11.352 41.267 ;
     RECT  50.64 41.205 51.336 41.267 ;
     RECT  24.48 41.075 24.504 41.333 ;
     RECT  52.464 40.501 52.488 41.365 ;
     RECT  24.384 41.333 24.504 41.411 ;
     RECT  34.944 41.333 34.968 41.411 ;
     RECT  47.856 41.219 49.152 41.411 ;
     RECT  51.888 41.365 52.488 41.411 ;
     RECT  50.64 41.267 50.664 41.451 ;
     RECT  51.888 41.411 51.912 41.451 ;
     RECT  16.32 41.259 17.112 41.459 ;
     RECT  48.72 41.411 49.152 41.459 ;
     RECT  18.192 40.885 18.216 41.525 ;
     RECT  46.704 40.619 46.728 41.589 ;
     RECT  36.528 41.509 36.552 41.643 ;
     RECT  46.704 41.589 47.016 41.643 ;
     RECT  18.144 41.525 18.216 41.651 ;
     RECT  24.48 41.411 24.504 41.651 ;
     RECT  35.328 41.589 35.352 41.651 ;
     RECT  44.976 40.811 45.576 41.651 ;
     RECT  46.992 41.643 47.016 41.651 ;
     RECT  32.448 41.173 32.952 41.653 ;
     RECT  23.28 40.835 23.4 41.699 ;
     RECT  32.112 41.653 32.952 41.707 ;
     RECT  36.96 41.653 36.984 41.747 ;
     RECT  42.096 41.653 42.12 41.747 ;
     RECT  26.736 41.075 27.552 41.891 ;
     RECT  45.552 41.651 45.576 41.891 ;
     RECT  23.376 41.699 23.4 41.987 ;
     RECT  27.24 41.891 27.552 41.989 ;
     RECT  18.192 41.651 18.216 42.085 ;
     RECT  19.344 41.195 19.512 42.085 ;
     RECT  43.44 40.835 43.752 42.133 ;
     RECT  42.768 42.133 43.752 42.219 ;
     RECT  41.568 42.165 41.592 42.227 ;
     RECT  18.192 42.085 19.512 42.275 ;
     RECT  21.36 41.075 22.152 42.357 ;
     RECT  21.36 42.357 22.248 42.411 ;
     RECT  25.776 42.277 26.232 42.411 ;
     RECT  27.24 41.989 27.672 42.411 ;
     RECT  0.24 34.731 0.552 42.413 ;
     RECT  5.64 41.003 5.952 42.413 ;
     RECT  11.04 41.267 11.352 42.413 ;
     RECT  16.44 41.459 16.752 42.413 ;
     RECT  27.24 42.411 27.552 42.413 ;
     RECT  32.64 41.707 32.952 42.413 ;
     RECT  43.44 42.219 43.752 42.413 ;
     RECT  48.84 41.459 49.152 42.413 ;
     RECT  54.24 40.171 54.552 42.413 ;
     RECT  59.64 36.331 59.952 42.413 ;
     RECT  21.84 42.411 22.248 42.419 ;
     RECT  19.008 42.275 19.512 42.421 ;
     RECT  25.776 42.411 25.8 42.475 ;
     RECT  24.528 42.357 24.6 42.515 ;
     RECT  19.008 42.421 19.704 42.565 ;
     RECT  24.576 42.515 24.6 42.611 ;
     RECT  38.04 40.355 38.352 42.613 ;
     RECT  0.24 42.413 0.36 42.683 ;
     RECT  5.64 42.413 5.76 42.683 ;
     RECT  11.04 42.413 11.16 42.683 ;
     RECT  16.44 42.413 16.56 42.683 ;
     RECT  21.84 42.419 21.96 42.683 ;
     RECT  27.24 42.413 27.36 42.683 ;
     RECT  32.64 42.413 32.76 42.683 ;
     RECT  38.04 42.613 38.808 42.683 ;
     RECT  43.44 42.413 43.56 42.683 ;
     RECT  48.84 42.413 48.96 42.683 ;
     RECT  54.24 42.413 54.36 42.683 ;
     RECT  59.64 42.413 59.76 42.683 ;
     RECT  38.784 42.683 38.808 42.709 ;
     RECT  19.008 42.565 19.8 43.024 ;
     RECT  38.784 42.709 38.904 43.024 ;
    LAYER M6 ;
     RECT  0 17.196 0.053 18.06 ;
     RECT  0 22.596 0.117 23.46 ;
     RECT  0 6.396 0.133 7.26 ;
     RECT  0 11.796 0.133 12.66 ;
     RECT  0.053 14.208 0.133 14.24 ;
     RECT  0.053 16.832 0.133 18.06 ;
     RECT  0.117 20.16 0.133 20.192 ;
     RECT  0.117 22.272 0.133 23.46 ;
     RECT  0.133 11.648 0.245 20.384 ;
     RECT  0.245 10.752 0.565 20.384 ;
     RECT  0.133 22.272 0.565 23.584 ;
     RECT  0 27.996 0.949 28.86 ;
     RECT  0 33.396 0.949 34.26 ;
     RECT  0.133 6.396 0.997 8.288 ;
     RECT  0.949 33.396 1.141 34.592 ;
     RECT  0.997 5.376 1.205 8.288 ;
     RECT  1.141 32.256 1.237 34.592 ;
     RECT  0.565 10.752 1.333 23.584 ;
     RECT  1.205 5.376 1.461 8.608 ;
     RECT  1.333 10.752 1.461 23.84 ;
     RECT  1.461 5.376 1.573 23.84 ;
     RECT  0.949 27.996 1.573 29.152 ;
     RECT  0 0.996 1.653 1.86 ;
     RECT  1.589 37.056 1.669 37.088 ;
     RECT  1.653 0.996 1.715 2.848 ;
     RECT  1.573 5.376 1.717 24.224 ;
     RECT  1.237 32.256 1.957 34.72 ;
     RECT  1.717 4.48 1.963 24.608 ;
     RECT  1.573 26.88 2.037 29.152 ;
     RECT  1.669 30.72 2.037 30.752 ;
     RECT  1.957 32.256 2.037 34.848 ;
     RECT  2.037 26.88 2.091 34.848 ;
     RECT  1.963 4.48 2.229 23.84 ;
     RECT  2.091 26.88 2.389 29.984 ;
     RECT  2.389 26.368 2.485 29.984 ;
     RECT  1.669 36.928 2.821 37.088 ;
     RECT  0 38.796 2.821 39.66 ;
     RECT  2.229 3.392 2.915 23.84 ;
     RECT  2.915 3.392 3.157 18.208 ;
     RECT  2.821 36.928 3.397 39.66 ;
     RECT  3.157 3.264 3.563 18.208 ;
     RECT  3.563 3.264 3.635 4 ;
     RECT  2.091 31.424 3.701 34.848 ;
     RECT  3.397 36.672 3.701 39.66 ;
     RECT  2.485 26.112 3.877 29.984 ;
     RECT  3.877 25.024 4.019 29.984 ;
     RECT  3.563 5.376 4.075 18.208 ;
     RECT  4.019 26.048 4.341 29.984 ;
     RECT  3.701 31.424 4.341 39.66 ;
     RECT  4.075 14.784 4.501 18.208 ;
     RECT  2.915 19.776 4.501 23.584 ;
     RECT  4.341 26.048 4.501 39.66 ;
     RECT  4.501 14.784 4.693 23.584 ;
     RECT  4.075 5.376 4.843 13.344 ;
     RECT  1.715 0.996 5.029 1.86 ;
     RECT  4.843 6.272 5.509 13.344 ;
     RECT  4.693 14.784 5.509 23.648 ;
     RECT  4.501 26.048 5.509 39.968 ;
     RECT  5.509 6.272 6.083 23.648 ;
     RECT  6.083 19.776 6.469 23.648 ;
     RECT  3.635 3.392 6.661 4 ;
     RECT  5.029 0.996 6.805 2.08 ;
     RECT  6.661 3.392 6.805 4.384 ;
     RECT  6.469 19.776 6.805 24.288 ;
     RECT  5.509 26.048 6.805 40.992 ;
     RECT  6.083 6.272 6.899 18.272 ;
     RECT  6.805 19.776 6.899 40.992 ;
     RECT  6.899 14.912 7.331 18.208 ;
     RECT  6.805 0.996 7.717 4.384 ;
     RECT  6.899 6.272 7.717 13.6 ;
     RECT  6.899 21.888 7.763 40.992 ;
     RECT  6.899 19.776 8.003 19.808 ;
     RECT  7.763 21.888 8.485 40.864 ;
     RECT  7.717 0.996 8.917 13.6 ;
     RECT  7.331 15.04 8.917 18.208 ;
     RECT  8.917 0.996 9.131 18.208 ;
     RECT  9.131 4.352 9.333 18.208 ;
     RECT  8.485 20.672 10.405 40.864 ;
     RECT  9.333 4.352 10.677 18.272 ;
     RECT  10.677 4.16 10.883 18.272 ;
     RECT  10.405 19.776 11.461 40.864 ;
     RECT  11.461 19.776 11.651 40.992 ;
     RECT  10.883 4.288 11.843 18.208 ;
     RECT  9.131 0.996 11.941 2.528 ;
     RECT  11.941 0.996 12.213 2.656 ;
     RECT  11.843 4.288 12.213 12.96 ;
     RECT  12.213 0.996 12.267 12.96 ;
     RECT  11.651 40.96 12.613 40.992 ;
     RECT  12.613 40.96 12.659 41.184 ;
     RECT  11.651 19.776 12.709 39.66 ;
     RECT  12.267 0.996 12.907 4.96 ;
     RECT  12.709 19.712 12.907 39.66 ;
     RECT  12.907 0.996 13.045 2.848 ;
     RECT  12.267 6.272 13.237 12.96 ;
     RECT  11.843 14.272 13.237 18.208 ;
     RECT  12.907 27.996 13.525 39.66 ;
     RECT  12.907 4.288 13.685 4.96 ;
     RECT  13.237 6.272 13.685 18.208 ;
     RECT  12.907 19.712 14.197 26.592 ;
     RECT  13.525 27.996 14.197 39.776 ;
     RECT  13.045 0.832 14.243 2.848 ;
     RECT  13.685 4.288 14.325 18.208 ;
     RECT  14.197 19.712 14.325 39.776 ;
     RECT  14.243 0.832 14.579 2.784 ;
     RECT  14.325 4.288 14.699 39.776 ;
     RECT  12.659 41.152 14.723 41.184 ;
     RECT  14.699 4.288 14.867 19.936 ;
     RECT  14.699 21.696 15.347 39.776 ;
     RECT  14.867 4.288 15.923 19.552 ;
     RECT  14.579 0.996 15.925 2.784 ;
     RECT  15.923 4.288 15.925 13.536 ;
     RECT  15.923 15.424 16.235 19.552 ;
     RECT  16.235 19.392 16.933 19.552 ;
     RECT  15.347 21.696 16.933 39.66 ;
     RECT  15.349 41.216 17.077 41.248 ;
     RECT  16.235 15.424 17.461 18.06 ;
     RECT  16.933 19.392 17.557 39.66 ;
     RECT  17.077 41.152 17.557 41.44 ;
     RECT  17.557 19.392 17.579 41.44 ;
     RECT  15.925 0.996 17.605 13.536 ;
     RECT  17.461 14.848 17.605 18.06 ;
     RECT  17.579 19.392 17.707 20.512 ;
     RECT  17.579 21.888 18.133 41.44 ;
     RECT  17.605 0.996 18.275 18.06 ;
     RECT  18.275 3.84 18.755 18.06 ;
     RECT  18.133 21.888 19.061 41.568 ;
     RECT  18.755 14.592 19.115 18.06 ;
     RECT  19.061 21.568 19.283 41.568 ;
     RECT  19.283 21.888 19.333 41.568 ;
     RECT  19.115 14.72 19.427 18.06 ;
     RECT  18.755 3.84 19.435 12.66 ;
     RECT  19.333 21.888 19.435 42.4 ;
     RECT  19.435 21.888 19.715 36.576 ;
     RECT  19.435 3.84 19.947 5.024 ;
     RECT  19.947 3.84 20.003 4.896 ;
     RECT  19.715 22.016 20.003 36.576 ;
     RECT  19.427 15.168 20.147 18.06 ;
     RECT  18.275 0.996 20.389 2.528 ;
     RECT  20.003 3.84 20.389 4.576 ;
     RECT  20.389 0.996 20.459 4.576 ;
     RECT  20.459 4.288 21.155 4.576 ;
     RECT  20.147 16.896 21.205 18.06 ;
     RECT  17.707 19.392 21.205 19.424 ;
     RECT  20.003 22.08 21.253 36.576 ;
     RECT  19.435 37.952 21.253 42.4 ;
     RECT  21.253 22.08 21.397 42.4 ;
     RECT  21.205 16.896 21.445 19.424 ;
     RECT  19.435 6.396 21.621 12.66 ;
     RECT  21.155 4.288 21.675 4.32 ;
     RECT  20.147 15.168 21.685 15.2 ;
     RECT  21.445 16.896 21.685 20.448 ;
     RECT  21.685 15.168 21.733 20.448 ;
     RECT  21.397 21.824 21.733 42.4 ;
     RECT  21.621 6.272 21.779 12.66 ;
     RECT  21.733 15.168 21.779 42.4 ;
     RECT  21.779 6.396 21.867 12.66 ;
     RECT  21.779 15.168 22.213 36.96 ;
     RECT  21.867 11.648 22.325 12.66 ;
     RECT  22.213 14.336 22.325 36.96 ;
     RECT  20.459 0.996 22.355 2.848 ;
     RECT  22.325 11.648 22.403 36.96 ;
     RECT  22.403 20.288 22.835 36.96 ;
     RECT  22.355 0.996 23.211 2.72 ;
     RECT  21.779 38.464 23.595 42.4 ;
     RECT  23.595 38.464 23.701 39.904 ;
     RECT  22.835 22.016 23.987 36.32 ;
     RECT  22.835 20.288 24.229 20.64 ;
     RECT  23.987 22.016 24.229 36.192 ;
     RECT  23.595 41.344 24.437 42.4 ;
     RECT  24.437 41.344 24.491 42.464 ;
     RECT  22.837 4.544 24.563 4.576 ;
     RECT  23.701 38.208 24.565 39.904 ;
     RECT  24.491 42.368 24.611 42.464 ;
     RECT  21.867 6.396 24.613 9.952 ;
     RECT  24.229 20.288 24.613 36.192 ;
     RECT  24.629 3.968 24.755 4 ;
     RECT  22.403 14.336 25.045 18.72 ;
     RECT  24.613 20.16 25.045 36.192 ;
     RECT  24.565 37.568 25.141 39.904 ;
     RECT  25.141 37.568 25.235 41.056 ;
     RECT  24.613 5.696 25.331 9.952 ;
     RECT  25.045 14.336 25.525 36.192 ;
     RECT  25.235 37.568 25.525 39.904 ;
     RECT  25.525 14.336 25.653 39.904 ;
     RECT  25.331 5.696 25.811 8.416 ;
     RECT  24.611 42.432 25.811 42.464 ;
     RECT  25.653 14.208 26.243 39.904 ;
     RECT  22.403 11.648 26.485 12.66 ;
     RECT  26.243 14.208 26.485 37.344 ;
     RECT  26.485 11.648 26.539 37.344 ;
     RECT  26.243 38.796 26.677 39.904 ;
     RECT  25.811 5.76 26.725 8.416 ;
     RECT  25.331 9.92 26.725 9.952 ;
     RECT  26.539 11.648 26.725 12.66 ;
     RECT  26.725 5.76 26.805 9.952 ;
     RECT  26.805 5.76 26.859 10.08 ;
     RECT  26.859 5.76 27.107 8.608 ;
     RECT  26.197 42.368 27.683 42.4 ;
     RECT  26.539 14.208 27.685 37.344 ;
     RECT  26.677 38.796 27.685 40.864 ;
     RECT  26.917 3.392 27.755 3.424 ;
     RECT  23.211 0.996 27.781 1.86 ;
     RECT  26.725 11.456 27.971 12.66 ;
     RECT  27.971 11.796 28.117 12.66 ;
     RECT  27.685 14.208 28.117 40.864 ;
     RECT  28.117 11.796 28.259 40.864 ;
     RECT  28.259 11.796 28.267 40.544 ;
     RECT  27.107 5.952 28.661 8.608 ;
     RECT  28.661 5.12 28.837 8.608 ;
     RECT  26.859 9.92 28.837 10.08 ;
     RECT  27.781 0.996 28.883 3.168 ;
     RECT  29.365 3.776 29.459 3.808 ;
     RECT  28.267 11.796 29.931 39.904 ;
     RECT  29.931 35.584 30.085 39.904 ;
     RECT  28.837 5.12 30.181 10.08 ;
     RECT  29.931 11.796 30.181 34.26 ;
     RECT  30.181 5.12 30.325 34.26 ;
     RECT  30.085 35.584 30.827 40.928 ;
     RECT  28.883 0.996 31.285 1.86 ;
     RECT  30.827 37.632 31.331 40.928 ;
     RECT  30.325 4.16 31.379 34.26 ;
     RECT  31.379 10.112 31.477 34.26 ;
     RECT  30.827 35.584 31.477 36.32 ;
     RECT  31.477 10.112 31.955 36.32 ;
     RECT  31.955 10.112 31.979 31.392 ;
     RECT  31.285 0.996 32.099 2.848 ;
     RECT  32.099 0.996 32.341 1.86 ;
     RECT  32.341 0.192 32.427 1.86 ;
     RECT  31.979 10.112 32.579 30.816 ;
     RECT  31.955 33.396 33.013 36.32 ;
     RECT  31.331 37.632 33.013 39.904 ;
     RECT  32.579 10.112 33.251 30.56 ;
     RECT  31.379 4.16 33.541 8.8 ;
     RECT  33.251 10.112 33.541 29.536 ;
     RECT  33.541 4.16 33.925 29.536 ;
     RECT  33.013 33.396 34.165 39.904 ;
     RECT  32.101 41.344 34.165 41.696 ;
     RECT  32.427 0.996 34.997 1.86 ;
     RECT  33.925 3.264 34.997 29.536 ;
     RECT  34.997 0.996 35.173 29.536 ;
     RECT  35.173 0.996 35.189 29.92 ;
     RECT  34.165 31.488 35.189 31.52 ;
     RECT  34.165 33.396 35.307 41.696 ;
     RECT  35.189 0.996 35.317 31.52 ;
     RECT  35.307 41.6 36.563 41.696 ;
     RECT  35.317 0.996 36.995 31.968 ;
     RECT  36.563 41.664 36.995 41.696 ;
     RECT  36.995 0.996 37.091 31.648 ;
     RECT  37.091 30.848 37.163 31.648 ;
     RECT  37.091 0.996 37.355 29.536 ;
     RECT  35.307 33.396 37.427 40.288 ;
     RECT  37.163 30.848 37.667 31.52 ;
     RECT  37.427 33.396 37.675 39.776 ;
     RECT  37.667 30.848 37.763 30.88 ;
     RECT  37.355 0.996 38.517 29.28 ;
     RECT  37.675 33.396 38.579 36.512 ;
     RECT  38.517 0.512 38.867 29.28 ;
     RECT  37.675 38.016 39.349 39.776 ;
     RECT  38.579 35.712 39.541 36.512 ;
     RECT  39.349 37.888 39.541 39.776 ;
     RECT  39.541 35.712 39.595 40.032 ;
     RECT  39.595 38.016 39.635 40.032 ;
     RECT  39.595 35.712 39.971 36.512 ;
     RECT  39.635 38.016 40.115 39.66 ;
     RECT  39.971 36.096 40.171 36.512 ;
     RECT  38.867 0.996 40.499 29.28 ;
     RECT  38.579 33.396 40.565 34.26 ;
     RECT  40.499 3.776 40.619 29.28 ;
     RECT  40.565 32.32 41.205 34.26 ;
     RECT  40.619 3.776 41.387 28.86 ;
     RECT  41.557 42.176 42.085 42.208 ;
     RECT  40.171 36.16 42.469 36.512 ;
     RECT  41.205 31.872 42.485 34.26 ;
     RECT  42.469 36.16 42.485 37.088 ;
     RECT  42.085 41.664 42.539 42.208 ;
     RECT  42.485 36.16 42.613 37.216 ;
     RECT  42.485 31.872 42.667 34.848 ;
     RECT  41.461 30.272 42.757 30.304 ;
     RECT  42.539 42.176 42.803 42.208 ;
     RECT  40.115 38.796 43.189 39.66 ;
     RECT  42.613 36.16 43.237 37.408 ;
     RECT  43.189 38.796 43.237 40.8 ;
     RECT  42.757 30.272 43.285 30.496 ;
     RECT  43.237 36.16 43.307 40.8 ;
     RECT  40.499 0.996 43.317 2.272 ;
     RECT  41.387 3.904 43.317 28.86 ;
     RECT  43.285 30.144 43.331 30.496 ;
     RECT  43.317 0.996 43.499 28.86 ;
     RECT  42.667 31.872 43.861 34.26 ;
     RECT  43.499 0.996 43.883 3.424 ;
     RECT  43.307 36.16 44.197 37.408 ;
     RECT  43.499 5.184 44.853 28.86 ;
     RECT  43.331 30.144 44.853 30.176 ;
     RECT  43.861 31.488 44.853 34.26 ;
     RECT  44.197 35.84 44.853 37.408 ;
     RECT  44.853 31.488 44.917 37.408 ;
     RECT  43.307 38.796 44.917 40.8 ;
     RECT  44.853 5.184 44.965 30.176 ;
     RECT  44.917 31.488 44.965 40.8 ;
     RECT  44.965 5.184 45.059 41.632 ;
     RECT  43.883 0.996 45.205 3.296 ;
     RECT  45.059 5.184 45.635 29.28 ;
     RECT  45.059 30.656 45.803 41.632 ;
     RECT  45.205 0.996 46.197 3.808 ;
     RECT  45.635 5.184 46.197 28.86 ;
     RECT  46.197 0.996 46.379 28.86 ;
     RECT  46.379 5.184 46.933 28.86 ;
     RECT  46.933 5.184 47.019 29.152 ;
     RECT  45.803 31.04 47.027 41.632 ;
     RECT  47.027 31.04 47.541 41.248 ;
     RECT  46.379 0.996 47.797 3.808 ;
     RECT  47.019 5.184 47.797 28.86 ;
     RECT  47.797 0.996 47.851 28.86 ;
     RECT  47.851 0.996 47.891 13.984 ;
     RECT  47.851 15.36 48.309 28.86 ;
     RECT  47.541 30.208 48.309 41.248 ;
     RECT  48.309 15.36 48.515 41.248 ;
     RECT  48.515 37.312 48.709 41.248 ;
     RECT  47.891 5.376 48.755 13.984 ;
     RECT  48.515 15.36 49.067 35.552 ;
     RECT  48.755 5.376 49.205 13.92 ;
     RECT  47.891 0.996 49.283 3.68 ;
     RECT  48.709 37.312 49.323 41.44 ;
     RECT  49.067 30.528 49.619 35.552 ;
     RECT  49.067 15.36 50.053 29.152 ;
     RECT  50.053 15.296 50.195 29.152 ;
     RECT  49.283 3.392 50.389 3.68 ;
     RECT  49.205 4.992 50.389 13.92 ;
     RECT  50.101 36.032 50.725 36.064 ;
     RECT  49.323 37.44 50.725 41.44 ;
     RECT  50.725 36.032 51.051 41.44 ;
     RECT  50.389 3.392 51.253 13.92 ;
     RECT  50.195 15.296 51.253 29.024 ;
     RECT  51.051 36.992 51.299 41.44 ;
     RECT  49.283 0.996 51.445 1.86 ;
     RECT  51.253 3.392 51.445 29.024 ;
     RECT  51.445 0.996 51.829 29.024 ;
     RECT  49.619 30.528 51.829 34.26 ;
     RECT  51.829 0.996 51.883 34.26 ;
     RECT  51.299 38.796 51.923 41.44 ;
     RECT  51.883 30.4 52.261 34.26 ;
     RECT  51.923 38.796 52.499 40.544 ;
     RECT  52.261 30.4 53.651 34.976 ;
     RECT  52.499 38.796 53.843 40.16 ;
     RECT  53.651 31.552 53.989 34.976 ;
     RECT  53.989 31.552 54.085 35.104 ;
     RECT  51.299 36.992 54.085 37.024 ;
     RECT  53.843 38.796 54.517 39.904 ;
     RECT  51.883 0.996 54.645 28.86 ;
     RECT  54.085 31.552 54.645 37.024 ;
     RECT  54.517 38.656 54.645 39.904 ;
     RECT  54.645 31.552 54.707 39.904 ;
     RECT  54.707 31.552 55.221 37.024 ;
     RECT  55.221 30.848 55.237 37.024 ;
     RECT  55.237 30.72 55.331 37.024 ;
     RECT  54.707 38.796 55.331 39.904 ;
     RECT  55.331 30.72 55.925 35.104 ;
     RECT  55.331 36.416 56.043 37.024 ;
     RECT  54.645 0.996 56.107 29.024 ;
     RECT  56.107 5.568 56.373 29.024 ;
     RECT  55.925 30.336 56.373 35.104 ;
     RECT  56.107 0.996 56.483 4.064 ;
     RECT  56.043 36.416 56.483 36.512 ;
     RECT  56.373 5.568 57.011 35.104 ;
     RECT  57.011 5.568 57.203 34.976 ;
     RECT  57.203 5.568 57.443 12.66 ;
     RECT  57.443 5.952 57.539 12.66 ;
     RECT  57.539 5.952 57.579 9.824 ;
     RECT  57.579 5.952 57.587 9.312 ;
     RECT  56.483 36.48 57.635 36.512 ;
     RECT  56.483 0.996 57.683 3.936 ;
     RECT  57.539 11.648 57.971 12.66 ;
     RECT  57.587 6.272 58.347 9.312 ;
     RECT  57.203 14.144 58.347 34.976 ;
     RECT  58.347 14.144 58.499 19.36 ;
     RECT  58.347 20.672 58.603 34.976 ;
     RECT  58.499 14.144 58.645 14.432 ;
     RECT  58.347 6.272 58.739 7.26 ;
     RECT  58.603 20.736 58.795 34.976 ;
     RECT  57.971 11.796 58.981 12.66 ;
     RECT  58.981 11.796 59.051 12.768 ;
     RECT  58.645 14.08 59.051 14.432 ;
     RECT  57.683 0.996 59.061 3.296 ;
     RECT  59.061 0.996 59.115 4.064 ;
     RECT  59.115 4.032 59.171 4.064 ;
     RECT  58.117 36.288 59.315 36.32 ;
     RECT  58.795 20.992 59.509 34.976 ;
     RECT  59.509 20.992 59.691 35.808 ;
     RECT  58.739 6.396 60.021 7.26 ;
     RECT  60.021 6.272 60.037 7.26 ;
     RECT  58.347 8.832 60.037 9.312 ;
     RECT  59.051 14.272 60.037 14.432 ;
     RECT  58.499 15.872 60.037 19.36 ;
     RECT  60.021 4.544 60.083 4.576 ;
     RECT  60.037 6.272 60.083 9.312 ;
     RECT  60.037 14.272 60.083 19.36 ;
     RECT  60.083 6.396 60.085 9.312 ;
     RECT  59.051 11.796 60.085 12.66 ;
     RECT  60.085 6.396 60.139 12.66 ;
     RECT  60.139 8.832 60.419 12.66 ;
     RECT  60.419 11.796 60.565 12.66 ;
     RECT  60.083 14.272 60.565 18.976 ;
     RECT  59.691 20.992 60.709 34.784 ;
     RECT  60.709 20.928 60.803 34.784 ;
     RECT  60.565 11.796 61.427 18.976 ;
     RECT  60.419 8.832 61.619 9.312 ;
     RECT  61.427 16.128 61.909 18.976 ;
     RECT  61.909 16.128 61.957 19.232 ;
     RECT  60.803 20.928 61.957 34.26 ;
     RECT  61.619 9.28 62.195 9.312 ;
     RECT  61.957 16.128 62.195 34.26 ;
     RECT  62.195 21.504 62.723 34.26 ;
     RECT  62.723 21.568 62.771 34.26 ;
     RECT  61.427 11.796 62.915 14.816 ;
     RECT  62.771 21.568 63.083 30.816 ;
     RECT  63.083 21.568 63.107 29.216 ;
     RECT  63.107 22.272 63.147 29.216 ;
     RECT  62.915 11.796 63.157 12.66 ;
     RECT  63.083 30.784 63.251 30.816 ;
     RECT  62.195 16.128 63.275 20.128 ;
     RECT  63.147 27.584 63.275 29.216 ;
     RECT  62.915 14.208 63.299 14.816 ;
     RECT  63.275 17.196 63.299 20.128 ;
     RECT  63.275 27.996 63.299 29.216 ;
     RECT  63.147 22.596 63.347 26.144 ;
     RECT  63.299 20.096 63.531 20.128 ;
     RECT  63.299 17.196 63.539 18.784 ;
     RECT  63.157 11.328 63.595 12.66 ;
     RECT  63.541 15.744 63.595 15.776 ;
     RECT  62.771 33.396 63.861 34.26 ;
     RECT  63.299 14.208 63.875 14.24 ;
     RECT  63.861 33.396 63.923 34.848 ;
     RECT  63.347 22.596 64.163 24.736 ;
     RECT  64.117 9.664 64.171 9.696 ;
     RECT  63.539 17.196 64.211 18.272 ;
     RECT  64.213 20.928 64.299 20.96 ;
     RECT  59.115 0.996 64.8 1.86 ;
     RECT  60.139 6.396 64.8 7.26 ;
     RECT  63.595 11.796 64.8 12.66 ;
     RECT  64.211 17.196 64.8 18.06 ;
     RECT  64.163 22.596 64.8 23.46 ;
     RECT  63.299 27.996 64.8 28.86 ;
     RECT  63.923 33.396 64.8 34.26 ;
     RECT  55.331 38.796 64.8 39.66 ;
    LAYER M7 ;
     RECT  32.384 0.181 32.416 0.235 ;
     RECT  32.388 0.235 32.416 0.531 ;
     RECT  38.528 0.501 38.56 0.531 ;
     RECT  17.056 0.531 17.344 1.397 ;
     RECT  6.256 0.531 6.544 1.973 ;
     RECT  11.656 0.531 11.944 1.973 ;
     RECT  47.424 1.973 47.456 2.037 ;
     RECT  10.112 1.397 10.144 2.229 ;
     RECT  11.52 1.973 11.944 2.229 ;
     RECT  13.504 1.397 13.536 2.229 ;
     RECT  38.528 0.531 38.944 2.357 ;
     RECT  19.2 1.397 19.232 2.677 ;
     RECT  22.456 0.531 22.744 2.677 ;
     RECT  37.952 2.357 38.944 2.677 ;
     RECT  17.056 1.397 17.632 2.741 ;
     RECT  0.856 0.531 1.144 2.805 ;
     RECT  27.856 0.531 28.144 2.805 ;
     RECT  44.056 0.531 44.344 2.805 ;
     RECT  54.856 0.531 55.144 2.805 ;
     RECT  60.256 0.531 60.544 2.997 ;
     RECT  46.208 2.037 47.456 3.125 ;
     RECT  35.008 2.677 35.04 3.189 ;
     RECT  54.856 2.805 56.416 3.189 ;
     RECT  43.84 2.805 44.344 3.253 ;
     RECT  54.856 3.189 57.184 3.253 ;
     RECT  59.072 2.997 60.544 3.253 ;
     RECT  35.008 3.189 35.872 3.317 ;
     RECT  27.856 2.805 28.704 3.381 ;
     RECT  6.256 1.973 7.52 3.499 ;
     RECT  3.264 3.381 3.296 3.637 ;
     RECT  8.832 2.229 10.144 3.701 ;
     RECT  3.264 3.637 4.128 3.765 ;
     RECT  26.944 3.381 28.704 3.765 ;
     RECT  51.456 2.805 51.488 3.765 ;
     RECT  37.952 2.677 39.264 3.893 ;
     RECT  0.856 2.805 1.696 3.957 ;
     RECT  3.264 3.765 4.832 3.957 ;
     RECT  51.328 3.765 51.488 4.075 ;
     RECT  54.856 3.253 60.544 4.075 ;
     RECT  8.576 3.701 10.144 4.149 ;
     RECT  11.52 2.229 13.536 4.149 ;
     RECT  16.768 2.741 17.632 4.277 ;
     RECT  19.2 2.677 20.448 4.277 ;
     RECT  22.456 2.677 23.2 4.277 ;
     RECT  41.344 2.229 41.376 4.277 ;
     RECT  43.328 3.253 44.344 4.277 ;
     RECT  49.456 0.531 49.744 4.277 ;
     RECT  51.328 4.075 51.36 4.277 ;
     RECT  8.576 4.149 13.536 4.395 ;
     RECT  19.2 4.277 23.2 4.405 ;
     RECT  16.064 4.277 17.632 4.459 ;
     RECT  19.072 4.405 23.2 4.533 ;
     RECT  54.856 4.075 58.208 4.533 ;
     RECT  18.816 4.533 23.2 4.587 ;
     RECT  49.456 4.277 51.36 4.587 ;
     RECT  37.952 3.893 39.648 4.789 ;
     RECT  10.688 4.395 13.536 4.917 ;
     RECT  49.456 4.587 50.784 4.981 ;
     RECT  6.256 3.499 7.2 5.045 ;
     RECT  8.576 4.395 9.12 5.045 ;
     RECT  35.008 3.317 36.512 5.173 ;
     RECT  37.824 4.789 39.648 5.173 ;
     RECT  0.856 3.957 4.832 5.419 ;
     RECT  41.344 4.277 44.344 5.429 ;
     RECT  46.208 3.125 47.84 5.429 ;
     RECT  26.944 3.765 29.408 5.493 ;
     RECT  49.216 4.981 50.784 5.739 ;
     RECT  26.944 5.493 30.304 5.803 ;
     RECT  6.256 5.045 9.12 5.877 ;
     RECT  10.688 4.917 14.176 5.877 ;
     RECT  54.144 4.533 58.208 5.877 ;
     RECT  35.008 5.173 39.648 6.005 ;
     RECT  32.388 0.531 33.544 6.069 ;
     RECT  35.008 6.005 39.84 6.069 ;
     RECT  52.864 5.877 58.208 6.069 ;
     RECT  6.256 5.877 14.176 6.187 ;
     RECT  6.256 6.187 7.776 6.315 ;
     RECT  9.408 6.187 14.176 6.315 ;
     RECT  18.816 4.587 22.744 6.315 ;
     RECT  41.344 5.429 47.84 6.315 ;
     RECT  60.032 4.075 60.544 6.315 ;
     RECT  0.856 5.419 4.128 6.773 ;
     RECT  52.096 6.069 58.208 6.773 ;
     RECT  16.064 4.459 17.344 6.827 ;
     RECT  18.944 6.315 20.448 6.827 ;
     RECT  52.096 6.773 58.336 6.891 ;
     RECT  27.584 5.803 30.304 7.349 ;
     RECT  32.388 6.069 39.84 7.349 ;
     RECT  27.584 7.349 39.84 7.467 ;
     RECT  52.416 6.891 58.336 7.659 ;
     RECT  52.416 7.659 53.216 7.787 ;
     RECT  54.856 7.659 58.336 7.851 ;
     RECT  60.256 6.315 60.544 7.925 ;
     RECT  18.944 6.827 20.256 7.979 ;
     RECT  24.64 3.957 24.672 8.043 ;
     RECT  41.6 6.315 47.84 8.043 ;
     RECT  26.24 7.541 26.272 8.053 ;
     RECT  27.584 7.467 37.344 8.053 ;
     RECT  38.656 7.467 39.84 8.053 ;
     RECT  26.24 8.053 37.344 8.107 ;
     RECT  42.304 8.043 47.84 8.117 ;
     RECT  49.216 5.739 50.272 8.117 ;
     RECT  57.536 7.851 58.336 8.171 ;
     RECT  0.856 6.773 4.768 8.245 ;
     RECT  42.304 8.117 50.272 8.363 ;
     RECT  26.496 8.107 37.344 8.427 ;
     RECT  42.304 8.363 47.648 8.427 ;
     RECT  16.128 6.827 17.344 8.437 ;
     RECT  30.528 8.427 37.344 8.491 ;
     RECT  6.256 6.315 7.2 8.501 ;
     RECT  9.408 6.315 10.08 8.501 ;
     RECT  11.392 6.315 14.176 8.501 ;
     RECT  49.344 8.363 50.272 8.555 ;
     RECT  52.48 7.787 53.216 8.555 ;
     RECT  26.496 8.427 28.704 8.619 ;
     RECT  9.408 8.501 14.176 8.683 ;
     RECT  0.512 8.245 4.768 8.821 ;
     RECT  6.256 8.501 7.392 8.821 ;
     RECT  60.096 7.925 60.544 8.821 ;
     RECT  57.536 8.171 58.208 8.875 ;
     RECT  16.128 8.437 17.504 8.949 ;
     RECT  52.48 8.555 53.024 9.003 ;
     RECT  49.344 8.555 50.08 9.323 ;
     RECT  54.856 7.851 56.096 9.515 ;
     RECT  30.528 8.491 36.704 9.707 ;
     RECT  0.512 8.821 7.392 9.771 ;
     RECT  31.168 9.707 36.704 9.771 ;
     RECT  46.208 8.427 47.648 9.771 ;
     RECT  49.344 9.323 49.744 9.771 ;
     RECT  57.536 8.875 57.568 9.781 ;
     RECT  57.088 9.781 57.568 9.835 ;
     RECT  16.128 8.949 17.632 9.845 ;
     RECT  19.072 7.979 20.256 9.845 ;
     RECT  22.456 6.315 22.744 9.909 ;
     RECT  31.296 9.771 36.704 9.909 ;
     RECT  38.656 8.053 40.992 9.973 ;
     RECT  42.304 8.427 44.344 9.973 ;
     RECT  31.296 9.909 36.768 10.027 ;
     RECT  16.128 9.845 20.256 10.091 ;
     RECT  26.496 8.619 28.144 10.091 ;
     RECT  9.792 8.683 14.176 10.229 ;
     RECT  52.736 9.003 53.024 10.283 ;
     RECT  16.192 10.091 20.256 10.357 ;
     RECT  22.336 9.909 22.744 10.357 ;
     RECT  60.096 8.821 60.704 10.539 ;
     RECT  52.736 10.283 52.96 10.603 ;
     RECT  0.512 9.771 7.264 10.741 ;
     RECT  9.792 10.229 14.24 10.859 ;
     RECT  32.388 10.027 36.768 10.869 ;
     RECT  38.656 9.973 44.344 10.869 ;
     RECT  57.088 9.835 57.12 10.923 ;
     RECT  0.256 10.741 7.264 11.061 ;
     RECT  32.388 10.869 44.344 11.307 ;
     RECT  46.656 9.771 47.648 11.317 ;
     RECT  64.128 9.653 64.16 11.317 ;
     RECT  40.512 11.307 44.344 11.509 ;
     RECT  52.736 10.603 52.768 11.509 ;
     RECT  0.256 11.061 7.392 11.637 ;
     RECT  40.512 11.509 45.152 11.637 ;
     RECT  46.464 11.317 48.16 11.637 ;
     RECT  40.512 11.637 48.16 11.691 ;
     RECT  16.192 10.357 22.744 12.213 ;
     RECT  52.288 11.509 52.768 12.213 ;
     RECT  32.388 11.307 38.944 12.267 ;
     RECT  41.216 11.691 48.16 12.267 ;
     RECT  60.256 10.539 60.704 12.725 ;
     RECT  30.784 11.381 30.816 12.779 ;
     RECT  59.008 12.725 60.704 12.789 ;
     RECT  59.008 12.789 60.768 12.917 ;
     RECT  0.192 11.637 7.392 13.035 ;
     RECT  9.792 10.859 10.08 13.045 ;
     RECT  32.388 12.267 36.768 13.163 ;
     RECT  42.176 12.267 48.16 13.611 ;
     RECT  42.88 13.611 48.16 13.749 ;
     RECT  49.456 9.771 49.744 13.749 ;
     RECT  8.96 13.045 10.08 13.803 ;
     RECT  11.392 10.859 14.24 13.803 ;
     RECT  38.656 12.267 38.944 13.813 ;
     RECT  32.388 13.163 34.592 13.877 ;
     RECT  42.88 13.749 49.744 13.931 ;
     RECT  54.856 9.515 55.144 13.941 ;
     RECT  56.768 13.429 56.8 13.941 ;
     RECT  0.192 13.035 4.064 14.197 ;
     RECT  11.52 13.803 14.24 14.197 ;
     RECT  16 12.213 22.744 14.197 ;
     RECT  26.496 10.091 26.528 14.197 ;
     RECT  59.008 12.917 61.536 14.197 ;
     RECT  31.168 13.877 34.592 14.261 ;
     RECT  38.656 13.813 40.16 14.261 ;
     RECT  54.856 13.941 56.8 14.261 ;
     RECT  58.112 14.197 61.536 14.261 ;
     RECT  52.288 12.213 53.024 14.325 ;
     RECT  54.856 14.261 61.536 14.443 ;
     RECT  30.016 14.261 34.592 14.453 ;
     RECT  36.096 13.163 36.768 14.453 ;
     RECT  51.264 14.325 53.024 14.453 ;
     RECT  25.664 14.197 26.528 14.517 ;
     RECT  27.856 10.091 28.144 14.517 ;
     RECT  0.064 14.197 4.064 14.773 ;
     RECT  5.632 13.035 7.392 14.773 ;
     RECT  25.664 14.517 28.144 14.773 ;
     RECT  30.016 14.453 36.768 14.773 ;
     RECT  25.664 14.773 36.768 15.019 ;
     RECT  31.168 15.019 36.768 15.029 ;
     RECT  38.464 14.261 40.16 15.029 ;
     RECT  9.792 13.803 10.08 15.285 ;
     RECT  42.88 13.931 48.16 15.285 ;
     RECT  49.456 13.931 49.744 15.349 ;
     RECT  31.168 15.029 40.16 15.605 ;
     RECT  42.304 15.285 48.16 15.605 ;
     RECT  49.456 15.349 49.888 15.605 ;
     RECT  0.064 14.773 7.392 15.787 ;
     RECT  31.168 15.605 49.888 15.851 ;
     RECT  25.664 15.019 29.472 15.925 ;
     RECT  11.52 14.197 22.744 16.043 ;
     RECT  24.576 15.925 29.472 16.043 ;
     RECT  51.264 14.453 53.344 16.235 ;
     RECT  26.432 16.043 29.472 16.373 ;
     RECT  51.392 16.235 53.344 16.437 ;
     RECT  54.856 14.443 58.272 16.437 ;
     RECT  60.256 14.443 61.536 16.437 ;
     RECT  63.552 11.317 64.16 16.501 ;
     RECT  31.296 15.851 49.888 16.555 ;
     RECT  9.344 15.285 10.08 16.619 ;
     RECT  11.52 16.043 19.232 16.619 ;
     RECT  31.68 16.555 49.888 16.619 ;
     RECT  0.064 15.787 7.072 16.875 ;
     RECT  0.192 16.875 7.072 16.939 ;
     RECT  13.888 16.619 19.232 16.939 ;
     RECT  51.392 16.437 61.536 16.949 ;
     RECT  63.232 16.501 64.16 16.949 ;
     RECT  24.576 16.043 24.608 17.003 ;
     RECT  16.192 16.939 19.232 17.067 ;
     RECT  0.192 16.939 6.544 17.131 ;
     RECT  13.888 16.939 14.88 17.131 ;
     RECT  11.52 16.619 11.944 17.643 ;
     RECT  14.336 17.131 14.88 17.643 ;
     RECT  20.544 16.043 22.744 17.707 ;
     RECT  26.432 16.373 29.6 18.165 ;
     RECT  31.68 16.619 47.776 18.165 ;
     RECT  49.28 16.619 49.888 18.165 ;
     RECT  51.392 16.949 64.16 18.165 ;
     RECT  0.192 17.131 3.232 18.283 ;
     RECT  9.344 16.619 9.376 18.283 ;
     RECT  16.192 17.067 19.104 18.283 ;
     RECT  49.28 18.165 64.16 18.283 ;
     RECT  49.28 18.283 63.52 18.411 ;
     RECT  30.912 18.165 47.776 18.421 ;
     RECT  49.28 18.411 52.128 18.421 ;
     RECT  30.912 18.421 52.128 18.603 ;
     RECT  4.864 17.131 4.896 18.795 ;
     RECT  14.336 17.643 14.56 18.859 ;
     RECT  21.376 17.707 22.744 19.051 ;
     RECT  25.6 18.165 29.6 19.179 ;
     RECT  17.056 18.283 19.104 19.435 ;
     RECT  0.512 18.283 3.232 19.819 ;
     RECT  21.696 19.051 22.744 20.011 ;
     RECT  0.512 19.819 2.784 20.139 ;
     RECT  0.512 20.139 2.272 20.149 ;
     RECT  26.048 19.179 29.6 20.469 ;
     RECT  30.912 18.603 49.888 20.469 ;
     RECT  0.128 20.149 2.272 20.587 ;
     RECT  51.328 18.603 52.128 20.661 ;
     RECT  53.696 18.411 63.52 20.917 ;
     RECT  53.696 20.917 64.288 21.045 ;
     RECT  14.528 18.859 14.56 21.109 ;
     RECT  21.76 20.011 22.744 21.163 ;
     RECT  26.048 20.469 49.888 21.291 ;
     RECT  24.256 17.077 24.288 21.419 ;
     RECT  14.528 21.109 14.688 21.493 ;
     RECT  17.056 19.435 18.72 21.557 ;
     RECT  11.656 17.643 11.944 21.621 ;
     RECT  35.84 21.291 49.888 21.621 ;
     RECT  51.264 20.661 52.128 21.621 ;
     RECT  53.568 21.045 64.288 21.675 ;
     RECT  9.536 21.621 9.568 21.685 ;
     RECT  10.944 21.621 11.944 21.685 ;
     RECT  26.048 21.291 34.464 21.867 ;
     RECT  17.056 21.557 19.104 21.877 ;
     RECT  9.536 21.685 11.944 22.005 ;
     RECT  8.384 22.005 11.944 22.069 ;
     RECT  17.056 21.877 19.616 22.069 ;
     RECT  31.424 21.867 34.464 22.123 ;
     RECT  6.256 17.131 6.544 22.261 ;
     RECT  7.936 22.069 11.944 22.261 ;
     RECT  0.128 20.587 1.952 22.315 ;
     RECT  0.32 22.315 1.952 22.325 ;
     RECT  31.424 22.123 34.208 22.443 ;
     RECT  6.256 22.261 11.944 22.453 ;
     RECT  14.272 21.493 14.688 22.453 ;
     RECT  35.84 21.621 52.128 22.453 ;
     RECT  53.568 21.675 56.736 22.453 ;
     RECT  35.84 22.453 56.736 22.965 ;
     RECT  58.112 21.675 64.288 22.965 ;
     RECT  5.76 22.453 11.944 23.029 ;
     RECT  26.048 21.867 29.664 23.029 ;
     RECT  14.272 22.453 15.008 23.083 ;
     RECT  22.336 21.163 22.744 23.541 ;
     RECT  24.384 23.029 29.664 23.541 ;
     RECT  0.32 22.325 2.208 23.595 ;
     RECT  22.336 23.541 29.664 23.595 ;
     RECT  5.76 23.029 12.064 23.605 ;
     RECT  27.52 23.595 29.664 23.723 ;
     RECT  35.84 22.965 64.288 23.723 ;
     RECT  31.936 22.443 34.208 23.861 ;
     RECT  27.856 23.723 29.664 23.925 ;
     RECT  31.68 23.861 34.208 23.925 ;
     RECT  27.856 23.925 34.208 24.821 ;
     RECT  35.84 23.723 60.544 24.821 ;
     RECT  27.856 24.821 60.544 24.939 ;
     RECT  27.856 24.939 53.28 25.003 ;
     RECT  62.016 23.723 64.288 25.067 ;
     RECT  27.856 25.003 33.76 25.131 ;
     RECT  35.072 25.003 53.28 25.131 ;
     RECT  17.056 22.069 21.024 25.333 ;
     RECT  22.336 23.595 26.208 25.333 ;
     RECT  54.72 24.939 60.544 25.333 ;
     RECT  5.76 23.605 12.384 25.589 ;
     RECT  14.528 23.083 15.008 25.589 ;
     RECT  17.056 25.333 26.208 25.589 ;
     RECT  14.528 25.589 26.208 25.707 ;
     RECT  54.72 25.333 60.704 25.707 ;
     RECT  58.56 25.707 60.704 25.835 ;
     RECT  5.76 25.589 12.576 25.899 ;
     RECT  14.528 25.707 18.08 25.899 ;
     RECT  35.072 25.131 52.128 25.963 ;
     RECT  14.528 25.899 14.56 26.027 ;
     RECT  36.416 25.963 52.128 26.027 ;
     RECT  19.52 25.707 26.208 26.283 ;
     RECT  36.416 26.027 51.744 26.475 ;
     RECT  15.936 25.899 18.08 26.539 ;
     RECT  5.76 25.899 12.512 26.741 ;
     RECT  31.68 25.131 33.76 26.741 ;
     RECT  35.072 25.963 35.104 26.741 ;
     RECT  54.72 25.707 56.992 26.741 ;
     RECT  36.416 26.475 51.616 26.987 ;
     RECT  43.904 26.987 51.616 27.051 ;
     RECT  62.464 25.067 64.288 27.051 ;
     RECT  31.68 26.741 35.104 27.115 ;
     RECT  32.512 27.115 35.104 27.179 ;
     RECT  35.072 27.179 35.104 27.435 ;
     RECT  36.416 26.987 42.528 27.435 ;
     RECT  46.976 27.051 51.616 27.435 ;
     RECT  51.456 27.435 51.616 27.627 ;
     RECT  5.184 26.741 12.512 27.701 ;
     RECT  19.52 26.283 22.744 27.829 ;
     RECT  24.448 26.283 26.208 27.829 ;
     RECT  5.184 27.701 12.896 27.883 ;
     RECT  19.52 27.829 26.208 27.883 ;
     RECT  46.976 27.435 49.888 27.883 ;
     RECT  27.856 25.131 30.048 28.405 ;
     RECT  32.512 27.179 33.544 28.405 ;
     RECT  36.416 27.435 38.944 28.459 ;
     RECT  51.584 27.627 51.616 28.459 ;
     RECT  54.656 26.741 56.992 28.459 ;
     RECT  58.688 25.835 60.704 28.459 ;
     RECT  5.76 27.883 12.896 28.981 ;
     RECT  14.208 27.829 14.24 28.981 ;
     RECT  54.656 28.459 56.16 29.035 ;
     RECT  62.528 27.051 64.288 29.035 ;
     RECT  46.976 27.883 49.744 29.163 ;
     RECT  19.52 27.883 19.872 29.227 ;
     RECT  43.904 27.051 45.344 29.291 ;
     RECT  3.712 29.173 3.744 29.365 ;
     RECT  5.76 28.981 14.432 29.365 ;
     RECT  16.576 26.539 18.08 29.365 ;
     RECT  5.76 29.365 18.08 29.493 ;
     RECT  19.52 29.227 19.808 29.493 ;
     RECT  0.856 23.595 2.208 29.547 ;
     RECT  21.376 27.883 26.208 29.557 ;
     RECT  27.856 28.405 30.368 29.557 ;
     RECT  58.88 28.459 60.704 29.557 ;
     RECT  21.376 29.557 30.368 29.867 ;
     RECT  36.416 28.459 37.344 29.877 ;
     RECT  21.376 29.867 22.88 29.941 ;
     RECT  54.856 29.035 56.16 29.941 ;
     RECT  31.936 28.405 33.544 30.133 ;
     RECT  47.552 29.163 49.744 30.251 ;
     RECT  58.88 29.557 61.024 30.251 ;
     RECT  5.76 29.493 19.808 30.315 ;
     RECT  35.2 29.877 37.344 30.315 ;
     RECT  59.776 30.251 61.024 30.325 ;
     RECT  31.744 30.133 33.544 30.443 ;
     RECT  3.712 29.365 3.936 30.453 ;
     RECT  40.576 27.435 42.528 30.453 ;
     RECT  43.904 29.291 44.344 30.453 ;
     RECT  59.776 30.325 61.344 30.645 ;
     RECT  63.04 29.035 64.288 30.645 ;
     RECT  16.576 30.315 19.808 30.709 ;
     RECT  21.12 29.941 22.88 30.709 ;
     RECT  5.76 30.315 14.432 30.827 ;
     RECT  31.744 30.443 31.968 30.827 ;
     RECT  35.2 30.315 35.232 30.827 ;
     RECT  48.64 30.251 49.744 30.827 ;
     RECT  59.776 30.645 64.288 30.827 ;
     RECT  54.856 29.941 57.376 30.891 ;
     RECT  3.712 30.453 4.384 31.093 ;
     RECT  5.76 30.827 8.608 31.093 ;
     RECT  51.84 29.557 51.872 31.157 ;
     RECT  16.576 30.709 22.88 31.211 ;
     RECT  21.44 31.211 22.88 31.349 ;
     RECT  49.024 30.827 49.744 31.349 ;
     RECT  51.84 31.157 52.192 31.349 ;
     RECT  16.576 31.211 19.936 31.403 ;
     RECT  31.936 30.827 31.968 31.403 ;
     RECT  59.776 30.827 62.112 31.403 ;
     RECT  24.448 29.867 30.368 31.541 ;
     RECT  0.856 29.547 2.08 31.595 ;
     RECT  37.12 30.315 37.344 31.659 ;
     RECT  54.856 30.891 56.416 31.669 ;
     RECT  59.776 31.403 61.344 31.669 ;
     RECT  10.112 30.827 14.432 31.797 ;
     RECT  10.112 31.797 14.56 31.861 ;
     RECT  40.576 30.453 44.344 31.915 ;
     RECT  42.496 31.915 44.344 31.989 ;
     RECT  45.76 30.645 45.792 31.989 ;
     RECT  42.496 31.989 45.792 32.117 ;
     RECT  49.024 31.349 52.192 32.171 ;
     RECT  59.52 31.669 61.344 32.171 ;
     RECT  21.44 31.349 23.008 32.245 ;
     RECT  24.448 31.541 30.496 32.245 ;
     RECT  40.576 31.915 41.056 32.363 ;
     RECT  54.656 31.669 56.416 32.427 ;
     RECT  54.656 32.427 56.16 32.437 ;
     RECT  41.024 32.363 41.056 32.491 ;
     RECT  42.496 32.117 46.432 32.555 ;
     RECT  59.52 32.171 61.024 32.555 ;
     RECT  59.52 32.555 60.704 32.747 ;
     RECT  3.712 31.093 8.608 32.757 ;
     RECT  10.112 31.861 15.136 32.757 ;
     RECT  21.44 32.245 30.496 32.821 ;
     RECT  49.456 32.171 52.192 32.885 ;
     RECT  54.144 32.437 56.16 32.939 ;
     RECT  21.44 32.821 31.52 33.131 ;
     RECT  0.856 31.595 1.504 33.269 ;
     RECT  3.712 32.757 15.136 33.323 ;
     RECT  44.056 32.555 46.432 33.323 ;
     RECT  49.456 32.885 52.32 33.323 ;
     RECT  38.656 28.459 38.944 33.781 ;
     RECT  64.256 30.827 64.288 33.781 ;
     RECT  21.44 33.131 30.048 33.835 ;
     RECT  63.872 33.781 64.288 33.835 ;
     RECT  10.56 33.323 15.136 33.845 ;
     RECT  10.56 33.845 15.2 34.411 ;
     RECT  21.44 33.835 28.384 34.475 ;
     RECT  14.528 34.411 15.2 34.677 ;
     RECT  17.056 31.403 19.936 34.677 ;
     RECT  33.256 30.443 33.544 34.677 ;
     RECT  0.856 33.269 2.016 34.731 ;
     RECT  14.528 34.677 19.936 34.731 ;
     RECT  31.488 33.131 31.52 34.741 ;
     RECT  33.152 34.677 33.544 34.741 ;
     RECT  44.056 33.323 45.408 34.741 ;
     RECT  37.312 31.659 37.344 34.805 ;
     RECT  42.496 32.555 42.528 34.805 ;
     RECT  3.712 33.323 8.992 34.859 ;
     RECT  14.528 34.731 19.744 34.859 ;
     RECT  42.496 34.805 42.656 34.859 ;
     RECT  52.288 33.323 52.32 34.859 ;
     RECT  63.872 33.835 63.904 34.859 ;
     RECT  36.992 34.805 37.344 34.869 ;
     RECT  59.52 32.747 60.544 34.933 ;
     RECT  36.864 34.869 37.344 34.997 ;
     RECT  38.656 33.781 40.16 34.997 ;
     RECT  31.488 34.741 34.848 35.061 ;
     RECT  49.456 33.323 50.976 35.253 ;
     RECT  31.488 35.061 35.232 35.381 ;
     RECT  36.864 34.997 40.16 35.381 ;
     RECT  14.528 34.859 19.68 35.435 ;
     RECT  21.504 34.475 28.384 35.637 ;
     RECT  29.888 33.835 30.048 35.637 ;
     RECT  21.504 35.637 30.048 35.819 ;
     RECT  58.752 34.933 60.544 35.819 ;
     RECT  27.008 35.819 30.048 35.829 ;
     RECT  31.488 35.381 40.16 35.829 ;
     RECT  49.024 35.253 50.976 36.021 ;
     RECT  44.056 34.741 46.304 36.085 ;
     RECT  54.144 32.939 56.032 36.331 ;
     RECT  58.752 35.819 58.784 36.331 ;
     RECT  42.624 34.859 42.656 36.405 ;
     RECT  27.008 35.829 40.16 36.523 ;
     RECT  17.056 35.435 19.68 36.533 ;
     RECT  21.504 35.819 25.696 36.533 ;
     RECT  27.008 36.523 39.584 36.971 ;
     RECT  54.528 36.331 56.032 37.035 ;
     RECT  0.856 34.731 1.632 37.099 ;
     RECT  3.712 34.859 8.544 37.099 ;
     RECT  27.008 36.971 29.664 37.099 ;
     RECT  49.024 36.021 51.04 37.355 ;
     RECT  31.744 36.971 39.584 37.611 ;
     RECT  44.056 36.085 47.264 37.611 ;
     RECT  10.56 34.411 13.024 37.675 ;
     RECT  31.744 37.611 37.344 37.675 ;
     RECT  10.56 37.675 12.896 37.803 ;
     RECT  4.352 37.099 8.544 38.059 ;
     RECT  4.992 38.059 8.544 38.069 ;
     RECT  10.56 37.803 12.256 38.069 ;
     RECT  4.992 38.069 12.256 38.123 ;
     RECT  14.528 35.435 15.392 38.123 ;
     RECT  29.632 37.099 29.664 38.123 ;
     RECT  17.056 36.533 25.696 38.133 ;
     RECT  27.008 37.099 28.256 38.133 ;
     RECT  42.496 36.405 42.656 38.133 ;
     RECT  44.056 37.611 45.728 38.133 ;
     RECT  47.232 37.611 47.264 38.133 ;
     RECT  33.024 37.675 37.344 38.251 ;
     RECT  17.056 38.133 28.256 38.261 ;
     RECT  33.256 38.251 37.344 38.379 ;
     RECT  14.528 38.123 14.56 38.507 ;
     RECT  6.144 38.123 12.256 38.571 ;
     RECT  15.936 38.261 28.256 38.635 ;
     RECT  15.936 38.635 19.68 38.699 ;
     RECT  54.528 37.035 55.144 38.699 ;
     RECT  6.144 38.571 11.944 39.211 ;
     RECT  15.936 38.699 17.632 39.211 ;
     RECT  21.632 38.635 28.256 39.211 ;
     RECT  42.496 38.133 45.728 39.221 ;
     RECT  47.232 38.133 47.776 39.221 ;
     RECT  7.936 39.211 11.944 39.275 ;
     RECT  16 39.211 17.632 39.275 ;
     RECT  21.632 39.211 25.696 39.275 ;
     RECT  35.136 38.379 37.344 39.275 ;
     RECT  21.76 39.275 25.696 39.787 ;
     RECT  27.008 39.211 28.256 39.787 ;
     RECT  42.496 39.221 47.776 39.787 ;
     RECT  49.152 37.355 51.04 39.787 ;
     RECT  8.192 39.275 11.944 39.915 ;
     RECT  19.648 38.699 19.68 39.979 ;
     RECT  6.144 39.211 6.544 40.043 ;
     RECT  38.656 37.611 39.584 40.043 ;
     RECT  49.152 39.787 50.976 40.043 ;
     RECT  10.56 39.915 11.944 40.299 ;
     RECT  35.136 39.275 37.024 40.299 ;
     RECT  42.496 39.787 46.816 40.363 ;
     RECT  8.192 39.915 9.184 40.427 ;
     RECT  8.192 40.427 8.224 40.555 ;
     RECT  11.52 40.299 11.944 40.555 ;
     RECT  27.856 39.787 28.256 40.555 ;
     RECT  42.496 40.363 45.728 40.555 ;
     RECT  49.344 40.043 50.976 40.555 ;
     RECT  17.056 39.275 17.632 40.811 ;
     RECT  21.76 39.787 25.184 40.811 ;
     RECT  21.76 40.811 22.744 41.067 ;
     RECT  24.448 40.811 25.184 41.067 ;
     RECT  49.344 40.555 49.744 41.067 ;
     RECT  35.136 40.299 36.448 41.387 ;
     RECT  44.056 40.555 45.024 41.643 ;
     RECT  36.416 41.387 36.448 41.707 ;
     RECT  42.496 40.555 42.528 41.707 ;
     RECT  24.448 41.067 24.48 42.475 ;
     RECT  0.856 37.099 1.144 42.669 ;
     RECT  6.256 40.043 6.544 42.669 ;
     RECT  11.656 40.555 11.944 42.669 ;
     RECT  17.056 40.811 17.344 42.669 ;
     RECT  22.456 41.067 22.744 42.669 ;
     RECT  27.856 40.555 28.144 42.669 ;
     RECT  33.256 38.379 33.544 42.669 ;
     RECT  38.656 40.043 38.944 42.669 ;
     RECT  44.056 41.643 44.344 42.669 ;
     RECT  49.456 41.067 49.744 42.669 ;
     RECT  54.856 38.699 55.144 42.669 ;
     RECT  60.256 35.819 60.544 42.669 ;
  END
END dsfd_svc_join
END LIBRARY
